VERSION 5.8 ;
BUSBITCHARS "[]" ;
DIVIDERCHAR "/" ;
UNITS
    DATABASE MICRONS 1000 ;
END UNITS

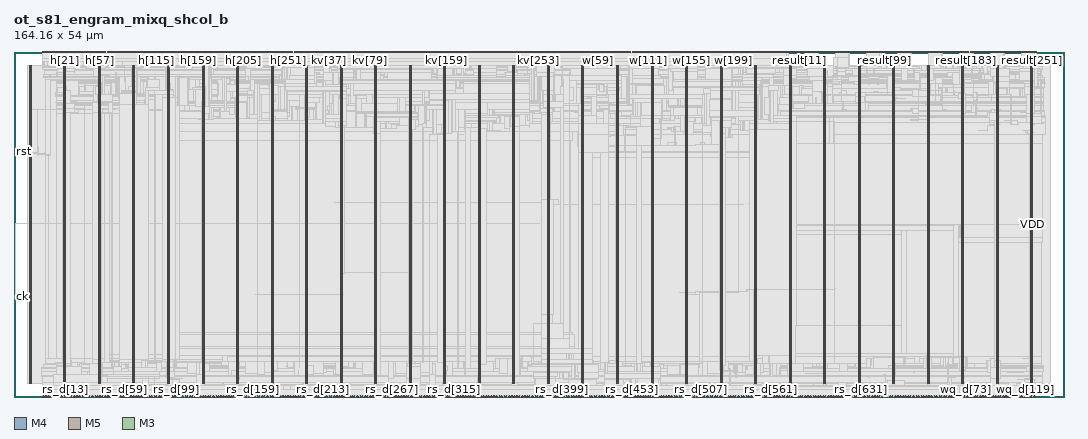
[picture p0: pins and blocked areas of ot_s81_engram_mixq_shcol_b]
MACRO ot_s81_engram_mixq_shcol_b
  FOREIGN ot_s81_engram_mixq_shcol_b 0 0 ;
  CLASS BLOCK ;
  SIZE 164.16 BY 54 ;
  PIN ck
    DIRECTION INPUT ;
    USE SIGNAL ;
    PORT
      LAYER M4 ;
        RECT  0 15.696 0.192 15.72 ;
    END
  END ck
  PIN h[0]
    DIRECTION OUTPUT ;
    USE SIGNAL ;
    PORT
      LAYER M5 ;
        RECT  4.848 53.808 4.872 54 ;
    END
  END h[0]
  PIN h[100]
    DIRECTION OUTPUT ;
    USE SIGNAL ;
    PORT
      LAYER M5 ;
        RECT  19.968 53.808 19.992 54 ;
    END
  END h[100]
  PIN h[101]
    DIRECTION OUTPUT ;
    USE SIGNAL ;
    PORT
      LAYER M3 ;
        RECT  20.124 53.856 20.142 54 ;
    END
  END h[101]
  PIN h[102]
    DIRECTION OUTPUT ;
    USE SIGNAL ;
    PORT
      LAYER M5 ;
        RECT  20.304 53.808 20.328 54 ;
    END
  END h[102]
  PIN h[103]
    DIRECTION OUTPUT ;
    USE SIGNAL ;
    PORT
      LAYER M3 ;
        RECT  20.448 53.856 20.466 54 ;
    END
  END h[103]
  PIN h[104]
    DIRECTION OUTPUT ;
    USE SIGNAL ;
    PORT
      LAYER M5 ;
        RECT  20.592 53.808 20.616 54 ;
    END
  END h[104]
  PIN h[105]
    DIRECTION OUTPUT ;
    USE SIGNAL ;
    PORT
      LAYER M3 ;
        RECT  20.736 53.856 20.754 54 ;
    END
  END h[105]
  PIN h[106]
    DIRECTION OUTPUT ;
    USE SIGNAL ;
    PORT
      LAYER M5 ;
        RECT  20.88 53.808 20.904 54 ;
    END
  END h[106]
  PIN h[107]
    DIRECTION OUTPUT ;
    USE SIGNAL ;
    PORT
      LAYER M3 ;
        RECT  21.06 53.856 21.078 54 ;
    END
  END h[107]
  PIN h[108]
    DIRECTION OUTPUT ;
    USE SIGNAL ;
    PORT
      LAYER M5 ;
        RECT  21.216 53.808 21.24 54 ;
    END
  END h[108]
  PIN h[109]
    DIRECTION OUTPUT ;
    USE SIGNAL ;
    PORT
      LAYER M3 ;
        RECT  21.348 53.856 21.366 54 ;
    END
  END h[109]
  PIN h[10]
    DIRECTION OUTPUT ;
    USE SIGNAL ;
    PORT
      LAYER M5 ;
        RECT  6.336 53.808 6.36 54 ;
    END
  END h[10]
  PIN h[110]
    DIRECTION OUTPUT ;
    USE SIGNAL ;
    PORT
      LAYER M5 ;
        RECT  21.504 53.808 21.528 54 ;
    END
  END h[110]
  PIN h[111]
    DIRECTION OUTPUT ;
    USE SIGNAL ;
    PORT
      LAYER M3 ;
        RECT  21.636 53.856 21.654 54 ;
    END
  END h[111]
  PIN h[112]
    DIRECTION OUTPUT ;
    USE SIGNAL ;
    PORT
      LAYER M5 ;
        RECT  21.792 53.808 21.816 54 ;
    END
  END h[112]
  PIN h[113]
    DIRECTION OUTPUT ;
    USE SIGNAL ;
    PORT
      LAYER M3 ;
        RECT  21.96 53.856 21.978 54 ;
    END
  END h[113]
  PIN h[114]
    DIRECTION OUTPUT ;
    USE SIGNAL ;
    PORT
      LAYER M5 ;
        RECT  22.08 53.808 22.104 54 ;
    END
  END h[114]
  PIN h[115]
    DIRECTION OUTPUT ;
    USE SIGNAL ;
    PORT
      LAYER M3 ;
        RECT  22.248 53.856 22.266 54 ;
    END
  END h[115]
  PIN h[116]
    DIRECTION OUTPUT ;
    USE SIGNAL ;
    PORT
      LAYER M5 ;
        RECT  22.416 53.808 22.44 54 ;
    END
  END h[116]
  PIN h[117]
    DIRECTION OUTPUT ;
    USE SIGNAL ;
    PORT
      LAYER M3 ;
        RECT  22.572 53.856 22.59 54 ;
    END
  END h[117]
  PIN h[118]
    DIRECTION OUTPUT ;
    USE SIGNAL ;
    PORT
      LAYER M5 ;
        RECT  22.704 53.808 22.728 54 ;
    END
  END h[118]
  PIN h[119]
    DIRECTION OUTPUT ;
    USE SIGNAL ;
    PORT
      LAYER M3 ;
        RECT  22.86 53.856 22.878 54 ;
    END
  END h[119]
  PIN h[11]
    DIRECTION OUTPUT ;
    USE SIGNAL ;
    PORT
      LAYER M3 ;
        RECT  6.516 53.856 6.534 54 ;
    END
  END h[11]
  PIN h[120]
    DIRECTION OUTPUT ;
    USE SIGNAL ;
    PORT
      LAYER M5 ;
        RECT  22.992 53.808 23.016 54 ;
    END
  END h[120]
  PIN h[121]
    DIRECTION OUTPUT ;
    USE SIGNAL ;
    PORT
      LAYER M3 ;
        RECT  23.148 53.856 23.166 54 ;
    END
  END h[121]
  PIN h[122]
    DIRECTION OUTPUT ;
    USE SIGNAL ;
    PORT
      LAYER M5 ;
        RECT  23.328 53.808 23.352 54 ;
    END
  END h[122]
  PIN h[123]
    DIRECTION OUTPUT ;
    USE SIGNAL ;
    PORT
      LAYER M3 ;
        RECT  23.472 53.856 23.49 54 ;
    END
  END h[123]
  PIN h[124]
    DIRECTION OUTPUT ;
    USE SIGNAL ;
    PORT
      LAYER M5 ;
        RECT  23.616 53.808 23.64 54 ;
    END
  END h[124]
  PIN h[125]
    DIRECTION OUTPUT ;
    USE SIGNAL ;
    PORT
      LAYER M3 ;
        RECT  23.76 53.856 23.778 54 ;
    END
  END h[125]
  PIN h[126]
    DIRECTION OUTPUT ;
    USE SIGNAL ;
    PORT
      LAYER M5 ;
        RECT  23.904 53.808 23.928 54 ;
    END
  END h[126]
  PIN h[127]
    DIRECTION OUTPUT ;
    USE SIGNAL ;
    PORT
      LAYER M3 ;
        RECT  24.084 53.856 24.102 54 ;
    END
  END h[127]
  PIN h[128]
    DIRECTION OUTPUT ;
    USE SIGNAL ;
    PORT
      LAYER M5 ;
        RECT  24.24 53.808 24.264 54 ;
    END
  END h[128]
  PIN h[129]
    DIRECTION OUTPUT ;
    USE SIGNAL ;
    PORT
      LAYER M3 ;
        RECT  24.372 53.856 24.39 54 ;
    END
  END h[129]
  PIN h[12]
    DIRECTION OUTPUT ;
    USE SIGNAL ;
    PORT
      LAYER M5 ;
        RECT  6.672 53.808 6.696 54 ;
    END
  END h[12]
  PIN h[130]
    DIRECTION OUTPUT ;
    USE SIGNAL ;
    PORT
      LAYER M5 ;
        RECT  24.528 53.808 24.552 54 ;
    END
  END h[130]
  PIN h[131]
    DIRECTION OUTPUT ;
    USE SIGNAL ;
    PORT
      LAYER M3 ;
        RECT  24.696 53.856 24.714 54 ;
    END
  END h[131]
  PIN h[132]
    DIRECTION OUTPUT ;
    USE SIGNAL ;
    PORT
      LAYER M5 ;
        RECT  24.816 53.808 24.84 54 ;
    END
  END h[132]
  PIN h[133]
    DIRECTION OUTPUT ;
    USE SIGNAL ;
    PORT
      LAYER M3 ;
        RECT  24.984 53.856 25.002 54 ;
    END
  END h[133]
  PIN h[134]
    DIRECTION OUTPUT ;
    USE SIGNAL ;
    PORT
      LAYER M5 ;
        RECT  25.152 53.808 25.176 54 ;
    END
  END h[134]
  PIN h[135]
    DIRECTION OUTPUT ;
    USE SIGNAL ;
    PORT
      LAYER M3 ;
        RECT  25.272 53.856 25.29 54 ;
    END
  END h[135]
  PIN h[136]
    DIRECTION OUTPUT ;
    USE SIGNAL ;
    PORT
      LAYER M5 ;
        RECT  25.44 53.808 25.464 54 ;
    END
  END h[136]
  PIN h[137]
    DIRECTION OUTPUT ;
    USE SIGNAL ;
    PORT
      LAYER M3 ;
        RECT  25.596 53.856 25.614 54 ;
    END
  END h[137]
  PIN h[138]
    DIRECTION OUTPUT ;
    USE SIGNAL ;
    PORT
      LAYER M5 ;
        RECT  25.728 53.808 25.752 54 ;
    END
  END h[138]
  PIN h[139]
    DIRECTION OUTPUT ;
    USE SIGNAL ;
    PORT
      LAYER M3 ;
        RECT  25.884 53.856 25.902 54 ;
    END
  END h[139]
  PIN h[13]
    DIRECTION OUTPUT ;
    USE SIGNAL ;
    PORT
      LAYER M3 ;
        RECT  6.804 53.856 6.822 54 ;
    END
  END h[13]
  PIN h[140]
    DIRECTION OUTPUT ;
    USE SIGNAL ;
    PORT
      LAYER M5 ;
        RECT  26.016 53.808 26.04 54 ;
    END
  END h[140]
  PIN h[141]
    DIRECTION OUTPUT ;
    USE SIGNAL ;
    PORT
      LAYER M3 ;
        RECT  26.208 53.856 26.226 54 ;
    END
  END h[141]
  PIN h[142]
    DIRECTION OUTPUT ;
    USE SIGNAL ;
    PORT
      LAYER M5 ;
        RECT  26.352 53.808 26.376 54 ;
    END
  END h[142]
  PIN h[143]
    DIRECTION OUTPUT ;
    USE SIGNAL ;
    PORT
      LAYER M3 ;
        RECT  26.496 53.856 26.514 54 ;
    END
  END h[143]
  PIN h[144]
    DIRECTION OUTPUT ;
    USE SIGNAL ;
    PORT
      LAYER M5 ;
        RECT  26.64 53.808 26.664 54 ;
    END
  END h[144]
  PIN h[145]
    DIRECTION OUTPUT ;
    USE SIGNAL ;
    PORT
      LAYER M3 ;
        RECT  26.784 53.856 26.802 54 ;
    END
  END h[145]
  PIN h[146]
    DIRECTION OUTPUT ;
    USE SIGNAL ;
    PORT
      LAYER M5 ;
        RECT  26.928 53.808 26.952 54 ;
    END
  END h[146]
  PIN h[147]
    DIRECTION OUTPUT ;
    USE SIGNAL ;
    PORT
      LAYER M3 ;
        RECT  27.108 53.856 27.126 54 ;
    END
  END h[147]
  PIN h[148]
    DIRECTION OUTPUT ;
    USE SIGNAL ;
    PORT
      LAYER M5 ;
        RECT  27.264 53.808 27.288 54 ;
    END
  END h[148]
  PIN h[149]
    DIRECTION OUTPUT ;
    USE SIGNAL ;
    PORT
      LAYER M3 ;
        RECT  27.396 53.856 27.414 54 ;
    END
  END h[149]
  PIN h[14]
    DIRECTION OUTPUT ;
    USE SIGNAL ;
    PORT
      LAYER M5 ;
        RECT  6.96 53.808 6.984 54 ;
    END
  END h[14]
  PIN h[150]
    DIRECTION OUTPUT ;
    USE SIGNAL ;
    PORT
      LAYER M5 ;
        RECT  27.552 53.808 27.576 54 ;
    END
  END h[150]
  PIN h[151]
    DIRECTION OUTPUT ;
    USE SIGNAL ;
    PORT
      LAYER M3 ;
        RECT  27.72 53.856 27.738 54 ;
    END
  END h[151]
  PIN h[152]
    DIRECTION OUTPUT ;
    USE SIGNAL ;
    PORT
      LAYER M5 ;
        RECT  27.84 53.808 27.864 54 ;
    END
  END h[152]
  PIN h[153]
    DIRECTION OUTPUT ;
    USE SIGNAL ;
    PORT
      LAYER M3 ;
        RECT  28.008 53.856 28.026 54 ;
    END
  END h[153]
  PIN h[154]
    DIRECTION OUTPUT ;
    USE SIGNAL ;
    PORT
      LAYER M5 ;
        RECT  28.176 53.808 28.2 54 ;
    END
  END h[154]
  PIN h[155]
    DIRECTION OUTPUT ;
    USE SIGNAL ;
    PORT
      LAYER M3 ;
        RECT  28.296 53.856 28.314 54 ;
    END
  END h[155]
  PIN h[156]
    DIRECTION OUTPUT ;
    USE SIGNAL ;
    PORT
      LAYER M5 ;
        RECT  28.464 53.808 28.488 54 ;
    END
  END h[156]
  PIN h[157]
    DIRECTION OUTPUT ;
    USE SIGNAL ;
    PORT
      LAYER M3 ;
        RECT  28.62 53.856 28.638 54 ;
    END
  END h[157]
  PIN h[158]
    DIRECTION OUTPUT ;
    USE SIGNAL ;
    PORT
      LAYER M5 ;
        RECT  28.752 53.808 28.776 54 ;
    END
  END h[158]
  PIN h[159]
    DIRECTION OUTPUT ;
    USE SIGNAL ;
    PORT
      LAYER M3 ;
        RECT  28.908 53.856 28.926 54 ;
    END
  END h[159]
  PIN h[15]
    DIRECTION OUTPUT ;
    USE SIGNAL ;
    PORT
      LAYER M3 ;
        RECT  7.128 53.856 7.146 54 ;
    END
  END h[15]
  PIN h[160]
    DIRECTION OUTPUT ;
    USE SIGNAL ;
    PORT
      LAYER M5 ;
        RECT  29.088 53.808 29.112 54 ;
    END
  END h[160]
  PIN h[161]
    DIRECTION OUTPUT ;
    USE SIGNAL ;
    PORT
      LAYER M3 ;
        RECT  29.232 53.856 29.25 54 ;
    END
  END h[161]
  PIN h[162]
    DIRECTION OUTPUT ;
    USE SIGNAL ;
    PORT
      LAYER M5 ;
        RECT  29.376 53.808 29.4 54 ;
    END
  END h[162]
  PIN h[163]
    DIRECTION OUTPUT ;
    USE SIGNAL ;
    PORT
      LAYER M3 ;
        RECT  29.52 53.856 29.538 54 ;
    END
  END h[163]
  PIN h[164]
    DIRECTION OUTPUT ;
    USE SIGNAL ;
    PORT
      LAYER M5 ;
        RECT  29.664 53.808 29.688 54 ;
    END
  END h[164]
  PIN h[165]
    DIRECTION OUTPUT ;
    USE SIGNAL ;
    PORT
      LAYER M3 ;
        RECT  29.844 53.856 29.862 54 ;
    END
  END h[165]
  PIN h[166]
    DIRECTION OUTPUT ;
    USE SIGNAL ;
    PORT
      LAYER M5 ;
        RECT  29.952 53.808 29.976 54 ;
    END
  END h[166]
  PIN h[167]
    DIRECTION OUTPUT ;
    USE SIGNAL ;
    PORT
      LAYER M3 ;
        RECT  30.132 53.856 30.15 54 ;
    END
  END h[167]
  PIN h[168]
    DIRECTION OUTPUT ;
    USE SIGNAL ;
    PORT
      LAYER M5 ;
        RECT  30.288 53.808 30.312 54 ;
    END
  END h[168]
  PIN h[169]
    DIRECTION OUTPUT ;
    USE SIGNAL ;
    PORT
      LAYER M3 ;
        RECT  30.42 53.856 30.438 54 ;
    END
  END h[169]
  PIN h[16]
    DIRECTION OUTPUT ;
    USE SIGNAL ;
    PORT
      LAYER M5 ;
        RECT  7.248 53.808 7.272 54 ;
    END
  END h[16]
  PIN h[170]
    DIRECTION OUTPUT ;
    USE SIGNAL ;
    PORT
      LAYER M5 ;
        RECT  30.576 53.808 30.6 54 ;
    END
  END h[170]
  PIN h[171]
    DIRECTION OUTPUT ;
    USE SIGNAL ;
    PORT
      LAYER M3 ;
        RECT  30.744 53.856 30.762 54 ;
    END
  END h[171]
  PIN h[172]
    DIRECTION OUTPUT ;
    USE SIGNAL ;
    PORT
      LAYER M5 ;
        RECT  30.864 53.808 30.888 54 ;
    END
  END h[172]
  PIN h[173]
    DIRECTION OUTPUT ;
    USE SIGNAL ;
    PORT
      LAYER M3 ;
        RECT  31.032 53.856 31.05 54 ;
    END
  END h[173]
  PIN h[174]
    DIRECTION OUTPUT ;
    USE SIGNAL ;
    PORT
      LAYER M5 ;
        RECT  31.2 53.808 31.224 54 ;
    END
  END h[174]
  PIN h[175]
    DIRECTION OUTPUT ;
    USE SIGNAL ;
    PORT
      LAYER M3 ;
        RECT  31.356 53.856 31.374 54 ;
    END
  END h[175]
  PIN h[176]
    DIRECTION OUTPUT ;
    USE SIGNAL ;
    PORT
      LAYER M5 ;
        RECT  31.488 53.808 31.512 54 ;
    END
  END h[176]
  PIN h[177]
    DIRECTION OUTPUT ;
    USE SIGNAL ;
    PORT
      LAYER M3 ;
        RECT  31.644 53.856 31.662 54 ;
    END
  END h[177]
  PIN h[178]
    DIRECTION OUTPUT ;
    USE SIGNAL ;
    PORT
      LAYER M5 ;
        RECT  31.776 53.808 31.8 54 ;
    END
  END h[178]
  PIN h[179]
    DIRECTION OUTPUT ;
    USE SIGNAL ;
    PORT
      LAYER M3 ;
        RECT  31.932 53.856 31.95 54 ;
    END
  END h[179]
  PIN h[17]
    DIRECTION OUTPUT ;
    USE SIGNAL ;
    PORT
      LAYER M3 ;
        RECT  7.416 53.856 7.434 54 ;
    END
  END h[17]
  PIN h[180]
    DIRECTION OUTPUT ;
    USE SIGNAL ;
    PORT
      LAYER M5 ;
        RECT  32.112 53.808 32.136 54 ;
    END
  END h[180]
  PIN h[181]
    DIRECTION OUTPUT ;
    USE SIGNAL ;
    PORT
      LAYER M3 ;
        RECT  32.256 53.856 32.274 54 ;
    END
  END h[181]
  PIN h[182]
    DIRECTION OUTPUT ;
    USE SIGNAL ;
    PORT
      LAYER M5 ;
        RECT  32.4 53.808 32.424 54 ;
    END
  END h[182]
  PIN h[183]
    DIRECTION OUTPUT ;
    USE SIGNAL ;
    PORT
      LAYER M3 ;
        RECT  32.544 53.856 32.562 54 ;
    END
  END h[183]
  PIN h[184]
    DIRECTION OUTPUT ;
    USE SIGNAL ;
    PORT
      LAYER M5 ;
        RECT  32.688 53.808 32.712 54 ;
    END
  END h[184]
  PIN h[185]
    DIRECTION OUTPUT ;
    USE SIGNAL ;
    PORT
      LAYER M3 ;
        RECT  32.868 53.856 32.886 54 ;
    END
  END h[185]
  PIN h[186]
    DIRECTION OUTPUT ;
    USE SIGNAL ;
    PORT
      LAYER M5 ;
        RECT  33.024 53.808 33.048 54 ;
    END
  END h[186]
  PIN h[187]
    DIRECTION OUTPUT ;
    USE SIGNAL ;
    PORT
      LAYER M3 ;
        RECT  33.156 53.856 33.174 54 ;
    END
  END h[187]
  PIN h[188]
    DIRECTION OUTPUT ;
    USE SIGNAL ;
    PORT
      LAYER M5 ;
        RECT  33.312 53.808 33.336 54 ;
    END
  END h[188]
  PIN h[189]
    DIRECTION OUTPUT ;
    USE SIGNAL ;
    PORT
      LAYER M3 ;
        RECT  33.444 53.856 33.462 54 ;
    END
  END h[189]
  PIN h[18]
    DIRECTION OUTPUT ;
    USE SIGNAL ;
    PORT
      LAYER M5 ;
        RECT  7.584 53.808 7.608 54 ;
    END
  END h[18]
  PIN h[190]
    DIRECTION OUTPUT ;
    USE SIGNAL ;
    PORT
      LAYER M5 ;
        RECT  33.6 53.808 33.624 54 ;
    END
  END h[190]
  PIN h[191]
    DIRECTION OUTPUT ;
    USE SIGNAL ;
    PORT
      LAYER M3 ;
        RECT  33.768 53.856 33.786 54 ;
    END
  END h[191]
  PIN h[192]
    DIRECTION OUTPUT ;
    USE SIGNAL ;
    PORT
      LAYER M5 ;
        RECT  33.936 53.808 33.96 54 ;
    END
  END h[192]
  PIN h[193]
    DIRECTION OUTPUT ;
    USE SIGNAL ;
    PORT
      LAYER M3 ;
        RECT  34.056 53.856 34.074 54 ;
    END
  END h[193]
  PIN h[194]
    DIRECTION OUTPUT ;
    USE SIGNAL ;
    PORT
      LAYER M5 ;
        RECT  34.224 53.808 34.248 54 ;
    END
  END h[194]
  PIN h[195]
    DIRECTION OUTPUT ;
    USE SIGNAL ;
    PORT
      LAYER M3 ;
        RECT  34.38 53.856 34.398 54 ;
    END
  END h[195]
  PIN h[196]
    DIRECTION OUTPUT ;
    USE SIGNAL ;
    PORT
      LAYER M5 ;
        RECT  34.512 53.808 34.536 54 ;
    END
  END h[196]
  PIN h[197]
    DIRECTION OUTPUT ;
    USE SIGNAL ;
    PORT
      LAYER M3 ;
        RECT  34.668 53.856 34.686 54 ;
    END
  END h[197]
  PIN h[198]
    DIRECTION OUTPUT ;
    USE SIGNAL ;
    PORT
      LAYER M5 ;
        RECT  34.8 53.808 34.824 54 ;
    END
  END h[198]
  PIN h[199]
    DIRECTION OUTPUT ;
    USE SIGNAL ;
    PORT
      LAYER M3 ;
        RECT  34.992 53.856 35.01 54 ;
    END
  END h[199]
  PIN h[19]
    DIRECTION OUTPUT ;
    USE SIGNAL ;
    PORT
      LAYER M3 ;
        RECT  7.704 53.856 7.722 54 ;
    END
  END h[19]
  PIN h[1]
    DIRECTION OUTPUT ;
    USE SIGNAL ;
    PORT
      LAYER M3 ;
        RECT  5.004 53.856 5.022 54 ;
    END
  END h[1]
  PIN h[200]
    DIRECTION OUTPUT ;
    USE SIGNAL ;
    PORT
      LAYER M5 ;
        RECT  35.136 53.808 35.16 54 ;
    END
  END h[200]
  PIN h[201]
    DIRECTION OUTPUT ;
    USE SIGNAL ;
    PORT
      LAYER M3 ;
        RECT  35.28 53.856 35.298 54 ;
    END
  END h[201]
  PIN h[202]
    DIRECTION OUTPUT ;
    USE SIGNAL ;
    PORT
      LAYER M5 ;
        RECT  35.424 53.808 35.448 54 ;
    END
  END h[202]
  PIN h[203]
    DIRECTION OUTPUT ;
    USE SIGNAL ;
    PORT
      LAYER M3 ;
        RECT  35.568 53.856 35.586 54 ;
    END
  END h[203]
  PIN h[204]
    DIRECTION OUTPUT ;
    USE SIGNAL ;
    PORT
      LAYER M5 ;
        RECT  35.712 53.808 35.736 54 ;
    END
  END h[204]
  PIN h[205]
    DIRECTION OUTPUT ;
    USE SIGNAL ;
    PORT
      LAYER M3 ;
        RECT  35.892 53.856 35.91 54 ;
    END
  END h[205]
  PIN h[206]
    DIRECTION OUTPUT ;
    USE SIGNAL ;
    PORT
      LAYER M5 ;
        RECT  36.048 53.808 36.072 54 ;
    END
  END h[206]
  PIN h[207]
    DIRECTION OUTPUT ;
    USE SIGNAL ;
    PORT
      LAYER M3 ;
        RECT  36.18 53.856 36.198 54 ;
    END
  END h[207]
  PIN h[208]
    DIRECTION OUTPUT ;
    USE SIGNAL ;
    PORT
      LAYER M5 ;
        RECT  36.336 53.808 36.36 54 ;
    END
  END h[208]
  PIN h[209]
    DIRECTION OUTPUT ;
    USE SIGNAL ;
    PORT
      LAYER M3 ;
        RECT  36.504 53.856 36.522 54 ;
    END
  END h[209]
  PIN h[20]
    DIRECTION OUTPUT ;
    USE SIGNAL ;
    PORT
      LAYER M5 ;
        RECT  7.872 53.808 7.896 54 ;
    END
  END h[20]
  PIN h[210]
    DIRECTION OUTPUT ;
    USE SIGNAL ;
    PORT
      LAYER M5 ;
        RECT  36.624 53.808 36.648 54 ;
    END
  END h[210]
  PIN h[211]
    DIRECTION OUTPUT ;
    USE SIGNAL ;
    PORT
      LAYER M3 ;
        RECT  36.792 53.856 36.81 54 ;
    END
  END h[211]
  PIN h[212]
    DIRECTION OUTPUT ;
    USE SIGNAL ;
    PORT
      LAYER M5 ;
        RECT  36.96 53.808 36.984 54 ;
    END
  END h[212]
  PIN h[213]
    DIRECTION OUTPUT ;
    USE SIGNAL ;
    PORT
      LAYER M3 ;
        RECT  37.08 53.856 37.098 54 ;
    END
  END h[213]
  PIN h[214]
    DIRECTION OUTPUT ;
    USE SIGNAL ;
    PORT
      LAYER M5 ;
        RECT  37.248 53.808 37.272 54 ;
    END
  END h[214]
  PIN h[215]
    DIRECTION OUTPUT ;
    USE SIGNAL ;
    PORT
      LAYER M3 ;
        RECT  37.404 53.856 37.422 54 ;
    END
  END h[215]
  PIN h[216]
    DIRECTION OUTPUT ;
    USE SIGNAL ;
    PORT
      LAYER M5 ;
        RECT  37.536 53.808 37.56 54 ;
    END
  END h[216]
  PIN h[217]
    DIRECTION OUTPUT ;
    USE SIGNAL ;
    PORT
      LAYER M3 ;
        RECT  37.692 53.856 37.71 54 ;
    END
  END h[217]
  PIN h[218]
    DIRECTION OUTPUT ;
    USE SIGNAL ;
    PORT
      LAYER M5 ;
        RECT  37.872 53.808 37.896 54 ;
    END
  END h[218]
  PIN h[219]
    DIRECTION OUTPUT ;
    USE SIGNAL ;
    PORT
      LAYER M3 ;
        RECT  38.016 53.856 38.034 54 ;
    END
  END h[219]
  PIN h[21]
    DIRECTION OUTPUT ;
    USE SIGNAL ;
    PORT
      LAYER M3 ;
        RECT  8.028 53.856 8.046 54 ;
    END
  END h[21]
  PIN h[220]
    DIRECTION OUTPUT ;
    USE SIGNAL ;
    PORT
      LAYER M5 ;
        RECT  38.16 53.808 38.184 54 ;
    END
  END h[220]
  PIN h[221]
    DIRECTION OUTPUT ;
    USE SIGNAL ;
    PORT
      LAYER M3 ;
        RECT  38.304 53.856 38.322 54 ;
    END
  END h[221]
  PIN h[222]
    DIRECTION OUTPUT ;
    USE SIGNAL ;
    PORT
      LAYER M5 ;
        RECT  38.448 53.808 38.472 54 ;
    END
  END h[222]
  PIN h[223]
    DIRECTION OUTPUT ;
    USE SIGNAL ;
    PORT
      LAYER M3 ;
        RECT  38.628 53.856 38.646 54 ;
    END
  END h[223]
  PIN h[224]
    DIRECTION OUTPUT ;
    USE SIGNAL ;
    PORT
      LAYER M5 ;
        RECT  38.736 53.808 38.76 54 ;
    END
  END h[224]
  PIN h[225]
    DIRECTION OUTPUT ;
    USE SIGNAL ;
    PORT
      LAYER M3 ;
        RECT  38.916 53.856 38.934 54 ;
    END
  END h[225]
  PIN h[226]
    DIRECTION OUTPUT ;
    USE SIGNAL ;
    PORT
      LAYER M5 ;
        RECT  39.072 53.808 39.096 54 ;
    END
  END h[226]
  PIN h[227]
    DIRECTION OUTPUT ;
    USE SIGNAL ;
    PORT
      LAYER M3 ;
        RECT  39.204 53.856 39.222 54 ;
    END
  END h[227]
  PIN h[228]
    DIRECTION OUTPUT ;
    USE SIGNAL ;
    PORT
      LAYER M5 ;
        RECT  39.36 53.808 39.384 54 ;
    END
  END h[228]
  PIN h[229]
    DIRECTION OUTPUT ;
    USE SIGNAL ;
    PORT
      LAYER M3 ;
        RECT  39.528 53.856 39.546 54 ;
    END
  END h[229]
  PIN h[22]
    DIRECTION OUTPUT ;
    USE SIGNAL ;
    PORT
      LAYER M5 ;
        RECT  8.16 53.808 8.184 54 ;
    END
  END h[22]
  PIN h[230]
    DIRECTION OUTPUT ;
    USE SIGNAL ;
    PORT
      LAYER M5 ;
        RECT  39.648 53.808 39.672 54 ;
    END
  END h[230]
  PIN h[231]
    DIRECTION OUTPUT ;
    USE SIGNAL ;
    PORT
      LAYER M3 ;
        RECT  39.816 53.856 39.834 54 ;
    END
  END h[231]
  PIN h[232]
    DIRECTION OUTPUT ;
    USE SIGNAL ;
    PORT
      LAYER M5 ;
        RECT  39.984 53.808 40.008 54 ;
    END
  END h[232]
  PIN h[233]
    DIRECTION OUTPUT ;
    USE SIGNAL ;
    PORT
      LAYER M3 ;
        RECT  40.14 53.856 40.158 54 ;
    END
  END h[233]
  PIN h[234]
    DIRECTION OUTPUT ;
    USE SIGNAL ;
    PORT
      LAYER M5 ;
        RECT  40.272 53.808 40.296 54 ;
    END
  END h[234]
  PIN h[235]
    DIRECTION OUTPUT ;
    USE SIGNAL ;
    PORT
      LAYER M3 ;
        RECT  40.428 53.856 40.446 54 ;
    END
  END h[235]
  PIN h[236]
    DIRECTION OUTPUT ;
    USE SIGNAL ;
    PORT
      LAYER M5 ;
        RECT  40.56 53.808 40.584 54 ;
    END
  END h[236]
  PIN h[237]
    DIRECTION OUTPUT ;
    USE SIGNAL ;
    PORT
      LAYER M3 ;
        RECT  40.716 53.856 40.734 54 ;
    END
  END h[237]
  PIN h[238]
    DIRECTION OUTPUT ;
    USE SIGNAL ;
    PORT
      LAYER M5 ;
        RECT  40.896 53.808 40.92 54 ;
    END
  END h[238]
  PIN h[239]
    DIRECTION OUTPUT ;
    USE SIGNAL ;
    PORT
      LAYER M3 ;
        RECT  41.04 53.856 41.058 54 ;
    END
  END h[239]
  PIN h[23]
    DIRECTION OUTPUT ;
    USE SIGNAL ;
    PORT
      LAYER M3 ;
        RECT  8.316 53.856 8.334 54 ;
    END
  END h[23]
  PIN h[240]
    DIRECTION OUTPUT ;
    USE SIGNAL ;
    PORT
      LAYER M5 ;
        RECT  41.184 53.808 41.208 54 ;
    END
  END h[240]
  PIN h[241]
    DIRECTION OUTPUT ;
    USE SIGNAL ;
    PORT
      LAYER M3 ;
        RECT  41.328 53.856 41.346 54 ;
    END
  END h[241]
  PIN h[242]
    DIRECTION OUTPUT ;
    USE SIGNAL ;
    PORT
      LAYER M5 ;
        RECT  41.472 53.808 41.496 54 ;
    END
  END h[242]
  PIN h[243]
    DIRECTION OUTPUT ;
    USE SIGNAL ;
    PORT
      LAYER M3 ;
        RECT  41.652 53.856 41.67 54 ;
    END
  END h[243]
  PIN h[244]
    DIRECTION OUTPUT ;
    USE SIGNAL ;
    PORT
      LAYER M5 ;
        RECT  41.808 53.808 41.832 54 ;
    END
  END h[244]
  PIN h[245]
    DIRECTION OUTPUT ;
    USE SIGNAL ;
    PORT
      LAYER M3 ;
        RECT  41.94 53.856 41.958 54 ;
    END
  END h[245]
  PIN h[246]
    DIRECTION OUTPUT ;
    USE SIGNAL ;
    PORT
      LAYER M5 ;
        RECT  42.096 53.808 42.12 54 ;
    END
  END h[246]
  PIN h[247]
    DIRECTION OUTPUT ;
    USE SIGNAL ;
    PORT
      LAYER M3 ;
        RECT  42.228 53.856 42.246 54 ;
    END
  END h[247]
  PIN h[248]
    DIRECTION OUTPUT ;
    USE SIGNAL ;
    PORT
      LAYER M5 ;
        RECT  42.384 53.808 42.408 54 ;
    END
  END h[248]
  PIN h[249]
    DIRECTION OUTPUT ;
    USE SIGNAL ;
    PORT
      LAYER M3 ;
        RECT  42.552 53.856 42.57 54 ;
    END
  END h[249]
  PIN h[24]
    DIRECTION OUTPUT ;
    USE SIGNAL ;
    PORT
      LAYER M5 ;
        RECT  8.496 53.808 8.52 54 ;
    END
  END h[24]
  PIN h[250]
    DIRECTION OUTPUT ;
    USE SIGNAL ;
    PORT
      LAYER M5 ;
        RECT  42.672 53.808 42.696 54 ;
    END
  END h[250]
  PIN h[251]
    DIRECTION OUTPUT ;
    USE SIGNAL ;
    PORT
      LAYER M3 ;
        RECT  42.84 53.856 42.858 54 ;
    END
  END h[251]
  PIN h[252]
    DIRECTION OUTPUT ;
    USE SIGNAL ;
    PORT
      LAYER M5 ;
        RECT  43.008 53.808 43.032 54 ;
    END
  END h[252]
  PIN h[253]
    DIRECTION OUTPUT ;
    USE SIGNAL ;
    PORT
      LAYER M3 ;
        RECT  43.164 53.856 43.182 54 ;
    END
  END h[253]
  PIN h[254]
    DIRECTION OUTPUT ;
    USE SIGNAL ;
    PORT
      LAYER M5 ;
        RECT  43.296 53.808 43.32 54 ;
    END
  END h[254]
  PIN h[255]
    DIRECTION OUTPUT ;
    USE SIGNAL ;
    PORT
      LAYER M3 ;
        RECT  43.452 53.856 43.47 54 ;
    END
  END h[255]
  PIN h[25]
    DIRECTION OUTPUT ;
    USE SIGNAL ;
    PORT
      LAYER M3 ;
        RECT  8.64 53.856 8.658 54 ;
    END
  END h[25]
  PIN h[26]
    DIRECTION OUTPUT ;
    USE SIGNAL ;
    PORT
      LAYER M5 ;
        RECT  8.784 53.808 8.808 54 ;
    END
  END h[26]
  PIN h[27]
    DIRECTION OUTPUT ;
    USE SIGNAL ;
    PORT
      LAYER M3 ;
        RECT  8.928 53.856 8.946 54 ;
    END
  END h[27]
  PIN h[28]
    DIRECTION OUTPUT ;
    USE SIGNAL ;
    PORT
      LAYER M5 ;
        RECT  9.072 53.808 9.096 54 ;
    END
  END h[28]
  PIN h[29]
    DIRECTION OUTPUT ;
    USE SIGNAL ;
    PORT
      LAYER M3 ;
        RECT  9.216 53.856 9.234 54 ;
    END
  END h[29]
  PIN h[2]
    DIRECTION OUTPUT ;
    USE SIGNAL ;
    PORT
      LAYER M5 ;
        RECT  5.136 53.808 5.16 54 ;
    END
  END h[2]
  PIN h[30]
    DIRECTION OUTPUT ;
    USE SIGNAL ;
    PORT
      LAYER M5 ;
        RECT  9.36 53.808 9.384 54 ;
    END
  END h[30]
  PIN h[31]
    DIRECTION OUTPUT ;
    USE SIGNAL ;
    PORT
      LAYER M3 ;
        RECT  9.54 53.856 9.558 54 ;
    END
  END h[31]
  PIN h[32]
    DIRECTION OUTPUT ;
    USE SIGNAL ;
    PORT
      LAYER M5 ;
        RECT  9.696 53.808 9.72 54 ;
    END
  END h[32]
  PIN h[33]
    DIRECTION OUTPUT ;
    USE SIGNAL ;
    PORT
      LAYER M3 ;
        RECT  9.828 53.856 9.846 54 ;
    END
  END h[33]
  PIN h[34]
    DIRECTION OUTPUT ;
    USE SIGNAL ;
    PORT
      LAYER M5 ;
        RECT  9.984 53.808 10.008 54 ;
    END
  END h[34]
  PIN h[35]
    DIRECTION OUTPUT ;
    USE SIGNAL ;
    PORT
      LAYER M3 ;
        RECT  10.152 53.856 10.17 54 ;
    END
  END h[35]
  PIN h[36]
    DIRECTION OUTPUT ;
    USE SIGNAL ;
    PORT
      LAYER M5 ;
        RECT  10.272 53.808 10.296 54 ;
    END
  END h[36]
  PIN h[37]
    DIRECTION OUTPUT ;
    USE SIGNAL ;
    PORT
      LAYER M3 ;
        RECT  10.44 53.856 10.458 54 ;
    END
  END h[37]
  PIN h[38]
    DIRECTION OUTPUT ;
    USE SIGNAL ;
    PORT
      LAYER M5 ;
        RECT  10.608 53.808 10.632 54 ;
    END
  END h[38]
  PIN h[39]
    DIRECTION OUTPUT ;
    USE SIGNAL ;
    PORT
      LAYER M3 ;
        RECT  10.764 53.856 10.782 54 ;
    END
  END h[39]
  PIN h[3]
    DIRECTION OUTPUT ;
    USE SIGNAL ;
    PORT
      LAYER M3 ;
        RECT  5.292 53.856 5.31 54 ;
    END
  END h[3]
  PIN h[40]
    DIRECTION OUTPUT ;
    USE SIGNAL ;
    PORT
      LAYER M5 ;
        RECT  10.896 53.808 10.92 54 ;
    END
  END h[40]
  PIN h[41]
    DIRECTION OUTPUT ;
    USE SIGNAL ;
    PORT
      LAYER M3 ;
        RECT  11.052 53.856 11.07 54 ;
    END
  END h[41]
  PIN h[42]
    DIRECTION OUTPUT ;
    USE SIGNAL ;
    PORT
      LAYER M5 ;
        RECT  11.184 53.808 11.208 54 ;
    END
  END h[42]
  PIN h[43]
    DIRECTION OUTPUT ;
    USE SIGNAL ;
    PORT
      LAYER M3 ;
        RECT  11.34 53.856 11.358 54 ;
    END
  END h[43]
  PIN h[44]
    DIRECTION OUTPUT ;
    USE SIGNAL ;
    PORT
      LAYER M5 ;
        RECT  11.52 53.808 11.544 54 ;
    END
  END h[44]
  PIN h[45]
    DIRECTION OUTPUT ;
    USE SIGNAL ;
    PORT
      LAYER M3 ;
        RECT  11.664 53.856 11.682 54 ;
    END
  END h[45]
  PIN h[46]
    DIRECTION OUTPUT ;
    USE SIGNAL ;
    PORT
      LAYER M5 ;
        RECT  11.808 53.808 11.832 54 ;
    END
  END h[46]
  PIN h[47]
    DIRECTION OUTPUT ;
    USE SIGNAL ;
    PORT
      LAYER M3 ;
        RECT  11.952 53.856 11.97 54 ;
    END
  END h[47]
  PIN h[48]
    DIRECTION OUTPUT ;
    USE SIGNAL ;
    PORT
      LAYER M5 ;
        RECT  12.096 53.808 12.12 54 ;
    END
  END h[48]
  PIN h[49]
    DIRECTION OUTPUT ;
    USE SIGNAL ;
    PORT
      LAYER M3 ;
        RECT  12.276 53.856 12.294 54 ;
    END
  END h[49]
  PIN h[4]
    DIRECTION OUTPUT ;
    USE SIGNAL ;
    PORT
      LAYER M5 ;
        RECT  5.424 53.808 5.448 54 ;
    END
  END h[4]
  PIN h[50]
    DIRECTION OUTPUT ;
    USE SIGNAL ;
    PORT
      LAYER M5 ;
        RECT  12.432 53.808 12.456 54 ;
    END
  END h[50]
  PIN h[51]
    DIRECTION OUTPUT ;
    USE SIGNAL ;
    PORT
      LAYER M3 ;
        RECT  12.564 53.856 12.582 54 ;
    END
  END h[51]
  PIN h[52]
    DIRECTION OUTPUT ;
    USE SIGNAL ;
    PORT
      LAYER M5 ;
        RECT  12.72 53.808 12.744 54 ;
    END
  END h[52]
  PIN h[53]
    DIRECTION OUTPUT ;
    USE SIGNAL ;
    PORT
      LAYER M3 ;
        RECT  12.852 53.856 12.87 54 ;
    END
  END h[53]
  PIN h[54]
    DIRECTION OUTPUT ;
    USE SIGNAL ;
    PORT
      LAYER M5 ;
        RECT  13.008 53.808 13.032 54 ;
    END
  END h[54]
  PIN h[55]
    DIRECTION OUTPUT ;
    USE SIGNAL ;
    PORT
      LAYER M3 ;
        RECT  13.176 53.856 13.194 54 ;
    END
  END h[55]
  PIN h[56]
    DIRECTION OUTPUT ;
    USE SIGNAL ;
    PORT
      LAYER M5 ;
        RECT  13.296 53.808 13.32 54 ;
    END
  END h[56]
  PIN h[57]
    DIRECTION OUTPUT ;
    USE SIGNAL ;
    PORT
      LAYER M3 ;
        RECT  13.464 53.856 13.482 54 ;
    END
  END h[57]
  PIN h[58]
    DIRECTION OUTPUT ;
    USE SIGNAL ;
    PORT
      LAYER M5 ;
        RECT  13.632 53.808 13.656 54 ;
    END
  END h[58]
  PIN h[59]
    DIRECTION OUTPUT ;
    USE SIGNAL ;
    PORT
      LAYER M3 ;
        RECT  13.788 53.856 13.806 54 ;
    END
  END h[59]
  PIN h[5]
    DIRECTION OUTPUT ;
    USE SIGNAL ;
    PORT
      LAYER M3 ;
        RECT  5.616 53.856 5.634 54 ;
    END
  END h[5]
  PIN h[60]
    DIRECTION OUTPUT ;
    USE SIGNAL ;
    PORT
      LAYER M5 ;
        RECT  13.92 53.808 13.944 54 ;
    END
  END h[60]
  PIN h[61]
    DIRECTION OUTPUT ;
    USE SIGNAL ;
    PORT
      LAYER M3 ;
        RECT  14.076 53.856 14.094 54 ;
    END
  END h[61]
  PIN h[62]
    DIRECTION OUTPUT ;
    USE SIGNAL ;
    PORT
      LAYER M5 ;
        RECT  14.208 53.808 14.232 54 ;
    END
  END h[62]
  PIN h[63]
    DIRECTION OUTPUT ;
    USE SIGNAL ;
    PORT
      LAYER M3 ;
        RECT  14.364 53.856 14.382 54 ;
    END
  END h[63]
  PIN h[64]
    DIRECTION OUTPUT ;
    USE SIGNAL ;
    PORT
      LAYER M5 ;
        RECT  14.544 53.808 14.568 54 ;
    END
  END h[64]
  PIN h[65]
    DIRECTION OUTPUT ;
    USE SIGNAL ;
    PORT
      LAYER M3 ;
        RECT  14.688 53.856 14.706 54 ;
    END
  END h[65]
  PIN h[66]
    DIRECTION OUTPUT ;
    USE SIGNAL ;
    PORT
      LAYER M5 ;
        RECT  14.832 53.808 14.856 54 ;
    END
  END h[66]
  PIN h[67]
    DIRECTION OUTPUT ;
    USE SIGNAL ;
    PORT
      LAYER M3 ;
        RECT  14.976 53.856 14.994 54 ;
    END
  END h[67]
  PIN h[68]
    DIRECTION OUTPUT ;
    USE SIGNAL ;
    PORT
      LAYER M5 ;
        RECT  15.12 53.808 15.144 54 ;
    END
  END h[68]
  PIN h[69]
    DIRECTION OUTPUT ;
    USE SIGNAL ;
    PORT
      LAYER M3 ;
        RECT  15.3 53.856 15.318 54 ;
    END
  END h[69]
  PIN h[6]
    DIRECTION OUTPUT ;
    USE SIGNAL ;
    PORT
      LAYER M5 ;
        RECT  5.76 53.808 5.784 54 ;
    END
  END h[6]
  PIN h[70]
    DIRECTION OUTPUT ;
    USE SIGNAL ;
    PORT
      LAYER M5 ;
        RECT  15.456 53.808 15.48 54 ;
    END
  END h[70]
  PIN h[71]
    DIRECTION OUTPUT ;
    USE SIGNAL ;
    PORT
      LAYER M3 ;
        RECT  15.588 53.856 15.606 54 ;
    END
  END h[71]
  PIN h[72]
    DIRECTION OUTPUT ;
    USE SIGNAL ;
    PORT
      LAYER M5 ;
        RECT  15.744 53.808 15.768 54 ;
    END
  END h[72]
  PIN h[73]
    DIRECTION OUTPUT ;
    USE SIGNAL ;
    PORT
      LAYER M3 ;
        RECT  15.912 53.856 15.93 54 ;
    END
  END h[73]
  PIN h[74]
    DIRECTION OUTPUT ;
    USE SIGNAL ;
    PORT
      LAYER M5 ;
        RECT  16.032 53.808 16.056 54 ;
    END
  END h[74]
  PIN h[75]
    DIRECTION OUTPUT ;
    USE SIGNAL ;
    PORT
      LAYER M3 ;
        RECT  16.2 53.856 16.218 54 ;
    END
  END h[75]
  PIN h[76]
    DIRECTION OUTPUT ;
    USE SIGNAL ;
    PORT
      LAYER M5 ;
        RECT  16.368 53.808 16.392 54 ;
    END
  END h[76]
  PIN h[77]
    DIRECTION OUTPUT ;
    USE SIGNAL ;
    PORT
      LAYER M3 ;
        RECT  16.488 53.856 16.506 54 ;
    END
  END h[77]
  PIN h[78]
    DIRECTION OUTPUT ;
    USE SIGNAL ;
    PORT
      LAYER M5 ;
        RECT  16.656 53.808 16.68 54 ;
    END
  END h[78]
  PIN h[79]
    DIRECTION OUTPUT ;
    USE SIGNAL ;
    PORT
      LAYER M3 ;
        RECT  16.812 53.856 16.83 54 ;
    END
  END h[79]
  PIN h[7]
    DIRECTION OUTPUT ;
    USE SIGNAL ;
    PORT
      LAYER M3 ;
        RECT  5.904 53.856 5.922 54 ;
    END
  END h[7]
  PIN h[80]
    DIRECTION OUTPUT ;
    USE SIGNAL ;
    PORT
      LAYER M5 ;
        RECT  16.944 53.808 16.968 54 ;
    END
  END h[80]
  PIN h[81]
    DIRECTION OUTPUT ;
    USE SIGNAL ;
    PORT
      LAYER M3 ;
        RECT  17.1 53.856 17.118 54 ;
    END
  END h[81]
  PIN h[82]
    DIRECTION OUTPUT ;
    USE SIGNAL ;
    PORT
      LAYER M5 ;
        RECT  17.232 53.808 17.256 54 ;
    END
  END h[82]
  PIN h[83]
    DIRECTION OUTPUT ;
    USE SIGNAL ;
    PORT
      LAYER M3 ;
        RECT  17.424 53.856 17.442 54 ;
    END
  END h[83]
  PIN h[84]
    DIRECTION OUTPUT ;
    USE SIGNAL ;
    PORT
      LAYER M5 ;
        RECT  17.568 53.808 17.592 54 ;
    END
  END h[84]
  PIN h[85]
    DIRECTION OUTPUT ;
    USE SIGNAL ;
    PORT
      LAYER M3 ;
        RECT  17.712 53.856 17.73 54 ;
    END
  END h[85]
  PIN h[86]
    DIRECTION OUTPUT ;
    USE SIGNAL ;
    PORT
      LAYER M5 ;
        RECT  17.856 53.808 17.88 54 ;
    END
  END h[86]
  PIN h[87]
    DIRECTION OUTPUT ;
    USE SIGNAL ;
    PORT
      LAYER M3 ;
        RECT  18 53.856 18.018 54 ;
    END
  END h[87]
  PIN h[88]
    DIRECTION OUTPUT ;
    USE SIGNAL ;
    PORT
      LAYER M5 ;
        RECT  18.144 53.808 18.168 54 ;
    END
  END h[88]
  PIN h[89]
    DIRECTION OUTPUT ;
    USE SIGNAL ;
    PORT
      LAYER M3 ;
        RECT  18.324 53.856 18.342 54 ;
    END
  END h[89]
  PIN h[8]
    DIRECTION OUTPUT ;
    USE SIGNAL ;
    PORT
      LAYER M5 ;
        RECT  6.048 53.808 6.072 54 ;
    END
  END h[8]
  PIN h[90]
    DIRECTION OUTPUT ;
    USE SIGNAL ;
    PORT
      LAYER M5 ;
        RECT  18.48 53.808 18.504 54 ;
    END
  END h[90]
  PIN h[91]
    DIRECTION OUTPUT ;
    USE SIGNAL ;
    PORT
      LAYER M3 ;
        RECT  18.612 53.856 18.63 54 ;
    END
  END h[91]
  PIN h[92]
    DIRECTION OUTPUT ;
    USE SIGNAL ;
    PORT
      LAYER M5 ;
        RECT  18.768 53.808 18.792 54 ;
    END
  END h[92]
  PIN h[93]
    DIRECTION OUTPUT ;
    USE SIGNAL ;
    PORT
      LAYER M3 ;
        RECT  18.936 53.856 18.954 54 ;
    END
  END h[93]
  PIN h[94]
    DIRECTION OUTPUT ;
    USE SIGNAL ;
    PORT
      LAYER M5 ;
        RECT  19.056 53.808 19.08 54 ;
    END
  END h[94]
  PIN h[95]
    DIRECTION OUTPUT ;
    USE SIGNAL ;
    PORT
      LAYER M3 ;
        RECT  19.224 53.856 19.242 54 ;
    END
  END h[95]
  PIN h[96]
    DIRECTION OUTPUT ;
    USE SIGNAL ;
    PORT
      LAYER M5 ;
        RECT  19.392 53.808 19.416 54 ;
    END
  END h[96]
  PIN h[97]
    DIRECTION OUTPUT ;
    USE SIGNAL ;
    PORT
      LAYER M3 ;
        RECT  19.512 53.856 19.53 54 ;
    END
  END h[97]
  PIN h[98]
    DIRECTION OUTPUT ;
    USE SIGNAL ;
    PORT
      LAYER M5 ;
        RECT  19.68 53.808 19.704 54 ;
    END
  END h[98]
  PIN h[99]
    DIRECTION OUTPUT ;
    USE SIGNAL ;
    PORT
      LAYER M3 ;
        RECT  19.836 53.856 19.854 54 ;
    END
  END h[99]
  PIN h[9]
    DIRECTION OUTPUT ;
    USE SIGNAL ;
    PORT
      LAYER M3 ;
        RECT  6.192 53.856 6.21 54 ;
    END
  END h[9]
  PIN iv
    DIRECTION OUTPUT ;
    USE SIGNAL ;
    PORT
      LAYER M5 ;
        RECT  4.512 53.808 4.536 54 ;
    END
  END iv
  PIN kv[0]
    DIRECTION OUTPUT ;
    USE SIGNAL ;
    PORT
      LAYER M5 ;
        RECT  43.584 53.808 43.608 54 ;
    END
  END kv[0]
  PIN kv[100]
    DIRECTION OUTPUT ;
    USE SIGNAL ;
    PORT
      LAYER M5 ;
        RECT  58.752 53.808 58.776 54 ;
    END
  END kv[100]
  PIN kv[101]
    DIRECTION OUTPUT ;
    USE SIGNAL ;
    PORT
      LAYER M3 ;
        RECT  58.896 53.856 58.914 54 ;
    END
  END kv[101]
  PIN kv[102]
    DIRECTION OUTPUT ;
    USE SIGNAL ;
    PORT
      LAYER M5 ;
        RECT  59.04 53.808 59.064 54 ;
    END
  END kv[102]
  PIN kv[103]
    DIRECTION OUTPUT ;
    USE SIGNAL ;
    PORT
      LAYER M3 ;
        RECT  59.22 53.856 59.238 54 ;
    END
  END kv[103]
  PIN kv[104]
    DIRECTION OUTPUT ;
    USE SIGNAL ;
    PORT
      LAYER M5 ;
        RECT  59.376 53.808 59.4 54 ;
    END
  END kv[104]
  PIN kv[105]
    DIRECTION OUTPUT ;
    USE SIGNAL ;
    PORT
      LAYER M3 ;
        RECT  59.508 53.856 59.526 54 ;
    END
  END kv[105]
  PIN kv[106]
    DIRECTION OUTPUT ;
    USE SIGNAL ;
    PORT
      LAYER M5 ;
        RECT  59.664 53.808 59.688 54 ;
    END
  END kv[106]
  PIN kv[107]
    DIRECTION OUTPUT ;
    USE SIGNAL ;
    PORT
      LAYER M3 ;
        RECT  59.796 53.856 59.814 54 ;
    END
  END kv[107]
  PIN kv[108]
    DIRECTION OUTPUT ;
    USE SIGNAL ;
    PORT
      LAYER M5 ;
        RECT  59.952 53.808 59.976 54 ;
    END
  END kv[108]
  PIN kv[109]
    DIRECTION OUTPUT ;
    USE SIGNAL ;
    PORT
      LAYER M3 ;
        RECT  60.12 53.856 60.138 54 ;
    END
  END kv[109]
  PIN kv[10]
    DIRECTION OUTPUT ;
    USE SIGNAL ;
    PORT
      LAYER M5 ;
        RECT  45.12 53.808 45.144 54 ;
    END
  END kv[10]
  PIN kv[110]
    DIRECTION OUTPUT ;
    USE SIGNAL ;
    PORT
      LAYER M5 ;
        RECT  60.24 53.808 60.264 54 ;
    END
  END kv[110]
  PIN kv[111]
    DIRECTION OUTPUT ;
    USE SIGNAL ;
    PORT
      LAYER M3 ;
        RECT  60.408 53.856 60.426 54 ;
    END
  END kv[111]
  PIN kv[112]
    DIRECTION OUTPUT ;
    USE SIGNAL ;
    PORT
      LAYER M5 ;
        RECT  60.576 53.808 60.6 54 ;
    END
  END kv[112]
  PIN kv[113]
    DIRECTION OUTPUT ;
    USE SIGNAL ;
    PORT
      LAYER M3 ;
        RECT  60.732 53.856 60.75 54 ;
    END
  END kv[113]
  PIN kv[114]
    DIRECTION OUTPUT ;
    USE SIGNAL ;
    PORT
      LAYER M5 ;
        RECT  60.864 53.808 60.888 54 ;
    END
  END kv[114]
  PIN kv[115]
    DIRECTION OUTPUT ;
    USE SIGNAL ;
    PORT
      LAYER M3 ;
        RECT  61.02 53.856 61.038 54 ;
    END
  END kv[115]
  PIN kv[116]
    DIRECTION OUTPUT ;
    USE SIGNAL ;
    PORT
      LAYER M5 ;
        RECT  61.152 53.808 61.176 54 ;
    END
  END kv[116]
  PIN kv[117]
    DIRECTION OUTPUT ;
    USE SIGNAL ;
    PORT
      LAYER M3 ;
        RECT  61.308 53.856 61.326 54 ;
    END
  END kv[117]
  PIN kv[118]
    DIRECTION OUTPUT ;
    USE SIGNAL ;
    PORT
      LAYER M5 ;
        RECT  61.488 53.808 61.512 54 ;
    END
  END kv[118]
  PIN kv[119]
    DIRECTION OUTPUT ;
    USE SIGNAL ;
    PORT
      LAYER M3 ;
        RECT  61.632 53.856 61.65 54 ;
    END
  END kv[119]
  PIN kv[11]
    DIRECTION OUTPUT ;
    USE SIGNAL ;
    PORT
      LAYER M3 ;
        RECT  45.288 53.856 45.306 54 ;
    END
  END kv[11]
  PIN kv[120]
    DIRECTION OUTPUT ;
    USE SIGNAL ;
    PORT
      LAYER M5 ;
        RECT  61.776 53.808 61.8 54 ;
    END
  END kv[120]
  PIN kv[121]
    DIRECTION OUTPUT ;
    USE SIGNAL ;
    PORT
      LAYER M3 ;
        RECT  61.92 53.856 61.938 54 ;
    END
  END kv[121]
  PIN kv[122]
    DIRECTION OUTPUT ;
    USE SIGNAL ;
    PORT
      LAYER M5 ;
        RECT  62.064 53.808 62.088 54 ;
    END
  END kv[122]
  PIN kv[123]
    DIRECTION OUTPUT ;
    USE SIGNAL ;
    PORT
      LAYER M3 ;
        RECT  62.244 53.856 62.262 54 ;
    END
  END kv[123]
  PIN kv[124]
    DIRECTION OUTPUT ;
    USE SIGNAL ;
    PORT
      LAYER M5 ;
        RECT  62.4 53.808 62.424 54 ;
    END
  END kv[124]
  PIN kv[125]
    DIRECTION OUTPUT ;
    USE SIGNAL ;
    PORT
      LAYER M3 ;
        RECT  62.532 53.856 62.55 54 ;
    END
  END kv[125]
  PIN kv[126]
    DIRECTION OUTPUT ;
    USE SIGNAL ;
    PORT
      LAYER M5 ;
        RECT  62.688 53.808 62.712 54 ;
    END
  END kv[126]
  PIN kv[127]
    DIRECTION OUTPUT ;
    USE SIGNAL ;
    PORT
      LAYER M3 ;
        RECT  62.856 53.856 62.874 54 ;
    END
  END kv[127]
  PIN kv[128]
    DIRECTION OUTPUT ;
    USE SIGNAL ;
    PORT
      LAYER M5 ;
        RECT  62.976 53.808 63 54 ;
    END
  END kv[128]
  PIN kv[129]
    DIRECTION OUTPUT ;
    USE SIGNAL ;
    PORT
      LAYER M3 ;
        RECT  63.144 53.856 63.162 54 ;
    END
  END kv[129]
  PIN kv[12]
    DIRECTION OUTPUT ;
    USE SIGNAL ;
    PORT
      LAYER M5 ;
        RECT  45.408 53.808 45.432 54 ;
    END
  END kv[12]
  PIN kv[130]
    DIRECTION OUTPUT ;
    USE SIGNAL ;
    PORT
      LAYER M5 ;
        RECT  63.312 53.808 63.336 54 ;
    END
  END kv[130]
  PIN kv[131]
    DIRECTION OUTPUT ;
    USE SIGNAL ;
    PORT
      LAYER M3 ;
        RECT  63.432 53.856 63.45 54 ;
    END
  END kv[131]
  PIN kv[132]
    DIRECTION OUTPUT ;
    USE SIGNAL ;
    PORT
      LAYER M5 ;
        RECT  63.6 53.808 63.624 54 ;
    END
  END kv[132]
  PIN kv[133]
    DIRECTION OUTPUT ;
    USE SIGNAL ;
    PORT
      LAYER M3 ;
        RECT  63.756 53.856 63.774 54 ;
    END
  END kv[133]
  PIN kv[134]
    DIRECTION OUTPUT ;
    USE SIGNAL ;
    PORT
      LAYER M5 ;
        RECT  63.888 53.808 63.912 54 ;
    END
  END kv[134]
  PIN kv[135]
    DIRECTION OUTPUT ;
    USE SIGNAL ;
    PORT
      LAYER M3 ;
        RECT  64.044 53.856 64.062 54 ;
    END
  END kv[135]
  PIN kv[136]
    DIRECTION OUTPUT ;
    USE SIGNAL ;
    PORT
      LAYER M5 ;
        RECT  64.176 53.808 64.2 54 ;
    END
  END kv[136]
  PIN kv[137]
    DIRECTION OUTPUT ;
    USE SIGNAL ;
    PORT
      LAYER M3 ;
        RECT  64.368 53.856 64.386 54 ;
    END
  END kv[137]
  PIN kv[138]
    DIRECTION OUTPUT ;
    USE SIGNAL ;
    PORT
      LAYER M5 ;
        RECT  64.512 53.808 64.536 54 ;
    END
  END kv[138]
  PIN kv[139]
    DIRECTION OUTPUT ;
    USE SIGNAL ;
    PORT
      LAYER M3 ;
        RECT  64.656 53.856 64.674 54 ;
    END
  END kv[139]
  PIN kv[13]
    DIRECTION OUTPUT ;
    USE SIGNAL ;
    PORT
      LAYER M3 ;
        RECT  45.576 53.856 45.594 54 ;
    END
  END kv[13]
  PIN kv[140]
    DIRECTION OUTPUT ;
    USE SIGNAL ;
    PORT
      LAYER M5 ;
        RECT  64.8 53.808 64.824 54 ;
    END
  END kv[140]
  PIN kv[141]
    DIRECTION OUTPUT ;
    USE SIGNAL ;
    PORT
      LAYER M3 ;
        RECT  64.944 53.856 64.962 54 ;
    END
  END kv[141]
  PIN kv[142]
    DIRECTION OUTPUT ;
    USE SIGNAL ;
    PORT
      LAYER M5 ;
        RECT  65.088 53.808 65.112 54 ;
    END
  END kv[142]
  PIN kv[143]
    DIRECTION OUTPUT ;
    USE SIGNAL ;
    PORT
      LAYER M3 ;
        RECT  65.268 53.856 65.286 54 ;
    END
  END kv[143]
  PIN kv[144]
    DIRECTION OUTPUT ;
    USE SIGNAL ;
    PORT
      LAYER M5 ;
        RECT  65.424 53.808 65.448 54 ;
    END
  END kv[144]
  PIN kv[145]
    DIRECTION OUTPUT ;
    USE SIGNAL ;
    PORT
      LAYER M3 ;
        RECT  65.556 53.856 65.574 54 ;
    END
  END kv[145]
  PIN kv[146]
    DIRECTION OUTPUT ;
    USE SIGNAL ;
    PORT
      LAYER M5 ;
        RECT  65.712 53.808 65.736 54 ;
    END
  END kv[146]
  PIN kv[147]
    DIRECTION OUTPUT ;
    USE SIGNAL ;
    PORT
      LAYER M3 ;
        RECT  65.88 53.856 65.898 54 ;
    END
  END kv[147]
  PIN kv[148]
    DIRECTION OUTPUT ;
    USE SIGNAL ;
    PORT
      LAYER M5 ;
        RECT  66 53.808 66.024 54 ;
    END
  END kv[148]
  PIN kv[149]
    DIRECTION OUTPUT ;
    USE SIGNAL ;
    PORT
      LAYER M3 ;
        RECT  66.168 53.856 66.186 54 ;
    END
  END kv[149]
  PIN kv[14]
    DIRECTION OUTPUT ;
    USE SIGNAL ;
    PORT
      LAYER M5 ;
        RECT  45.744 53.808 45.768 54 ;
    END
  END kv[14]
  PIN kv[150]
    DIRECTION OUTPUT ;
    USE SIGNAL ;
    PORT
      LAYER M5 ;
        RECT  66.336 53.808 66.36 54 ;
    END
  END kv[150]
  PIN kv[151]
    DIRECTION OUTPUT ;
    USE SIGNAL ;
    PORT
      LAYER M3 ;
        RECT  66.456 53.856 66.474 54 ;
    END
  END kv[151]
  PIN kv[152]
    DIRECTION OUTPUT ;
    USE SIGNAL ;
    PORT
      LAYER M5 ;
        RECT  66.624 53.808 66.648 54 ;
    END
  END kv[152]
  PIN kv[153]
    DIRECTION OUTPUT ;
    USE SIGNAL ;
    PORT
      LAYER M3 ;
        RECT  66.78 53.856 66.798 54 ;
    END
  END kv[153]
  PIN kv[154]
    DIRECTION OUTPUT ;
    USE SIGNAL ;
    PORT
      LAYER M5 ;
        RECT  66.912 53.808 66.936 54 ;
    END
  END kv[154]
  PIN kv[155]
    DIRECTION OUTPUT ;
    USE SIGNAL ;
    PORT
      LAYER M3 ;
        RECT  67.068 53.856 67.086 54 ;
    END
  END kv[155]
  PIN kv[156]
    DIRECTION OUTPUT ;
    USE SIGNAL ;
    PORT
      LAYER M5 ;
        RECT  67.248 53.808 67.272 54 ;
    END
  END kv[156]
  PIN kv[157]
    DIRECTION OUTPUT ;
    USE SIGNAL ;
    PORT
      LAYER M3 ;
        RECT  67.392 53.856 67.41 54 ;
    END
  END kv[157]
  PIN kv[158]
    DIRECTION OUTPUT ;
    USE SIGNAL ;
    PORT
      LAYER M5 ;
        RECT  67.536 53.808 67.56 54 ;
    END
  END kv[158]
  PIN kv[159]
    DIRECTION OUTPUT ;
    USE SIGNAL ;
    PORT
      LAYER M3 ;
        RECT  67.68 53.856 67.698 54 ;
    END
  END kv[159]
  PIN kv[15]
    DIRECTION OUTPUT ;
    USE SIGNAL ;
    PORT
      LAYER M3 ;
        RECT  45.864 53.856 45.882 54 ;
    END
  END kv[15]
  PIN kv[160]
    DIRECTION OUTPUT ;
    USE SIGNAL ;
    PORT
      LAYER M5 ;
        RECT  67.824 53.808 67.848 54 ;
    END
  END kv[160]
  PIN kv[161]
    DIRECTION OUTPUT ;
    USE SIGNAL ;
    PORT
      LAYER M3 ;
        RECT  68.004 53.856 68.022 54 ;
    END
  END kv[161]
  PIN kv[162]
    DIRECTION OUTPUT ;
    USE SIGNAL ;
    PORT
      LAYER M5 ;
        RECT  68.16 53.808 68.184 54 ;
    END
  END kv[162]
  PIN kv[163]
    DIRECTION OUTPUT ;
    USE SIGNAL ;
    PORT
      LAYER M3 ;
        RECT  68.292 53.856 68.31 54 ;
    END
  END kv[163]
  PIN kv[164]
    DIRECTION OUTPUT ;
    USE SIGNAL ;
    PORT
      LAYER M5 ;
        RECT  68.448 53.808 68.472 54 ;
    END
  END kv[164]
  PIN kv[165]
    DIRECTION OUTPUT ;
    USE SIGNAL ;
    PORT
      LAYER M3 ;
        RECT  68.58 53.856 68.598 54 ;
    END
  END kv[165]
  PIN kv[166]
    DIRECTION OUTPUT ;
    USE SIGNAL ;
    PORT
      LAYER M5 ;
        RECT  68.736 53.808 68.76 54 ;
    END
  END kv[166]
  PIN kv[167]
    DIRECTION OUTPUT ;
    USE SIGNAL ;
    PORT
      LAYER M3 ;
        RECT  68.904 53.856 68.922 54 ;
    END
  END kv[167]
  PIN kv[168]
    DIRECTION OUTPUT ;
    USE SIGNAL ;
    PORT
      LAYER M5 ;
        RECT  69.024 53.808 69.048 54 ;
    END
  END kv[168]
  PIN kv[169]
    DIRECTION OUTPUT ;
    USE SIGNAL ;
    PORT
      LAYER M3 ;
        RECT  69.192 53.856 69.21 54 ;
    END
  END kv[169]
  PIN kv[16]
    DIRECTION OUTPUT ;
    USE SIGNAL ;
    PORT
      LAYER M5 ;
        RECT  46.032 53.808 46.056 54 ;
    END
  END kv[16]
  PIN kv[170]
    DIRECTION OUTPUT ;
    USE SIGNAL ;
    PORT
      LAYER M5 ;
        RECT  69.36 53.808 69.384 54 ;
    END
  END kv[170]
  PIN kv[171]
    DIRECTION OUTPUT ;
    USE SIGNAL ;
    PORT
      LAYER M3 ;
        RECT  69.516 53.856 69.534 54 ;
    END
  END kv[171]
  PIN kv[172]
    DIRECTION OUTPUT ;
    USE SIGNAL ;
    PORT
      LAYER M5 ;
        RECT  69.648 53.808 69.672 54 ;
    END
  END kv[172]
  PIN kv[173]
    DIRECTION OUTPUT ;
    USE SIGNAL ;
    PORT
      LAYER M3 ;
        RECT  69.804 53.856 69.822 54 ;
    END
  END kv[173]
  PIN kv[174]
    DIRECTION OUTPUT ;
    USE SIGNAL ;
    PORT
      LAYER M5 ;
        RECT  69.936 53.808 69.96 54 ;
    END
  END kv[174]
  PIN kv[175]
    DIRECTION OUTPUT ;
    USE SIGNAL ;
    PORT
      LAYER M3 ;
        RECT  70.092 53.856 70.11 54 ;
    END
  END kv[175]
  PIN kv[176]
    DIRECTION OUTPUT ;
    USE SIGNAL ;
    PORT
      LAYER M5 ;
        RECT  70.272 53.808 70.296 54 ;
    END
  END kv[176]
  PIN kv[177]
    DIRECTION OUTPUT ;
    USE SIGNAL ;
    PORT
      LAYER M3 ;
        RECT  70.416 53.856 70.434 54 ;
    END
  END kv[177]
  PIN kv[178]
    DIRECTION OUTPUT ;
    USE SIGNAL ;
    PORT
      LAYER M5 ;
        RECT  70.56 53.808 70.584 54 ;
    END
  END kv[178]
  PIN kv[179]
    DIRECTION OUTPUT ;
    USE SIGNAL ;
    PORT
      LAYER M3 ;
        RECT  70.704 53.856 70.722 54 ;
    END
  END kv[179]
  PIN kv[17]
    DIRECTION OUTPUT ;
    USE SIGNAL ;
    PORT
      LAYER M3 ;
        RECT  46.188 53.856 46.206 54 ;
    END
  END kv[17]
  PIN kv[180]
    DIRECTION OUTPUT ;
    USE SIGNAL ;
    PORT
      LAYER M5 ;
        RECT  70.848 53.808 70.872 54 ;
    END
  END kv[180]
  PIN kv[181]
    DIRECTION OUTPUT ;
    USE SIGNAL ;
    PORT
      LAYER M3 ;
        RECT  71.028 53.856 71.046 54 ;
    END
  END kv[181]
  PIN kv[182]
    DIRECTION OUTPUT ;
    USE SIGNAL ;
    PORT
      LAYER M5 ;
        RECT  71.184 53.808 71.208 54 ;
    END
  END kv[182]
  PIN kv[183]
    DIRECTION OUTPUT ;
    USE SIGNAL ;
    PORT
      LAYER M3 ;
        RECT  71.316 53.856 71.334 54 ;
    END
  END kv[183]
  PIN kv[184]
    DIRECTION OUTPUT ;
    USE SIGNAL ;
    PORT
      LAYER M5 ;
        RECT  71.472 53.808 71.496 54 ;
    END
  END kv[184]
  PIN kv[185]
    DIRECTION OUTPUT ;
    USE SIGNAL ;
    PORT
      LAYER M3 ;
        RECT  71.64 53.856 71.658 54 ;
    END
  END kv[185]
  PIN kv[186]
    DIRECTION OUTPUT ;
    USE SIGNAL ;
    PORT
      LAYER M5 ;
        RECT  71.76 53.808 71.784 54 ;
    END
  END kv[186]
  PIN kv[187]
    DIRECTION OUTPUT ;
    USE SIGNAL ;
    PORT
      LAYER M3 ;
        RECT  71.928 53.856 71.946 54 ;
    END
  END kv[187]
  PIN kv[188]
    DIRECTION OUTPUT ;
    USE SIGNAL ;
    PORT
      LAYER M5 ;
        RECT  72.096 53.808 72.12 54 ;
    END
  END kv[188]
  PIN kv[189]
    DIRECTION OUTPUT ;
    USE SIGNAL ;
    PORT
      LAYER M3 ;
        RECT  72.216 53.856 72.234 54 ;
    END
  END kv[189]
  PIN kv[18]
    DIRECTION OUTPUT ;
    USE SIGNAL ;
    PORT
      LAYER M5 ;
        RECT  46.32 53.808 46.344 54 ;
    END
  END kv[18]
  PIN kv[190]
    DIRECTION OUTPUT ;
    USE SIGNAL ;
    PORT
      LAYER M5 ;
        RECT  72.384 53.808 72.408 54 ;
    END
  END kv[190]
  PIN kv[191]
    DIRECTION OUTPUT ;
    USE SIGNAL ;
    PORT
      LAYER M3 ;
        RECT  72.54 53.856 72.558 54 ;
    END
  END kv[191]
  PIN kv[192]
    DIRECTION OUTPUT ;
    USE SIGNAL ;
    PORT
      LAYER M5 ;
        RECT  72.672 53.808 72.696 54 ;
    END
  END kv[192]
  PIN kv[193]
    DIRECTION OUTPUT ;
    USE SIGNAL ;
    PORT
      LAYER M3 ;
        RECT  72.828 53.856 72.846 54 ;
    END
  END kv[193]
  PIN kv[194]
    DIRECTION OUTPUT ;
    USE SIGNAL ;
    PORT
      LAYER M5 ;
        RECT  72.96 53.808 72.984 54 ;
    END
  END kv[194]
  PIN kv[195]
    DIRECTION OUTPUT ;
    USE SIGNAL ;
    PORT
      LAYER M3 ;
        RECT  73.152 53.856 73.17 54 ;
    END
  END kv[195]
  PIN kv[196]
    DIRECTION OUTPUT ;
    USE SIGNAL ;
    PORT
      LAYER M5 ;
        RECT  73.296 53.808 73.32 54 ;
    END
  END kv[196]
  PIN kv[197]
    DIRECTION OUTPUT ;
    USE SIGNAL ;
    PORT
      LAYER M3 ;
        RECT  73.44 53.856 73.458 54 ;
    END
  END kv[197]
  PIN kv[198]
    DIRECTION OUTPUT ;
    USE SIGNAL ;
    PORT
      LAYER M5 ;
        RECT  73.584 53.808 73.608 54 ;
    END
  END kv[198]
  PIN kv[199]
    DIRECTION OUTPUT ;
    USE SIGNAL ;
    PORT
      LAYER M3 ;
        RECT  73.728 53.856 73.746 54 ;
    END
  END kv[199]
  PIN kv[19]
    DIRECTION OUTPUT ;
    USE SIGNAL ;
    PORT
      LAYER M3 ;
        RECT  46.476 53.856 46.494 54 ;
    END
  END kv[19]
  PIN kv[1]
    DIRECTION OUTPUT ;
    USE SIGNAL ;
    PORT
      LAYER M3 ;
        RECT  43.776 53.856 43.794 54 ;
    END
  END kv[1]
  PIN kv[200]
    DIRECTION OUTPUT ;
    USE SIGNAL ;
    PORT
      LAYER M5 ;
        RECT  73.872 53.808 73.896 54 ;
    END
  END kv[200]
  PIN kv[201]
    DIRECTION OUTPUT ;
    USE SIGNAL ;
    PORT
      LAYER M3 ;
        RECT  74.052 53.856 74.07 54 ;
    END
  END kv[201]
  PIN kv[202]
    DIRECTION OUTPUT ;
    USE SIGNAL ;
    PORT
      LAYER M5 ;
        RECT  74.208 53.808 74.232 54 ;
    END
  END kv[202]
  PIN kv[203]
    DIRECTION OUTPUT ;
    USE SIGNAL ;
    PORT
      LAYER M3 ;
        RECT  74.34 53.856 74.358 54 ;
    END
  END kv[203]
  PIN kv[204]
    DIRECTION OUTPUT ;
    USE SIGNAL ;
    PORT
      LAYER M5 ;
        RECT  74.496 53.808 74.52 54 ;
    END
  END kv[204]
  PIN kv[205]
    DIRECTION OUTPUT ;
    USE SIGNAL ;
    PORT
      LAYER M3 ;
        RECT  74.664 53.856 74.682 54 ;
    END
  END kv[205]
  PIN kv[206]
    DIRECTION OUTPUT ;
    USE SIGNAL ;
    PORT
      LAYER M5 ;
        RECT  74.784 53.808 74.808 54 ;
    END
  END kv[206]
  PIN kv[207]
    DIRECTION OUTPUT ;
    USE SIGNAL ;
    PORT
      LAYER M3 ;
        RECT  74.952 53.856 74.97 54 ;
    END
  END kv[207]
  PIN kv[208]
    DIRECTION OUTPUT ;
    USE SIGNAL ;
    PORT
      LAYER M5 ;
        RECT  75.12 53.808 75.144 54 ;
    END
  END kv[208]
  PIN kv[209]
    DIRECTION OUTPUT ;
    USE SIGNAL ;
    PORT
      LAYER M3 ;
        RECT  75.24 53.856 75.258 54 ;
    END
  END kv[209]
  PIN kv[20]
    DIRECTION OUTPUT ;
    USE SIGNAL ;
    PORT
      LAYER M5 ;
        RECT  46.656 53.808 46.68 54 ;
    END
  END kv[20]
  PIN kv[210]
    DIRECTION OUTPUT ;
    USE SIGNAL ;
    PORT
      LAYER M5 ;
        RECT  75.408 53.808 75.432 54 ;
    END
  END kv[210]
  PIN kv[211]
    DIRECTION OUTPUT ;
    USE SIGNAL ;
    PORT
      LAYER M3 ;
        RECT  75.564 53.856 75.582 54 ;
    END
  END kv[211]
  PIN kv[212]
    DIRECTION OUTPUT ;
    USE SIGNAL ;
    PORT
      LAYER M5 ;
        RECT  75.696 53.808 75.72 54 ;
    END
  END kv[212]
  PIN kv[213]
    DIRECTION OUTPUT ;
    USE SIGNAL ;
    PORT
      LAYER M3 ;
        RECT  75.852 53.856 75.87 54 ;
    END
  END kv[213]
  PIN kv[214]
    DIRECTION OUTPUT ;
    USE SIGNAL ;
    PORT
      LAYER M5 ;
        RECT  76.032 53.808 76.056 54 ;
    END
  END kv[214]
  PIN kv[215]
    DIRECTION OUTPUT ;
    USE SIGNAL ;
    PORT
      LAYER M3 ;
        RECT  76.176 53.856 76.194 54 ;
    END
  END kv[215]
  PIN kv[216]
    DIRECTION OUTPUT ;
    USE SIGNAL ;
    PORT
      LAYER M5 ;
        RECT  76.32 53.808 76.344 54 ;
    END
  END kv[216]
  PIN kv[217]
    DIRECTION OUTPUT ;
    USE SIGNAL ;
    PORT
      LAYER M3 ;
        RECT  76.464 53.856 76.482 54 ;
    END
  END kv[217]
  PIN kv[218]
    DIRECTION OUTPUT ;
    USE SIGNAL ;
    PORT
      LAYER M5 ;
        RECT  76.608 53.808 76.632 54 ;
    END
  END kv[218]
  PIN kv[219]
    DIRECTION OUTPUT ;
    USE SIGNAL ;
    PORT
      LAYER M3 ;
        RECT  76.788 53.856 76.806 54 ;
    END
  END kv[219]
  PIN kv[21]
    DIRECTION OUTPUT ;
    USE SIGNAL ;
    PORT
      LAYER M3 ;
        RECT  46.8 53.856 46.818 54 ;
    END
  END kv[21]
  PIN kv[220]
    DIRECTION OUTPUT ;
    USE SIGNAL ;
    PORT
      LAYER M5 ;
        RECT  76.896 53.808 76.92 54 ;
    END
  END kv[220]
  PIN kv[221]
    DIRECTION OUTPUT ;
    USE SIGNAL ;
    PORT
      LAYER M3 ;
        RECT  77.076 53.856 77.094 54 ;
    END
  END kv[221]
  PIN kv[222]
    DIRECTION OUTPUT ;
    USE SIGNAL ;
    PORT
      LAYER M5 ;
        RECT  77.232 53.808 77.256 54 ;
    END
  END kv[222]
  PIN kv[223]
    DIRECTION OUTPUT ;
    USE SIGNAL ;
    PORT
      LAYER M3 ;
        RECT  77.364 53.856 77.382 54 ;
    END
  END kv[223]
  PIN kv[224]
    DIRECTION OUTPUT ;
    USE SIGNAL ;
    PORT
      LAYER M5 ;
        RECT  77.52 53.808 77.544 54 ;
    END
  END kv[224]
  PIN kv[225]
    DIRECTION OUTPUT ;
    USE SIGNAL ;
    PORT
      LAYER M3 ;
        RECT  77.688 53.856 77.706 54 ;
    END
  END kv[225]
  PIN kv[226]
    DIRECTION OUTPUT ;
    USE SIGNAL ;
    PORT
      LAYER M5 ;
        RECT  77.808 53.808 77.832 54 ;
    END
  END kv[226]
  PIN kv[227]
    DIRECTION OUTPUT ;
    USE SIGNAL ;
    PORT
      LAYER M3 ;
        RECT  77.976 53.856 77.994 54 ;
    END
  END kv[227]
  PIN kv[228]
    DIRECTION OUTPUT ;
    USE SIGNAL ;
    PORT
      LAYER M5 ;
        RECT  78.144 53.808 78.168 54 ;
    END
  END kv[228]
  PIN kv[229]
    DIRECTION OUTPUT ;
    USE SIGNAL ;
    PORT
      LAYER M3 ;
        RECT  78.3 53.856 78.318 54 ;
    END
  END kv[229]
  PIN kv[22]
    DIRECTION OUTPUT ;
    USE SIGNAL ;
    PORT
      LAYER M5 ;
        RECT  46.944 53.808 46.968 54 ;
    END
  END kv[22]
  PIN kv[230]
    DIRECTION OUTPUT ;
    USE SIGNAL ;
    PORT
      LAYER M5 ;
        RECT  78.432 53.808 78.456 54 ;
    END
  END kv[230]
  PIN kv[231]
    DIRECTION OUTPUT ;
    USE SIGNAL ;
    PORT
      LAYER M3 ;
        RECT  78.588 53.856 78.606 54 ;
    END
  END kv[231]
  PIN kv[232]
    DIRECTION OUTPUT ;
    USE SIGNAL ;
    PORT
      LAYER M5 ;
        RECT  78.72 53.808 78.744 54 ;
    END
  END kv[232]
  PIN kv[233]
    DIRECTION OUTPUT ;
    USE SIGNAL ;
    PORT
      LAYER M3 ;
        RECT  78.876 53.856 78.894 54 ;
    END
  END kv[233]
  PIN kv[234]
    DIRECTION OUTPUT ;
    USE SIGNAL ;
    PORT
      LAYER M5 ;
        RECT  79.056 53.808 79.08 54 ;
    END
  END kv[234]
  PIN kv[235]
    DIRECTION OUTPUT ;
    USE SIGNAL ;
    PORT
      LAYER M3 ;
        RECT  79.2 53.856 79.218 54 ;
    END
  END kv[235]
  PIN kv[236]
    DIRECTION OUTPUT ;
    USE SIGNAL ;
    PORT
      LAYER M5 ;
        RECT  79.344 53.808 79.368 54 ;
    END
  END kv[236]
  PIN kv[237]
    DIRECTION OUTPUT ;
    USE SIGNAL ;
    PORT
      LAYER M3 ;
        RECT  79.488 53.856 79.506 54 ;
    END
  END kv[237]
  PIN kv[238]
    DIRECTION OUTPUT ;
    USE SIGNAL ;
    PORT
      LAYER M5 ;
        RECT  79.632 53.808 79.656 54 ;
    END
  END kv[238]
  PIN kv[239]
    DIRECTION OUTPUT ;
    USE SIGNAL ;
    PORT
      LAYER M3 ;
        RECT  79.812 53.856 79.83 54 ;
    END
  END kv[239]
  PIN kv[23]
    DIRECTION OUTPUT ;
    USE SIGNAL ;
    PORT
      LAYER M3 ;
        RECT  47.088 53.856 47.106 54 ;
    END
  END kv[23]
  PIN kv[240]
    DIRECTION OUTPUT ;
    USE SIGNAL ;
    PORT
      LAYER M5 ;
        RECT  79.968 53.808 79.992 54 ;
    END
  END kv[240]
  PIN kv[241]
    DIRECTION OUTPUT ;
    USE SIGNAL ;
    PORT
      LAYER M3 ;
        RECT  80.1 53.856 80.118 54 ;
    END
  END kv[241]
  PIN kv[242]
    DIRECTION OUTPUT ;
    USE SIGNAL ;
    PORT
      LAYER M5 ;
        RECT  80.256 53.808 80.28 54 ;
    END
  END kv[242]
  PIN kv[243]
    DIRECTION OUTPUT ;
    USE SIGNAL ;
    PORT
      LAYER M3 ;
        RECT  80.388 53.856 80.406 54 ;
    END
  END kv[243]
  PIN kv[244]
    DIRECTION OUTPUT ;
    USE SIGNAL ;
    PORT
      LAYER M5 ;
        RECT  80.544 53.808 80.568 54 ;
    END
  END kv[244]
  PIN kv[245]
    DIRECTION OUTPUT ;
    USE SIGNAL ;
    PORT
      LAYER M3 ;
        RECT  80.712 53.856 80.73 54 ;
    END
  END kv[245]
  PIN kv[246]
    DIRECTION OUTPUT ;
    USE SIGNAL ;
    PORT
      LAYER M5 ;
        RECT  80.88 53.808 80.904 54 ;
    END
  END kv[246]
  PIN kv[247]
    DIRECTION OUTPUT ;
    USE SIGNAL ;
    PORT
      LAYER M3 ;
        RECT  81 53.856 81.018 54 ;
    END
  END kv[247]
  PIN kv[248]
    DIRECTION OUTPUT ;
    USE SIGNAL ;
    PORT
      LAYER M5 ;
        RECT  81.168 53.808 81.192 54 ;
    END
  END kv[248]
  PIN kv[249]
    DIRECTION OUTPUT ;
    USE SIGNAL ;
    PORT
      LAYER M3 ;
        RECT  81.324 53.856 81.342 54 ;
    END
  END kv[249]
  PIN kv[24]
    DIRECTION OUTPUT ;
    USE SIGNAL ;
    PORT
      LAYER M5 ;
        RECT  47.232 53.808 47.256 54 ;
    END
  END kv[24]
  PIN kv[250]
    DIRECTION OUTPUT ;
    USE SIGNAL ;
    PORT
      LAYER M5 ;
        RECT  81.456 53.808 81.48 54 ;
    END
  END kv[250]
  PIN kv[251]
    DIRECTION OUTPUT ;
    USE SIGNAL ;
    PORT
      LAYER M3 ;
        RECT  81.612 53.856 81.63 54 ;
    END
  END kv[251]
  PIN kv[252]
    DIRECTION OUTPUT ;
    USE SIGNAL ;
    PORT
      LAYER M5 ;
        RECT  81.744 53.808 81.768 54 ;
    END
  END kv[252]
  PIN kv[253]
    DIRECTION OUTPUT ;
    USE SIGNAL ;
    PORT
      LAYER M3 ;
        RECT  81.936 53.856 81.954 54 ;
    END
  END kv[253]
  PIN kv[254]
    DIRECTION OUTPUT ;
    USE SIGNAL ;
    PORT
      LAYER M5 ;
        RECT  82.08 53.808 82.104 54 ;
    END
  END kv[254]
  PIN kv[255]
    DIRECTION OUTPUT ;
    USE SIGNAL ;
    PORT
      LAYER M3 ;
        RECT  82.224 53.856 82.242 54 ;
    END
  END kv[255]
  PIN kv[25]
    DIRECTION OUTPUT ;
    USE SIGNAL ;
    PORT
      LAYER M3 ;
        RECT  47.376 53.856 47.394 54 ;
    END
  END kv[25]
  PIN kv[26]
    DIRECTION OUTPUT ;
    USE SIGNAL ;
    PORT
      LAYER M5 ;
        RECT  47.52 53.808 47.544 54 ;
    END
  END kv[26]
  PIN kv[27]
    DIRECTION OUTPUT ;
    USE SIGNAL ;
    PORT
      LAYER M3 ;
        RECT  47.7 53.856 47.718 54 ;
    END
  END kv[27]
  PIN kv[28]
    DIRECTION OUTPUT ;
    USE SIGNAL ;
    PORT
      LAYER M5 ;
        RECT  47.856 53.808 47.88 54 ;
    END
  END kv[28]
  PIN kv[29]
    DIRECTION OUTPUT ;
    USE SIGNAL ;
    PORT
      LAYER M3 ;
        RECT  47.988 53.856 48.006 54 ;
    END
  END kv[29]
  PIN kv[2]
    DIRECTION OUTPUT ;
    USE SIGNAL ;
    PORT
      LAYER M5 ;
        RECT  43.92 53.808 43.944 54 ;
    END
  END kv[2]
  PIN kv[30]
    DIRECTION OUTPUT ;
    USE SIGNAL ;
    PORT
      LAYER M5 ;
        RECT  48.144 53.808 48.168 54 ;
    END
  END kv[30]
  PIN kv[31]
    DIRECTION OUTPUT ;
    USE SIGNAL ;
    PORT
      LAYER M3 ;
        RECT  48.312 53.856 48.33 54 ;
    END
  END kv[31]
  PIN kv[32]
    DIRECTION OUTPUT ;
    USE SIGNAL ;
    PORT
      LAYER M5 ;
        RECT  48.432 53.808 48.456 54 ;
    END
  END kv[32]
  PIN kv[33]
    DIRECTION OUTPUT ;
    USE SIGNAL ;
    PORT
      LAYER M3 ;
        RECT  48.6 53.856 48.618 54 ;
    END
  END kv[33]
  PIN kv[34]
    DIRECTION OUTPUT ;
    USE SIGNAL ;
    PORT
      LAYER M5 ;
        RECT  48.768 53.808 48.792 54 ;
    END
  END kv[34]
  PIN kv[35]
    DIRECTION OUTPUT ;
    USE SIGNAL ;
    PORT
      LAYER M3 ;
        RECT  48.924 53.856 48.942 54 ;
    END
  END kv[35]
  PIN kv[36]
    DIRECTION OUTPUT ;
    USE SIGNAL ;
    PORT
      LAYER M5 ;
        RECT  49.056 53.808 49.08 54 ;
    END
  END kv[36]
  PIN kv[37]
    DIRECTION OUTPUT ;
    USE SIGNAL ;
    PORT
      LAYER M3 ;
        RECT  49.212 53.856 49.23 54 ;
    END
  END kv[37]
  PIN kv[38]
    DIRECTION OUTPUT ;
    USE SIGNAL ;
    PORT
      LAYER M5 ;
        RECT  49.344 53.808 49.368 54 ;
    END
  END kv[38]
  PIN kv[39]
    DIRECTION OUTPUT ;
    USE SIGNAL ;
    PORT
      LAYER M3 ;
        RECT  49.5 53.856 49.518 54 ;
    END
  END kv[39]
  PIN kv[3]
    DIRECTION OUTPUT ;
    USE SIGNAL ;
    PORT
      LAYER M3 ;
        RECT  44.064 53.856 44.082 54 ;
    END
  END kv[3]
  PIN kv[40]
    DIRECTION OUTPUT ;
    USE SIGNAL ;
    PORT
      LAYER M5 ;
        RECT  49.68 53.808 49.704 54 ;
    END
  END kv[40]
  PIN kv[41]
    DIRECTION OUTPUT ;
    USE SIGNAL ;
    PORT
      LAYER M3 ;
        RECT  49.824 53.856 49.842 54 ;
    END
  END kv[41]
  PIN kv[42]
    DIRECTION OUTPUT ;
    USE SIGNAL ;
    PORT
      LAYER M5 ;
        RECT  49.968 53.808 49.992 54 ;
    END
  END kv[42]
  PIN kv[43]
    DIRECTION OUTPUT ;
    USE SIGNAL ;
    PORT
      LAYER M3 ;
        RECT  50.112 53.856 50.13 54 ;
    END
  END kv[43]
  PIN kv[44]
    DIRECTION OUTPUT ;
    USE SIGNAL ;
    PORT
      LAYER M5 ;
        RECT  50.256 53.808 50.28 54 ;
    END
  END kv[44]
  PIN kv[45]
    DIRECTION OUTPUT ;
    USE SIGNAL ;
    PORT
      LAYER M3 ;
        RECT  50.436 53.856 50.454 54 ;
    END
  END kv[45]
  PIN kv[46]
    DIRECTION OUTPUT ;
    USE SIGNAL ;
    PORT
      LAYER M5 ;
        RECT  50.592 53.808 50.616 54 ;
    END
  END kv[46]
  PIN kv[47]
    DIRECTION OUTPUT ;
    USE SIGNAL ;
    PORT
      LAYER M3 ;
        RECT  50.724 53.856 50.742 54 ;
    END
  END kv[47]
  PIN kv[48]
    DIRECTION OUTPUT ;
    USE SIGNAL ;
    PORT
      LAYER M5 ;
        RECT  50.88 53.808 50.904 54 ;
    END
  END kv[48]
  PIN kv[49]
    DIRECTION OUTPUT ;
    USE SIGNAL ;
    PORT
      LAYER M3 ;
        RECT  51.012 53.856 51.03 54 ;
    END
  END kv[49]
  PIN kv[4]
    DIRECTION OUTPUT ;
    USE SIGNAL ;
    PORT
      LAYER M5 ;
        RECT  44.208 53.808 44.232 54 ;
    END
  END kv[4]
  PIN kv[50]
    DIRECTION OUTPUT ;
    USE SIGNAL ;
    PORT
      LAYER M5 ;
        RECT  51.168 53.808 51.192 54 ;
    END
  END kv[50]
  PIN kv[51]
    DIRECTION OUTPUT ;
    USE SIGNAL ;
    PORT
      LAYER M3 ;
        RECT  51.336 53.856 51.354 54 ;
    END
  END kv[51]
  PIN kv[52]
    DIRECTION OUTPUT ;
    USE SIGNAL ;
    PORT
      LAYER M5 ;
        RECT  51.456 53.808 51.48 54 ;
    END
  END kv[52]
  PIN kv[53]
    DIRECTION OUTPUT ;
    USE SIGNAL ;
    PORT
      LAYER M3 ;
        RECT  51.624 53.856 51.642 54 ;
    END
  END kv[53]
  PIN kv[54]
    DIRECTION OUTPUT ;
    USE SIGNAL ;
    PORT
      LAYER M5 ;
        RECT  51.792 53.808 51.816 54 ;
    END
  END kv[54]
  PIN kv[55]
    DIRECTION OUTPUT ;
    USE SIGNAL ;
    PORT
      LAYER M3 ;
        RECT  51.948 53.856 51.966 54 ;
    END
  END kv[55]
  PIN kv[56]
    DIRECTION OUTPUT ;
    USE SIGNAL ;
    PORT
      LAYER M5 ;
        RECT  52.08 53.808 52.104 54 ;
    END
  END kv[56]
  PIN kv[57]
    DIRECTION OUTPUT ;
    USE SIGNAL ;
    PORT
      LAYER M3 ;
        RECT  52.236 53.856 52.254 54 ;
    END
  END kv[57]
  PIN kv[58]
    DIRECTION OUTPUT ;
    USE SIGNAL ;
    PORT
      LAYER M5 ;
        RECT  52.368 53.808 52.392 54 ;
    END
  END kv[58]
  PIN kv[59]
    DIRECTION OUTPUT ;
    USE SIGNAL ;
    PORT
      LAYER M3 ;
        RECT  52.524 53.856 52.542 54 ;
    END
  END kv[59]
  PIN kv[5]
    DIRECTION OUTPUT ;
    USE SIGNAL ;
    PORT
      LAYER M3 ;
        RECT  44.352 53.856 44.37 54 ;
    END
  END kv[5]
  PIN kv[60]
    DIRECTION OUTPUT ;
    USE SIGNAL ;
    PORT
      LAYER M5 ;
        RECT  52.704 53.808 52.728 54 ;
    END
  END kv[60]
  PIN kv[61]
    DIRECTION OUTPUT ;
    USE SIGNAL ;
    PORT
      LAYER M3 ;
        RECT  52.848 53.856 52.866 54 ;
    END
  END kv[61]
  PIN kv[62]
    DIRECTION OUTPUT ;
    USE SIGNAL ;
    PORT
      LAYER M5 ;
        RECT  52.992 53.808 53.016 54 ;
    END
  END kv[62]
  PIN kv[63]
    DIRECTION OUTPUT ;
    USE SIGNAL ;
    PORT
      LAYER M3 ;
        RECT  53.136 53.856 53.154 54 ;
    END
  END kv[63]
  PIN kv[64]
    DIRECTION OUTPUT ;
    USE SIGNAL ;
    PORT
      LAYER M5 ;
        RECT  53.28 53.808 53.304 54 ;
    END
  END kv[64]
  PIN kv[65]
    DIRECTION OUTPUT ;
    USE SIGNAL ;
    PORT
      LAYER M3 ;
        RECT  53.46 53.856 53.478 54 ;
    END
  END kv[65]
  PIN kv[66]
    DIRECTION OUTPUT ;
    USE SIGNAL ;
    PORT
      LAYER M5 ;
        RECT  53.616 53.808 53.64 54 ;
    END
  END kv[66]
  PIN kv[67]
    DIRECTION OUTPUT ;
    USE SIGNAL ;
    PORT
      LAYER M3 ;
        RECT  53.748 53.856 53.766 54 ;
    END
  END kv[67]
  PIN kv[68]
    DIRECTION OUTPUT ;
    USE SIGNAL ;
    PORT
      LAYER M5 ;
        RECT  53.904 53.808 53.928 54 ;
    END
  END kv[68]
  PIN kv[69]
    DIRECTION OUTPUT ;
    USE SIGNAL ;
    PORT
      LAYER M3 ;
        RECT  54.072 53.856 54.09 54 ;
    END
  END kv[69]
  PIN kv[6]
    DIRECTION OUTPUT ;
    USE SIGNAL ;
    PORT
      LAYER M5 ;
        RECT  44.496 53.808 44.52 54 ;
    END
  END kv[6]
  PIN kv[70]
    DIRECTION OUTPUT ;
    USE SIGNAL ;
    PORT
      LAYER M5 ;
        RECT  54.192 53.808 54.216 54 ;
    END
  END kv[70]
  PIN kv[71]
    DIRECTION OUTPUT ;
    USE SIGNAL ;
    PORT
      LAYER M3 ;
        RECT  54.36 53.856 54.378 54 ;
    END
  END kv[71]
  PIN kv[72]
    DIRECTION OUTPUT ;
    USE SIGNAL ;
    PORT
      LAYER M5 ;
        RECT  54.528 53.808 54.552 54 ;
    END
  END kv[72]
  PIN kv[73]
    DIRECTION OUTPUT ;
    USE SIGNAL ;
    PORT
      LAYER M3 ;
        RECT  54.648 53.856 54.666 54 ;
    END
  END kv[73]
  PIN kv[74]
    DIRECTION OUTPUT ;
    USE SIGNAL ;
    PORT
      LAYER M5 ;
        RECT  54.816 53.808 54.84 54 ;
    END
  END kv[74]
  PIN kv[75]
    DIRECTION OUTPUT ;
    USE SIGNAL ;
    PORT
      LAYER M3 ;
        RECT  54.972 53.856 54.99 54 ;
    END
  END kv[75]
  PIN kv[76]
    DIRECTION OUTPUT ;
    USE SIGNAL ;
    PORT
      LAYER M5 ;
        RECT  55.104 53.808 55.128 54 ;
    END
  END kv[76]
  PIN kv[77]
    DIRECTION OUTPUT ;
    USE SIGNAL ;
    PORT
      LAYER M3 ;
        RECT  55.26 53.856 55.278 54 ;
    END
  END kv[77]
  PIN kv[78]
    DIRECTION OUTPUT ;
    USE SIGNAL ;
    PORT
      LAYER M5 ;
        RECT  55.44 53.808 55.464 54 ;
    END
  END kv[78]
  PIN kv[79]
    DIRECTION OUTPUT ;
    USE SIGNAL ;
    PORT
      LAYER M3 ;
        RECT  55.584 53.856 55.602 54 ;
    END
  END kv[79]
  PIN kv[7]
    DIRECTION OUTPUT ;
    USE SIGNAL ;
    PORT
      LAYER M3 ;
        RECT  44.676 53.856 44.694 54 ;
    END
  END kv[7]
  PIN kv[80]
    DIRECTION OUTPUT ;
    USE SIGNAL ;
    PORT
      LAYER M5 ;
        RECT  55.728 53.808 55.752 54 ;
    END
  END kv[80]
  PIN kv[81]
    DIRECTION OUTPUT ;
    USE SIGNAL ;
    PORT
      LAYER M3 ;
        RECT  55.872 53.856 55.89 54 ;
    END
  END kv[81]
  PIN kv[82]
    DIRECTION OUTPUT ;
    USE SIGNAL ;
    PORT
      LAYER M5 ;
        RECT  56.016 53.808 56.04 54 ;
    END
  END kv[82]
  PIN kv[83]
    DIRECTION OUTPUT ;
    USE SIGNAL ;
    PORT
      LAYER M3 ;
        RECT  56.16 53.856 56.178 54 ;
    END
  END kv[83]
  PIN kv[84]
    DIRECTION OUTPUT ;
    USE SIGNAL ;
    PORT
      LAYER M5 ;
        RECT  56.304 53.808 56.328 54 ;
    END
  END kv[84]
  PIN kv[85]
    DIRECTION OUTPUT ;
    USE SIGNAL ;
    PORT
      LAYER M3 ;
        RECT  56.484 53.856 56.502 54 ;
    END
  END kv[85]
  PIN kv[86]
    DIRECTION OUTPUT ;
    USE SIGNAL ;
    PORT
      LAYER M5 ;
        RECT  56.64 53.808 56.664 54 ;
    END
  END kv[86]
  PIN kv[87]
    DIRECTION OUTPUT ;
    USE SIGNAL ;
    PORT
      LAYER M3 ;
        RECT  56.772 53.856 56.79 54 ;
    END
  END kv[87]
  PIN kv[88]
    DIRECTION OUTPUT ;
    USE SIGNAL ;
    PORT
      LAYER M5 ;
        RECT  56.928 53.808 56.952 54 ;
    END
  END kv[88]
  PIN kv[89]
    DIRECTION OUTPUT ;
    USE SIGNAL ;
    PORT
      LAYER M3 ;
        RECT  57.096 53.856 57.114 54 ;
    END
  END kv[89]
  PIN kv[8]
    DIRECTION OUTPUT ;
    USE SIGNAL ;
    PORT
      LAYER M5 ;
        RECT  44.832 53.808 44.856 54 ;
    END
  END kv[8]
  PIN kv[90]
    DIRECTION OUTPUT ;
    USE SIGNAL ;
    PORT
      LAYER M5 ;
        RECT  57.216 53.808 57.24 54 ;
    END
  END kv[90]
  PIN kv[91]
    DIRECTION OUTPUT ;
    USE SIGNAL ;
    PORT
      LAYER M3 ;
        RECT  57.384 53.856 57.402 54 ;
    END
  END kv[91]
  PIN kv[92]
    DIRECTION OUTPUT ;
    USE SIGNAL ;
    PORT
      LAYER M5 ;
        RECT  57.552 53.808 57.576 54 ;
    END
  END kv[92]
  PIN kv[93]
    DIRECTION OUTPUT ;
    USE SIGNAL ;
    PORT
      LAYER M3 ;
        RECT  57.708 53.856 57.726 54 ;
    END
  END kv[93]
  PIN kv[94]
    DIRECTION OUTPUT ;
    USE SIGNAL ;
    PORT
      LAYER M5 ;
        RECT  57.84 53.808 57.864 54 ;
    END
  END kv[94]
  PIN kv[95]
    DIRECTION OUTPUT ;
    USE SIGNAL ;
    PORT
      LAYER M3 ;
        RECT  57.996 53.856 58.014 54 ;
    END
  END kv[95]
  PIN kv[96]
    DIRECTION OUTPUT ;
    USE SIGNAL ;
    PORT
      LAYER M5 ;
        RECT  58.128 53.808 58.152 54 ;
    END
  END kv[96]
  PIN kv[97]
    DIRECTION OUTPUT ;
    USE SIGNAL ;
    PORT
      LAYER M3 ;
        RECT  58.284 53.856 58.302 54 ;
    END
  END kv[97]
  PIN kv[98]
    DIRECTION OUTPUT ;
    USE SIGNAL ;
    PORT
      LAYER M5 ;
        RECT  58.464 53.808 58.488 54 ;
    END
  END kv[98]
  PIN kv[99]
    DIRECTION OUTPUT ;
    USE SIGNAL ;
    PORT
      LAYER M3 ;
        RECT  58.608 53.856 58.626 54 ;
    END
  END kv[99]
  PIN kv[9]
    DIRECTION OUTPUT ;
    USE SIGNAL ;
    PORT
      LAYER M3 ;
        RECT  44.964 53.856 44.982 54 ;
    END
  END kv[9]
  PIN ov
    DIRECTION INPUT ;
    USE SIGNAL ;
    PORT
      LAYER M3 ;
        RECT  4.392 53.856 4.41 54 ;
    END
  END ov
  PIN ph
    DIRECTION OUTPUT ;
    USE SIGNAL ;
    PORT
      LAYER M3 ;
        RECT  4.68 53.856 4.698 54 ;
    END
  END ph
  PIN result[0]
    DIRECTION INPUT ;
    USE SIGNAL ;
    PORT
      LAYER M5 ;
        RECT  121.152 53.808 121.176 54 ;
    END
  END result[0]
  PIN result[100]
    DIRECTION INPUT ;
    USE SIGNAL ;
    PORT
      LAYER M5 ;
        RECT  136.272 53.808 136.296 54 ;
    END
  END result[100]
  PIN result[101]
    DIRECTION INPUT ;
    USE SIGNAL ;
    PORT
      LAYER M3 ;
        RECT  136.44 53.856 136.458 54 ;
    END
  END result[101]
  PIN result[102]
    DIRECTION INPUT ;
    USE SIGNAL ;
    PORT
      LAYER M5 ;
        RECT  136.56 53.808 136.584 54 ;
    END
  END result[102]
  PIN result[103]
    DIRECTION INPUT ;
    USE SIGNAL ;
    PORT
      LAYER M3 ;
        RECT  136.728 53.856 136.746 54 ;
    END
  END result[103]
  PIN result[104]
    DIRECTION INPUT ;
    USE SIGNAL ;
    PORT
      LAYER M5 ;
        RECT  136.896 53.808 136.92 54 ;
    END
  END result[104]
  PIN result[105]
    DIRECTION INPUT ;
    USE SIGNAL ;
    PORT
      LAYER M3 ;
        RECT  137.052 53.856 137.07 54 ;
    END
  END result[105]
  PIN result[106]
    DIRECTION INPUT ;
    USE SIGNAL ;
    PORT
      LAYER M5 ;
        RECT  137.184 53.808 137.208 54 ;
    END
  END result[106]
  PIN result[107]
    DIRECTION INPUT ;
    USE SIGNAL ;
    PORT
      LAYER M3 ;
        RECT  137.34 53.856 137.358 54 ;
    END
  END result[107]
  PIN result[108]
    DIRECTION INPUT ;
    USE SIGNAL ;
    PORT
      LAYER M5 ;
        RECT  137.472 53.808 137.496 54 ;
    END
  END result[108]
  PIN result[109]
    DIRECTION INPUT ;
    USE SIGNAL ;
    PORT
      LAYER M3 ;
        RECT  137.664 53.856 137.682 54 ;
    END
  END result[109]
  PIN result[10]
    DIRECTION INPUT ;
    USE SIGNAL ;
    PORT
      LAYER M5 ;
        RECT  122.64 53.808 122.664 54 ;
    END
  END result[10]
  PIN result[110]
    DIRECTION INPUT ;
    USE SIGNAL ;
    PORT
      LAYER M5 ;
        RECT  137.808 53.808 137.832 54 ;
    END
  END result[110]
  PIN result[111]
    DIRECTION INPUT ;
    USE SIGNAL ;
    PORT
      LAYER M3 ;
        RECT  137.952 53.856 137.97 54 ;
    END
  END result[111]
  PIN result[112]
    DIRECTION INPUT ;
    USE SIGNAL ;
    PORT
      LAYER M5 ;
        RECT  138.096 53.808 138.12 54 ;
    END
  END result[112]
  PIN result[113]
    DIRECTION INPUT ;
    USE SIGNAL ;
    PORT
      LAYER M3 ;
        RECT  138.24 53.856 138.258 54 ;
    END
  END result[113]
  PIN result[114]
    DIRECTION INPUT ;
    USE SIGNAL ;
    PORT
      LAYER M5 ;
        RECT  138.384 53.808 138.408 54 ;
    END
  END result[114]
  PIN result[115]
    DIRECTION INPUT ;
    USE SIGNAL ;
    PORT
      LAYER M3 ;
        RECT  138.564 53.856 138.582 54 ;
    END
  END result[115]
  PIN result[116]
    DIRECTION INPUT ;
    USE SIGNAL ;
    PORT
      LAYER M5 ;
        RECT  138.72 53.808 138.744 54 ;
    END
  END result[116]
  PIN result[117]
    DIRECTION INPUT ;
    USE SIGNAL ;
    PORT
      LAYER M3 ;
        RECT  138.852 53.856 138.87 54 ;
    END
  END result[117]
  PIN result[118]
    DIRECTION INPUT ;
    USE SIGNAL ;
    PORT
      LAYER M5 ;
        RECT  139.008 53.808 139.032 54 ;
    END
  END result[118]
  PIN result[119]
    DIRECTION INPUT ;
    USE SIGNAL ;
    PORT
      LAYER M3 ;
        RECT  139.176 53.856 139.194 54 ;
    END
  END result[119]
  PIN result[11]
    DIRECTION INPUT ;
    USE SIGNAL ;
    PORT
      LAYER M3 ;
        RECT  122.796 53.856 122.814 54 ;
    END
  END result[11]
  PIN result[120]
    DIRECTION INPUT ;
    USE SIGNAL ;
    PORT
      LAYER M5 ;
        RECT  139.296 53.808 139.32 54 ;
    END
  END result[120]
  PIN result[121]
    DIRECTION INPUT ;
    USE SIGNAL ;
    PORT
      LAYER M3 ;
        RECT  139.464 53.856 139.482 54 ;
    END
  END result[121]
  PIN result[122]
    DIRECTION INPUT ;
    USE SIGNAL ;
    PORT
      LAYER M5 ;
        RECT  139.632 53.808 139.656 54 ;
    END
  END result[122]
  PIN result[123]
    DIRECTION INPUT ;
    USE SIGNAL ;
    PORT
      LAYER M3 ;
        RECT  139.752 53.856 139.77 54 ;
    END
  END result[123]
  PIN result[124]
    DIRECTION INPUT ;
    USE SIGNAL ;
    PORT
      LAYER M5 ;
        RECT  139.92 53.808 139.944 54 ;
    END
  END result[124]
  PIN result[125]
    DIRECTION INPUT ;
    USE SIGNAL ;
    PORT
      LAYER M3 ;
        RECT  140.076 53.856 140.094 54 ;
    END
  END result[125]
  PIN result[126]
    DIRECTION INPUT ;
    USE SIGNAL ;
    PORT
      LAYER M5 ;
        RECT  140.208 53.808 140.232 54 ;
    END
  END result[126]
  PIN result[127]
    DIRECTION INPUT ;
    USE SIGNAL ;
    PORT
      LAYER M3 ;
        RECT  140.364 53.856 140.382 54 ;
    END
  END result[127]
  PIN result[128]
    DIRECTION INPUT ;
    USE SIGNAL ;
    PORT
      LAYER M5 ;
        RECT  140.544 53.808 140.568 54 ;
    END
  END result[128]
  PIN result[129]
    DIRECTION INPUT ;
    USE SIGNAL ;
    PORT
      LAYER M3 ;
        RECT  140.688 53.856 140.706 54 ;
    END
  END result[129]
  PIN result[12]
    DIRECTION INPUT ;
    USE SIGNAL ;
    PORT
      LAYER M5 ;
        RECT  122.976 53.808 123 54 ;
    END
  END result[12]
  PIN result[130]
    DIRECTION INPUT ;
    USE SIGNAL ;
    PORT
      LAYER M5 ;
        RECT  140.832 53.808 140.856 54 ;
    END
  END result[130]
  PIN result[131]
    DIRECTION INPUT ;
    USE SIGNAL ;
    PORT
      LAYER M3 ;
        RECT  140.976 53.856 140.994 54 ;
    END
  END result[131]
  PIN result[132]
    DIRECTION INPUT ;
    USE SIGNAL ;
    PORT
      LAYER M5 ;
        RECT  141.12 53.808 141.144 54 ;
    END
  END result[132]
  PIN result[133]
    DIRECTION INPUT ;
    USE SIGNAL ;
    PORT
      LAYER M3 ;
        RECT  141.264 53.856 141.282 54 ;
    END
  END result[133]
  PIN result[134]
    DIRECTION INPUT ;
    USE SIGNAL ;
    PORT
      LAYER M5 ;
        RECT  141.408 53.808 141.432 54 ;
    END
  END result[134]
  PIN result[135]
    DIRECTION INPUT ;
    USE SIGNAL ;
    PORT
      LAYER M3 ;
        RECT  141.588 53.856 141.606 54 ;
    END
  END result[135]
  PIN result[136]
    DIRECTION INPUT ;
    USE SIGNAL ;
    PORT
      LAYER M5 ;
        RECT  141.744 53.808 141.768 54 ;
    END
  END result[136]
  PIN result[137]
    DIRECTION INPUT ;
    USE SIGNAL ;
    PORT
      LAYER M3 ;
        RECT  141.876 53.856 141.894 54 ;
    END
  END result[137]
  PIN result[138]
    DIRECTION INPUT ;
    USE SIGNAL ;
    PORT
      LAYER M5 ;
        RECT  142.032 53.808 142.056 54 ;
    END
  END result[138]
  PIN result[139]
    DIRECTION INPUT ;
    USE SIGNAL ;
    PORT
      LAYER M3 ;
        RECT  142.2 53.856 142.218 54 ;
    END
  END result[139]
  PIN result[13]
    DIRECTION INPUT ;
    USE SIGNAL ;
    PORT
      LAYER M3 ;
        RECT  123.12 53.856 123.138 54 ;
    END
  END result[13]
  PIN result[140]
    DIRECTION INPUT ;
    USE SIGNAL ;
    PORT
      LAYER M5 ;
        RECT  142.32 53.808 142.344 54 ;
    END
  END result[140]
  PIN result[141]
    DIRECTION INPUT ;
    USE SIGNAL ;
    PORT
      LAYER M3 ;
        RECT  142.488 53.856 142.506 54 ;
    END
  END result[141]
  PIN result[142]
    DIRECTION INPUT ;
    USE SIGNAL ;
    PORT
      LAYER M5 ;
        RECT  142.656 53.808 142.68 54 ;
    END
  END result[142]
  PIN result[143]
    DIRECTION INPUT ;
    USE SIGNAL ;
    PORT
      LAYER M3 ;
        RECT  142.812 53.856 142.83 54 ;
    END
  END result[143]
  PIN result[144]
    DIRECTION INPUT ;
    USE SIGNAL ;
    PORT
      LAYER M5 ;
        RECT  142.944 53.808 142.968 54 ;
    END
  END result[144]
  PIN result[145]
    DIRECTION INPUT ;
    USE SIGNAL ;
    PORT
      LAYER M3 ;
        RECT  143.1 53.856 143.118 54 ;
    END
  END result[145]
  PIN result[146]
    DIRECTION INPUT ;
    USE SIGNAL ;
    PORT
      LAYER M5 ;
        RECT  143.232 53.808 143.256 54 ;
    END
  END result[146]
  PIN result[147]
    DIRECTION INPUT ;
    USE SIGNAL ;
    PORT
      LAYER M3 ;
        RECT  143.388 53.856 143.406 54 ;
    END
  END result[147]
  PIN result[148]
    DIRECTION INPUT ;
    USE SIGNAL ;
    PORT
      LAYER M5 ;
        RECT  143.568 53.808 143.592 54 ;
    END
  END result[148]
  PIN result[149]
    DIRECTION INPUT ;
    USE SIGNAL ;
    PORT
      LAYER M3 ;
        RECT  143.712 53.856 143.73 54 ;
    END
  END result[149]
  PIN result[14]
    DIRECTION INPUT ;
    USE SIGNAL ;
    PORT
      LAYER M5 ;
        RECT  123.264 53.808 123.288 54 ;
    END
  END result[14]
  PIN result[150]
    DIRECTION INPUT ;
    USE SIGNAL ;
    PORT
      LAYER M5 ;
        RECT  143.856 53.808 143.88 54 ;
    END
  END result[150]
  PIN result[151]
    DIRECTION INPUT ;
    USE SIGNAL ;
    PORT
      LAYER M3 ;
        RECT  144 53.856 144.018 54 ;
    END
  END result[151]
  PIN result[152]
    DIRECTION INPUT ;
    USE SIGNAL ;
    PORT
      LAYER M5 ;
        RECT  144.144 53.808 144.168 54 ;
    END
  END result[152]
  PIN result[153]
    DIRECTION INPUT ;
    USE SIGNAL ;
    PORT
      LAYER M3 ;
        RECT  144.324 53.856 144.342 54 ;
    END
  END result[153]
  PIN result[154]
    DIRECTION INPUT ;
    USE SIGNAL ;
    PORT
      LAYER M5 ;
        RECT  144.48 53.808 144.504 54 ;
    END
  END result[154]
  PIN result[155]
    DIRECTION INPUT ;
    USE SIGNAL ;
    PORT
      LAYER M3 ;
        RECT  144.612 53.856 144.63 54 ;
    END
  END result[155]
  PIN result[156]
    DIRECTION INPUT ;
    USE SIGNAL ;
    PORT
      LAYER M5 ;
        RECT  144.768 53.808 144.792 54 ;
    END
  END result[156]
  PIN result[157]
    DIRECTION INPUT ;
    USE SIGNAL ;
    PORT
      LAYER M3 ;
        RECT  144.9 53.856 144.918 54 ;
    END
  END result[157]
  PIN result[158]
    DIRECTION INPUT ;
    USE SIGNAL ;
    PORT
      LAYER M5 ;
        RECT  145.056 53.808 145.08 54 ;
    END
  END result[158]
  PIN result[159]
    DIRECTION INPUT ;
    USE SIGNAL ;
    PORT
      LAYER M3 ;
        RECT  145.224 53.856 145.242 54 ;
    END
  END result[159]
  PIN result[15]
    DIRECTION INPUT ;
    USE SIGNAL ;
    PORT
      LAYER M3 ;
        RECT  123.408 53.856 123.426 54 ;
    END
  END result[15]
  PIN result[160]
    DIRECTION INPUT ;
    USE SIGNAL ;
    PORT
      LAYER M5 ;
        RECT  145.344 53.808 145.368 54 ;
    END
  END result[160]
  PIN result[161]
    DIRECTION INPUT ;
    USE SIGNAL ;
    PORT
      LAYER M3 ;
        RECT  145.512 53.856 145.53 54 ;
    END
  END result[161]
  PIN result[162]
    DIRECTION INPUT ;
    USE SIGNAL ;
    PORT
      LAYER M5 ;
        RECT  145.68 53.808 145.704 54 ;
    END
  END result[162]
  PIN result[163]
    DIRECTION INPUT ;
    USE SIGNAL ;
    PORT
      LAYER M3 ;
        RECT  145.836 53.856 145.854 54 ;
    END
  END result[163]
  PIN result[164]
    DIRECTION INPUT ;
    USE SIGNAL ;
    PORT
      LAYER M5 ;
        RECT  145.968 53.808 145.992 54 ;
    END
  END result[164]
  PIN result[165]
    DIRECTION INPUT ;
    USE SIGNAL ;
    PORT
      LAYER M3 ;
        RECT  146.124 53.856 146.142 54 ;
    END
  END result[165]
  PIN result[166]
    DIRECTION INPUT ;
    USE SIGNAL ;
    PORT
      LAYER M5 ;
        RECT  146.256 53.808 146.28 54 ;
    END
  END result[166]
  PIN result[167]
    DIRECTION INPUT ;
    USE SIGNAL ;
    PORT
      LAYER M3 ;
        RECT  146.412 53.856 146.43 54 ;
    END
  END result[167]
  PIN result[168]
    DIRECTION INPUT ;
    USE SIGNAL ;
    PORT
      LAYER M5 ;
        RECT  146.592 53.808 146.616 54 ;
    END
  END result[168]
  PIN result[169]
    DIRECTION INPUT ;
    USE SIGNAL ;
    PORT
      LAYER M3 ;
        RECT  146.736 53.856 146.754 54 ;
    END
  END result[169]
  PIN result[16]
    DIRECTION INPUT ;
    USE SIGNAL ;
    PORT
      LAYER M5 ;
        RECT  123.552 53.808 123.576 54 ;
    END
  END result[16]
  PIN result[170]
    DIRECTION INPUT ;
    USE SIGNAL ;
    PORT
      LAYER M5 ;
        RECT  146.88 53.808 146.904 54 ;
    END
  END result[170]
  PIN result[171]
    DIRECTION INPUT ;
    USE SIGNAL ;
    PORT
      LAYER M3 ;
        RECT  147.024 53.856 147.042 54 ;
    END
  END result[171]
  PIN result[172]
    DIRECTION INPUT ;
    USE SIGNAL ;
    PORT
      LAYER M5 ;
        RECT  147.168 53.808 147.192 54 ;
    END
  END result[172]
  PIN result[173]
    DIRECTION INPUT ;
    USE SIGNAL ;
    PORT
      LAYER M3 ;
        RECT  147.348 53.856 147.366 54 ;
    END
  END result[173]
  PIN result[174]
    DIRECTION INPUT ;
    USE SIGNAL ;
    PORT
      LAYER M5 ;
        RECT  147.504 53.808 147.528 54 ;
    END
  END result[174]
  PIN result[175]
    DIRECTION INPUT ;
    USE SIGNAL ;
    PORT
      LAYER M3 ;
        RECT  147.636 53.856 147.654 54 ;
    END
  END result[175]
  PIN result[176]
    DIRECTION INPUT ;
    USE SIGNAL ;
    PORT
      LAYER M5 ;
        RECT  147.792 53.808 147.816 54 ;
    END
  END result[176]
  PIN result[177]
    DIRECTION INPUT ;
    USE SIGNAL ;
    PORT
      LAYER M3 ;
        RECT  147.96 53.856 147.978 54 ;
    END
  END result[177]
  PIN result[178]
    DIRECTION INPUT ;
    USE SIGNAL ;
    PORT
      LAYER M5 ;
        RECT  148.08 53.808 148.104 54 ;
    END
  END result[178]
  PIN result[179]
    DIRECTION INPUT ;
    USE SIGNAL ;
    PORT
      LAYER M3 ;
        RECT  148.248 53.856 148.266 54 ;
    END
  END result[179]
  PIN result[17]
    DIRECTION INPUT ;
    USE SIGNAL ;
    PORT
      LAYER M3 ;
        RECT  123.732 53.856 123.75 54 ;
    END
  END result[17]
  PIN result[180]
    DIRECTION INPUT ;
    USE SIGNAL ;
    PORT
      LAYER M5 ;
        RECT  148.416 53.808 148.44 54 ;
    END
  END result[180]
  PIN result[181]
    DIRECTION INPUT ;
    USE SIGNAL ;
    PORT
      LAYER M3 ;
        RECT  148.536 53.856 148.554 54 ;
    END
  END result[181]
  PIN result[182]
    DIRECTION INPUT ;
    USE SIGNAL ;
    PORT
      LAYER M5 ;
        RECT  148.704 53.808 148.728 54 ;
    END
  END result[182]
  PIN result[183]
    DIRECTION INPUT ;
    USE SIGNAL ;
    PORT
      LAYER M3 ;
        RECT  148.86 53.856 148.878 54 ;
    END
  END result[183]
  PIN result[184]
    DIRECTION INPUT ;
    USE SIGNAL ;
    PORT
      LAYER M5 ;
        RECT  148.992 53.808 149.016 54 ;
    END
  END result[184]
  PIN result[185]
    DIRECTION INPUT ;
    USE SIGNAL ;
    PORT
      LAYER M3 ;
        RECT  149.148 53.856 149.166 54 ;
    END
  END result[185]
  PIN result[186]
    DIRECTION INPUT ;
    USE SIGNAL ;
    PORT
      LAYER M5 ;
        RECT  149.28 53.808 149.304 54 ;
    END
  END result[186]
  PIN result[187]
    DIRECTION INPUT ;
    USE SIGNAL ;
    PORT
      LAYER M3 ;
        RECT  149.472 53.856 149.49 54 ;
    END
  END result[187]
  PIN result[188]
    DIRECTION INPUT ;
    USE SIGNAL ;
    PORT
      LAYER M5 ;
        RECT  149.616 53.808 149.64 54 ;
    END
  END result[188]
  PIN result[189]
    DIRECTION INPUT ;
    USE SIGNAL ;
    PORT
      LAYER M3 ;
        RECT  149.76 53.856 149.778 54 ;
    END
  END result[189]
  PIN result[18]
    DIRECTION INPUT ;
    USE SIGNAL ;
    PORT
      LAYER M5 ;
        RECT  123.84 53.808 123.864 54 ;
    END
  END result[18]
  PIN result[190]
    DIRECTION INPUT ;
    USE SIGNAL ;
    PORT
      LAYER M5 ;
        RECT  149.904 53.808 149.928 54 ;
    END
  END result[190]
  PIN result[191]
    DIRECTION INPUT ;
    USE SIGNAL ;
    PORT
      LAYER M3 ;
        RECT  150.048 53.856 150.066 54 ;
    END
  END result[191]
  PIN result[192]
    DIRECTION INPUT ;
    USE SIGNAL ;
    PORT
      LAYER M5 ;
        RECT  150.192 53.808 150.216 54 ;
    END
  END result[192]
  PIN result[193]
    DIRECTION INPUT ;
    USE SIGNAL ;
    PORT
      LAYER M3 ;
        RECT  150.372 53.856 150.39 54 ;
    END
  END result[193]
  PIN result[194]
    DIRECTION INPUT ;
    USE SIGNAL ;
    PORT
      LAYER M5 ;
        RECT  150.528 53.808 150.552 54 ;
    END
  END result[194]
  PIN result[195]
    DIRECTION INPUT ;
    USE SIGNAL ;
    PORT
      LAYER M3 ;
        RECT  150.66 53.856 150.678 54 ;
    END
  END result[195]
  PIN result[196]
    DIRECTION INPUT ;
    USE SIGNAL ;
    PORT
      LAYER M5 ;
        RECT  150.816 53.808 150.84 54 ;
    END
  END result[196]
  PIN result[197]
    DIRECTION INPUT ;
    USE SIGNAL ;
    PORT
      LAYER M3 ;
        RECT  150.984 53.856 151.002 54 ;
    END
  END result[197]
  PIN result[198]
    DIRECTION INPUT ;
    USE SIGNAL ;
    PORT
      LAYER M5 ;
        RECT  151.104 53.808 151.128 54 ;
    END
  END result[198]
  PIN result[199]
    DIRECTION INPUT ;
    USE SIGNAL ;
    PORT
      LAYER M3 ;
        RECT  151.272 53.856 151.29 54 ;
    END
  END result[199]
  PIN result[19]
    DIRECTION INPUT ;
    USE SIGNAL ;
    PORT
      LAYER M3 ;
        RECT  124.02 53.856 124.038 54 ;
    END
  END result[19]
  PIN result[1]
    DIRECTION INPUT ;
    USE SIGNAL ;
    PORT
      LAYER M3 ;
        RECT  121.284 53.856 121.302 54 ;
    END
  END result[1]
  PIN result[200]
    DIRECTION INPUT ;
    USE SIGNAL ;
    PORT
      LAYER M5 ;
        RECT  151.44 53.808 151.464 54 ;
    END
  END result[200]
  PIN result[201]
    DIRECTION INPUT ;
    USE SIGNAL ;
    PORT
      LAYER M3 ;
        RECT  151.56 53.856 151.578 54 ;
    END
  END result[201]
  PIN result[202]
    DIRECTION INPUT ;
    USE SIGNAL ;
    PORT
      LAYER M5 ;
        RECT  151.728 53.808 151.752 54 ;
    END
  END result[202]
  PIN result[203]
    DIRECTION INPUT ;
    USE SIGNAL ;
    PORT
      LAYER M3 ;
        RECT  151.884 53.856 151.902 54 ;
    END
  END result[203]
  PIN result[204]
    DIRECTION INPUT ;
    USE SIGNAL ;
    PORT
      LAYER M5 ;
        RECT  152.016 53.808 152.04 54 ;
    END
  END result[204]
  PIN result[205]
    DIRECTION INPUT ;
    USE SIGNAL ;
    PORT
      LAYER M3 ;
        RECT  152.172 53.856 152.19 54 ;
    END
  END result[205]
  PIN result[206]
    DIRECTION INPUT ;
    USE SIGNAL ;
    PORT
      LAYER M5 ;
        RECT  152.352 53.808 152.376 54 ;
    END
  END result[206]
  PIN result[207]
    DIRECTION INPUT ;
    USE SIGNAL ;
    PORT
      LAYER M3 ;
        RECT  152.496 53.856 152.514 54 ;
    END
  END result[207]
  PIN result[208]
    DIRECTION INPUT ;
    USE SIGNAL ;
    PORT
      LAYER M5 ;
        RECT  152.64 53.808 152.664 54 ;
    END
  END result[208]
  PIN result[209]
    DIRECTION INPUT ;
    USE SIGNAL ;
    PORT
      LAYER M3 ;
        RECT  152.784 53.856 152.802 54 ;
    END
  END result[209]
  PIN result[20]
    DIRECTION INPUT ;
    USE SIGNAL ;
    PORT
      LAYER M5 ;
        RECT  124.176 53.808 124.2 54 ;
    END
  END result[20]
  PIN result[210]
    DIRECTION INPUT ;
    USE SIGNAL ;
    PORT
      LAYER M5 ;
        RECT  152.928 53.808 152.952 54 ;
    END
  END result[210]
  PIN result[211]
    DIRECTION INPUT ;
    USE SIGNAL ;
    PORT
      LAYER M3 ;
        RECT  153.108 53.856 153.126 54 ;
    END
  END result[211]
  PIN result[212]
    DIRECTION INPUT ;
    USE SIGNAL ;
    PORT
      LAYER M5 ;
        RECT  153.264 53.808 153.288 54 ;
    END
  END result[212]
  PIN result[213]
    DIRECTION INPUT ;
    USE SIGNAL ;
    PORT
      LAYER M3 ;
        RECT  153.396 53.856 153.414 54 ;
    END
  END result[213]
  PIN result[214]
    DIRECTION INPUT ;
    USE SIGNAL ;
    PORT
      LAYER M5 ;
        RECT  153.552 53.808 153.576 54 ;
    END
  END result[214]
  PIN result[215]
    DIRECTION INPUT ;
    USE SIGNAL ;
    PORT
      LAYER M3 ;
        RECT  153.684 53.856 153.702 54 ;
    END
  END result[215]
  PIN result[216]
    DIRECTION INPUT ;
    USE SIGNAL ;
    PORT
      LAYER M5 ;
        RECT  153.84 53.808 153.864 54 ;
    END
  END result[216]
  PIN result[217]
    DIRECTION INPUT ;
    USE SIGNAL ;
    PORT
      LAYER M3 ;
        RECT  154.008 53.856 154.026 54 ;
    END
  END result[217]
  PIN result[218]
    DIRECTION INPUT ;
    USE SIGNAL ;
    PORT
      LAYER M5 ;
        RECT  154.128 53.808 154.152 54 ;
    END
  END result[218]
  PIN result[219]
    DIRECTION INPUT ;
    USE SIGNAL ;
    PORT
      LAYER M3 ;
        RECT  154.296 53.856 154.314 54 ;
    END
  END result[219]
  PIN result[21]
    DIRECTION INPUT ;
    USE SIGNAL ;
    PORT
      LAYER M3 ;
        RECT  124.308 53.856 124.326 54 ;
    END
  END result[21]
  PIN result[220]
    DIRECTION INPUT ;
    USE SIGNAL ;
    PORT
      LAYER M5 ;
        RECT  154.464 53.808 154.488 54 ;
    END
  END result[220]
  PIN result[221]
    DIRECTION INPUT ;
    USE SIGNAL ;
    PORT
      LAYER M3 ;
        RECT  154.62 53.856 154.638 54 ;
    END
  END result[221]
  PIN result[222]
    DIRECTION INPUT ;
    USE SIGNAL ;
    PORT
      LAYER M5 ;
        RECT  154.752 53.808 154.776 54 ;
    END
  END result[222]
  PIN result[223]
    DIRECTION INPUT ;
    USE SIGNAL ;
    PORT
      LAYER M3 ;
        RECT  154.908 53.856 154.926 54 ;
    END
  END result[223]
  PIN result[224]
    DIRECTION INPUT ;
    USE SIGNAL ;
    PORT
      LAYER M5 ;
        RECT  155.04 53.808 155.064 54 ;
    END
  END result[224]
  PIN result[225]
    DIRECTION INPUT ;
    USE SIGNAL ;
    PORT
      LAYER M3 ;
        RECT  155.196 53.856 155.214 54 ;
    END
  END result[225]
  PIN result[226]
    DIRECTION INPUT ;
    USE SIGNAL ;
    PORT
      LAYER M5 ;
        RECT  155.376 53.808 155.4 54 ;
    END
  END result[226]
  PIN result[227]
    DIRECTION INPUT ;
    USE SIGNAL ;
    PORT
      LAYER M3 ;
        RECT  155.52 53.856 155.538 54 ;
    END
  END result[227]
  PIN result[228]
    DIRECTION INPUT ;
    USE SIGNAL ;
    PORT
      LAYER M5 ;
        RECT  155.664 53.808 155.688 54 ;
    END
  END result[228]
  PIN result[229]
    DIRECTION INPUT ;
    USE SIGNAL ;
    PORT
      LAYER M3 ;
        RECT  155.808 53.856 155.826 54 ;
    END
  END result[229]
  PIN result[22]
    DIRECTION INPUT ;
    USE SIGNAL ;
    PORT
      LAYER M5 ;
        RECT  124.464 53.808 124.488 54 ;
    END
  END result[22]
  PIN result[230]
    DIRECTION INPUT ;
    USE SIGNAL ;
    PORT
      LAYER M5 ;
        RECT  155.952 53.808 155.976 54 ;
    END
  END result[230]
  PIN result[231]
    DIRECTION INPUT ;
    USE SIGNAL ;
    PORT
      LAYER M3 ;
        RECT  156.132 53.856 156.15 54 ;
    END
  END result[231]
  PIN result[232]
    DIRECTION INPUT ;
    USE SIGNAL ;
    PORT
      LAYER M5 ;
        RECT  156.288 53.808 156.312 54 ;
    END
  END result[232]
  PIN result[233]
    DIRECTION INPUT ;
    USE SIGNAL ;
    PORT
      LAYER M3 ;
        RECT  156.42 53.856 156.438 54 ;
    END
  END result[233]
  PIN result[234]
    DIRECTION INPUT ;
    USE SIGNAL ;
    PORT
      LAYER M5 ;
        RECT  156.576 53.808 156.6 54 ;
    END
  END result[234]
  PIN result[235]
    DIRECTION INPUT ;
    USE SIGNAL ;
    PORT
      LAYER M3 ;
        RECT  156.744 53.856 156.762 54 ;
    END
  END result[235]
  PIN result[236]
    DIRECTION INPUT ;
    USE SIGNAL ;
    PORT
      LAYER M5 ;
        RECT  156.864 53.808 156.888 54 ;
    END
  END result[236]
  PIN result[237]
    DIRECTION INPUT ;
    USE SIGNAL ;
    PORT
      LAYER M3 ;
        RECT  157.032 53.856 157.05 54 ;
    END
  END result[237]
  PIN result[238]
    DIRECTION INPUT ;
    USE SIGNAL ;
    PORT
      LAYER M5 ;
        RECT  157.2 53.808 157.224 54 ;
    END
  END result[238]
  PIN result[239]
    DIRECTION INPUT ;
    USE SIGNAL ;
    PORT
      LAYER M3 ;
        RECT  157.32 53.856 157.338 54 ;
    END
  END result[239]
  PIN result[23]
    DIRECTION INPUT ;
    USE SIGNAL ;
    PORT
      LAYER M3 ;
        RECT  124.632 53.856 124.65 54 ;
    END
  END result[23]
  PIN result[240]
    DIRECTION INPUT ;
    USE SIGNAL ;
    PORT
      LAYER M5 ;
        RECT  157.488 53.808 157.512 54 ;
    END
  END result[240]
  PIN result[241]
    DIRECTION INPUT ;
    USE SIGNAL ;
    PORT
      LAYER M3 ;
        RECT  157.644 53.856 157.662 54 ;
    END
  END result[241]
  PIN result[242]
    DIRECTION INPUT ;
    USE SIGNAL ;
    PORT
      LAYER M5 ;
        RECT  157.776 53.808 157.8 54 ;
    END
  END result[242]
  PIN result[243]
    DIRECTION INPUT ;
    USE SIGNAL ;
    PORT
      LAYER M3 ;
        RECT  157.932 53.856 157.95 54 ;
    END
  END result[243]
  PIN result[244]
    DIRECTION INPUT ;
    USE SIGNAL ;
    PORT
      LAYER M5 ;
        RECT  158.064 53.808 158.088 54 ;
    END
  END result[244]
  PIN result[245]
    DIRECTION INPUT ;
    USE SIGNAL ;
    PORT
      LAYER M3 ;
        RECT  158.256 53.856 158.274 54 ;
    END
  END result[245]
  PIN result[246]
    DIRECTION INPUT ;
    USE SIGNAL ;
    PORT
      LAYER M5 ;
        RECT  158.4 53.808 158.424 54 ;
    END
  END result[246]
  PIN result[247]
    DIRECTION INPUT ;
    USE SIGNAL ;
    PORT
      LAYER M3 ;
        RECT  158.544 53.856 158.562 54 ;
    END
  END result[247]
  PIN result[248]
    DIRECTION INPUT ;
    USE SIGNAL ;
    PORT
      LAYER M5 ;
        RECT  158.688 53.808 158.712 54 ;
    END
  END result[248]
  PIN result[249]
    DIRECTION INPUT ;
    USE SIGNAL ;
    PORT
      LAYER M3 ;
        RECT  158.832 53.856 158.85 54 ;
    END
  END result[249]
  PIN result[24]
    DIRECTION INPUT ;
    USE SIGNAL ;
    PORT
      LAYER M5 ;
        RECT  124.752 53.808 124.776 54 ;
    END
  END result[24]
  PIN result[250]
    DIRECTION INPUT ;
    USE SIGNAL ;
    PORT
      LAYER M5 ;
        RECT  158.976 53.808 159 54 ;
    END
  END result[250]
  PIN result[251]
    DIRECTION INPUT ;
    USE SIGNAL ;
    PORT
      LAYER M3 ;
        RECT  159.156 53.856 159.174 54 ;
    END
  END result[251]
  PIN result[252]
    DIRECTION INPUT ;
    USE SIGNAL ;
    PORT
      LAYER M5 ;
        RECT  159.312 53.808 159.336 54 ;
    END
  END result[252]
  PIN result[253]
    DIRECTION INPUT ;
    USE SIGNAL ;
    PORT
      LAYER M3 ;
        RECT  159.444 53.856 159.462 54 ;
    END
  END result[253]
  PIN result[254]
    DIRECTION INPUT ;
    USE SIGNAL ;
    PORT
      LAYER M5 ;
        RECT  159.6 53.808 159.624 54 ;
    END
  END result[254]
  PIN result[255]
    DIRECTION INPUT ;
    USE SIGNAL ;
    PORT
      LAYER M3 ;
        RECT  159.768 53.856 159.786 54 ;
    END
  END result[255]
  PIN result[25]
    DIRECTION INPUT ;
    USE SIGNAL ;
    PORT
      LAYER M3 ;
        RECT  124.92 53.856 124.938 54 ;
    END
  END result[25]
  PIN result[26]
    DIRECTION INPUT ;
    USE SIGNAL ;
    PORT
      LAYER M5 ;
        RECT  125.088 53.808 125.112 54 ;
    END
  END result[26]
  PIN result[27]
    DIRECTION INPUT ;
    USE SIGNAL ;
    PORT
      LAYER M3 ;
        RECT  125.244 53.856 125.262 54 ;
    END
  END result[27]
  PIN result[28]
    DIRECTION INPUT ;
    USE SIGNAL ;
    PORT
      LAYER M5 ;
        RECT  125.376 53.808 125.4 54 ;
    END
  END result[28]
  PIN result[29]
    DIRECTION INPUT ;
    USE SIGNAL ;
    PORT
      LAYER M3 ;
        RECT  125.532 53.856 125.55 54 ;
    END
  END result[29]
  PIN result[2]
    DIRECTION INPUT ;
    USE SIGNAL ;
    PORT
      LAYER M5 ;
        RECT  121.44 53.808 121.464 54 ;
    END
  END result[2]
  PIN result[30]
    DIRECTION INPUT ;
    USE SIGNAL ;
    PORT
      LAYER M5 ;
        RECT  125.664 53.808 125.688 54 ;
    END
  END result[30]
  PIN result[31]
    DIRECTION INPUT ;
    USE SIGNAL ;
    PORT
      LAYER M3 ;
        RECT  125.82 53.856 125.838 54 ;
    END
  END result[31]
  PIN result[32]
    DIRECTION INPUT ;
    USE SIGNAL ;
    PORT
      LAYER M5 ;
        RECT  126 53.808 126.024 54 ;
    END
  END result[32]
  PIN result[33]
    DIRECTION INPUT ;
    USE SIGNAL ;
    PORT
      LAYER M3 ;
        RECT  126.144 53.856 126.162 54 ;
    END
  END result[33]
  PIN result[34]
    DIRECTION INPUT ;
    USE SIGNAL ;
    PORT
      LAYER M5 ;
        RECT  126.288 53.808 126.312 54 ;
    END
  END result[34]
  PIN result[35]
    DIRECTION INPUT ;
    USE SIGNAL ;
    PORT
      LAYER M3 ;
        RECT  126.432 53.856 126.45 54 ;
    END
  END result[35]
  PIN result[36]
    DIRECTION INPUT ;
    USE SIGNAL ;
    PORT
      LAYER M5 ;
        RECT  126.576 53.808 126.6 54 ;
    END
  END result[36]
  PIN result[37]
    DIRECTION INPUT ;
    USE SIGNAL ;
    PORT
      LAYER M3 ;
        RECT  126.756 53.856 126.774 54 ;
    END
  END result[37]
  PIN result[38]
    DIRECTION INPUT ;
    USE SIGNAL ;
    PORT
      LAYER M5 ;
        RECT  126.912 53.808 126.936 54 ;
    END
  END result[38]
  PIN result[39]
    DIRECTION INPUT ;
    USE SIGNAL ;
    PORT
      LAYER M3 ;
        RECT  127.044 53.856 127.062 54 ;
    END
  END result[39]
  PIN result[3]
    DIRECTION INPUT ;
    USE SIGNAL ;
    PORT
      LAYER M3 ;
        RECT  121.608 53.856 121.626 54 ;
    END
  END result[3]
  PIN result[40]
    DIRECTION INPUT ;
    USE SIGNAL ;
    PORT
      LAYER M5 ;
        RECT  127.2 53.808 127.224 54 ;
    END
  END result[40]
  PIN result[41]
    DIRECTION INPUT ;
    USE SIGNAL ;
    PORT
      LAYER M3 ;
        RECT  127.332 53.856 127.35 54 ;
    END
  END result[41]
  PIN result[42]
    DIRECTION INPUT ;
    USE SIGNAL ;
    PORT
      LAYER M5 ;
        RECT  127.488 53.808 127.512 54 ;
    END
  END result[42]
  PIN result[43]
    DIRECTION INPUT ;
    USE SIGNAL ;
    PORT
      LAYER M3 ;
        RECT  127.656 53.856 127.674 54 ;
    END
  END result[43]
  PIN result[44]
    DIRECTION INPUT ;
    USE SIGNAL ;
    PORT
      LAYER M5 ;
        RECT  127.824 53.808 127.848 54 ;
    END
  END result[44]
  PIN result[45]
    DIRECTION INPUT ;
    USE SIGNAL ;
    PORT
      LAYER M3 ;
        RECT  127.944 53.856 127.962 54 ;
    END
  END result[45]
  PIN result[46]
    DIRECTION INPUT ;
    USE SIGNAL ;
    PORT
      LAYER M5 ;
        RECT  128.112 53.808 128.136 54 ;
    END
  END result[46]
  PIN result[47]
    DIRECTION INPUT ;
    USE SIGNAL ;
    PORT
      LAYER M3 ;
        RECT  128.268 53.856 128.286 54 ;
    END
  END result[47]
  PIN result[48]
    DIRECTION INPUT ;
    USE SIGNAL ;
    PORT
      LAYER M5 ;
        RECT  128.4 53.808 128.424 54 ;
    END
  END result[48]
  PIN result[49]
    DIRECTION INPUT ;
    USE SIGNAL ;
    PORT
      LAYER M3 ;
        RECT  128.556 53.856 128.574 54 ;
    END
  END result[49]
  PIN result[4]
    DIRECTION INPUT ;
    USE SIGNAL ;
    PORT
      LAYER M5 ;
        RECT  121.728 53.808 121.752 54 ;
    END
  END result[4]
  PIN result[50]
    DIRECTION INPUT ;
    USE SIGNAL ;
    PORT
      LAYER M5 ;
        RECT  128.688 53.808 128.712 54 ;
    END
  END result[50]
  PIN result[51]
    DIRECTION INPUT ;
    USE SIGNAL ;
    PORT
      LAYER M3 ;
        RECT  128.88 53.856 128.898 54 ;
    END
  END result[51]
  PIN result[52]
    DIRECTION INPUT ;
    USE SIGNAL ;
    PORT
      LAYER M5 ;
        RECT  129.024 53.808 129.048 54 ;
    END
  END result[52]
  PIN result[53]
    DIRECTION INPUT ;
    USE SIGNAL ;
    PORT
      LAYER M3 ;
        RECT  129.168 53.856 129.186 54 ;
    END
  END result[53]
  PIN result[54]
    DIRECTION INPUT ;
    USE SIGNAL ;
    PORT
      LAYER M5 ;
        RECT  129.312 53.808 129.336 54 ;
    END
  END result[54]
  PIN result[55]
    DIRECTION INPUT ;
    USE SIGNAL ;
    PORT
      LAYER M3 ;
        RECT  129.456 53.856 129.474 54 ;
    END
  END result[55]
  PIN result[56]
    DIRECTION INPUT ;
    USE SIGNAL ;
    PORT
      LAYER M5 ;
        RECT  129.6 53.808 129.624 54 ;
    END
  END result[56]
  PIN result[57]
    DIRECTION INPUT ;
    USE SIGNAL ;
    PORT
      LAYER M3 ;
        RECT  129.78 53.856 129.798 54 ;
    END
  END result[57]
  PIN result[58]
    DIRECTION INPUT ;
    USE SIGNAL ;
    PORT
      LAYER M5 ;
        RECT  129.936 53.808 129.96 54 ;
    END
  END result[58]
  PIN result[59]
    DIRECTION INPUT ;
    USE SIGNAL ;
    PORT
      LAYER M3 ;
        RECT  130.068 53.856 130.086 54 ;
    END
  END result[59]
  PIN result[5]
    DIRECTION INPUT ;
    USE SIGNAL ;
    PORT
      LAYER M3 ;
        RECT  121.896 53.856 121.914 54 ;
    END
  END result[5]
  PIN result[60]
    DIRECTION INPUT ;
    USE SIGNAL ;
    PORT
      LAYER M5 ;
        RECT  130.224 53.808 130.248 54 ;
    END
  END result[60]
  PIN result[61]
    DIRECTION INPUT ;
    USE SIGNAL ;
    PORT
      LAYER M3 ;
        RECT  130.392 53.856 130.41 54 ;
    END
  END result[61]
  PIN result[62]
    DIRECTION INPUT ;
    USE SIGNAL ;
    PORT
      LAYER M5 ;
        RECT  130.512 53.808 130.536 54 ;
    END
  END result[62]
  PIN result[63]
    DIRECTION INPUT ;
    USE SIGNAL ;
    PORT
      LAYER M3 ;
        RECT  130.68 53.856 130.698 54 ;
    END
  END result[63]
  PIN result[64]
    DIRECTION INPUT ;
    USE SIGNAL ;
    PORT
      LAYER M5 ;
        RECT  130.848 53.808 130.872 54 ;
    END
  END result[64]
  PIN result[65]
    DIRECTION INPUT ;
    USE SIGNAL ;
    PORT
      LAYER M3 ;
        RECT  130.968 53.856 130.986 54 ;
    END
  END result[65]
  PIN result[66]
    DIRECTION INPUT ;
    USE SIGNAL ;
    PORT
      LAYER M5 ;
        RECT  131.136 53.808 131.16 54 ;
    END
  END result[66]
  PIN result[67]
    DIRECTION INPUT ;
    USE SIGNAL ;
    PORT
      LAYER M3 ;
        RECT  131.292 53.856 131.31 54 ;
    END
  END result[67]
  PIN result[68]
    DIRECTION INPUT ;
    USE SIGNAL ;
    PORT
      LAYER M5 ;
        RECT  131.424 53.808 131.448 54 ;
    END
  END result[68]
  PIN result[69]
    DIRECTION INPUT ;
    USE SIGNAL ;
    PORT
      LAYER M3 ;
        RECT  131.58 53.856 131.598 54 ;
    END
  END result[69]
  PIN result[6]
    DIRECTION INPUT ;
    USE SIGNAL ;
    PORT
      LAYER M5 ;
        RECT  122.064 53.808 122.088 54 ;
    END
  END result[6]
  PIN result[70]
    DIRECTION INPUT ;
    USE SIGNAL ;
    PORT
      LAYER M5 ;
        RECT  131.76 53.808 131.784 54 ;
    END
  END result[70]
  PIN result[71]
    DIRECTION INPUT ;
    USE SIGNAL ;
    PORT
      LAYER M3 ;
        RECT  131.904 53.856 131.922 54 ;
    END
  END result[71]
  PIN result[72]
    DIRECTION INPUT ;
    USE SIGNAL ;
    PORT
      LAYER M5 ;
        RECT  132.048 53.808 132.072 54 ;
    END
  END result[72]
  PIN result[73]
    DIRECTION INPUT ;
    USE SIGNAL ;
    PORT
      LAYER M3 ;
        RECT  132.192 53.856 132.21 54 ;
    END
  END result[73]
  PIN result[74]
    DIRECTION INPUT ;
    USE SIGNAL ;
    PORT
      LAYER M5 ;
        RECT  132.336 53.808 132.36 54 ;
    END
  END result[74]
  PIN result[75]
    DIRECTION INPUT ;
    USE SIGNAL ;
    PORT
      LAYER M3 ;
        RECT  132.48 53.856 132.498 54 ;
    END
  END result[75]
  PIN result[76]
    DIRECTION INPUT ;
    USE SIGNAL ;
    PORT
      LAYER M5 ;
        RECT  132.624 53.808 132.648 54 ;
    END
  END result[76]
  PIN result[77]
    DIRECTION INPUT ;
    USE SIGNAL ;
    PORT
      LAYER M3 ;
        RECT  132.804 53.856 132.822 54 ;
    END
  END result[77]
  PIN result[78]
    DIRECTION INPUT ;
    USE SIGNAL ;
    PORT
      LAYER M5 ;
        RECT  132.96 53.808 132.984 54 ;
    END
  END result[78]
  PIN result[79]
    DIRECTION INPUT ;
    USE SIGNAL ;
    PORT
      LAYER M3 ;
        RECT  133.092 53.856 133.11 54 ;
    END
  END result[79]
  PIN result[7]
    DIRECTION INPUT ;
    USE SIGNAL ;
    PORT
      LAYER M3 ;
        RECT  122.184 53.856 122.202 54 ;
    END
  END result[7]
  PIN result[80]
    DIRECTION INPUT ;
    USE SIGNAL ;
    PORT
      LAYER M5 ;
        RECT  133.248 53.808 133.272 54 ;
    END
  END result[80]
  PIN result[81]
    DIRECTION INPUT ;
    USE SIGNAL ;
    PORT
      LAYER M3 ;
        RECT  133.416 53.856 133.434 54 ;
    END
  END result[81]
  PIN result[82]
    DIRECTION INPUT ;
    USE SIGNAL ;
    PORT
      LAYER M5 ;
        RECT  133.536 53.808 133.56 54 ;
    END
  END result[82]
  PIN result[83]
    DIRECTION INPUT ;
    USE SIGNAL ;
    PORT
      LAYER M3 ;
        RECT  133.704 53.856 133.722 54 ;
    END
  END result[83]
  PIN result[84]
    DIRECTION INPUT ;
    USE SIGNAL ;
    PORT
      LAYER M5 ;
        RECT  133.872 53.808 133.896 54 ;
    END
  END result[84]
  PIN result[85]
    DIRECTION INPUT ;
    USE SIGNAL ;
    PORT
      LAYER M3 ;
        RECT  134.028 53.856 134.046 54 ;
    END
  END result[85]
  PIN result[86]
    DIRECTION INPUT ;
    USE SIGNAL ;
    PORT
      LAYER M5 ;
        RECT  134.16 53.808 134.184 54 ;
    END
  END result[86]
  PIN result[87]
    DIRECTION INPUT ;
    USE SIGNAL ;
    PORT
      LAYER M3 ;
        RECT  134.316 53.856 134.334 54 ;
    END
  END result[87]
  PIN result[88]
    DIRECTION INPUT ;
    USE SIGNAL ;
    PORT
      LAYER M5 ;
        RECT  134.448 53.808 134.472 54 ;
    END
  END result[88]
  PIN result[89]
    DIRECTION INPUT ;
    USE SIGNAL ;
    PORT
      LAYER M3 ;
        RECT  134.604 53.856 134.622 54 ;
    END
  END result[89]
  PIN result[8]
    DIRECTION INPUT ;
    USE SIGNAL ;
    PORT
      LAYER M5 ;
        RECT  122.352 53.808 122.376 54 ;
    END
  END result[8]
  PIN result[90]
    DIRECTION INPUT ;
    USE SIGNAL ;
    PORT
      LAYER M5 ;
        RECT  134.784 53.808 134.808 54 ;
    END
  END result[90]
  PIN result[91]
    DIRECTION INPUT ;
    USE SIGNAL ;
    PORT
      LAYER M3 ;
        RECT  134.928 53.856 134.946 54 ;
    END
  END result[91]
  PIN result[92]
    DIRECTION INPUT ;
    USE SIGNAL ;
    PORT
      LAYER M5 ;
        RECT  135.072 53.808 135.096 54 ;
    END
  END result[92]
  PIN result[93]
    DIRECTION INPUT ;
    USE SIGNAL ;
    PORT
      LAYER M3 ;
        RECT  135.216 53.856 135.234 54 ;
    END
  END result[93]
  PIN result[94]
    DIRECTION INPUT ;
    USE SIGNAL ;
    PORT
      LAYER M5 ;
        RECT  135.36 53.808 135.384 54 ;
    END
  END result[94]
  PIN result[95]
    DIRECTION INPUT ;
    USE SIGNAL ;
    PORT
      LAYER M3 ;
        RECT  135.54 53.856 135.558 54 ;
    END
  END result[95]
  PIN result[96]
    DIRECTION INPUT ;
    USE SIGNAL ;
    PORT
      LAYER M5 ;
        RECT  135.696 53.808 135.72 54 ;
    END
  END result[96]
  PIN result[97]
    DIRECTION INPUT ;
    USE SIGNAL ;
    PORT
      LAYER M3 ;
        RECT  135.828 53.856 135.846 54 ;
    END
  END result[97]
  PIN result[98]
    DIRECTION INPUT ;
    USE SIGNAL ;
    PORT
      LAYER M5 ;
        RECT  135.984 53.808 136.008 54 ;
    END
  END result[98]
  PIN result[99]
    DIRECTION INPUT ;
    USE SIGNAL ;
    PORT
      LAYER M3 ;
        RECT  136.116 53.856 136.134 54 ;
    END
  END result[99]
  PIN result[9]
    DIRECTION INPUT ;
    USE SIGNAL ;
    PORT
      LAYER M3 ;
        RECT  122.508 53.856 122.526 54 ;
    END
  END result[9]
  PIN rs_d[0]
    DIRECTION INPUT ;
    USE SIGNAL ;
    PORT
      LAYER M5 ;
        RECT  5.424 0 5.448 0.192 ;
    END
  END rs_d[0]
  PIN rs_d[100]
    DIRECTION INPUT ;
    USE SIGNAL ;
    PORT
      LAYER M5 ;
        RECT  25.536 0 25.56 0.192 ;
    END
  END rs_d[100]
  PIN rs_d[101]
    DIRECTION INPUT ;
    USE SIGNAL ;
    PORT
      LAYER M3 ;
        RECT  25.74 0 25.758 0.144 ;
    END
  END rs_d[101]
  PIN rs_d[102]
    DIRECTION INPUT ;
    USE SIGNAL ;
    PORT
      LAYER M5 ;
        RECT  25.92 0 25.944 0.192 ;
    END
  END rs_d[102]
  PIN rs_d[103]
    DIRECTION INPUT ;
    USE SIGNAL ;
    PORT
      LAYER M3 ;
        RECT  26.136 0 26.154 0.144 ;
    END
  END rs_d[103]
  PIN rs_d[104]
    DIRECTION INPUT ;
    USE SIGNAL ;
    PORT
      LAYER M5 ;
        RECT  26.352 0 26.376 0.192 ;
    END
  END rs_d[104]
  PIN rs_d[105]
    DIRECTION INPUT ;
    USE SIGNAL ;
    PORT
      LAYER M3 ;
        RECT  26.532 0 26.55 0.144 ;
    END
  END rs_d[105]
  PIN rs_d[106]
    DIRECTION INPUT ;
    USE SIGNAL ;
    PORT
      LAYER M5 ;
        RECT  26.736 0 26.76 0.192 ;
    END
  END rs_d[106]
  PIN rs_d[107]
    DIRECTION INPUT ;
    USE SIGNAL ;
    PORT
      LAYER M3 ;
        RECT  26.928 0 26.946 0.144 ;
    END
  END rs_d[107]
  PIN rs_d[108]
    DIRECTION INPUT ;
    USE SIGNAL ;
    PORT
      LAYER M5 ;
        RECT  27.12 0 27.144 0.192 ;
    END
  END rs_d[108]
  PIN rs_d[109]
    DIRECTION INPUT ;
    USE SIGNAL ;
    PORT
      LAYER M3 ;
        RECT  27.36 0 27.378 0.144 ;
    END
  END rs_d[109]
  PIN rs_d[10]
    DIRECTION INPUT ;
    USE SIGNAL ;
    PORT
      LAYER M5 ;
        RECT  7.44 0 7.464 0.192 ;
    END
  END rs_d[10]
  PIN rs_d[110]
    DIRECTION INPUT ;
    USE SIGNAL ;
    PORT
      LAYER M5 ;
        RECT  27.552 0 27.576 0.192 ;
    END
  END rs_d[110]
  PIN rs_d[111]
    DIRECTION INPUT ;
    USE SIGNAL ;
    PORT
      LAYER M3 ;
        RECT  27.756 0 27.774 0.144 ;
    END
  END rs_d[111]
  PIN rs_d[112]
    DIRECTION INPUT ;
    USE SIGNAL ;
    PORT
      LAYER M5 ;
        RECT  27.936 0 27.96 0.192 ;
    END
  END rs_d[112]
  PIN rs_d[113]
    DIRECTION INPUT ;
    USE SIGNAL ;
    PORT
      LAYER M3 ;
        RECT  28.152 0 28.17 0.144 ;
    END
  END rs_d[113]
  PIN rs_d[114]
    DIRECTION INPUT ;
    USE SIGNAL ;
    PORT
      LAYER M5 ;
        RECT  28.368 0 28.392 0.192 ;
    END
  END rs_d[114]
  PIN rs_d[115]
    DIRECTION INPUT ;
    USE SIGNAL ;
    PORT
      LAYER M3 ;
        RECT  28.548 0 28.566 0.144 ;
    END
  END rs_d[115]
  PIN rs_d[116]
    DIRECTION INPUT ;
    USE SIGNAL ;
    PORT
      LAYER M5 ;
        RECT  28.752 0 28.776 0.192 ;
    END
  END rs_d[116]
  PIN rs_d[117]
    DIRECTION INPUT ;
    USE SIGNAL ;
    PORT
      LAYER M3 ;
        RECT  28.944 0 28.962 0.144 ;
    END
  END rs_d[117]
  PIN rs_d[118]
    DIRECTION INPUT ;
    USE SIGNAL ;
    PORT
      LAYER M5 ;
        RECT  29.136 0 29.16 0.192 ;
    END
  END rs_d[118]
  PIN rs_d[119]
    DIRECTION INPUT ;
    USE SIGNAL ;
    PORT
      LAYER M3 ;
        RECT  29.376 0 29.394 0.144 ;
    END
  END rs_d[119]
  PIN rs_d[11]
    DIRECTION INPUT ;
    USE SIGNAL ;
    PORT
      LAYER M3 ;
        RECT  7.632 0 7.65 0.144 ;
    END
  END rs_d[11]
  PIN rs_d[120]
    DIRECTION INPUT ;
    USE SIGNAL ;
    PORT
      LAYER M5 ;
        RECT  29.568 0 29.592 0.192 ;
    END
  END rs_d[120]
  PIN rs_d[121]
    DIRECTION INPUT ;
    USE SIGNAL ;
    PORT
      LAYER M3 ;
        RECT  29.772 0 29.79 0.144 ;
    END
  END rs_d[121]
  PIN rs_d[122]
    DIRECTION INPUT ;
    USE SIGNAL ;
    PORT
      LAYER M5 ;
        RECT  29.952 0 29.976 0.192 ;
    END
  END rs_d[122]
  PIN rs_d[123]
    DIRECTION INPUT ;
    USE SIGNAL ;
    PORT
      LAYER M3 ;
        RECT  30.168 0 30.186 0.144 ;
    END
  END rs_d[123]
  PIN rs_d[124]
    DIRECTION INPUT ;
    USE SIGNAL ;
    PORT
      LAYER M5 ;
        RECT  30.384 0 30.408 0.192 ;
    END
  END rs_d[124]
  PIN rs_d[125]
    DIRECTION INPUT ;
    USE SIGNAL ;
    PORT
      LAYER M3 ;
        RECT  30.564 0 30.582 0.144 ;
    END
  END rs_d[125]
  PIN rs_d[126]
    DIRECTION INPUT ;
    USE SIGNAL ;
    PORT
      LAYER M5 ;
        RECT  30.768 0 30.792 0.192 ;
    END
  END rs_d[126]
  PIN rs_d[127]
    DIRECTION INPUT ;
    USE SIGNAL ;
    PORT
      LAYER M3 ;
        RECT  30.96 0 30.978 0.144 ;
    END
  END rs_d[127]
  PIN rs_d[128]
    DIRECTION INPUT ;
    USE SIGNAL ;
    PORT
      LAYER M5 ;
        RECT  31.152 0 31.176 0.192 ;
    END
  END rs_d[128]
  PIN rs_d[129]
    DIRECTION INPUT ;
    USE SIGNAL ;
    PORT
      LAYER M3 ;
        RECT  31.356 0 31.374 0.144 ;
    END
  END rs_d[129]
  PIN rs_d[12]
    DIRECTION INPUT ;
    USE SIGNAL ;
    PORT
      LAYER M5 ;
        RECT  7.824 0 7.848 0.192 ;
    END
  END rs_d[12]
  PIN rs_d[130]
    DIRECTION INPUT ;
    USE SIGNAL ;
    PORT
      LAYER M5 ;
        RECT  31.584 0 31.608 0.192 ;
    END
  END rs_d[130]
  PIN rs_d[131]
    DIRECTION INPUT ;
    USE SIGNAL ;
    PORT
      LAYER M3 ;
        RECT  31.788 0 31.806 0.144 ;
    END
  END rs_d[131]
  PIN rs_d[132]
    DIRECTION INPUT ;
    USE SIGNAL ;
    PORT
      LAYER M5 ;
        RECT  31.968 0 31.992 0.192 ;
    END
  END rs_d[132]
  PIN rs_d[133]
    DIRECTION INPUT ;
    USE SIGNAL ;
    PORT
      LAYER M3 ;
        RECT  32.184 0 32.202 0.144 ;
    END
  END rs_d[133]
  PIN rs_d[134]
    DIRECTION INPUT ;
    USE SIGNAL ;
    PORT
      LAYER M5 ;
        RECT  32.352 0 32.376 0.192 ;
    END
  END rs_d[134]
  PIN rs_d[135]
    DIRECTION INPUT ;
    USE SIGNAL ;
    PORT
      LAYER M3 ;
        RECT  32.58 0 32.598 0.144 ;
    END
  END rs_d[135]
  PIN rs_d[136]
    DIRECTION INPUT ;
    USE SIGNAL ;
    PORT
      LAYER M5 ;
        RECT  32.784 0 32.808 0.192 ;
    END
  END rs_d[136]
  PIN rs_d[137]
    DIRECTION INPUT ;
    USE SIGNAL ;
    PORT
      LAYER M3 ;
        RECT  32.976 0 32.994 0.144 ;
    END
  END rs_d[137]
  PIN rs_d[138]
    DIRECTION INPUT ;
    USE SIGNAL ;
    PORT
      LAYER M5 ;
        RECT  33.168 0 33.192 0.192 ;
    END
  END rs_d[138]
  PIN rs_d[139]
    DIRECTION INPUT ;
    USE SIGNAL ;
    PORT
      LAYER M3 ;
        RECT  33.372 0 33.39 0.144 ;
    END
  END rs_d[139]
  PIN rs_d[13]
    DIRECTION INPUT ;
    USE SIGNAL ;
    PORT
      LAYER M3 ;
        RECT  8.028 0 8.046 0.144 ;
    END
  END rs_d[13]
  PIN rs_d[140]
    DIRECTION INPUT ;
    USE SIGNAL ;
    PORT
      LAYER M5 ;
        RECT  33.6 0 33.624 0.192 ;
    END
  END rs_d[140]
  PIN rs_d[141]
    DIRECTION INPUT ;
    USE SIGNAL ;
    PORT
      LAYER M3 ;
        RECT  33.768 0 33.786 0.144 ;
    END
  END rs_d[141]
  PIN rs_d[142]
    DIRECTION INPUT ;
    USE SIGNAL ;
    PORT
      LAYER M5 ;
        RECT  33.984 0 34.008 0.192 ;
    END
  END rs_d[142]
  PIN rs_d[143]
    DIRECTION INPUT ;
    USE SIGNAL ;
    PORT
      LAYER M3 ;
        RECT  34.2 0 34.218 0.144 ;
    END
  END rs_d[143]
  PIN rs_d[144]
    DIRECTION INPUT ;
    USE SIGNAL ;
    PORT
      LAYER M5 ;
        RECT  34.368 0 34.392 0.192 ;
    END
  END rs_d[144]
  PIN rs_d[145]
    DIRECTION INPUT ;
    USE SIGNAL ;
    PORT
      LAYER M3 ;
        RECT  34.596 0 34.614 0.144 ;
    END
  END rs_d[145]
  PIN rs_d[146]
    DIRECTION INPUT ;
    USE SIGNAL ;
    PORT
      LAYER M5 ;
        RECT  34.8 0 34.824 0.192 ;
    END
  END rs_d[146]
  PIN rs_d[147]
    DIRECTION INPUT ;
    USE SIGNAL ;
    PORT
      LAYER M3 ;
        RECT  34.992 0 35.01 0.144 ;
    END
  END rs_d[147]
  PIN rs_d[148]
    DIRECTION INPUT ;
    USE SIGNAL ;
    PORT
      LAYER M5 ;
        RECT  35.184 0 35.208 0.192 ;
    END
  END rs_d[148]
  PIN rs_d[149]
    DIRECTION INPUT ;
    USE SIGNAL ;
    PORT
      LAYER M3 ;
        RECT  35.388 0 35.406 0.144 ;
    END
  END rs_d[149]
  PIN rs_d[14]
    DIRECTION INPUT ;
    USE SIGNAL ;
    PORT
      LAYER M5 ;
        RECT  8.208 0 8.232 0.192 ;
    END
  END rs_d[14]
  PIN rs_d[150]
    DIRECTION INPUT ;
    USE SIGNAL ;
    PORT
      LAYER M5 ;
        RECT  35.616 0 35.64 0.192 ;
    END
  END rs_d[150]
  PIN rs_d[151]
    DIRECTION INPUT ;
    USE SIGNAL ;
    PORT
      LAYER M3 ;
        RECT  35.784 0 35.802 0.144 ;
    END
  END rs_d[151]
  PIN rs_d[152]
    DIRECTION INPUT ;
    USE SIGNAL ;
    PORT
      LAYER M5 ;
        RECT  36 0 36.024 0.192 ;
    END
  END rs_d[152]
  PIN rs_d[153]
    DIRECTION INPUT ;
    USE SIGNAL ;
    PORT
      LAYER M3 ;
        RECT  36.216 0 36.234 0.144 ;
    END
  END rs_d[153]
  PIN rs_d[154]
    DIRECTION INPUT ;
    USE SIGNAL ;
    PORT
      LAYER M5 ;
        RECT  36.384 0 36.408 0.192 ;
    END
  END rs_d[154]
  PIN rs_d[155]
    DIRECTION INPUT ;
    USE SIGNAL ;
    PORT
      LAYER M3 ;
        RECT  36.612 0 36.63 0.144 ;
    END
  END rs_d[155]
  PIN rs_d[156]
    DIRECTION INPUT ;
    USE SIGNAL ;
    PORT
      LAYER M5 ;
        RECT  36.816 0 36.84 0.192 ;
    END
  END rs_d[156]
  PIN rs_d[157]
    DIRECTION INPUT ;
    USE SIGNAL ;
    PORT
      LAYER M3 ;
        RECT  37.008 0 37.026 0.144 ;
    END
  END rs_d[157]
  PIN rs_d[158]
    DIRECTION INPUT ;
    USE SIGNAL ;
    PORT
      LAYER M5 ;
        RECT  37.2 0 37.224 0.192 ;
    END
  END rs_d[158]
  PIN rs_d[159]
    DIRECTION INPUT ;
    USE SIGNAL ;
    PORT
      LAYER M3 ;
        RECT  37.404 0 37.422 0.144 ;
    END
  END rs_d[159]
  PIN rs_d[15]
    DIRECTION INPUT ;
    USE SIGNAL ;
    PORT
      LAYER M3 ;
        RECT  8.424 0 8.442 0.144 ;
    END
  END rs_d[15]
  PIN rs_d[160]
    DIRECTION INPUT ;
    USE SIGNAL ;
    PORT
      LAYER M5 ;
        RECT  37.584 0 37.608 0.192 ;
    END
  END rs_d[160]
  PIN rs_d[161]
    DIRECTION INPUT ;
    USE SIGNAL ;
    PORT
      LAYER M3 ;
        RECT  37.8 0 37.818 0.144 ;
    END
  END rs_d[161]
  PIN rs_d[162]
    DIRECTION INPUT ;
    USE SIGNAL ;
    PORT
      LAYER M5 ;
        RECT  38.016 0 38.04 0.192 ;
    END
  END rs_d[162]
  PIN rs_d[163]
    DIRECTION INPUT ;
    USE SIGNAL ;
    PORT
      LAYER M3 ;
        RECT  38.196 0 38.214 0.144 ;
    END
  END rs_d[163]
  PIN rs_d[164]
    DIRECTION INPUT ;
    USE SIGNAL ;
    PORT
      LAYER M5 ;
        RECT  38.4 0 38.424 0.192 ;
    END
  END rs_d[164]
  PIN rs_d[165]
    DIRECTION INPUT ;
    USE SIGNAL ;
    PORT
      LAYER M3 ;
        RECT  38.628 0 38.646 0.144 ;
    END
  END rs_d[165]
  PIN rs_d[166]
    DIRECTION INPUT ;
    USE SIGNAL ;
    PORT
      LAYER M5 ;
        RECT  38.832 0 38.856 0.192 ;
    END
  END rs_d[166]
  PIN rs_d[167]
    DIRECTION INPUT ;
    USE SIGNAL ;
    PORT
      LAYER M3 ;
        RECT  39.024 0 39.042 0.144 ;
    END
  END rs_d[167]
  PIN rs_d[168]
    DIRECTION INPUT ;
    USE SIGNAL ;
    PORT
      LAYER M5 ;
        RECT  39.216 0 39.24 0.192 ;
    END
  END rs_d[168]
  PIN rs_d[169]
    DIRECTION INPUT ;
    USE SIGNAL ;
    PORT
      LAYER M3 ;
        RECT  39.42 0 39.438 0.144 ;
    END
  END rs_d[169]
  PIN rs_d[16]
    DIRECTION INPUT ;
    USE SIGNAL ;
    PORT
      LAYER M5 ;
        RECT  8.64 0 8.664 0.192 ;
    END
  END rs_d[16]
  PIN rs_d[170]
    DIRECTION INPUT ;
    USE SIGNAL ;
    PORT
      LAYER M5 ;
        RECT  39.6 0 39.624 0.192 ;
    END
  END rs_d[170]
  PIN rs_d[171]
    DIRECTION INPUT ;
    USE SIGNAL ;
    PORT
      LAYER M3 ;
        RECT  39.816 0 39.834 0.144 ;
    END
  END rs_d[171]
  PIN rs_d[172]
    DIRECTION INPUT ;
    USE SIGNAL ;
    PORT
      LAYER M5 ;
        RECT  40.032 0 40.056 0.192 ;
    END
  END rs_d[172]
  PIN rs_d[173]
    DIRECTION INPUT ;
    USE SIGNAL ;
    PORT
      LAYER M3 ;
        RECT  40.212 0 40.23 0.144 ;
    END
  END rs_d[173]
  PIN rs_d[174]
    DIRECTION INPUT ;
    USE SIGNAL ;
    PORT
      LAYER M5 ;
        RECT  40.416 0 40.44 0.192 ;
    END
  END rs_d[174]
  PIN rs_d[175]
    DIRECTION INPUT ;
    USE SIGNAL ;
    PORT
      LAYER M3 ;
        RECT  40.608 0 40.626 0.144 ;
    END
  END rs_d[175]
  PIN rs_d[176]
    DIRECTION INPUT ;
    USE SIGNAL ;
    PORT
      LAYER M5 ;
        RECT  40.848 0 40.872 0.192 ;
    END
  END rs_d[176]
  PIN rs_d[177]
    DIRECTION INPUT ;
    USE SIGNAL ;
    PORT
      LAYER M3 ;
        RECT  41.04 0 41.058 0.144 ;
    END
  END rs_d[177]
  PIN rs_d[178]
    DIRECTION INPUT ;
    USE SIGNAL ;
    PORT
      LAYER M5 ;
        RECT  41.232 0 41.256 0.192 ;
    END
  END rs_d[178]
  PIN rs_d[179]
    DIRECTION INPUT ;
    USE SIGNAL ;
    PORT
      LAYER M3 ;
        RECT  41.436 0 41.454 0.144 ;
    END
  END rs_d[179]
  PIN rs_d[17]
    DIRECTION INPUT ;
    USE SIGNAL ;
    PORT
      LAYER M3 ;
        RECT  8.82 0 8.838 0.144 ;
    END
  END rs_d[17]
  PIN rs_d[180]
    DIRECTION INPUT ;
    USE SIGNAL ;
    PORT
      LAYER M5 ;
        RECT  41.616 0 41.64 0.192 ;
    END
  END rs_d[180]
  PIN rs_d[181]
    DIRECTION INPUT ;
    USE SIGNAL ;
    PORT
      LAYER M3 ;
        RECT  41.832 0 41.85 0.144 ;
    END
  END rs_d[181]
  PIN rs_d[182]
    DIRECTION INPUT ;
    USE SIGNAL ;
    PORT
      LAYER M5 ;
        RECT  42.048 0 42.072 0.192 ;
    END
  END rs_d[182]
  PIN rs_d[183]
    DIRECTION INPUT ;
    USE SIGNAL ;
    PORT
      LAYER M3 ;
        RECT  42.228 0 42.246 0.144 ;
    END
  END rs_d[183]
  PIN rs_d[184]
    DIRECTION INPUT ;
    USE SIGNAL ;
    PORT
      LAYER M5 ;
        RECT  42.432 0 42.456 0.192 ;
    END
  END rs_d[184]
  PIN rs_d[185]
    DIRECTION INPUT ;
    USE SIGNAL ;
    PORT
      LAYER M3 ;
        RECT  42.624 0 42.642 0.144 ;
    END
  END rs_d[185]
  PIN rs_d[186]
    DIRECTION INPUT ;
    USE SIGNAL ;
    PORT
      LAYER M5 ;
        RECT  42.816 0 42.84 0.192 ;
    END
  END rs_d[186]
  PIN rs_d[187]
    DIRECTION INPUT ;
    USE SIGNAL ;
    PORT
      LAYER M3 ;
        RECT  43.056 0 43.074 0.144 ;
    END
  END rs_d[187]
  PIN rs_d[188]
    DIRECTION INPUT ;
    USE SIGNAL ;
    PORT
      LAYER M5 ;
        RECT  43.248 0 43.272 0.192 ;
    END
  END rs_d[188]
  PIN rs_d[189]
    DIRECTION INPUT ;
    USE SIGNAL ;
    PORT
      LAYER M3 ;
        RECT  43.452 0 43.47 0.144 ;
    END
  END rs_d[189]
  PIN rs_d[18]
    DIRECTION INPUT ;
    USE SIGNAL ;
    PORT
      LAYER M5 ;
        RECT  9.024 0 9.048 0.192 ;
    END
  END rs_d[18]
  PIN rs_d[190]
    DIRECTION INPUT ;
    USE SIGNAL ;
    PORT
      LAYER M5 ;
        RECT  43.632 0 43.656 0.192 ;
    END
  END rs_d[190]
  PIN rs_d[191]
    DIRECTION INPUT ;
    USE SIGNAL ;
    PORT
      LAYER M3 ;
        RECT  43.848 0 43.866 0.144 ;
    END
  END rs_d[191]
  PIN rs_d[192]
    DIRECTION INPUT ;
    USE SIGNAL ;
    PORT
      LAYER M5 ;
        RECT  44.064 0 44.088 0.192 ;
    END
  END rs_d[192]
  PIN rs_d[193]
    DIRECTION INPUT ;
    USE SIGNAL ;
    PORT
      LAYER M3 ;
        RECT  44.244 0 44.262 0.144 ;
    END
  END rs_d[193]
  PIN rs_d[194]
    DIRECTION INPUT ;
    USE SIGNAL ;
    PORT
      LAYER M5 ;
        RECT  44.448 0 44.472 0.192 ;
    END
  END rs_d[194]
  PIN rs_d[195]
    DIRECTION INPUT ;
    USE SIGNAL ;
    PORT
      LAYER M3 ;
        RECT  44.64 0 44.658 0.144 ;
    END
  END rs_d[195]
  PIN rs_d[196]
    DIRECTION INPUT ;
    USE SIGNAL ;
    PORT
      LAYER M5 ;
        RECT  44.832 0 44.856 0.192 ;
    END
  END rs_d[196]
  PIN rs_d[197]
    DIRECTION INPUT ;
    USE SIGNAL ;
    PORT
      LAYER M3 ;
        RECT  45.036 0 45.054 0.144 ;
    END
  END rs_d[197]
  PIN rs_d[198]
    DIRECTION INPUT ;
    USE SIGNAL ;
    PORT
      LAYER M5 ;
        RECT  45.264 0 45.288 0.192 ;
    END
  END rs_d[198]
  PIN rs_d[199]
    DIRECTION INPUT ;
    USE SIGNAL ;
    PORT
      LAYER M3 ;
        RECT  45.468 0 45.486 0.144 ;
    END
  END rs_d[199]
  PIN rs_d[19]
    DIRECTION INPUT ;
    USE SIGNAL ;
    PORT
      LAYER M3 ;
        RECT  9.252 0 9.27 0.144 ;
    END
  END rs_d[19]
  PIN rs_d[1]
    DIRECTION INPUT ;
    USE SIGNAL ;
    PORT
      LAYER M3 ;
        RECT  5.616 0 5.634 0.144 ;
    END
  END rs_d[1]
  PIN rs_d[200]
    DIRECTION INPUT ;
    USE SIGNAL ;
    PORT
      LAYER M5 ;
        RECT  45.648 0 45.672 0.192 ;
    END
  END rs_d[200]
  PIN rs_d[201]
    DIRECTION INPUT ;
    USE SIGNAL ;
    PORT
      LAYER M3 ;
        RECT  45.864 0 45.882 0.144 ;
    END
  END rs_d[201]
  PIN rs_d[202]
    DIRECTION INPUT ;
    USE SIGNAL ;
    PORT
      LAYER M5 ;
        RECT  46.032 0 46.056 0.192 ;
    END
  END rs_d[202]
  PIN rs_d[203]
    DIRECTION INPUT ;
    USE SIGNAL ;
    PORT
      LAYER M3 ;
        RECT  46.26 0 46.278 0.144 ;
    END
  END rs_d[203]
  PIN rs_d[204]
    DIRECTION INPUT ;
    USE SIGNAL ;
    PORT
      LAYER M5 ;
        RECT  46.464 0 46.488 0.192 ;
    END
  END rs_d[204]
  PIN rs_d[205]
    DIRECTION INPUT ;
    USE SIGNAL ;
    PORT
      LAYER M3 ;
        RECT  46.656 0 46.674 0.144 ;
    END
  END rs_d[205]
  PIN rs_d[206]
    DIRECTION INPUT ;
    USE SIGNAL ;
    PORT
      LAYER M5 ;
        RECT  46.848 0 46.872 0.192 ;
    END
  END rs_d[206]
  PIN rs_d[207]
    DIRECTION INPUT ;
    USE SIGNAL ;
    PORT
      LAYER M3 ;
        RECT  47.052 0 47.07 0.144 ;
    END
  END rs_d[207]
  PIN rs_d[208]
    DIRECTION INPUT ;
    USE SIGNAL ;
    PORT
      LAYER M5 ;
        RECT  47.28 0 47.304 0.192 ;
    END
  END rs_d[208]
  PIN rs_d[209]
    DIRECTION INPUT ;
    USE SIGNAL ;
    PORT
      LAYER M3 ;
        RECT  47.484 0 47.502 0.144 ;
    END
  END rs_d[209]
  PIN rs_d[20]
    DIRECTION INPUT ;
    USE SIGNAL ;
    PORT
      LAYER M5 ;
        RECT  9.456 0 9.48 0.192 ;
    END
  END rs_d[20]
  PIN rs_d[210]
    DIRECTION INPUT ;
    USE SIGNAL ;
    PORT
      LAYER M5 ;
        RECT  47.664 0 47.688 0.192 ;
    END
  END rs_d[210]
  PIN rs_d[211]
    DIRECTION INPUT ;
    USE SIGNAL ;
    PORT
      LAYER M3 ;
        RECT  47.88 0 47.898 0.144 ;
    END
  END rs_d[211]
  PIN rs_d[212]
    DIRECTION INPUT ;
    USE SIGNAL ;
    PORT
      LAYER M5 ;
        RECT  48.048 0 48.072 0.192 ;
    END
  END rs_d[212]
  PIN rs_d[213]
    DIRECTION INPUT ;
    USE SIGNAL ;
    PORT
      LAYER M3 ;
        RECT  48.276 0 48.294 0.144 ;
    END
  END rs_d[213]
  PIN rs_d[214]
    DIRECTION INPUT ;
    USE SIGNAL ;
    PORT
      LAYER M5 ;
        RECT  48.48 0 48.504 0.192 ;
    END
  END rs_d[214]
  PIN rs_d[215]
    DIRECTION INPUT ;
    USE SIGNAL ;
    PORT
      LAYER M3 ;
        RECT  48.672 0 48.69 0.144 ;
    END
  END rs_d[215]
  PIN rs_d[216]
    DIRECTION INPUT ;
    USE SIGNAL ;
    PORT
      LAYER M5 ;
        RECT  48.864 0 48.888 0.192 ;
    END
  END rs_d[216]
  PIN rs_d[217]
    DIRECTION INPUT ;
    USE SIGNAL ;
    PORT
      LAYER M3 ;
        RECT  49.068 0 49.086 0.144 ;
    END
  END rs_d[217]
  PIN rs_d[218]
    DIRECTION INPUT ;
    USE SIGNAL ;
    PORT
      LAYER M5 ;
        RECT  49.296 0 49.32 0.192 ;
    END
  END rs_d[218]
  PIN rs_d[219]
    DIRECTION INPUT ;
    USE SIGNAL ;
    PORT
      LAYER M3 ;
        RECT  49.464 0 49.482 0.144 ;
    END
  END rs_d[219]
  PIN rs_d[21]
    DIRECTION INPUT ;
    USE SIGNAL ;
    PORT
      LAYER M3 ;
        RECT  9.648 0 9.666 0.144 ;
    END
  END rs_d[21]
  PIN rs_d[220]
    DIRECTION INPUT ;
    USE SIGNAL ;
    PORT
      LAYER M5 ;
        RECT  49.68 0 49.704 0.192 ;
    END
  END rs_d[220]
  PIN rs_d[221]
    DIRECTION INPUT ;
    USE SIGNAL ;
    PORT
      LAYER M3 ;
        RECT  49.896 0 49.914 0.144 ;
    END
  END rs_d[221]
  PIN rs_d[222]
    DIRECTION INPUT ;
    USE SIGNAL ;
    PORT
      LAYER M5 ;
        RECT  50.064 0 50.088 0.192 ;
    END
  END rs_d[222]
  PIN rs_d[223]
    DIRECTION INPUT ;
    USE SIGNAL ;
    PORT
      LAYER M3 ;
        RECT  50.292 0 50.31 0.144 ;
    END
  END rs_d[223]
  PIN rs_d[224]
    DIRECTION INPUT ;
    USE SIGNAL ;
    PORT
      LAYER M5 ;
        RECT  50.496 0 50.52 0.192 ;
    END
  END rs_d[224]
  PIN rs_d[225]
    DIRECTION INPUT ;
    USE SIGNAL ;
    PORT
      LAYER M3 ;
        RECT  50.688 0 50.706 0.144 ;
    END
  END rs_d[225]
  PIN rs_d[226]
    DIRECTION INPUT ;
    USE SIGNAL ;
    PORT
      LAYER M5 ;
        RECT  50.88 0 50.904 0.192 ;
    END
  END rs_d[226]
  PIN rs_d[227]
    DIRECTION INPUT ;
    USE SIGNAL ;
    PORT
      LAYER M3 ;
        RECT  51.084 0 51.102 0.144 ;
    END
  END rs_d[227]
  PIN rs_d[228]
    DIRECTION INPUT ;
    USE SIGNAL ;
    PORT
      LAYER M5 ;
        RECT  51.264 0 51.288 0.192 ;
    END
  END rs_d[228]
  PIN rs_d[229]
    DIRECTION INPUT ;
    USE SIGNAL ;
    PORT
      LAYER M3 ;
        RECT  51.48 0 51.498 0.144 ;
    END
  END rs_d[229]
  PIN rs_d[22]
    DIRECTION INPUT ;
    USE SIGNAL ;
    PORT
      LAYER M5 ;
        RECT  9.84 0 9.864 0.192 ;
    END
  END rs_d[22]
  PIN rs_d[230]
    DIRECTION INPUT ;
    USE SIGNAL ;
    PORT
      LAYER M5 ;
        RECT  51.696 0 51.72 0.192 ;
    END
  END rs_d[230]
  PIN rs_d[231]
    DIRECTION INPUT ;
    USE SIGNAL ;
    PORT
      LAYER M3 ;
        RECT  51.876 0 51.894 0.144 ;
    END
  END rs_d[231]
  PIN rs_d[232]
    DIRECTION INPUT ;
    USE SIGNAL ;
    PORT
      LAYER M5 ;
        RECT  52.08 0 52.104 0.192 ;
    END
  END rs_d[232]
  PIN rs_d[233]
    DIRECTION INPUT ;
    USE SIGNAL ;
    PORT
      LAYER M3 ;
        RECT  52.308 0 52.326 0.144 ;
    END
  END rs_d[233]
  PIN rs_d[234]
    DIRECTION INPUT ;
    USE SIGNAL ;
    PORT
      LAYER M5 ;
        RECT  52.512 0 52.536 0.192 ;
    END
  END rs_d[234]
  PIN rs_d[235]
    DIRECTION INPUT ;
    USE SIGNAL ;
    PORT
      LAYER M3 ;
        RECT  52.704 0 52.722 0.144 ;
    END
  END rs_d[235]
  PIN rs_d[236]
    DIRECTION INPUT ;
    USE SIGNAL ;
    PORT
      LAYER M5 ;
        RECT  52.896 0 52.92 0.192 ;
    END
  END rs_d[236]
  PIN rs_d[237]
    DIRECTION INPUT ;
    USE SIGNAL ;
    PORT
      LAYER M3 ;
        RECT  53.1 0 53.118 0.144 ;
    END
  END rs_d[237]
  PIN rs_d[238]
    DIRECTION INPUT ;
    USE SIGNAL ;
    PORT
      LAYER M5 ;
        RECT  53.28 0 53.304 0.192 ;
    END
  END rs_d[238]
  PIN rs_d[239]
    DIRECTION INPUT ;
    USE SIGNAL ;
    PORT
      LAYER M3 ;
        RECT  53.496 0 53.514 0.144 ;
    END
  END rs_d[239]
  PIN rs_d[23]
    DIRECTION INPUT ;
    USE SIGNAL ;
    PORT
      LAYER M3 ;
        RECT  10.044 0 10.062 0.144 ;
    END
  END rs_d[23]
  PIN rs_d[240]
    DIRECTION INPUT ;
    USE SIGNAL ;
    PORT
      LAYER M5 ;
        RECT  53.712 0 53.736 0.192 ;
    END
  END rs_d[240]
  PIN rs_d[241]
    DIRECTION INPUT ;
    USE SIGNAL ;
    PORT
      LAYER M3 ;
        RECT  53.892 0 53.91 0.144 ;
    END
  END rs_d[241]
  PIN rs_d[242]
    DIRECTION INPUT ;
    USE SIGNAL ;
    PORT
      LAYER M5 ;
        RECT  54.096 0 54.12 0.192 ;
    END
  END rs_d[242]
  PIN rs_d[243]
    DIRECTION INPUT ;
    USE SIGNAL ;
    PORT
      LAYER M3 ;
        RECT  54.324 0 54.342 0.144 ;
    END
  END rs_d[243]
  PIN rs_d[244]
    DIRECTION INPUT ;
    USE SIGNAL ;
    PORT
      LAYER M5 ;
        RECT  54.528 0 54.552 0.192 ;
    END
  END rs_d[244]
  PIN rs_d[245]
    DIRECTION INPUT ;
    USE SIGNAL ;
    PORT
      LAYER M3 ;
        RECT  54.72 0 54.738 0.144 ;
    END
  END rs_d[245]
  PIN rs_d[246]
    DIRECTION INPUT ;
    USE SIGNAL ;
    PORT
      LAYER M5 ;
        RECT  54.912 0 54.936 0.192 ;
    END
  END rs_d[246]
  PIN rs_d[247]
    DIRECTION INPUT ;
    USE SIGNAL ;
    PORT
      LAYER M3 ;
        RECT  55.116 0 55.134 0.144 ;
    END
  END rs_d[247]
  PIN rs_d[248]
    DIRECTION INPUT ;
    USE SIGNAL ;
    PORT
      LAYER M5 ;
        RECT  55.296 0 55.32 0.192 ;
    END
  END rs_d[248]
  PIN rs_d[249]
    DIRECTION INPUT ;
    USE SIGNAL ;
    PORT
      LAYER M3 ;
        RECT  55.512 0 55.53 0.144 ;
    END
  END rs_d[249]
  PIN rs_d[24]
    DIRECTION INPUT ;
    USE SIGNAL ;
    PORT
      LAYER M5 ;
        RECT  10.224 0 10.248 0.192 ;
    END
  END rs_d[24]
  PIN rs_d[250]
    DIRECTION INPUT ;
    USE SIGNAL ;
    PORT
      LAYER M5 ;
        RECT  55.728 0 55.752 0.192 ;
    END
  END rs_d[250]
  PIN rs_d[251]
    DIRECTION INPUT ;
    USE SIGNAL ;
    PORT
      LAYER M3 ;
        RECT  55.908 0 55.926 0.144 ;
    END
  END rs_d[251]
  PIN rs_d[252]
    DIRECTION INPUT ;
    USE SIGNAL ;
    PORT
      LAYER M5 ;
        RECT  56.112 0 56.136 0.192 ;
    END
  END rs_d[252]
  PIN rs_d[253]
    DIRECTION INPUT ;
    USE SIGNAL ;
    PORT
      LAYER M3 ;
        RECT  56.304 0 56.322 0.144 ;
    END
  END rs_d[253]
  PIN rs_d[254]
    DIRECTION INPUT ;
    USE SIGNAL ;
    PORT
      LAYER M5 ;
        RECT  56.496 0 56.52 0.192 ;
    END
  END rs_d[254]
  PIN rs_d[255]
    DIRECTION INPUT ;
    USE SIGNAL ;
    PORT
      LAYER M3 ;
        RECT  56.736 0 56.754 0.144 ;
    END
  END rs_d[255]
  PIN rs_d[256]
    DIRECTION INPUT ;
    USE SIGNAL ;
    PORT
      LAYER M5 ;
        RECT  56.928 0 56.952 0.192 ;
    END
  END rs_d[256]
  PIN rs_d[257]
    DIRECTION INPUT ;
    USE SIGNAL ;
    PORT
      LAYER M3 ;
        RECT  57.132 0 57.15 0.144 ;
    END
  END rs_d[257]
  PIN rs_d[258]
    DIRECTION INPUT ;
    USE SIGNAL ;
    PORT
      LAYER M5 ;
        RECT  57.312 0 57.336 0.192 ;
    END
  END rs_d[258]
  PIN rs_d[259]
    DIRECTION INPUT ;
    USE SIGNAL ;
    PORT
      LAYER M3 ;
        RECT  57.528 0 57.546 0.144 ;
    END
  END rs_d[259]
  PIN rs_d[25]
    DIRECTION INPUT ;
    USE SIGNAL ;
    PORT
      LAYER M3 ;
        RECT  10.44 0 10.458 0.144 ;
    END
  END rs_d[25]
  PIN rs_d[260]
    DIRECTION INPUT ;
    USE SIGNAL ;
    PORT
      LAYER M5 ;
        RECT  57.744 0 57.768 0.192 ;
    END
  END rs_d[260]
  PIN rs_d[261]
    DIRECTION INPUT ;
    USE SIGNAL ;
    PORT
      LAYER M3 ;
        RECT  57.924 0 57.942 0.144 ;
    END
  END rs_d[261]
  PIN rs_d[262]
    DIRECTION INPUT ;
    USE SIGNAL ;
    PORT
      LAYER M5 ;
        RECT  58.128 0 58.152 0.192 ;
    END
  END rs_d[262]
  PIN rs_d[263]
    DIRECTION INPUT ;
    USE SIGNAL ;
    PORT
      LAYER M3 ;
        RECT  58.32 0 58.338 0.144 ;
    END
  END rs_d[263]
  PIN rs_d[264]
    DIRECTION INPUT ;
    USE SIGNAL ;
    PORT
      LAYER M5 ;
        RECT  58.512 0 58.536 0.192 ;
    END
  END rs_d[264]
  PIN rs_d[265]
    DIRECTION INPUT ;
    USE SIGNAL ;
    PORT
      LAYER M3 ;
        RECT  58.716 0 58.734 0.144 ;
    END
  END rs_d[265]
  PIN rs_d[266]
    DIRECTION INPUT ;
    USE SIGNAL ;
    PORT
      LAYER M5 ;
        RECT  58.944 0 58.968 0.192 ;
    END
  END rs_d[266]
  PIN rs_d[267]
    DIRECTION INPUT ;
    USE SIGNAL ;
    PORT
      LAYER M3 ;
        RECT  59.148 0 59.166 0.144 ;
    END
  END rs_d[267]
  PIN rs_d[268]
    DIRECTION INPUT ;
    USE SIGNAL ;
    PORT
      LAYER M5 ;
        RECT  59.328 0 59.352 0.192 ;
    END
  END rs_d[268]
  PIN rs_d[269]
    DIRECTION INPUT ;
    USE SIGNAL ;
    PORT
      LAYER M3 ;
        RECT  59.544 0 59.562 0.144 ;
    END
  END rs_d[269]
  PIN rs_d[26]
    DIRECTION INPUT ;
    USE SIGNAL ;
    PORT
      LAYER M5 ;
        RECT  10.656 0 10.68 0.192 ;
    END
  END rs_d[26]
  PIN rs_d[270]
    DIRECTION INPUT ;
    USE SIGNAL ;
    PORT
      LAYER M5 ;
        RECT  59.712 0 59.736 0.192 ;
    END
  END rs_d[270]
  PIN rs_d[271]
    DIRECTION INPUT ;
    USE SIGNAL ;
    PORT
      LAYER M3 ;
        RECT  59.94 0 59.958 0.144 ;
    END
  END rs_d[271]
  PIN rs_d[272]
    DIRECTION INPUT ;
    USE SIGNAL ;
    PORT
      LAYER M5 ;
        RECT  60.144 0 60.168 0.192 ;
    END
  END rs_d[272]
  PIN rs_d[273]
    DIRECTION INPUT ;
    USE SIGNAL ;
    PORT
      LAYER M3 ;
        RECT  60.336 0 60.354 0.144 ;
    END
  END rs_d[273]
  PIN rs_d[274]
    DIRECTION INPUT ;
    USE SIGNAL ;
    PORT
      LAYER M5 ;
        RECT  60.528 0 60.552 0.192 ;
    END
  END rs_d[274]
  PIN rs_d[275]
    DIRECTION INPUT ;
    USE SIGNAL ;
    PORT
      LAYER M3 ;
        RECT  60.732 0 60.75 0.144 ;
    END
  END rs_d[275]
  PIN rs_d[276]
    DIRECTION INPUT ;
    USE SIGNAL ;
    PORT
      LAYER M5 ;
        RECT  60.96 0 60.984 0.192 ;
    END
  END rs_d[276]
  PIN rs_d[277]
    DIRECTION INPUT ;
    USE SIGNAL ;
    PORT
      LAYER M3 ;
        RECT  61.164 0 61.182 0.144 ;
    END
  END rs_d[277]
  PIN rs_d[278]
    DIRECTION INPUT ;
    USE SIGNAL ;
    PORT
      LAYER M5 ;
        RECT  61.344 0 61.368 0.192 ;
    END
  END rs_d[278]
  PIN rs_d[279]
    DIRECTION INPUT ;
    USE SIGNAL ;
    PORT
      LAYER M3 ;
        RECT  61.56 0 61.578 0.144 ;
    END
  END rs_d[279]
  PIN rs_d[27]
    DIRECTION INPUT ;
    USE SIGNAL ;
    PORT
      LAYER M3 ;
        RECT  10.836 0 10.854 0.144 ;
    END
  END rs_d[27]
  PIN rs_d[280]
    DIRECTION INPUT ;
    USE SIGNAL ;
    PORT
      LAYER M5 ;
        RECT  61.728 0 61.752 0.192 ;
    END
  END rs_d[280]
  PIN rs_d[281]
    DIRECTION INPUT ;
    USE SIGNAL ;
    PORT
      LAYER M3 ;
        RECT  61.956 0 61.974 0.144 ;
    END
  END rs_d[281]
  PIN rs_d[282]
    DIRECTION INPUT ;
    USE SIGNAL ;
    PORT
      LAYER M5 ;
        RECT  62.16 0 62.184 0.192 ;
    END
  END rs_d[282]
  PIN rs_d[283]
    DIRECTION INPUT ;
    USE SIGNAL ;
    PORT
      LAYER M3 ;
        RECT  62.352 0 62.37 0.144 ;
    END
  END rs_d[283]
  PIN rs_d[284]
    DIRECTION INPUT ;
    USE SIGNAL ;
    PORT
      LAYER M5 ;
        RECT  62.544 0 62.568 0.192 ;
    END
  END rs_d[284]
  PIN rs_d[285]
    DIRECTION INPUT ;
    USE SIGNAL ;
    PORT
      LAYER M3 ;
        RECT  62.748 0 62.766 0.144 ;
    END
  END rs_d[285]
  PIN rs_d[286]
    DIRECTION INPUT ;
    USE SIGNAL ;
    PORT
      LAYER M5 ;
        RECT  62.976 0 63 0.192 ;
    END
  END rs_d[286]
  PIN rs_d[287]
    DIRECTION INPUT ;
    USE SIGNAL ;
    PORT
      LAYER M3 ;
        RECT  63.144 0 63.162 0.144 ;
    END
  END rs_d[287]
  PIN rs_d[288]
    DIRECTION INPUT ;
    USE SIGNAL ;
    PORT
      LAYER M5 ;
        RECT  63.36 0 63.384 0.192 ;
    END
  END rs_d[288]
  PIN rs_d[289]
    DIRECTION INPUT ;
    USE SIGNAL ;
    PORT
      LAYER M3 ;
        RECT  63.576 0 63.594 0.144 ;
    END
  END rs_d[289]
  PIN rs_d[28]
    DIRECTION INPUT ;
    USE SIGNAL ;
    PORT
      LAYER M5 ;
        RECT  11.04 0 11.064 0.192 ;
    END
  END rs_d[28]
  PIN rs_d[290]
    DIRECTION INPUT ;
    USE SIGNAL ;
    PORT
      LAYER M5 ;
        RECT  63.744 0 63.768 0.192 ;
    END
  END rs_d[290]
  PIN rs_d[291]
    DIRECTION INPUT ;
    USE SIGNAL ;
    PORT
      LAYER M3 ;
        RECT  63.972 0 63.99 0.144 ;
    END
  END rs_d[291]
  PIN rs_d[292]
    DIRECTION INPUT ;
    USE SIGNAL ;
    PORT
      LAYER M5 ;
        RECT  64.176 0 64.2 0.192 ;
    END
  END rs_d[292]
  PIN rs_d[293]
    DIRECTION INPUT ;
    USE SIGNAL ;
    PORT
      LAYER M3 ;
        RECT  64.368 0 64.386 0.144 ;
    END
  END rs_d[293]
  PIN rs_d[294]
    DIRECTION INPUT ;
    USE SIGNAL ;
    PORT
      LAYER M5 ;
        RECT  64.56 0 64.584 0.192 ;
    END
  END rs_d[294]
  PIN rs_d[295]
    DIRECTION INPUT ;
    USE SIGNAL ;
    PORT
      LAYER M3 ;
        RECT  64.764 0 64.782 0.144 ;
    END
  END rs_d[295]
  PIN rs_d[296]
    DIRECTION INPUT ;
    USE SIGNAL ;
    PORT
      LAYER M5 ;
        RECT  64.944 0 64.968 0.192 ;
    END
  END rs_d[296]
  PIN rs_d[297]
    DIRECTION INPUT ;
    USE SIGNAL ;
    PORT
      LAYER M3 ;
        RECT  65.16 0 65.178 0.144 ;
    END
  END rs_d[297]
  PIN rs_d[298]
    DIRECTION INPUT ;
    USE SIGNAL ;
    PORT
      LAYER M5 ;
        RECT  65.376 0 65.4 0.192 ;
    END
  END rs_d[298]
  PIN rs_d[299]
    DIRECTION INPUT ;
    USE SIGNAL ;
    PORT
      LAYER M3 ;
        RECT  65.556 0 65.574 0.144 ;
    END
  END rs_d[299]
  PIN rs_d[29]
    DIRECTION INPUT ;
    USE SIGNAL ;
    PORT
      LAYER M3 ;
        RECT  11.268 0 11.286 0.144 ;
    END
  END rs_d[29]
  PIN rs_d[2]
    DIRECTION INPUT ;
    USE SIGNAL ;
    PORT
      LAYER M5 ;
        RECT  5.808 0 5.832 0.192 ;
    END
  END rs_d[2]
  PIN rs_d[300]
    DIRECTION INPUT ;
    USE SIGNAL ;
    PORT
      LAYER M5 ;
        RECT  65.76 0 65.784 0.192 ;
    END
  END rs_d[300]
  PIN rs_d[301]
    DIRECTION INPUT ;
    USE SIGNAL ;
    PORT
      LAYER M3 ;
        RECT  65.988 0 66.006 0.144 ;
    END
  END rs_d[301]
  PIN rs_d[302]
    DIRECTION INPUT ;
    USE SIGNAL ;
    PORT
      LAYER M5 ;
        RECT  66.192 0 66.216 0.192 ;
    END
  END rs_d[302]
  PIN rs_d[303]
    DIRECTION INPUT ;
    USE SIGNAL ;
    PORT
      LAYER M3 ;
        RECT  66.384 0 66.402 0.144 ;
    END
  END rs_d[303]
  PIN rs_d[304]
    DIRECTION INPUT ;
    USE SIGNAL ;
    PORT
      LAYER M5 ;
        RECT  66.576 0 66.6 0.192 ;
    END
  END rs_d[304]
  PIN rs_d[305]
    DIRECTION INPUT ;
    USE SIGNAL ;
    PORT
      LAYER M3 ;
        RECT  66.78 0 66.798 0.144 ;
    END
  END rs_d[305]
  PIN rs_d[306]
    DIRECTION INPUT ;
    USE SIGNAL ;
    PORT
      LAYER M5 ;
        RECT  66.96 0 66.984 0.192 ;
    END
  END rs_d[306]
  PIN rs_d[307]
    DIRECTION INPUT ;
    USE SIGNAL ;
    PORT
      LAYER M3 ;
        RECT  67.176 0 67.194 0.144 ;
    END
  END rs_d[307]
  PIN rs_d[308]
    DIRECTION INPUT ;
    USE SIGNAL ;
    PORT
      LAYER M5 ;
        RECT  67.392 0 67.416 0.192 ;
    END
  END rs_d[308]
  PIN rs_d[309]
    DIRECTION INPUT ;
    USE SIGNAL ;
    PORT
      LAYER M3 ;
        RECT  67.572 0 67.59 0.144 ;
    END
  END rs_d[309]
  PIN rs_d[30]
    DIRECTION INPUT ;
    USE SIGNAL ;
    PORT
      LAYER M5 ;
        RECT  11.472 0 11.496 0.192 ;
    END
  END rs_d[30]
  PIN rs_d[310]
    DIRECTION INPUT ;
    USE SIGNAL ;
    PORT
      LAYER M5 ;
        RECT  67.776 0 67.8 0.192 ;
    END
  END rs_d[310]
  PIN rs_d[311]
    DIRECTION INPUT ;
    USE SIGNAL ;
    PORT
      LAYER M3 ;
        RECT  68.004 0 68.022 0.144 ;
    END
  END rs_d[311]
  PIN rs_d[312]
    DIRECTION INPUT ;
    USE SIGNAL ;
    PORT
      LAYER M5 ;
        RECT  68.208 0 68.232 0.192 ;
    END
  END rs_d[312]
  PIN rs_d[313]
    DIRECTION INPUT ;
    USE SIGNAL ;
    PORT
      LAYER M3 ;
        RECT  68.4 0 68.418 0.144 ;
    END
  END rs_d[313]
  PIN rs_d[314]
    DIRECTION INPUT ;
    USE SIGNAL ;
    PORT
      LAYER M5 ;
        RECT  68.592 0 68.616 0.192 ;
    END
  END rs_d[314]
  PIN rs_d[315]
    DIRECTION INPUT ;
    USE SIGNAL ;
    PORT
      LAYER M3 ;
        RECT  68.796 0 68.814 0.144 ;
    END
  END rs_d[315]
  PIN rs_d[316]
    DIRECTION INPUT ;
    USE SIGNAL ;
    PORT
      LAYER M5 ;
        RECT  68.976 0 69 0.192 ;
    END
  END rs_d[316]
  PIN rs_d[317]
    DIRECTION INPUT ;
    USE SIGNAL ;
    PORT
      LAYER M3 ;
        RECT  69.192 0 69.21 0.144 ;
    END
  END rs_d[317]
  PIN rs_d[318]
    DIRECTION INPUT ;
    USE SIGNAL ;
    PORT
      LAYER M5 ;
        RECT  69.408 0 69.432 0.192 ;
    END
  END rs_d[318]
  PIN rs_d[319]
    DIRECTION INPUT ;
    USE SIGNAL ;
    PORT
      LAYER M3 ;
        RECT  69.588 0 69.606 0.144 ;
    END
  END rs_d[319]
  PIN rs_d[31]
    DIRECTION INPUT ;
    USE SIGNAL ;
    PORT
      LAYER M3 ;
        RECT  11.664 0 11.682 0.144 ;
    END
  END rs_d[31]
  PIN rs_d[320]
    DIRECTION INPUT ;
    USE SIGNAL ;
    PORT
      LAYER M5 ;
        RECT  69.792 0 69.816 0.192 ;
    END
  END rs_d[320]
  PIN rs_d[321]
    DIRECTION INPUT ;
    USE SIGNAL ;
    PORT
      LAYER M3 ;
        RECT  69.984 0 70.002 0.144 ;
    END
  END rs_d[321]
  PIN rs_d[322]
    DIRECTION INPUT ;
    USE SIGNAL ;
    PORT
      LAYER M5 ;
        RECT  70.176 0 70.2 0.192 ;
    END
  END rs_d[322]
  PIN rs_d[323]
    DIRECTION INPUT ;
    USE SIGNAL ;
    PORT
      LAYER M3 ;
        RECT  70.416 0 70.434 0.144 ;
    END
  END rs_d[323]
  PIN rs_d[324]
    DIRECTION INPUT ;
    USE SIGNAL ;
    PORT
      LAYER M5 ;
        RECT  70.608 0 70.632 0.192 ;
    END
  END rs_d[324]
  PIN rs_d[325]
    DIRECTION INPUT ;
    USE SIGNAL ;
    PORT
      LAYER M3 ;
        RECT  70.812 0 70.83 0.144 ;
    END
  END rs_d[325]
  PIN rs_d[326]
    DIRECTION INPUT ;
    USE SIGNAL ;
    PORT
      LAYER M5 ;
        RECT  70.992 0 71.016 0.192 ;
    END
  END rs_d[326]
  PIN rs_d[327]
    DIRECTION INPUT ;
    USE SIGNAL ;
    PORT
      LAYER M3 ;
        RECT  71.208 0 71.226 0.144 ;
    END
  END rs_d[327]
  PIN rs_d[328]
    DIRECTION INPUT ;
    USE SIGNAL ;
    PORT
      LAYER M5 ;
        RECT  71.424 0 71.448 0.192 ;
    END
  END rs_d[328]
  PIN rs_d[329]
    DIRECTION INPUT ;
    USE SIGNAL ;
    PORT
      LAYER M3 ;
        RECT  71.604 0 71.622 0.144 ;
    END
  END rs_d[329]
  PIN rs_d[32]
    DIRECTION INPUT ;
    USE SIGNAL ;
    PORT
      LAYER M5 ;
        RECT  11.856 0 11.88 0.192 ;
    END
  END rs_d[32]
  PIN rs_d[330]
    DIRECTION INPUT ;
    USE SIGNAL ;
    PORT
      LAYER M5 ;
        RECT  71.808 0 71.832 0.192 ;
    END
  END rs_d[330]
  PIN rs_d[331]
    DIRECTION INPUT ;
    USE SIGNAL ;
    PORT
      LAYER M3 ;
        RECT  72 0 72.018 0.144 ;
    END
  END rs_d[331]
  PIN rs_d[332]
    DIRECTION INPUT ;
    USE SIGNAL ;
    PORT
      LAYER M5 ;
        RECT  72.192 0 72.216 0.192 ;
    END
  END rs_d[332]
  PIN rs_d[333]
    DIRECTION INPUT ;
    USE SIGNAL ;
    PORT
      LAYER M3 ;
        RECT  72.396 0 72.414 0.144 ;
    END
  END rs_d[333]
  PIN rs_d[334]
    DIRECTION INPUT ;
    USE SIGNAL ;
    PORT
      LAYER M5 ;
        RECT  72.624 0 72.648 0.192 ;
    END
  END rs_d[334]
  PIN rs_d[335]
    DIRECTION INPUT ;
    USE SIGNAL ;
    PORT
      LAYER M3 ;
        RECT  72.828 0 72.846 0.144 ;
    END
  END rs_d[335]
  PIN rs_d[336]
    DIRECTION INPUT ;
    USE SIGNAL ;
    PORT
      LAYER M5 ;
        RECT  73.008 0 73.032 0.192 ;
    END
  END rs_d[336]
  PIN rs_d[337]
    DIRECTION INPUT ;
    USE SIGNAL ;
    PORT
      LAYER M3 ;
        RECT  73.224 0 73.242 0.144 ;
    END
  END rs_d[337]
  PIN rs_d[338]
    DIRECTION INPUT ;
    USE SIGNAL ;
    PORT
      LAYER M5 ;
        RECT  73.44 0 73.464 0.192 ;
    END
  END rs_d[338]
  PIN rs_d[339]
    DIRECTION INPUT ;
    USE SIGNAL ;
    PORT
      LAYER M3 ;
        RECT  73.62 0 73.638 0.144 ;
    END
  END rs_d[339]
  PIN rs_d[33]
    DIRECTION INPUT ;
    USE SIGNAL ;
    PORT
      LAYER M3 ;
        RECT  12.06 0 12.078 0.144 ;
    END
  END rs_d[33]
  PIN rs_d[340]
    DIRECTION INPUT ;
    USE SIGNAL ;
    PORT
      LAYER M5 ;
        RECT  73.824 0 73.848 0.192 ;
    END
  END rs_d[340]
  PIN rs_d[341]
    DIRECTION INPUT ;
    USE SIGNAL ;
    PORT
      LAYER M3 ;
        RECT  74.016 0 74.034 0.144 ;
    END
  END rs_d[341]
  PIN rs_d[342]
    DIRECTION INPUT ;
    USE SIGNAL ;
    PORT
      LAYER M5 ;
        RECT  74.208 0 74.232 0.192 ;
    END
  END rs_d[342]
  PIN rs_d[343]
    DIRECTION INPUT ;
    USE SIGNAL ;
    PORT
      LAYER M3 ;
        RECT  74.412 0 74.43 0.144 ;
    END
  END rs_d[343]
  PIN rs_d[344]
    DIRECTION INPUT ;
    USE SIGNAL ;
    PORT
      LAYER M5 ;
        RECT  74.64 0 74.664 0.192 ;
    END
  END rs_d[344]
  PIN rs_d[345]
    DIRECTION INPUT ;
    USE SIGNAL ;
    PORT
      LAYER M3 ;
        RECT  74.844 0 74.862 0.144 ;
    END
  END rs_d[345]
  PIN rs_d[346]
    DIRECTION INPUT ;
    USE SIGNAL ;
    PORT
      LAYER M5 ;
        RECT  75.024 0 75.048 0.192 ;
    END
  END rs_d[346]
  PIN rs_d[347]
    DIRECTION INPUT ;
    USE SIGNAL ;
    PORT
      LAYER M3 ;
        RECT  75.24 0 75.258 0.144 ;
    END
  END rs_d[347]
  PIN rs_d[348]
    DIRECTION INPUT ;
    USE SIGNAL ;
    PORT
      LAYER M5 ;
        RECT  75.408 0 75.432 0.192 ;
    END
  END rs_d[348]
  PIN rs_d[349]
    DIRECTION INPUT ;
    USE SIGNAL ;
    PORT
      LAYER M3 ;
        RECT  75.636 0 75.654 0.144 ;
    END
  END rs_d[349]
  PIN rs_d[34]
    DIRECTION INPUT ;
    USE SIGNAL ;
    PORT
      LAYER M5 ;
        RECT  12.24 0 12.264 0.192 ;
    END
  END rs_d[34]
  PIN rs_d[350]
    DIRECTION INPUT ;
    USE SIGNAL ;
    PORT
      LAYER M5 ;
        RECT  75.84 0 75.864 0.192 ;
    END
  END rs_d[350]
  PIN rs_d[351]
    DIRECTION INPUT ;
    USE SIGNAL ;
    PORT
      LAYER M3 ;
        RECT  76.032 0 76.05 0.144 ;
    END
  END rs_d[351]
  PIN rs_d[352]
    DIRECTION INPUT ;
    USE SIGNAL ;
    PORT
      LAYER M5 ;
        RECT  76.224 0 76.248 0.192 ;
    END
  END rs_d[352]
  PIN rs_d[353]
    DIRECTION INPUT ;
    USE SIGNAL ;
    PORT
      LAYER M3 ;
        RECT  76.428 0 76.446 0.144 ;
    END
  END rs_d[353]
  PIN rs_d[354]
    DIRECTION INPUT ;
    USE SIGNAL ;
    PORT
      LAYER M5 ;
        RECT  76.656 0 76.68 0.192 ;
    END
  END rs_d[354]
  PIN rs_d[355]
    DIRECTION INPUT ;
    USE SIGNAL ;
    PORT
      LAYER M3 ;
        RECT  76.824 0 76.842 0.144 ;
    END
  END rs_d[355]
  PIN rs_d[356]
    DIRECTION INPUT ;
    USE SIGNAL ;
    PORT
      LAYER M5 ;
        RECT  77.04 0 77.064 0.192 ;
    END
  END rs_d[356]
  PIN rs_d[357]
    DIRECTION INPUT ;
    USE SIGNAL ;
    PORT
      LAYER M3 ;
        RECT  77.256 0 77.274 0.144 ;
    END
  END rs_d[357]
  PIN rs_d[358]
    DIRECTION INPUT ;
    USE SIGNAL ;
    PORT
      LAYER M5 ;
        RECT  77.424 0 77.448 0.192 ;
    END
  END rs_d[358]
  PIN rs_d[359]
    DIRECTION INPUT ;
    USE SIGNAL ;
    PORT
      LAYER M3 ;
        RECT  77.652 0 77.67 0.144 ;
    END
  END rs_d[359]
  PIN rs_d[35]
    DIRECTION INPUT ;
    USE SIGNAL ;
    PORT
      LAYER M3 ;
        RECT  12.456 0 12.474 0.144 ;
    END
  END rs_d[35]
  PIN rs_d[360]
    DIRECTION INPUT ;
    USE SIGNAL ;
    PORT
      LAYER M5 ;
        RECT  77.856 0 77.88 0.192 ;
    END
  END rs_d[360]
  PIN rs_d[361]
    DIRECTION INPUT ;
    USE SIGNAL ;
    PORT
      LAYER M3 ;
        RECT  78.048 0 78.066 0.144 ;
    END
  END rs_d[361]
  PIN rs_d[362]
    DIRECTION INPUT ;
    USE SIGNAL ;
    PORT
      LAYER M5 ;
        RECT  78.24 0 78.264 0.192 ;
    END
  END rs_d[362]
  PIN rs_d[363]
    DIRECTION INPUT ;
    USE SIGNAL ;
    PORT
      LAYER M3 ;
        RECT  78.444 0 78.462 0.144 ;
    END
  END rs_d[363]
  PIN rs_d[364]
    DIRECTION INPUT ;
    USE SIGNAL ;
    PORT
      LAYER M5 ;
        RECT  78.624 0 78.648 0.192 ;
    END
  END rs_d[364]
  PIN rs_d[365]
    DIRECTION INPUT ;
    USE SIGNAL ;
    PORT
      LAYER M3 ;
        RECT  78.84 0 78.858 0.144 ;
    END
  END rs_d[365]
  PIN rs_d[366]
    DIRECTION INPUT ;
    USE SIGNAL ;
    PORT
      LAYER M5 ;
        RECT  79.056 0 79.08 0.192 ;
    END
  END rs_d[366]
  PIN rs_d[367]
    DIRECTION INPUT ;
    USE SIGNAL ;
    PORT
      LAYER M3 ;
        RECT  79.272 0 79.29 0.144 ;
    END
  END rs_d[367]
  PIN rs_d[368]
    DIRECTION INPUT ;
    USE SIGNAL ;
    PORT
      LAYER M5 ;
        RECT  79.44 0 79.464 0.192 ;
    END
  END rs_d[368]
  PIN rs_d[369]
    DIRECTION INPUT ;
    USE SIGNAL ;
    PORT
      LAYER M3 ;
        RECT  79.668 0 79.686 0.144 ;
    END
  END rs_d[369]
  PIN rs_d[36]
    DIRECTION INPUT ;
    USE SIGNAL ;
    PORT
      LAYER M5 ;
        RECT  12.672 0 12.696 0.192 ;
    END
  END rs_d[36]
  PIN rs_d[370]
    DIRECTION INPUT ;
    USE SIGNAL ;
    PORT
      LAYER M5 ;
        RECT  79.872 0 79.896 0.192 ;
    END
  END rs_d[370]
  PIN rs_d[371]
    DIRECTION INPUT ;
    USE SIGNAL ;
    PORT
      LAYER M3 ;
        RECT  80.064 0 80.082 0.144 ;
    END
  END rs_d[371]
  PIN rs_d[372]
    DIRECTION INPUT ;
    USE SIGNAL ;
    PORT
      LAYER M5 ;
        RECT  80.256 0 80.28 0.192 ;
    END
  END rs_d[372]
  PIN rs_d[373]
    DIRECTION INPUT ;
    USE SIGNAL ;
    PORT
      LAYER M3 ;
        RECT  80.46 0 80.478 0.144 ;
    END
  END rs_d[373]
  PIN rs_d[374]
    DIRECTION INPUT ;
    USE SIGNAL ;
    PORT
      LAYER M5 ;
        RECT  80.64 0 80.664 0.192 ;
    END
  END rs_d[374]
  PIN rs_d[375]
    DIRECTION INPUT ;
    USE SIGNAL ;
    PORT
      LAYER M3 ;
        RECT  80.856 0 80.874 0.144 ;
    END
  END rs_d[375]
  PIN rs_d[376]
    DIRECTION INPUT ;
    USE SIGNAL ;
    PORT
      LAYER M5 ;
        RECT  81.072 0 81.096 0.192 ;
    END
  END rs_d[376]
  PIN rs_d[377]
    DIRECTION INPUT ;
    USE SIGNAL ;
    PORT
      LAYER M3 ;
        RECT  81.252 0 81.27 0.144 ;
    END
  END rs_d[377]
  PIN rs_d[378]
    DIRECTION INPUT ;
    USE SIGNAL ;
    PORT
      LAYER M5 ;
        RECT  81.456 0 81.48 0.192 ;
    END
  END rs_d[378]
  PIN rs_d[379]
    DIRECTION INPUT ;
    USE SIGNAL ;
    PORT
      LAYER M3 ;
        RECT  81.684 0 81.702 0.144 ;
    END
  END rs_d[379]
  PIN rs_d[37]
    DIRECTION INPUT ;
    USE SIGNAL ;
    PORT
      LAYER M3 ;
        RECT  12.852 0 12.87 0.144 ;
    END
  END rs_d[37]
  PIN rs_d[380]
    DIRECTION INPUT ;
    USE SIGNAL ;
    PORT
      LAYER M5 ;
        RECT  81.888 0 81.912 0.192 ;
    END
  END rs_d[380]
  PIN rs_d[381]
    DIRECTION INPUT ;
    USE SIGNAL ;
    PORT
      LAYER M3 ;
        RECT  82.08 0 82.098 0.144 ;
    END
  END rs_d[381]
  PIN rs_d[382]
    DIRECTION INPUT ;
    USE SIGNAL ;
    PORT
      LAYER M5 ;
        RECT  82.272 0 82.296 0.192 ;
    END
  END rs_d[382]
  PIN rs_d[383]
    DIRECTION INPUT ;
    USE SIGNAL ;
    PORT
      LAYER M3 ;
        RECT  82.476 0 82.494 0.144 ;
    END
  END rs_d[383]
  PIN rs_d[384]
    DIRECTION INPUT ;
    USE SIGNAL ;
    PORT
      LAYER M5 ;
        RECT  82.656 0 82.68 0.192 ;
    END
  END rs_d[384]
  PIN rs_d[385]
    DIRECTION INPUT ;
    USE SIGNAL ;
    PORT
      LAYER M3 ;
        RECT  82.872 0 82.89 0.144 ;
    END
  END rs_d[385]
  PIN rs_d[386]
    DIRECTION INPUT ;
    USE SIGNAL ;
    PORT
      LAYER M5 ;
        RECT  83.088 0 83.112 0.192 ;
    END
  END rs_d[386]
  PIN rs_d[387]
    DIRECTION INPUT ;
    USE SIGNAL ;
    PORT
      LAYER M3 ;
        RECT  83.268 0 83.286 0.144 ;
    END
  END rs_d[387]
  PIN rs_d[388]
    DIRECTION INPUT ;
    USE SIGNAL ;
    PORT
      LAYER M5 ;
        RECT  83.472 0 83.496 0.192 ;
    END
  END rs_d[388]
  PIN rs_d[389]
    DIRECTION INPUT ;
    USE SIGNAL ;
    PORT
      LAYER M3 ;
        RECT  83.664 0 83.682 0.144 ;
    END
  END rs_d[389]
  PIN rs_d[38]
    DIRECTION INPUT ;
    USE SIGNAL ;
    PORT
      LAYER M5 ;
        RECT  13.056 0 13.08 0.192 ;
    END
  END rs_d[38]
  PIN rs_d[390]
    DIRECTION INPUT ;
    USE SIGNAL ;
    PORT
      LAYER M5 ;
        RECT  83.856 0 83.88 0.192 ;
    END
  END rs_d[390]
  PIN rs_d[391]
    DIRECTION INPUT ;
    USE SIGNAL ;
    PORT
      LAYER M3 ;
        RECT  84.096 0 84.114 0.144 ;
    END
  END rs_d[391]
  PIN rs_d[392]
    DIRECTION INPUT ;
    USE SIGNAL ;
    PORT
      LAYER M5 ;
        RECT  84.288 0 84.312 0.192 ;
    END
  END rs_d[392]
  PIN rs_d[393]
    DIRECTION INPUT ;
    USE SIGNAL ;
    PORT
      LAYER M3 ;
        RECT  84.492 0 84.51 0.144 ;
    END
  END rs_d[393]
  PIN rs_d[394]
    DIRECTION INPUT ;
    USE SIGNAL ;
    PORT
      LAYER M5 ;
        RECT  84.672 0 84.696 0.192 ;
    END
  END rs_d[394]
  PIN rs_d[395]
    DIRECTION INPUT ;
    USE SIGNAL ;
    PORT
      LAYER M3 ;
        RECT  84.888 0 84.906 0.144 ;
    END
  END rs_d[395]
  PIN rs_d[396]
    DIRECTION INPUT ;
    USE SIGNAL ;
    PORT
      LAYER M5 ;
        RECT  85.104 0 85.128 0.192 ;
    END
  END rs_d[396]
  PIN rs_d[397]
    DIRECTION INPUT ;
    USE SIGNAL ;
    PORT
      LAYER M3 ;
        RECT  85.284 0 85.302 0.144 ;
    END
  END rs_d[397]
  PIN rs_d[398]
    DIRECTION INPUT ;
    USE SIGNAL ;
    PORT
      LAYER M5 ;
        RECT  85.488 0 85.512 0.192 ;
    END
  END rs_d[398]
  PIN rs_d[399]
    DIRECTION INPUT ;
    USE SIGNAL ;
    PORT
      LAYER M3 ;
        RECT  85.68 0 85.698 0.144 ;
    END
  END rs_d[399]
  PIN rs_d[39]
    DIRECTION INPUT ;
    USE SIGNAL ;
    PORT
      LAYER M3 ;
        RECT  13.248 0 13.266 0.144 ;
    END
  END rs_d[39]
  PIN rs_d[3]
    DIRECTION INPUT ;
    USE SIGNAL ;
    PORT
      LAYER M3 ;
        RECT  6.012 0 6.03 0.144 ;
    END
  END rs_d[3]
  PIN rs_d[400]
    DIRECTION INPUT ;
    USE SIGNAL ;
    PORT
      LAYER M5 ;
        RECT  85.872 0 85.896 0.192 ;
    END
  END rs_d[400]
  PIN rs_d[401]
    DIRECTION INPUT ;
    USE SIGNAL ;
    PORT
      LAYER M3 ;
        RECT  86.112 0 86.13 0.144 ;
    END
  END rs_d[401]
  PIN rs_d[402]
    DIRECTION INPUT ;
    USE SIGNAL ;
    PORT
      LAYER M5 ;
        RECT  86.304 0 86.328 0.192 ;
    END
  END rs_d[402]
  PIN rs_d[403]
    DIRECTION INPUT ;
    USE SIGNAL ;
    PORT
      LAYER M3 ;
        RECT  86.508 0 86.526 0.144 ;
    END
  END rs_d[403]
  PIN rs_d[404]
    DIRECTION INPUT ;
    USE SIGNAL ;
    PORT
      LAYER M5 ;
        RECT  86.688 0 86.712 0.192 ;
    END
  END rs_d[404]
  PIN rs_d[405]
    DIRECTION INPUT ;
    USE SIGNAL ;
    PORT
      LAYER M3 ;
        RECT  86.904 0 86.922 0.144 ;
    END
  END rs_d[405]
  PIN rs_d[406]
    DIRECTION INPUT ;
    USE SIGNAL ;
    PORT
      LAYER M5 ;
        RECT  87.12 0 87.144 0.192 ;
    END
  END rs_d[406]
  PIN rs_d[407]
    DIRECTION INPUT ;
    USE SIGNAL ;
    PORT
      LAYER M3 ;
        RECT  87.3 0 87.318 0.144 ;
    END
  END rs_d[407]
  PIN rs_d[408]
    DIRECTION INPUT ;
    USE SIGNAL ;
    PORT
      LAYER M5 ;
        RECT  87.504 0 87.528 0.192 ;
    END
  END rs_d[408]
  PIN rs_d[409]
    DIRECTION INPUT ;
    USE SIGNAL ;
    PORT
      LAYER M3 ;
        RECT  87.696 0 87.714 0.144 ;
    END
  END rs_d[409]
  PIN rs_d[40]
    DIRECTION INPUT ;
    USE SIGNAL ;
    PORT
      LAYER M5 ;
        RECT  13.44 0 13.464 0.192 ;
    END
  END rs_d[40]
  PIN rs_d[410]
    DIRECTION INPUT ;
    USE SIGNAL ;
    PORT
      LAYER M5 ;
        RECT  87.888 0 87.912 0.192 ;
    END
  END rs_d[410]
  PIN rs_d[411]
    DIRECTION INPUT ;
    USE SIGNAL ;
    PORT
      LAYER M3 ;
        RECT  88.092 0 88.11 0.144 ;
    END
  END rs_d[411]
  PIN rs_d[412]
    DIRECTION INPUT ;
    USE SIGNAL ;
    PORT
      LAYER M5 ;
        RECT  88.32 0 88.344 0.192 ;
    END
  END rs_d[412]
  PIN rs_d[413]
    DIRECTION INPUT ;
    USE SIGNAL ;
    PORT
      LAYER M3 ;
        RECT  88.524 0 88.542 0.144 ;
    END
  END rs_d[413]
  PIN rs_d[414]
    DIRECTION INPUT ;
    USE SIGNAL ;
    PORT
      LAYER M5 ;
        RECT  88.704 0 88.728 0.192 ;
    END
  END rs_d[414]
  PIN rs_d[415]
    DIRECTION INPUT ;
    USE SIGNAL ;
    PORT
      LAYER M3 ;
        RECT  88.92 0 88.938 0.144 ;
    END
  END rs_d[415]
  PIN rs_d[416]
    DIRECTION INPUT ;
    USE SIGNAL ;
    PORT
      LAYER M5 ;
        RECT  89.088 0 89.112 0.192 ;
    END
  END rs_d[416]
  PIN rs_d[417]
    DIRECTION INPUT ;
    USE SIGNAL ;
    PORT
      LAYER M3 ;
        RECT  89.316 0 89.334 0.144 ;
    END
  END rs_d[417]
  PIN rs_d[418]
    DIRECTION INPUT ;
    USE SIGNAL ;
    PORT
      LAYER M5 ;
        RECT  89.52 0 89.544 0.192 ;
    END
  END rs_d[418]
  PIN rs_d[419]
    DIRECTION INPUT ;
    USE SIGNAL ;
    PORT
      LAYER M3 ;
        RECT  89.712 0 89.73 0.144 ;
    END
  END rs_d[419]
  PIN rs_d[41]
    DIRECTION INPUT ;
    USE SIGNAL ;
    PORT
      LAYER M3 ;
        RECT  13.68 0 13.698 0.144 ;
    END
  END rs_d[41]
  PIN rs_d[420]
    DIRECTION INPUT ;
    USE SIGNAL ;
    PORT
      LAYER M5 ;
        RECT  89.904 0 89.928 0.192 ;
    END
  END rs_d[420]
  PIN rs_d[421]
    DIRECTION INPUT ;
    USE SIGNAL ;
    PORT
      LAYER M3 ;
        RECT  90.108 0 90.126 0.144 ;
    END
  END rs_d[421]
  PIN rs_d[422]
    DIRECTION INPUT ;
    USE SIGNAL ;
    PORT
      LAYER M5 ;
        RECT  90.336 0 90.36 0.192 ;
    END
  END rs_d[422]
  PIN rs_d[423]
    DIRECTION INPUT ;
    USE SIGNAL ;
    PORT
      LAYER M3 ;
        RECT  90.504 0 90.522 0.144 ;
    END
  END rs_d[423]
  PIN rs_d[424]
    DIRECTION INPUT ;
    USE SIGNAL ;
    PORT
      LAYER M5 ;
        RECT  90.72 0 90.744 0.192 ;
    END
  END rs_d[424]
  PIN rs_d[425]
    DIRECTION INPUT ;
    USE SIGNAL ;
    PORT
      LAYER M3 ;
        RECT  90.936 0 90.954 0.144 ;
    END
  END rs_d[425]
  PIN rs_d[426]
    DIRECTION INPUT ;
    USE SIGNAL ;
    PORT
      LAYER M5 ;
        RECT  91.104 0 91.128 0.192 ;
    END
  END rs_d[426]
  PIN rs_d[427]
    DIRECTION INPUT ;
    USE SIGNAL ;
    PORT
      LAYER M3 ;
        RECT  91.332 0 91.35 0.144 ;
    END
  END rs_d[427]
  PIN rs_d[428]
    DIRECTION INPUT ;
    USE SIGNAL ;
    PORT
      LAYER M5 ;
        RECT  91.536 0 91.56 0.192 ;
    END
  END rs_d[428]
  PIN rs_d[429]
    DIRECTION INPUT ;
    USE SIGNAL ;
    PORT
      LAYER M3 ;
        RECT  91.728 0 91.746 0.144 ;
    END
  END rs_d[429]
  PIN rs_d[42]
    DIRECTION INPUT ;
    USE SIGNAL ;
    PORT
      LAYER M5 ;
        RECT  13.872 0 13.896 0.192 ;
    END
  END rs_d[42]
  PIN rs_d[430]
    DIRECTION INPUT ;
    USE SIGNAL ;
    PORT
      LAYER M5 ;
        RECT  91.92 0 91.944 0.192 ;
    END
  END rs_d[430]
  PIN rs_d[431]
    DIRECTION INPUT ;
    USE SIGNAL ;
    PORT
      LAYER M3 ;
        RECT  92.124 0 92.142 0.144 ;
    END
  END rs_d[431]
  PIN rs_d[432]
    DIRECTION INPUT ;
    USE SIGNAL ;
    PORT
      LAYER M5 ;
        RECT  92.352 0 92.376 0.192 ;
    END
  END rs_d[432]
  PIN rs_d[433]
    DIRECTION INPUT ;
    USE SIGNAL ;
    PORT
      LAYER M3 ;
        RECT  92.52 0 92.538 0.144 ;
    END
  END rs_d[433]
  PIN rs_d[434]
    DIRECTION INPUT ;
    USE SIGNAL ;
    PORT
      LAYER M5 ;
        RECT  92.736 0 92.76 0.192 ;
    END
  END rs_d[434]
  PIN rs_d[435]
    DIRECTION INPUT ;
    USE SIGNAL ;
    PORT
      LAYER M3 ;
        RECT  92.952 0 92.97 0.144 ;
    END
  END rs_d[435]
  PIN rs_d[436]
    DIRECTION INPUT ;
    USE SIGNAL ;
    PORT
      LAYER M5 ;
        RECT  93.12 0 93.144 0.192 ;
    END
  END rs_d[436]
  PIN rs_d[437]
    DIRECTION INPUT ;
    USE SIGNAL ;
    PORT
      LAYER M3 ;
        RECT  93.348 0 93.366 0.144 ;
    END
  END rs_d[437]
  PIN rs_d[438]
    DIRECTION INPUT ;
    USE SIGNAL ;
    PORT
      LAYER M5 ;
        RECT  93.552 0 93.576 0.192 ;
    END
  END rs_d[438]
  PIN rs_d[439]
    DIRECTION INPUT ;
    USE SIGNAL ;
    PORT
      LAYER M3 ;
        RECT  93.744 0 93.762 0.144 ;
    END
  END rs_d[439]
  PIN rs_d[43]
    DIRECTION INPUT ;
    USE SIGNAL ;
    PORT
      LAYER M3 ;
        RECT  14.076 0 14.094 0.144 ;
    END
  END rs_d[43]
  PIN rs_d[440]
    DIRECTION INPUT ;
    USE SIGNAL ;
    PORT
      LAYER M5 ;
        RECT  93.936 0 93.96 0.192 ;
    END
  END rs_d[440]
  PIN rs_d[441]
    DIRECTION INPUT ;
    USE SIGNAL ;
    PORT
      LAYER M3 ;
        RECT  94.14 0 94.158 0.144 ;
    END
  END rs_d[441]
  PIN rs_d[442]
    DIRECTION INPUT ;
    USE SIGNAL ;
    PORT
      LAYER M5 ;
        RECT  94.32 0 94.344 0.192 ;
    END
  END rs_d[442]
  PIN rs_d[443]
    DIRECTION INPUT ;
    USE SIGNAL ;
    PORT
      LAYER M3 ;
        RECT  94.536 0 94.554 0.144 ;
    END
  END rs_d[443]
  PIN rs_d[444]
    DIRECTION INPUT ;
    USE SIGNAL ;
    PORT
      LAYER M5 ;
        RECT  94.752 0 94.776 0.192 ;
    END
  END rs_d[444]
  PIN rs_d[445]
    DIRECTION INPUT ;
    USE SIGNAL ;
    PORT
      LAYER M3 ;
        RECT  94.932 0 94.95 0.144 ;
    END
  END rs_d[445]
  PIN rs_d[446]
    DIRECTION INPUT ;
    USE SIGNAL ;
    PORT
      LAYER M5 ;
        RECT  95.136 0 95.16 0.192 ;
    END
  END rs_d[446]
  PIN rs_d[447]
    DIRECTION INPUT ;
    USE SIGNAL ;
    PORT
      LAYER M3 ;
        RECT  95.364 0 95.382 0.144 ;
    END
  END rs_d[447]
  PIN rs_d[448]
    DIRECTION INPUT ;
    USE SIGNAL ;
    PORT
      LAYER M5 ;
        RECT  95.568 0 95.592 0.192 ;
    END
  END rs_d[448]
  PIN rs_d[449]
    DIRECTION INPUT ;
    USE SIGNAL ;
    PORT
      LAYER M3 ;
        RECT  95.76 0 95.778 0.144 ;
    END
  END rs_d[449]
  PIN rs_d[44]
    DIRECTION INPUT ;
    USE SIGNAL ;
    PORT
      LAYER M5 ;
        RECT  14.256 0 14.28 0.192 ;
    END
  END rs_d[44]
  PIN rs_d[450]
    DIRECTION INPUT ;
    USE SIGNAL ;
    PORT
      LAYER M5 ;
        RECT  95.952 0 95.976 0.192 ;
    END
  END rs_d[450]
  PIN rs_d[451]
    DIRECTION INPUT ;
    USE SIGNAL ;
    PORT
      LAYER M3 ;
        RECT  96.156 0 96.174 0.144 ;
    END
  END rs_d[451]
  PIN rs_d[452]
    DIRECTION INPUT ;
    USE SIGNAL ;
    PORT
      LAYER M5 ;
        RECT  96.336 0 96.36 0.192 ;
    END
  END rs_d[452]
  PIN rs_d[453]
    DIRECTION INPUT ;
    USE SIGNAL ;
    PORT
      LAYER M3 ;
        RECT  96.552 0 96.57 0.144 ;
    END
  END rs_d[453]
  PIN rs_d[454]
    DIRECTION INPUT ;
    USE SIGNAL ;
    PORT
      LAYER M5 ;
        RECT  96.768 0 96.792 0.192 ;
    END
  END rs_d[454]
  PIN rs_d[455]
    DIRECTION INPUT ;
    USE SIGNAL ;
    PORT
      LAYER M3 ;
        RECT  96.948 0 96.966 0.144 ;
    END
  END rs_d[455]
  PIN rs_d[456]
    DIRECTION INPUT ;
    USE SIGNAL ;
    PORT
      LAYER M5 ;
        RECT  97.152 0 97.176 0.192 ;
    END
  END rs_d[456]
  PIN rs_d[457]
    DIRECTION INPUT ;
    USE SIGNAL ;
    PORT
      LAYER M3 ;
        RECT  97.344 0 97.362 0.144 ;
    END
  END rs_d[457]
  PIN rs_d[458]
    DIRECTION INPUT ;
    USE SIGNAL ;
    PORT
      LAYER M5 ;
        RECT  97.536 0 97.56 0.192 ;
    END
  END rs_d[458]
  PIN rs_d[459]
    DIRECTION INPUT ;
    USE SIGNAL ;
    PORT
      LAYER M3 ;
        RECT  97.776 0 97.794 0.144 ;
    END
  END rs_d[459]
  PIN rs_d[45]
    DIRECTION INPUT ;
    USE SIGNAL ;
    PORT
      LAYER M3 ;
        RECT  14.472 0 14.49 0.144 ;
    END
  END rs_d[45]
  PIN rs_d[460]
    DIRECTION INPUT ;
    USE SIGNAL ;
    PORT
      LAYER M5 ;
        RECT  97.968 0 97.992 0.192 ;
    END
  END rs_d[460]
  PIN rs_d[461]
    DIRECTION INPUT ;
    USE SIGNAL ;
    PORT
      LAYER M3 ;
        RECT  98.172 0 98.19 0.144 ;
    END
  END rs_d[461]
  PIN rs_d[462]
    DIRECTION INPUT ;
    USE SIGNAL ;
    PORT
      LAYER M5 ;
        RECT  98.352 0 98.376 0.192 ;
    END
  END rs_d[462]
  PIN rs_d[463]
    DIRECTION INPUT ;
    USE SIGNAL ;
    PORT
      LAYER M3 ;
        RECT  98.568 0 98.586 0.144 ;
    END
  END rs_d[463]
  PIN rs_d[464]
    DIRECTION INPUT ;
    USE SIGNAL ;
    PORT
      LAYER M5 ;
        RECT  98.784 0 98.808 0.192 ;
    END
  END rs_d[464]
  PIN rs_d[465]
    DIRECTION INPUT ;
    USE SIGNAL ;
    PORT
      LAYER M3 ;
        RECT  98.964 0 98.982 0.144 ;
    END
  END rs_d[465]
  PIN rs_d[466]
    DIRECTION INPUT ;
    USE SIGNAL ;
    PORT
      LAYER M5 ;
        RECT  99.168 0 99.192 0.192 ;
    END
  END rs_d[466]
  PIN rs_d[467]
    DIRECTION INPUT ;
    USE SIGNAL ;
    PORT
      LAYER M3 ;
        RECT  99.36 0 99.378 0.144 ;
    END
  END rs_d[467]
  PIN rs_d[468]
    DIRECTION INPUT ;
    USE SIGNAL ;
    PORT
      LAYER M5 ;
        RECT  99.552 0 99.576 0.192 ;
    END
  END rs_d[468]
  PIN rs_d[469]
    DIRECTION INPUT ;
    USE SIGNAL ;
    PORT
      LAYER M3 ;
        RECT  99.792 0 99.81 0.144 ;
    END
  END rs_d[469]
  PIN rs_d[46]
    DIRECTION INPUT ;
    USE SIGNAL ;
    PORT
      LAYER M5 ;
        RECT  14.688 0 14.712 0.192 ;
    END
  END rs_d[46]
  PIN rs_d[470]
    DIRECTION INPUT ;
    USE SIGNAL ;
    PORT
      LAYER M5 ;
        RECT  99.984 0 100.008 0.192 ;
    END
  END rs_d[470]
  PIN rs_d[471]
    DIRECTION INPUT ;
    USE SIGNAL ;
    PORT
      LAYER M3 ;
        RECT  100.188 0 100.206 0.144 ;
    END
  END rs_d[471]
  PIN rs_d[472]
    DIRECTION INPUT ;
    USE SIGNAL ;
    PORT
      LAYER M5 ;
        RECT  100.368 0 100.392 0.192 ;
    END
  END rs_d[472]
  PIN rs_d[473]
    DIRECTION INPUT ;
    USE SIGNAL ;
    PORT
      LAYER M3 ;
        RECT  100.584 0 100.602 0.144 ;
    END
  END rs_d[473]
  PIN rs_d[474]
    DIRECTION INPUT ;
    USE SIGNAL ;
    PORT
      LAYER M5 ;
        RECT  100.8 0 100.824 0.192 ;
    END
  END rs_d[474]
  PIN rs_d[475]
    DIRECTION INPUT ;
    USE SIGNAL ;
    PORT
      LAYER M3 ;
        RECT  100.98 0 100.998 0.144 ;
    END
  END rs_d[475]
  PIN rs_d[476]
    DIRECTION INPUT ;
    USE SIGNAL ;
    PORT
      LAYER M5 ;
        RECT  101.184 0 101.208 0.192 ;
    END
  END rs_d[476]
  PIN rs_d[477]
    DIRECTION INPUT ;
    USE SIGNAL ;
    PORT
      LAYER M3 ;
        RECT  101.376 0 101.394 0.144 ;
    END
  END rs_d[477]
  PIN rs_d[478]
    DIRECTION INPUT ;
    USE SIGNAL ;
    PORT
      LAYER M5 ;
        RECT  101.568 0 101.592 0.192 ;
    END
  END rs_d[478]
  PIN rs_d[479]
    DIRECTION INPUT ;
    USE SIGNAL ;
    PORT
      LAYER M3 ;
        RECT  101.772 0 101.79 0.144 ;
    END
  END rs_d[479]
  PIN rs_d[47]
    DIRECTION INPUT ;
    USE SIGNAL ;
    PORT
      LAYER M3 ;
        RECT  14.868 0 14.886 0.144 ;
    END
  END rs_d[47]
  PIN rs_d[480]
    DIRECTION INPUT ;
    USE SIGNAL ;
    PORT
      LAYER M5 ;
        RECT  102 0 102.024 0.192 ;
    END
  END rs_d[480]
  PIN rs_d[481]
    DIRECTION INPUT ;
    USE SIGNAL ;
    PORT
      LAYER M3 ;
        RECT  102.204 0 102.222 0.144 ;
    END
  END rs_d[481]
  PIN rs_d[482]
    DIRECTION INPUT ;
    USE SIGNAL ;
    PORT
      LAYER M5 ;
        RECT  102.384 0 102.408 0.192 ;
    END
  END rs_d[482]
  PIN rs_d[483]
    DIRECTION INPUT ;
    USE SIGNAL ;
    PORT
      LAYER M3 ;
        RECT  102.6 0 102.618 0.144 ;
    END
  END rs_d[483]
  PIN rs_d[484]
    DIRECTION INPUT ;
    USE SIGNAL ;
    PORT
      LAYER M5 ;
        RECT  102.768 0 102.792 0.192 ;
    END
  END rs_d[484]
  PIN rs_d[485]
    DIRECTION INPUT ;
    USE SIGNAL ;
    PORT
      LAYER M3 ;
        RECT  102.996 0 103.014 0.144 ;
    END
  END rs_d[485]
  PIN rs_d[486]
    DIRECTION INPUT ;
    USE SIGNAL ;
    PORT
      LAYER M5 ;
        RECT  103.2 0 103.224 0.192 ;
    END
  END rs_d[486]
  PIN rs_d[487]
    DIRECTION INPUT ;
    USE SIGNAL ;
    PORT
      LAYER M3 ;
        RECT  103.392 0 103.41 0.144 ;
    END
  END rs_d[487]
  PIN rs_d[488]
    DIRECTION INPUT ;
    USE SIGNAL ;
    PORT
      LAYER M5 ;
        RECT  103.584 0 103.608 0.192 ;
    END
  END rs_d[488]
  PIN rs_d[489]
    DIRECTION INPUT ;
    USE SIGNAL ;
    PORT
      LAYER M3 ;
        RECT  103.788 0 103.806 0.144 ;
    END
  END rs_d[489]
  PIN rs_d[48]
    DIRECTION INPUT ;
    USE SIGNAL ;
    PORT
      LAYER M5 ;
        RECT  15.072 0 15.096 0.192 ;
    END
  END rs_d[48]
  PIN rs_d[490]
    DIRECTION INPUT ;
    USE SIGNAL ;
    PORT
      LAYER M5 ;
        RECT  104.016 0 104.04 0.192 ;
    END
  END rs_d[490]
  PIN rs_d[491]
    DIRECTION INPUT ;
    USE SIGNAL ;
    PORT
      LAYER M3 ;
        RECT  104.184 0 104.202 0.144 ;
    END
  END rs_d[491]
  PIN rs_d[492]
    DIRECTION INPUT ;
    USE SIGNAL ;
    PORT
      LAYER M5 ;
        RECT  104.4 0 104.424 0.192 ;
    END
  END rs_d[492]
  PIN rs_d[493]
    DIRECTION INPUT ;
    USE SIGNAL ;
    PORT
      LAYER M3 ;
        RECT  104.616 0 104.634 0.144 ;
    END
  END rs_d[493]
  PIN rs_d[494]
    DIRECTION INPUT ;
    USE SIGNAL ;
    PORT
      LAYER M5 ;
        RECT  104.784 0 104.808 0.192 ;
    END
  END rs_d[494]
  PIN rs_d[495]
    DIRECTION INPUT ;
    USE SIGNAL ;
    PORT
      LAYER M3 ;
        RECT  105.012 0 105.03 0.144 ;
    END
  END rs_d[495]
  PIN rs_d[496]
    DIRECTION INPUT ;
    USE SIGNAL ;
    PORT
      LAYER M5 ;
        RECT  105.216 0 105.24 0.192 ;
    END
  END rs_d[496]
  PIN rs_d[497]
    DIRECTION INPUT ;
    USE SIGNAL ;
    PORT
      LAYER M3 ;
        RECT  105.408 0 105.426 0.144 ;
    END
  END rs_d[497]
  PIN rs_d[498]
    DIRECTION INPUT ;
    USE SIGNAL ;
    PORT
      LAYER M5 ;
        RECT  105.6 0 105.624 0.192 ;
    END
  END rs_d[498]
  PIN rs_d[499]
    DIRECTION INPUT ;
    USE SIGNAL ;
    PORT
      LAYER M3 ;
        RECT  105.804 0 105.822 0.144 ;
    END
  END rs_d[499]
  PIN rs_d[49]
    DIRECTION INPUT ;
    USE SIGNAL ;
    PORT
      LAYER M3 ;
        RECT  15.264 0 15.282 0.144 ;
    END
  END rs_d[49]
  PIN rs_d[4]
    DIRECTION INPUT ;
    USE SIGNAL ;
    PORT
      LAYER M5 ;
        RECT  6.24 0 6.264 0.192 ;
    END
  END rs_d[4]
  PIN rs_d[500]
    DIRECTION INPUT ;
    USE SIGNAL ;
    PORT
      LAYER M5 ;
        RECT  106.032 0 106.056 0.192 ;
    END
  END rs_d[500]
  PIN rs_d[501]
    DIRECTION INPUT ;
    USE SIGNAL ;
    PORT
      LAYER M3 ;
        RECT  106.2 0 106.218 0.144 ;
    END
  END rs_d[501]
  PIN rs_d[502]
    DIRECTION INPUT ;
    USE SIGNAL ;
    PORT
      LAYER M5 ;
        RECT  106.416 0 106.44 0.192 ;
    END
  END rs_d[502]
  PIN rs_d[503]
    DIRECTION INPUT ;
    USE SIGNAL ;
    PORT
      LAYER M3 ;
        RECT  106.632 0 106.65 0.144 ;
    END
  END rs_d[503]
  PIN rs_d[504]
    DIRECTION INPUT ;
    USE SIGNAL ;
    PORT
      LAYER M5 ;
        RECT  106.8 0 106.824 0.192 ;
    END
  END rs_d[504]
  PIN rs_d[505]
    DIRECTION INPUT ;
    USE SIGNAL ;
    PORT
      LAYER M3 ;
        RECT  107.028 0 107.046 0.144 ;
    END
  END rs_d[505]
  PIN rs_d[506]
    DIRECTION INPUT ;
    USE SIGNAL ;
    PORT
      LAYER M5 ;
        RECT  107.232 0 107.256 0.192 ;
    END
  END rs_d[506]
  PIN rs_d[507]
    DIRECTION INPUT ;
    USE SIGNAL ;
    PORT
      LAYER M3 ;
        RECT  107.424 0 107.442 0.144 ;
    END
  END rs_d[507]
  PIN rs_d[508]
    DIRECTION INPUT ;
    USE SIGNAL ;
    PORT
      LAYER M5 ;
        RECT  107.616 0 107.64 0.192 ;
    END
  END rs_d[508]
  PIN rs_d[509]
    DIRECTION INPUT ;
    USE SIGNAL ;
    PORT
      LAYER M3 ;
        RECT  107.82 0 107.838 0.144 ;
    END
  END rs_d[509]
  PIN rs_d[50]
    DIRECTION INPUT ;
    USE SIGNAL ;
    PORT
      LAYER M5 ;
        RECT  15.456 0 15.48 0.192 ;
    END
  END rs_d[50]
  PIN rs_d[510]
    DIRECTION INPUT ;
    USE SIGNAL ;
    PORT
      LAYER M5 ;
        RECT  108 0 108.024 0.192 ;
    END
  END rs_d[510]
  PIN rs_d[511]
    DIRECTION INPUT ;
    USE SIGNAL ;
    PORT
      LAYER M3 ;
        RECT  108.216 0 108.234 0.144 ;
    END
  END rs_d[511]
  PIN rs_d[512]
    DIRECTION INPUT ;
    USE SIGNAL ;
    PORT
      LAYER M5 ;
        RECT  108.432 0 108.456 0.192 ;
    END
  END rs_d[512]
  PIN rs_d[513]
    DIRECTION INPUT ;
    USE SIGNAL ;
    PORT
      LAYER M3 ;
        RECT  108.612 0 108.63 0.144 ;
    END
  END rs_d[513]
  PIN rs_d[514]
    DIRECTION INPUT ;
    USE SIGNAL ;
    PORT
      LAYER M5 ;
        RECT  108.816 0 108.84 0.192 ;
    END
  END rs_d[514]
  PIN rs_d[515]
    DIRECTION INPUT ;
    USE SIGNAL ;
    PORT
      LAYER M3 ;
        RECT  109.044 0 109.062 0.144 ;
    END
  END rs_d[515]
  PIN rs_d[516]
    DIRECTION INPUT ;
    USE SIGNAL ;
    PORT
      LAYER M5 ;
        RECT  109.248 0 109.272 0.192 ;
    END
  END rs_d[516]
  PIN rs_d[517]
    DIRECTION INPUT ;
    USE SIGNAL ;
    PORT
      LAYER M3 ;
        RECT  109.44 0 109.458 0.144 ;
    END
  END rs_d[517]
  PIN rs_d[518]
    DIRECTION INPUT ;
    USE SIGNAL ;
    PORT
      LAYER M5 ;
        RECT  109.632 0 109.656 0.192 ;
    END
  END rs_d[518]
  PIN rs_d[519]
    DIRECTION INPUT ;
    USE SIGNAL ;
    PORT
      LAYER M3 ;
        RECT  109.836 0 109.854 0.144 ;
    END
  END rs_d[519]
  PIN rs_d[51]
    DIRECTION INPUT ;
    USE SIGNAL ;
    PORT
      LAYER M3 ;
        RECT  15.696 0 15.714 0.144 ;
    END
  END rs_d[51]
  PIN rs_d[520]
    DIRECTION INPUT ;
    USE SIGNAL ;
    PORT
      LAYER M5 ;
        RECT  110.016 0 110.04 0.192 ;
    END
  END rs_d[520]
  PIN rs_d[521]
    DIRECTION INPUT ;
    USE SIGNAL ;
    PORT
      LAYER M3 ;
        RECT  110.232 0 110.25 0.144 ;
    END
  END rs_d[521]
  PIN rs_d[522]
    DIRECTION INPUT ;
    USE SIGNAL ;
    PORT
      LAYER M5 ;
        RECT  110.448 0 110.472 0.192 ;
    END
  END rs_d[522]
  PIN rs_d[523]
    DIRECTION INPUT ;
    USE SIGNAL ;
    PORT
      LAYER M3 ;
        RECT  110.628 0 110.646 0.144 ;
    END
  END rs_d[523]
  PIN rs_d[524]
    DIRECTION INPUT ;
    USE SIGNAL ;
    PORT
      LAYER M5 ;
        RECT  110.832 0 110.856 0.192 ;
    END
  END rs_d[524]
  PIN rs_d[525]
    DIRECTION INPUT ;
    USE SIGNAL ;
    PORT
      LAYER M3 ;
        RECT  111.06 0 111.078 0.144 ;
    END
  END rs_d[525]
  PIN rs_d[526]
    DIRECTION INPUT ;
    USE SIGNAL ;
    PORT
      LAYER M5 ;
        RECT  111.264 0 111.288 0.192 ;
    END
  END rs_d[526]
  PIN rs_d[527]
    DIRECTION INPUT ;
    USE SIGNAL ;
    PORT
      LAYER M3 ;
        RECT  111.456 0 111.474 0.144 ;
    END
  END rs_d[527]
  PIN rs_d[528]
    DIRECTION INPUT ;
    USE SIGNAL ;
    PORT
      LAYER M5 ;
        RECT  111.648 0 111.672 0.192 ;
    END
  END rs_d[528]
  PIN rs_d[529]
    DIRECTION INPUT ;
    USE SIGNAL ;
    PORT
      LAYER M3 ;
        RECT  111.852 0 111.87 0.144 ;
    END
  END rs_d[529]
  PIN rs_d[52]
    DIRECTION INPUT ;
    USE SIGNAL ;
    PORT
      LAYER M5 ;
        RECT  15.888 0 15.912 0.192 ;
    END
  END rs_d[52]
  PIN rs_d[530]
    DIRECTION INPUT ;
    USE SIGNAL ;
    PORT
      LAYER M5 ;
        RECT  112.032 0 112.056 0.192 ;
    END
  END rs_d[530]
  PIN rs_d[531]
    DIRECTION INPUT ;
    USE SIGNAL ;
    PORT
      LAYER M3 ;
        RECT  112.248 0 112.266 0.144 ;
    END
  END rs_d[531]
  PIN rs_d[532]
    DIRECTION INPUT ;
    USE SIGNAL ;
    PORT
      LAYER M5 ;
        RECT  112.464 0 112.488 0.192 ;
    END
  END rs_d[532]
  PIN rs_d[533]
    DIRECTION INPUT ;
    USE SIGNAL ;
    PORT
      LAYER M3 ;
        RECT  112.644 0 112.662 0.144 ;
    END
  END rs_d[533]
  PIN rs_d[534]
    DIRECTION INPUT ;
    USE SIGNAL ;
    PORT
      LAYER M5 ;
        RECT  112.848 0 112.872 0.192 ;
    END
  END rs_d[534]
  PIN rs_d[535]
    DIRECTION INPUT ;
    USE SIGNAL ;
    PORT
      LAYER M3 ;
        RECT  113.04 0 113.058 0.144 ;
    END
  END rs_d[535]
  PIN rs_d[536]
    DIRECTION INPUT ;
    USE SIGNAL ;
    PORT
      LAYER M5 ;
        RECT  113.232 0 113.256 0.192 ;
    END
  END rs_d[536]
  PIN rs_d[537]
    DIRECTION INPUT ;
    USE SIGNAL ;
    PORT
      LAYER M3 ;
        RECT  113.472 0 113.49 0.144 ;
    END
  END rs_d[537]
  PIN rs_d[538]
    DIRECTION INPUT ;
    USE SIGNAL ;
    PORT
      LAYER M5 ;
        RECT  113.664 0 113.688 0.192 ;
    END
  END rs_d[538]
  PIN rs_d[539]
    DIRECTION INPUT ;
    USE SIGNAL ;
    PORT
      LAYER M3 ;
        RECT  113.868 0 113.886 0.144 ;
    END
  END rs_d[539]
  PIN rs_d[53]
    DIRECTION INPUT ;
    USE SIGNAL ;
    PORT
      LAYER M3 ;
        RECT  16.092 0 16.11 0.144 ;
    END
  END rs_d[53]
  PIN rs_d[540]
    DIRECTION INPUT ;
    USE SIGNAL ;
    PORT
      LAYER M5 ;
        RECT  114.048 0 114.072 0.192 ;
    END
  END rs_d[540]
  PIN rs_d[541]
    DIRECTION INPUT ;
    USE SIGNAL ;
    PORT
      LAYER M3 ;
        RECT  114.264 0 114.282 0.144 ;
    END
  END rs_d[541]
  PIN rs_d[542]
    DIRECTION INPUT ;
    USE SIGNAL ;
    PORT
      LAYER M5 ;
        RECT  114.48 0 114.504 0.192 ;
    END
  END rs_d[542]
  PIN rs_d[543]
    DIRECTION INPUT ;
    USE SIGNAL ;
    PORT
      LAYER M3 ;
        RECT  114.66 0 114.678 0.144 ;
    END
  END rs_d[543]
  PIN rs_d[544]
    DIRECTION INPUT ;
    USE SIGNAL ;
    PORT
      LAYER M5 ;
        RECT  114.864 0 114.888 0.192 ;
    END
  END rs_d[544]
  PIN rs_d[545]
    DIRECTION INPUT ;
    USE SIGNAL ;
    PORT
      LAYER M3 ;
        RECT  115.056 0 115.074 0.144 ;
    END
  END rs_d[545]
  PIN rs_d[546]
    DIRECTION INPUT ;
    USE SIGNAL ;
    PORT
      LAYER M5 ;
        RECT  115.248 0 115.272 0.192 ;
    END
  END rs_d[546]
  PIN rs_d[547]
    DIRECTION INPUT ;
    USE SIGNAL ;
    PORT
      LAYER M3 ;
        RECT  115.452 0 115.47 0.144 ;
    END
  END rs_d[547]
  PIN rs_d[548]
    DIRECTION INPUT ;
    USE SIGNAL ;
    PORT
      LAYER M5 ;
        RECT  115.68 0 115.704 0.192 ;
    END
  END rs_d[548]
  PIN rs_d[549]
    DIRECTION INPUT ;
    USE SIGNAL ;
    PORT
      LAYER M3 ;
        RECT  115.884 0 115.902 0.144 ;
    END
  END rs_d[549]
  PIN rs_d[54]
    DIRECTION INPUT ;
    USE SIGNAL ;
    PORT
      LAYER M5 ;
        RECT  16.272 0 16.296 0.192 ;
    END
  END rs_d[54]
  PIN rs_d[550]
    DIRECTION INPUT ;
    USE SIGNAL ;
    PORT
      LAYER M5 ;
        RECT  116.064 0 116.088 0.192 ;
    END
  END rs_d[550]
  PIN rs_d[551]
    DIRECTION INPUT ;
    USE SIGNAL ;
    PORT
      LAYER M3 ;
        RECT  116.28 0 116.298 0.144 ;
    END
  END rs_d[551]
  PIN rs_d[552]
    DIRECTION INPUT ;
    USE SIGNAL ;
    PORT
      LAYER M5 ;
        RECT  116.448 0 116.472 0.192 ;
    END
  END rs_d[552]
  PIN rs_d[553]
    DIRECTION INPUT ;
    USE SIGNAL ;
    PORT
      LAYER M3 ;
        RECT  116.676 0 116.694 0.144 ;
    END
  END rs_d[553]
  PIN rs_d[554]
    DIRECTION INPUT ;
    USE SIGNAL ;
    PORT
      LAYER M5 ;
        RECT  116.88 0 116.904 0.192 ;
    END
  END rs_d[554]
  PIN rs_d[555]
    DIRECTION INPUT ;
    USE SIGNAL ;
    PORT
      LAYER M3 ;
        RECT  117.072 0 117.09 0.144 ;
    END
  END rs_d[555]
  PIN rs_d[556]
    DIRECTION INPUT ;
    USE SIGNAL ;
    PORT
      LAYER M5 ;
        RECT  117.264 0 117.288 0.192 ;
    END
  END rs_d[556]
  PIN rs_d[557]
    DIRECTION INPUT ;
    USE SIGNAL ;
    PORT
      LAYER M3 ;
        RECT  117.468 0 117.486 0.144 ;
    END
  END rs_d[557]
  PIN rs_d[558]
    DIRECTION INPUT ;
    USE SIGNAL ;
    PORT
      LAYER M5 ;
        RECT  117.696 0 117.72 0.192 ;
    END
  END rs_d[558]
  PIN rs_d[559]
    DIRECTION INPUT ;
    USE SIGNAL ;
    PORT
      LAYER M3 ;
        RECT  117.9 0 117.918 0.144 ;
    END
  END rs_d[559]
  PIN rs_d[55]
    DIRECTION INPUT ;
    USE SIGNAL ;
    PORT
      LAYER M3 ;
        RECT  16.488 0 16.506 0.144 ;
    END
  END rs_d[55]
  PIN rs_d[560]
    DIRECTION INPUT ;
    USE SIGNAL ;
    PORT
      LAYER M5 ;
        RECT  118.08 0 118.104 0.192 ;
    END
  END rs_d[560]
  PIN rs_d[561]
    DIRECTION INPUT ;
    USE SIGNAL ;
    PORT
      LAYER M3 ;
        RECT  118.296 0 118.314 0.144 ;
    END
  END rs_d[561]
  PIN rs_d[562]
    DIRECTION INPUT ;
    USE SIGNAL ;
    PORT
      LAYER M5 ;
        RECT  118.464 0 118.488 0.192 ;
    END
  END rs_d[562]
  PIN rs_d[563]
    DIRECTION INPUT ;
    USE SIGNAL ;
    PORT
      LAYER M3 ;
        RECT  118.692 0 118.71 0.144 ;
    END
  END rs_d[563]
  PIN rs_d[564]
    DIRECTION INPUT ;
    USE SIGNAL ;
    PORT
      LAYER M5 ;
        RECT  118.896 0 118.92 0.192 ;
    END
  END rs_d[564]
  PIN rs_d[565]
    DIRECTION INPUT ;
    USE SIGNAL ;
    PORT
      LAYER M3 ;
        RECT  119.088 0 119.106 0.144 ;
    END
  END rs_d[565]
  PIN rs_d[566]
    DIRECTION INPUT ;
    USE SIGNAL ;
    PORT
      LAYER M5 ;
        RECT  119.28 0 119.304 0.192 ;
    END
  END rs_d[566]
  PIN rs_d[567]
    DIRECTION INPUT ;
    USE SIGNAL ;
    PORT
      LAYER M3 ;
        RECT  119.484 0 119.502 0.144 ;
    END
  END rs_d[567]
  PIN rs_d[568]
    DIRECTION INPUT ;
    USE SIGNAL ;
    PORT
      LAYER M5 ;
        RECT  119.712 0 119.736 0.192 ;
    END
  END rs_d[568]
  PIN rs_d[569]
    DIRECTION INPUT ;
    USE SIGNAL ;
    PORT
      LAYER M3 ;
        RECT  119.88 0 119.898 0.144 ;
    END
  END rs_d[569]
  PIN rs_d[56]
    DIRECTION INPUT ;
    USE SIGNAL ;
    PORT
      LAYER M5 ;
        RECT  16.704 0 16.728 0.192 ;
    END
  END rs_d[56]
  PIN rs_d[570]
    DIRECTION INPUT ;
    USE SIGNAL ;
    PORT
      LAYER M5 ;
        RECT  120.096 0 120.12 0.192 ;
    END
  END rs_d[570]
  PIN rs_d[571]
    DIRECTION INPUT ;
    USE SIGNAL ;
    PORT
      LAYER M3 ;
        RECT  120.312 0 120.33 0.144 ;
    END
  END rs_d[571]
  PIN rs_d[572]
    DIRECTION INPUT ;
    USE SIGNAL ;
    PORT
      LAYER M5 ;
        RECT  120.48 0 120.504 0.192 ;
    END
  END rs_d[572]
  PIN rs_d[573]
    DIRECTION INPUT ;
    USE SIGNAL ;
    PORT
      LAYER M3 ;
        RECT  120.708 0 120.726 0.144 ;
    END
  END rs_d[573]
  PIN rs_d[574]
    DIRECTION INPUT ;
    USE SIGNAL ;
    PORT
      LAYER M5 ;
        RECT  120.912 0 120.936 0.192 ;
    END
  END rs_d[574]
  PIN rs_d[575]
    DIRECTION INPUT ;
    USE SIGNAL ;
    PORT
      LAYER M3 ;
        RECT  121.104 0 121.122 0.144 ;
    END
  END rs_d[575]
  PIN rs_d[576]
    DIRECTION INPUT ;
    USE SIGNAL ;
    PORT
      LAYER M5 ;
        RECT  121.296 0 121.32 0.192 ;
    END
  END rs_d[576]
  PIN rs_d[577]
    DIRECTION INPUT ;
    USE SIGNAL ;
    PORT
      LAYER M3 ;
        RECT  121.5 0 121.518 0.144 ;
    END
  END rs_d[577]
  PIN rs_d[578]
    DIRECTION INPUT ;
    USE SIGNAL ;
    PORT
      LAYER M5 ;
        RECT  121.68 0 121.704 0.192 ;
    END
  END rs_d[578]
  PIN rs_d[579]
    DIRECTION INPUT ;
    USE SIGNAL ;
    PORT
      LAYER M3 ;
        RECT  121.896 0 121.914 0.144 ;
    END
  END rs_d[579]
  PIN rs_d[57]
    DIRECTION INPUT ;
    USE SIGNAL ;
    PORT
      LAYER M3 ;
        RECT  16.884 0 16.902 0.144 ;
    END
  END rs_d[57]
  PIN rs_d[580]
    DIRECTION INPUT ;
    USE SIGNAL ;
    PORT
      LAYER M5 ;
        RECT  122.112 0 122.136 0.192 ;
    END
  END rs_d[580]
  PIN rs_d[581]
    DIRECTION INPUT ;
    USE SIGNAL ;
    PORT
      LAYER M3 ;
        RECT  122.292 0 122.31 0.144 ;
    END
  END rs_d[581]
  PIN rs_d[582]
    DIRECTION INPUT ;
    USE SIGNAL ;
    PORT
      LAYER M5 ;
        RECT  122.496 0 122.52 0.192 ;
    END
  END rs_d[582]
  PIN rs_d[583]
    DIRECTION INPUT ;
    USE SIGNAL ;
    PORT
      LAYER M3 ;
        RECT  122.724 0 122.742 0.144 ;
    END
  END rs_d[583]
  PIN rs_d[584]
    DIRECTION INPUT ;
    USE SIGNAL ;
    PORT
      LAYER M5 ;
        RECT  122.928 0 122.952 0.192 ;
    END
  END rs_d[584]
  PIN rs_d[585]
    DIRECTION INPUT ;
    USE SIGNAL ;
    PORT
      LAYER M3 ;
        RECT  123.12 0 123.138 0.144 ;
    END
  END rs_d[585]
  PIN rs_d[586]
    DIRECTION INPUT ;
    USE SIGNAL ;
    PORT
      LAYER M5 ;
        RECT  123.312 0 123.336 0.192 ;
    END
  END rs_d[586]
  PIN rs_d[587]
    DIRECTION INPUT ;
    USE SIGNAL ;
    PORT
      LAYER M3 ;
        RECT  123.516 0 123.534 0.144 ;
    END
  END rs_d[587]
  PIN rs_d[588]
    DIRECTION INPUT ;
    USE SIGNAL ;
    PORT
      LAYER M5 ;
        RECT  123.696 0 123.72 0.192 ;
    END
  END rs_d[588]
  PIN rs_d[589]
    DIRECTION INPUT ;
    USE SIGNAL ;
    PORT
      LAYER M3 ;
        RECT  123.912 0 123.93 0.144 ;
    END
  END rs_d[589]
  PIN rs_d[58]
    DIRECTION INPUT ;
    USE SIGNAL ;
    PORT
      LAYER M5 ;
        RECT  17.088 0 17.112 0.192 ;
    END
  END rs_d[58]
  PIN rs_d[590]
    DIRECTION INPUT ;
    USE SIGNAL ;
    PORT
      LAYER M5 ;
        RECT  124.128 0 124.152 0.192 ;
    END
  END rs_d[590]
  PIN rs_d[591]
    DIRECTION INPUT ;
    USE SIGNAL ;
    PORT
      LAYER M3 ;
        RECT  124.308 0 124.326 0.144 ;
    END
  END rs_d[591]
  PIN rs_d[592]
    DIRECTION INPUT ;
    USE SIGNAL ;
    PORT
      LAYER M5 ;
        RECT  124.512 0 124.536 0.192 ;
    END
  END rs_d[592]
  PIN rs_d[593]
    DIRECTION INPUT ;
    USE SIGNAL ;
    PORT
      LAYER M3 ;
        RECT  124.74 0 124.758 0.144 ;
    END
  END rs_d[593]
  PIN rs_d[594]
    DIRECTION INPUT ;
    USE SIGNAL ;
    PORT
      LAYER M5 ;
        RECT  124.944 0 124.968 0.192 ;
    END
  END rs_d[594]
  PIN rs_d[595]
    DIRECTION INPUT ;
    USE SIGNAL ;
    PORT
      LAYER M3 ;
        RECT  125.136 0 125.154 0.144 ;
    END
  END rs_d[595]
  PIN rs_d[596]
    DIRECTION INPUT ;
    USE SIGNAL ;
    PORT
      LAYER M5 ;
        RECT  125.328 0 125.352 0.192 ;
    END
  END rs_d[596]
  PIN rs_d[597]
    DIRECTION INPUT ;
    USE SIGNAL ;
    PORT
      LAYER M3 ;
        RECT  125.532 0 125.55 0.144 ;
    END
  END rs_d[597]
  PIN rs_d[598]
    DIRECTION INPUT ;
    USE SIGNAL ;
    PORT
      LAYER M5 ;
        RECT  125.712 0 125.736 0.192 ;
    END
  END rs_d[598]
  PIN rs_d[599]
    DIRECTION INPUT ;
    USE SIGNAL ;
    PORT
      LAYER M3 ;
        RECT  125.928 0 125.946 0.144 ;
    END
  END rs_d[599]
  PIN rs_d[59]
    DIRECTION INPUT ;
    USE SIGNAL ;
    PORT
      LAYER M3 ;
        RECT  17.28 0 17.298 0.144 ;
    END
  END rs_d[59]
  PIN rs_d[5]
    DIRECTION INPUT ;
    USE SIGNAL ;
    PORT
      LAYER M3 ;
        RECT  6.408 0 6.426 0.144 ;
    END
  END rs_d[5]
  PIN rs_d[600]
    DIRECTION INPUT ;
    USE SIGNAL ;
    PORT
      LAYER M5 ;
        RECT  126.144 0 126.168 0.192 ;
    END
  END rs_d[600]
  PIN rs_d[601]
    DIRECTION INPUT ;
    USE SIGNAL ;
    PORT
      LAYER M3 ;
        RECT  126.324 0 126.342 0.144 ;
    END
  END rs_d[601]
  PIN rs_d[602]
    DIRECTION INPUT ;
    USE SIGNAL ;
    PORT
      LAYER M5 ;
        RECT  126.528 0 126.552 0.192 ;
    END
  END rs_d[602]
  PIN rs_d[603]
    DIRECTION INPUT ;
    USE SIGNAL ;
    PORT
      LAYER M3 ;
        RECT  126.72 0 126.738 0.144 ;
    END
  END rs_d[603]
  PIN rs_d[604]
    DIRECTION INPUT ;
    USE SIGNAL ;
    PORT
      LAYER M5 ;
        RECT  126.912 0 126.936 0.192 ;
    END
  END rs_d[604]
  PIN rs_d[605]
    DIRECTION INPUT ;
    USE SIGNAL ;
    PORT
      LAYER M3 ;
        RECT  127.152 0 127.17 0.144 ;
    END
  END rs_d[605]
  PIN rs_d[606]
    DIRECTION INPUT ;
    USE SIGNAL ;
    PORT
      LAYER M5 ;
        RECT  127.344 0 127.368 0.192 ;
    END
  END rs_d[606]
  PIN rs_d[607]
    DIRECTION INPUT ;
    USE SIGNAL ;
    PORT
      LAYER M3 ;
        RECT  127.548 0 127.566 0.144 ;
    END
  END rs_d[607]
  PIN rs_d[608]
    DIRECTION INPUT ;
    USE SIGNAL ;
    PORT
      LAYER M5 ;
        RECT  127.728 0 127.752 0.192 ;
    END
  END rs_d[608]
  PIN rs_d[609]
    DIRECTION INPUT ;
    USE SIGNAL ;
    PORT
      LAYER M3 ;
        RECT  127.944 0 127.962 0.144 ;
    END
  END rs_d[609]
  PIN rs_d[60]
    DIRECTION INPUT ;
    USE SIGNAL ;
    PORT
      LAYER M5 ;
        RECT  17.472 0 17.496 0.192 ;
    END
  END rs_d[60]
  PIN rs_d[610]
    DIRECTION INPUT ;
    USE SIGNAL ;
    PORT
      LAYER M5 ;
        RECT  128.16 0 128.184 0.192 ;
    END
  END rs_d[610]
  PIN rs_d[611]
    DIRECTION INPUT ;
    USE SIGNAL ;
    PORT
      LAYER M3 ;
        RECT  128.34 0 128.358 0.144 ;
    END
  END rs_d[611]
  PIN rs_d[612]
    DIRECTION INPUT ;
    USE SIGNAL ;
    PORT
      LAYER M5 ;
        RECT  128.544 0 128.568 0.192 ;
    END
  END rs_d[612]
  PIN rs_d[613]
    DIRECTION INPUT ;
    USE SIGNAL ;
    PORT
      LAYER M3 ;
        RECT  128.736 0 128.754 0.144 ;
    END
  END rs_d[613]
  PIN rs_d[614]
    DIRECTION INPUT ;
    USE SIGNAL ;
    PORT
      LAYER M5 ;
        RECT  128.928 0 128.952 0.192 ;
    END
  END rs_d[614]
  PIN rs_d[615]
    DIRECTION INPUT ;
    USE SIGNAL ;
    PORT
      LAYER M3 ;
        RECT  129.132 0 129.15 0.144 ;
    END
  END rs_d[615]
  PIN rs_d[616]
    DIRECTION INPUT ;
    USE SIGNAL ;
    PORT
      LAYER M5 ;
        RECT  129.36 0 129.384 0.192 ;
    END
  END rs_d[616]
  PIN rs_d[617]
    DIRECTION INPUT ;
    USE SIGNAL ;
    PORT
      LAYER M3 ;
        RECT  129.564 0 129.582 0.144 ;
    END
  END rs_d[617]
  PIN rs_d[618]
    DIRECTION INPUT ;
    USE SIGNAL ;
    PORT
      LAYER M5 ;
        RECT  129.744 0 129.768 0.192 ;
    END
  END rs_d[618]
  PIN rs_d[619]
    DIRECTION INPUT ;
    USE SIGNAL ;
    PORT
      LAYER M3 ;
        RECT  129.96 0 129.978 0.144 ;
    END
  END rs_d[619]
  PIN rs_d[61]
    DIRECTION INPUT ;
    USE SIGNAL ;
    PORT
      LAYER M3 ;
        RECT  17.676 0 17.694 0.144 ;
    END
  END rs_d[61]
  PIN rs_d[620]
    DIRECTION INPUT ;
    USE SIGNAL ;
    PORT
      LAYER M5 ;
        RECT  130.176 0 130.2 0.192 ;
    END
  END rs_d[620]
  PIN rs_d[621]
    DIRECTION INPUT ;
    USE SIGNAL ;
    PORT
      LAYER M3 ;
        RECT  130.356 0 130.374 0.144 ;
    END
  END rs_d[621]
  PIN rs_d[622]
    DIRECTION INPUT ;
    USE SIGNAL ;
    PORT
      LAYER M5 ;
        RECT  130.56 0 130.584 0.192 ;
    END
  END rs_d[622]
  PIN rs_d[623]
    DIRECTION INPUT ;
    USE SIGNAL ;
    PORT
      LAYER M3 ;
        RECT  130.752 0 130.77 0.144 ;
    END
  END rs_d[623]
  PIN rs_d[624]
    DIRECTION INPUT ;
    USE SIGNAL ;
    PORT
      LAYER M5 ;
        RECT  130.944 0 130.968 0.192 ;
    END
  END rs_d[624]
  PIN rs_d[625]
    DIRECTION INPUT ;
    USE SIGNAL ;
    PORT
      LAYER M3 ;
        RECT  131.148 0 131.166 0.144 ;
    END
  END rs_d[625]
  PIN rs_d[626]
    DIRECTION INPUT ;
    USE SIGNAL ;
    PORT
      LAYER M5 ;
        RECT  131.376 0 131.4 0.192 ;
    END
  END rs_d[626]
  PIN rs_d[627]
    DIRECTION INPUT ;
    USE SIGNAL ;
    PORT
      LAYER M3 ;
        RECT  131.58 0 131.598 0.144 ;
    END
  END rs_d[627]
  PIN rs_d[628]
    DIRECTION INPUT ;
    USE SIGNAL ;
    PORT
      LAYER M5 ;
        RECT  131.76 0 131.784 0.192 ;
    END
  END rs_d[628]
  PIN rs_d[629]
    DIRECTION INPUT ;
    USE SIGNAL ;
    PORT
      LAYER M3 ;
        RECT  131.976 0 131.994 0.144 ;
    END
  END rs_d[629]
  PIN rs_d[62]
    DIRECTION INPUT ;
    USE SIGNAL ;
    PORT
      LAYER M5 ;
        RECT  17.904 0 17.928 0.192 ;
    END
  END rs_d[62]
  PIN rs_d[630]
    DIRECTION INPUT ;
    USE SIGNAL ;
    PORT
      LAYER M5 ;
        RECT  132.144 0 132.168 0.192 ;
    END
  END rs_d[630]
  PIN rs_d[631]
    DIRECTION INPUT ;
    USE SIGNAL ;
    PORT
      LAYER M3 ;
        RECT  132.372 0 132.39 0.144 ;
    END
  END rs_d[631]
  PIN rs_d[632]
    DIRECTION INPUT ;
    USE SIGNAL ;
    PORT
      LAYER M5 ;
        RECT  132.576 0 132.6 0.192 ;
    END
  END rs_d[632]
  PIN rs_d[633]
    DIRECTION INPUT ;
    USE SIGNAL ;
    PORT
      LAYER M3 ;
        RECT  132.768 0 132.786 0.144 ;
    END
  END rs_d[633]
  PIN rs_d[634]
    DIRECTION INPUT ;
    USE SIGNAL ;
    PORT
      LAYER M5 ;
        RECT  132.96 0 132.984 0.192 ;
    END
  END rs_d[634]
  PIN rs_d[635]
    DIRECTION INPUT ;
    USE SIGNAL ;
    PORT
      LAYER M3 ;
        RECT  133.164 0 133.182 0.144 ;
    END
  END rs_d[635]
  PIN rs_d[636]
    DIRECTION INPUT ;
    USE SIGNAL ;
    PORT
      LAYER M5 ;
        RECT  133.392 0 133.416 0.192 ;
    END
  END rs_d[636]
  PIN rs_d[637]
    DIRECTION INPUT ;
    USE SIGNAL ;
    PORT
      LAYER M3 ;
        RECT  133.56 0 133.578 0.144 ;
    END
  END rs_d[637]
  PIN rs_d[638]
    DIRECTION INPUT ;
    USE SIGNAL ;
    PORT
      LAYER M5 ;
        RECT  133.776 0 133.8 0.192 ;
    END
  END rs_d[638]
  PIN rs_d[639]
    DIRECTION INPUT ;
    USE SIGNAL ;
    PORT
      LAYER M3 ;
        RECT  133.992 0 134.01 0.144 ;
    END
  END rs_d[639]
  PIN rs_d[63]
    DIRECTION INPUT ;
    USE SIGNAL ;
    PORT
      LAYER M3 ;
        RECT  18.108 0 18.126 0.144 ;
    END
  END rs_d[63]
  PIN rs_d[64]
    DIRECTION INPUT ;
    USE SIGNAL ;
    PORT
      LAYER M5 ;
        RECT  18.288 0 18.312 0.192 ;
    END
  END rs_d[64]
  PIN rs_d[65]
    DIRECTION INPUT ;
    USE SIGNAL ;
    PORT
      LAYER M3 ;
        RECT  18.504 0 18.522 0.144 ;
    END
  END rs_d[65]
  PIN rs_d[66]
    DIRECTION INPUT ;
    USE SIGNAL ;
    PORT
      LAYER M5 ;
        RECT  18.672 0 18.696 0.192 ;
    END
  END rs_d[66]
  PIN rs_d[67]
    DIRECTION INPUT ;
    USE SIGNAL ;
    PORT
      LAYER M3 ;
        RECT  18.9 0 18.918 0.144 ;
    END
  END rs_d[67]
  PIN rs_d[68]
    DIRECTION INPUT ;
    USE SIGNAL ;
    PORT
      LAYER M5 ;
        RECT  19.104 0 19.128 0.192 ;
    END
  END rs_d[68]
  PIN rs_d[69]
    DIRECTION INPUT ;
    USE SIGNAL ;
    PORT
      LAYER M3 ;
        RECT  19.296 0 19.314 0.144 ;
    END
  END rs_d[69]
  PIN rs_d[6]
    DIRECTION INPUT ;
    USE SIGNAL ;
    PORT
      LAYER M5 ;
        RECT  6.624 0 6.648 0.192 ;
    END
  END rs_d[6]
  PIN rs_d[70]
    DIRECTION INPUT ;
    USE SIGNAL ;
    PORT
      LAYER M5 ;
        RECT  19.488 0 19.512 0.192 ;
    END
  END rs_d[70]
  PIN rs_d[71]
    DIRECTION INPUT ;
    USE SIGNAL ;
    PORT
      LAYER M3 ;
        RECT  19.692 0 19.71 0.144 ;
    END
  END rs_d[71]
  PIN rs_d[72]
    DIRECTION INPUT ;
    USE SIGNAL ;
    PORT
      LAYER M5 ;
        RECT  19.92 0 19.944 0.192 ;
    END
  END rs_d[72]
  PIN rs_d[73]
    DIRECTION INPUT ;
    USE SIGNAL ;
    PORT
      LAYER M3 ;
        RECT  20.088 0 20.106 0.144 ;
    END
  END rs_d[73]
  PIN rs_d[74]
    DIRECTION INPUT ;
    USE SIGNAL ;
    PORT
      LAYER M5 ;
        RECT  20.304 0 20.328 0.192 ;
    END
  END rs_d[74]
  PIN rs_d[75]
    DIRECTION INPUT ;
    USE SIGNAL ;
    PORT
      LAYER M3 ;
        RECT  20.52 0 20.538 0.144 ;
    END
  END rs_d[75]
  PIN rs_d[76]
    DIRECTION INPUT ;
    USE SIGNAL ;
    PORT
      LAYER M5 ;
        RECT  20.688 0 20.712 0.192 ;
    END
  END rs_d[76]
  PIN rs_d[77]
    DIRECTION INPUT ;
    USE SIGNAL ;
    PORT
      LAYER M3 ;
        RECT  20.916 0 20.934 0.144 ;
    END
  END rs_d[77]
  PIN rs_d[78]
    DIRECTION INPUT ;
    USE SIGNAL ;
    PORT
      LAYER M5 ;
        RECT  21.12 0 21.144 0.192 ;
    END
  END rs_d[78]
  PIN rs_d[79]
    DIRECTION INPUT ;
    USE SIGNAL ;
    PORT
      LAYER M3 ;
        RECT  21.312 0 21.33 0.144 ;
    END
  END rs_d[79]
  PIN rs_d[7]
    DIRECTION INPUT ;
    USE SIGNAL ;
    PORT
      LAYER M3 ;
        RECT  6.84 0 6.858 0.144 ;
    END
  END rs_d[7]
  PIN rs_d[80]
    DIRECTION INPUT ;
    USE SIGNAL ;
    PORT
      LAYER M5 ;
        RECT  21.504 0 21.528 0.192 ;
    END
  END rs_d[80]
  PIN rs_d[81]
    DIRECTION INPUT ;
    USE SIGNAL ;
    PORT
      LAYER M3 ;
        RECT  21.708 0 21.726 0.144 ;
    END
  END rs_d[81]
  PIN rs_d[82]
    DIRECTION INPUT ;
    USE SIGNAL ;
    PORT
      LAYER M5 ;
        RECT  21.936 0 21.96 0.192 ;
    END
  END rs_d[82]
  PIN rs_d[83]
    DIRECTION INPUT ;
    USE SIGNAL ;
    PORT
      LAYER M3 ;
        RECT  22.104 0 22.122 0.144 ;
    END
  END rs_d[83]
  PIN rs_d[84]
    DIRECTION INPUT ;
    USE SIGNAL ;
    PORT
      LAYER M5 ;
        RECT  22.32 0 22.344 0.192 ;
    END
  END rs_d[84]
  PIN rs_d[85]
    DIRECTION INPUT ;
    USE SIGNAL ;
    PORT
      LAYER M3 ;
        RECT  22.536 0 22.554 0.144 ;
    END
  END rs_d[85]
  PIN rs_d[86]
    DIRECTION INPUT ;
    USE SIGNAL ;
    PORT
      LAYER M5 ;
        RECT  22.704 0 22.728 0.192 ;
    END
  END rs_d[86]
  PIN rs_d[87]
    DIRECTION INPUT ;
    USE SIGNAL ;
    PORT
      LAYER M3 ;
        RECT  22.932 0 22.95 0.144 ;
    END
  END rs_d[87]
  PIN rs_d[88]
    DIRECTION INPUT ;
    USE SIGNAL ;
    PORT
      LAYER M5 ;
        RECT  23.136 0 23.16 0.192 ;
    END
  END rs_d[88]
  PIN rs_d[89]
    DIRECTION INPUT ;
    USE SIGNAL ;
    PORT
      LAYER M3 ;
        RECT  23.328 0 23.346 0.144 ;
    END
  END rs_d[89]
  PIN rs_d[8]
    DIRECTION INPUT ;
    USE SIGNAL ;
    PORT
      LAYER M5 ;
        RECT  7.008 0 7.032 0.192 ;
    END
  END rs_d[8]
  PIN rs_d[90]
    DIRECTION INPUT ;
    USE SIGNAL ;
    PORT
      LAYER M5 ;
        RECT  23.52 0 23.544 0.192 ;
    END
  END rs_d[90]
  PIN rs_d[91]
    DIRECTION INPUT ;
    USE SIGNAL ;
    PORT
      LAYER M3 ;
        RECT  23.724 0 23.742 0.144 ;
    END
  END rs_d[91]
  PIN rs_d[92]
    DIRECTION INPUT ;
    USE SIGNAL ;
    PORT
      LAYER M5 ;
        RECT  23.904 0 23.928 0.192 ;
    END
  END rs_d[92]
  PIN rs_d[93]
    DIRECTION INPUT ;
    USE SIGNAL ;
    PORT
      LAYER M3 ;
        RECT  24.12 0 24.138 0.144 ;
    END
  END rs_d[93]
  PIN rs_d[94]
    DIRECTION INPUT ;
    USE SIGNAL ;
    PORT
      LAYER M5 ;
        RECT  24.336 0 24.36 0.192 ;
    END
  END rs_d[94]
  PIN rs_d[95]
    DIRECTION INPUT ;
    USE SIGNAL ;
    PORT
      LAYER M3 ;
        RECT  24.516 0 24.534 0.144 ;
    END
  END rs_d[95]
  PIN rs_d[96]
    DIRECTION INPUT ;
    USE SIGNAL ;
    PORT
      LAYER M5 ;
        RECT  24.72 0 24.744 0.192 ;
    END
  END rs_d[96]
  PIN rs_d[97]
    DIRECTION INPUT ;
    USE SIGNAL ;
    PORT
      LAYER M3 ;
        RECT  24.948 0 24.966 0.144 ;
    END
  END rs_d[97]
  PIN rs_d[98]
    DIRECTION INPUT ;
    USE SIGNAL ;
    PORT
      LAYER M5 ;
        RECT  25.152 0 25.176 0.192 ;
    END
  END rs_d[98]
  PIN rs_d[99]
    DIRECTION INPUT ;
    USE SIGNAL ;
    PORT
      LAYER M3 ;
        RECT  25.344 0 25.362 0.144 ;
    END
  END rs_d[99]
  PIN rs_d[9]
    DIRECTION INPUT ;
    USE SIGNAL ;
    PORT
      LAYER M3 ;
        RECT  7.236 0 7.254 0.144 ;
    END
  END rs_d[9]
  PIN rs_v[0]
    DIRECTION INPUT ;
    USE SIGNAL ;
    PORT
      LAYER M3 ;
        RECT  4.428 0 4.446 0.144 ;
    END
  END rs_v[0]
  PIN rs_v[1]
    DIRECTION INPUT ;
    USE SIGNAL ;
    PORT
      LAYER M5 ;
        RECT  4.608 0 4.632 0.192 ;
    END
  END rs_v[1]
  PIN rs_v[2]
    DIRECTION INPUT ;
    USE SIGNAL ;
    PORT
      LAYER M3 ;
        RECT  4.824 0 4.842 0.144 ;
    END
  END rs_v[2]
  PIN rs_v[3]
    DIRECTION INPUT ;
    USE SIGNAL ;
    PORT
      LAYER M5 ;
        RECT  4.992 0 5.016 0.192 ;
    END
  END rs_v[3]
  PIN rs_v[4]
    DIRECTION INPUT ;
    USE SIGNAL ;
    PORT
      LAYER M3 ;
        RECT  5.22 0 5.238 0.144 ;
    END
  END rs_v[4]
  PIN rst
    DIRECTION INPUT ;
    USE SIGNAL ;
    PORT
      LAYER M4 ;
        RECT  0 38.352 0.192 38.376 ;
    END
  END rst
  PIN w[0]
    DIRECTION OUTPUT ;
    USE SIGNAL ;
    PORT
      LAYER M5 ;
        RECT  82.368 53.808 82.392 54 ;
    END
  END w[0]
  PIN w[100]
    DIRECTION OUTPUT ;
    USE SIGNAL ;
    PORT
      LAYER M5 ;
        RECT  97.536 53.808 97.56 54 ;
    END
  END w[100]
  PIN w[101]
    DIRECTION OUTPUT ;
    USE SIGNAL ;
    PORT
      LAYER M3 ;
        RECT  97.668 53.856 97.686 54 ;
    END
  END w[101]
  PIN w[102]
    DIRECTION OUTPUT ;
    USE SIGNAL ;
    PORT
      LAYER M5 ;
        RECT  97.824 53.808 97.848 54 ;
    END
  END w[102]
  PIN w[103]
    DIRECTION OUTPUT ;
    USE SIGNAL ;
    PORT
      LAYER M3 ;
        RECT  97.956 53.856 97.974 54 ;
    END
  END w[103]
  PIN w[104]
    DIRECTION OUTPUT ;
    USE SIGNAL ;
    PORT
      LAYER M5 ;
        RECT  98.112 53.808 98.136 54 ;
    END
  END w[104]
  PIN w[105]
    DIRECTION OUTPUT ;
    USE SIGNAL ;
    PORT
      LAYER M3 ;
        RECT  98.28 53.856 98.298 54 ;
    END
  END w[105]
  PIN w[106]
    DIRECTION OUTPUT ;
    USE SIGNAL ;
    PORT
      LAYER M5 ;
        RECT  98.4 53.808 98.424 54 ;
    END
  END w[106]
  PIN w[107]
    DIRECTION OUTPUT ;
    USE SIGNAL ;
    PORT
      LAYER M3 ;
        RECT  98.568 53.856 98.586 54 ;
    END
  END w[107]
  PIN w[108]
    DIRECTION OUTPUT ;
    USE SIGNAL ;
    PORT
      LAYER M5 ;
        RECT  98.736 53.808 98.76 54 ;
    END
  END w[108]
  PIN w[109]
    DIRECTION OUTPUT ;
    USE SIGNAL ;
    PORT
      LAYER M3 ;
        RECT  98.892 53.856 98.91 54 ;
    END
  END w[109]
  PIN w[10]
    DIRECTION OUTPUT ;
    USE SIGNAL ;
    PORT
      LAYER M5 ;
        RECT  83.904 53.808 83.928 54 ;
    END
  END w[10]
  PIN w[110]
    DIRECTION OUTPUT ;
    USE SIGNAL ;
    PORT
      LAYER M5 ;
        RECT  99.024 53.808 99.048 54 ;
    END
  END w[110]
  PIN w[111]
    DIRECTION OUTPUT ;
    USE SIGNAL ;
    PORT
      LAYER M3 ;
        RECT  99.18 53.856 99.198 54 ;
    END
  END w[111]
  PIN w[112]
    DIRECTION OUTPUT ;
    USE SIGNAL ;
    PORT
      LAYER M5 ;
        RECT  99.312 53.808 99.336 54 ;
    END
  END w[112]
  PIN w[113]
    DIRECTION OUTPUT ;
    USE SIGNAL ;
    PORT
      LAYER M3 ;
        RECT  99.468 53.856 99.486 54 ;
    END
  END w[113]
  PIN w[114]
    DIRECTION OUTPUT ;
    USE SIGNAL ;
    PORT
      LAYER M5 ;
        RECT  99.648 53.808 99.672 54 ;
    END
  END w[114]
  PIN w[115]
    DIRECTION OUTPUT ;
    USE SIGNAL ;
    PORT
      LAYER M3 ;
        RECT  99.792 53.856 99.81 54 ;
    END
  END w[115]
  PIN w[116]
    DIRECTION OUTPUT ;
    USE SIGNAL ;
    PORT
      LAYER M5 ;
        RECT  99.936 53.808 99.96 54 ;
    END
  END w[116]
  PIN w[117]
    DIRECTION OUTPUT ;
    USE SIGNAL ;
    PORT
      LAYER M3 ;
        RECT  100.08 53.856 100.098 54 ;
    END
  END w[117]
  PIN w[118]
    DIRECTION OUTPUT ;
    USE SIGNAL ;
    PORT
      LAYER M5 ;
        RECT  100.224 53.808 100.248 54 ;
    END
  END w[118]
  PIN w[119]
    DIRECTION OUTPUT ;
    USE SIGNAL ;
    PORT
      LAYER M3 ;
        RECT  100.404 53.856 100.422 54 ;
    END
  END w[119]
  PIN w[11]
    DIRECTION OUTPUT ;
    USE SIGNAL ;
    PORT
      LAYER M3 ;
        RECT  84.024 53.856 84.042 54 ;
    END
  END w[11]
  PIN w[120]
    DIRECTION OUTPUT ;
    USE SIGNAL ;
    PORT
      LAYER M5 ;
        RECT  100.56 53.808 100.584 54 ;
    END
  END w[120]
  PIN w[121]
    DIRECTION OUTPUT ;
    USE SIGNAL ;
    PORT
      LAYER M3 ;
        RECT  100.692 53.856 100.71 54 ;
    END
  END w[121]
  PIN w[122]
    DIRECTION OUTPUT ;
    USE SIGNAL ;
    PORT
      LAYER M5 ;
        RECT  100.848 53.808 100.872 54 ;
    END
  END w[122]
  PIN w[123]
    DIRECTION OUTPUT ;
    USE SIGNAL ;
    PORT
      LAYER M3 ;
        RECT  101.016 53.856 101.034 54 ;
    END
  END w[123]
  PIN w[124]
    DIRECTION OUTPUT ;
    USE SIGNAL ;
    PORT
      LAYER M5 ;
        RECT  101.136 53.808 101.16 54 ;
    END
  END w[124]
  PIN w[125]
    DIRECTION OUTPUT ;
    USE SIGNAL ;
    PORT
      LAYER M3 ;
        RECT  101.304 53.856 101.322 54 ;
    END
  END w[125]
  PIN w[126]
    DIRECTION OUTPUT ;
    USE SIGNAL ;
    PORT
      LAYER M5 ;
        RECT  101.472 53.808 101.496 54 ;
    END
  END w[126]
  PIN w[127]
    DIRECTION OUTPUT ;
    USE SIGNAL ;
    PORT
      LAYER M3 ;
        RECT  101.592 53.856 101.61 54 ;
    END
  END w[127]
  PIN w[128]
    DIRECTION OUTPUT ;
    USE SIGNAL ;
    PORT
      LAYER M5 ;
        RECT  101.76 53.808 101.784 54 ;
    END
  END w[128]
  PIN w[129]
    DIRECTION OUTPUT ;
    USE SIGNAL ;
    PORT
      LAYER M3 ;
        RECT  101.916 53.856 101.934 54 ;
    END
  END w[129]
  PIN w[12]
    DIRECTION OUTPUT ;
    USE SIGNAL ;
    PORT
      LAYER M5 ;
        RECT  84.192 53.808 84.216 54 ;
    END
  END w[12]
  PIN w[130]
    DIRECTION OUTPUT ;
    USE SIGNAL ;
    PORT
      LAYER M5 ;
        RECT  102.048 53.808 102.072 54 ;
    END
  END w[130]
  PIN w[131]
    DIRECTION OUTPUT ;
    USE SIGNAL ;
    PORT
      LAYER M3 ;
        RECT  102.204 53.856 102.222 54 ;
    END
  END w[131]
  PIN w[132]
    DIRECTION OUTPUT ;
    USE SIGNAL ;
    PORT
      LAYER M5 ;
        RECT  102.336 53.808 102.36 54 ;
    END
  END w[132]
  PIN w[133]
    DIRECTION OUTPUT ;
    USE SIGNAL ;
    PORT
      LAYER M3 ;
        RECT  102.528 53.856 102.546 54 ;
    END
  END w[133]
  PIN w[134]
    DIRECTION OUTPUT ;
    USE SIGNAL ;
    PORT
      LAYER M5 ;
        RECT  102.672 53.808 102.696 54 ;
    END
  END w[134]
  PIN w[135]
    DIRECTION OUTPUT ;
    USE SIGNAL ;
    PORT
      LAYER M3 ;
        RECT  102.816 53.856 102.834 54 ;
    END
  END w[135]
  PIN w[136]
    DIRECTION OUTPUT ;
    USE SIGNAL ;
    PORT
      LAYER M5 ;
        RECT  102.96 53.808 102.984 54 ;
    END
  END w[136]
  PIN w[137]
    DIRECTION OUTPUT ;
    USE SIGNAL ;
    PORT
      LAYER M3 ;
        RECT  103.104 53.856 103.122 54 ;
    END
  END w[137]
  PIN w[138]
    DIRECTION OUTPUT ;
    USE SIGNAL ;
    PORT
      LAYER M5 ;
        RECT  103.248 53.808 103.272 54 ;
    END
  END w[138]
  PIN w[139]
    DIRECTION OUTPUT ;
    USE SIGNAL ;
    PORT
      LAYER M3 ;
        RECT  103.428 53.856 103.446 54 ;
    END
  END w[139]
  PIN w[13]
    DIRECTION OUTPUT ;
    USE SIGNAL ;
    PORT
      LAYER M3 ;
        RECT  84.348 53.856 84.366 54 ;
    END
  END w[13]
  PIN w[140]
    DIRECTION OUTPUT ;
    USE SIGNAL ;
    PORT
      LAYER M5 ;
        RECT  103.584 53.808 103.608 54 ;
    END
  END w[140]
  PIN w[141]
    DIRECTION OUTPUT ;
    USE SIGNAL ;
    PORT
      LAYER M3 ;
        RECT  103.716 53.856 103.734 54 ;
    END
  END w[141]
  PIN w[142]
    DIRECTION OUTPUT ;
    USE SIGNAL ;
    PORT
      LAYER M5 ;
        RECT  103.872 53.808 103.896 54 ;
    END
  END w[142]
  PIN w[143]
    DIRECTION OUTPUT ;
    USE SIGNAL ;
    PORT
      LAYER M3 ;
        RECT  104.04 53.856 104.058 54 ;
    END
  END w[143]
  PIN w[144]
    DIRECTION OUTPUT ;
    USE SIGNAL ;
    PORT
      LAYER M5 ;
        RECT  104.16 53.808 104.184 54 ;
    END
  END w[144]
  PIN w[145]
    DIRECTION OUTPUT ;
    USE SIGNAL ;
    PORT
      LAYER M3 ;
        RECT  104.328 53.856 104.346 54 ;
    END
  END w[145]
  PIN w[146]
    DIRECTION OUTPUT ;
    USE SIGNAL ;
    PORT
      LAYER M5 ;
        RECT  104.496 53.808 104.52 54 ;
    END
  END w[146]
  PIN w[147]
    DIRECTION OUTPUT ;
    USE SIGNAL ;
    PORT
      LAYER M3 ;
        RECT  104.652 53.856 104.67 54 ;
    END
  END w[147]
  PIN w[148]
    DIRECTION OUTPUT ;
    USE SIGNAL ;
    PORT
      LAYER M5 ;
        RECT  104.784 53.808 104.808 54 ;
    END
  END w[148]
  PIN w[149]
    DIRECTION OUTPUT ;
    USE SIGNAL ;
    PORT
      LAYER M3 ;
        RECT  104.94 53.856 104.958 54 ;
    END
  END w[149]
  PIN w[14]
    DIRECTION OUTPUT ;
    USE SIGNAL ;
    PORT
      LAYER M5 ;
        RECT  84.48 53.808 84.504 54 ;
    END
  END w[14]
  PIN w[150]
    DIRECTION OUTPUT ;
    USE SIGNAL ;
    PORT
      LAYER M5 ;
        RECT  105.072 53.808 105.096 54 ;
    END
  END w[150]
  PIN w[151]
    DIRECTION OUTPUT ;
    USE SIGNAL ;
    PORT
      LAYER M3 ;
        RECT  105.228 53.856 105.246 54 ;
    END
  END w[151]
  PIN w[152]
    DIRECTION OUTPUT ;
    USE SIGNAL ;
    PORT
      LAYER M5 ;
        RECT  105.408 53.808 105.432 54 ;
    END
  END w[152]
  PIN w[153]
    DIRECTION OUTPUT ;
    USE SIGNAL ;
    PORT
      LAYER M3 ;
        RECT  105.552 53.856 105.57 54 ;
    END
  END w[153]
  PIN w[154]
    DIRECTION OUTPUT ;
    USE SIGNAL ;
    PORT
      LAYER M5 ;
        RECT  105.696 53.808 105.72 54 ;
    END
  END w[154]
  PIN w[155]
    DIRECTION OUTPUT ;
    USE SIGNAL ;
    PORT
      LAYER M3 ;
        RECT  105.84 53.856 105.858 54 ;
    END
  END w[155]
  PIN w[156]
    DIRECTION OUTPUT ;
    USE SIGNAL ;
    PORT
      LAYER M5 ;
        RECT  105.984 53.808 106.008 54 ;
    END
  END w[156]
  PIN w[157]
    DIRECTION OUTPUT ;
    USE SIGNAL ;
    PORT
      LAYER M3 ;
        RECT  106.164 53.856 106.182 54 ;
    END
  END w[157]
  PIN w[158]
    DIRECTION OUTPUT ;
    USE SIGNAL ;
    PORT
      LAYER M5 ;
        RECT  106.32 53.808 106.344 54 ;
    END
  END w[158]
  PIN w[159]
    DIRECTION OUTPUT ;
    USE SIGNAL ;
    PORT
      LAYER M3 ;
        RECT  106.452 53.856 106.47 54 ;
    END
  END w[159]
  PIN w[15]
    DIRECTION OUTPUT ;
    USE SIGNAL ;
    PORT
      LAYER M3 ;
        RECT  84.636 53.856 84.654 54 ;
    END
  END w[15]
  PIN w[160]
    DIRECTION OUTPUT ;
    USE SIGNAL ;
    PORT
      LAYER M5 ;
        RECT  106.608 53.808 106.632 54 ;
    END
  END w[160]
  PIN w[161]
    DIRECTION OUTPUT ;
    USE SIGNAL ;
    PORT
      LAYER M3 ;
        RECT  106.74 53.856 106.758 54 ;
    END
  END w[161]
  PIN w[162]
    DIRECTION OUTPUT ;
    USE SIGNAL ;
    PORT
      LAYER M5 ;
        RECT  106.896 53.808 106.92 54 ;
    END
  END w[162]
  PIN w[163]
    DIRECTION OUTPUT ;
    USE SIGNAL ;
    PORT
      LAYER M3 ;
        RECT  107.064 53.856 107.082 54 ;
    END
  END w[163]
  PIN w[164]
    DIRECTION OUTPUT ;
    USE SIGNAL ;
    PORT
      LAYER M5 ;
        RECT  107.184 53.808 107.208 54 ;
    END
  END w[164]
  PIN w[165]
    DIRECTION OUTPUT ;
    USE SIGNAL ;
    PORT
      LAYER M3 ;
        RECT  107.352 53.856 107.37 54 ;
    END
  END w[165]
  PIN w[166]
    DIRECTION OUTPUT ;
    USE SIGNAL ;
    PORT
      LAYER M5 ;
        RECT  107.52 53.808 107.544 54 ;
    END
  END w[166]
  PIN w[167]
    DIRECTION OUTPUT ;
    USE SIGNAL ;
    PORT
      LAYER M3 ;
        RECT  107.676 53.856 107.694 54 ;
    END
  END w[167]
  PIN w[168]
    DIRECTION OUTPUT ;
    USE SIGNAL ;
    PORT
      LAYER M5 ;
        RECT  107.808 53.808 107.832 54 ;
    END
  END w[168]
  PIN w[169]
    DIRECTION OUTPUT ;
    USE SIGNAL ;
    PORT
      LAYER M3 ;
        RECT  107.964 53.856 107.982 54 ;
    END
  END w[169]
  PIN w[16]
    DIRECTION OUTPUT ;
    USE SIGNAL ;
    PORT
      LAYER M5 ;
        RECT  84.816 53.808 84.84 54 ;
    END
  END w[16]
  PIN w[170]
    DIRECTION OUTPUT ;
    USE SIGNAL ;
    PORT
      LAYER M5 ;
        RECT  108.096 53.808 108.12 54 ;
    END
  END w[170]
  PIN w[171]
    DIRECTION OUTPUT ;
    USE SIGNAL ;
    PORT
      LAYER M3 ;
        RECT  108.252 53.856 108.27 54 ;
    END
  END w[171]
  PIN w[172]
    DIRECTION OUTPUT ;
    USE SIGNAL ;
    PORT
      LAYER M5 ;
        RECT  108.432 53.808 108.456 54 ;
    END
  END w[172]
  PIN w[173]
    DIRECTION OUTPUT ;
    USE SIGNAL ;
    PORT
      LAYER M3 ;
        RECT  108.576 53.856 108.594 54 ;
    END
  END w[173]
  PIN w[174]
    DIRECTION OUTPUT ;
    USE SIGNAL ;
    PORT
      LAYER M5 ;
        RECT  108.72 53.808 108.744 54 ;
    END
  END w[174]
  PIN w[175]
    DIRECTION OUTPUT ;
    USE SIGNAL ;
    PORT
      LAYER M3 ;
        RECT  108.864 53.856 108.882 54 ;
    END
  END w[175]
  PIN w[176]
    DIRECTION OUTPUT ;
    USE SIGNAL ;
    PORT
      LAYER M5 ;
        RECT  109.008 53.808 109.032 54 ;
    END
  END w[176]
  PIN w[177]
    DIRECTION OUTPUT ;
    USE SIGNAL ;
    PORT
      LAYER M3 ;
        RECT  109.188 53.856 109.206 54 ;
    END
  END w[177]
  PIN w[178]
    DIRECTION OUTPUT ;
    USE SIGNAL ;
    PORT
      LAYER M5 ;
        RECT  109.344 53.808 109.368 54 ;
    END
  END w[178]
  PIN w[179]
    DIRECTION OUTPUT ;
    USE SIGNAL ;
    PORT
      LAYER M3 ;
        RECT  109.476 53.856 109.494 54 ;
    END
  END w[179]
  PIN w[17]
    DIRECTION OUTPUT ;
    USE SIGNAL ;
    PORT
      LAYER M3 ;
        RECT  84.96 53.856 84.978 54 ;
    END
  END w[17]
  PIN w[180]
    DIRECTION OUTPUT ;
    USE SIGNAL ;
    PORT
      LAYER M5 ;
        RECT  109.632 53.808 109.656 54 ;
    END
  END w[180]
  PIN w[181]
    DIRECTION OUTPUT ;
    USE SIGNAL ;
    PORT
      LAYER M3 ;
        RECT  109.8 53.856 109.818 54 ;
    END
  END w[181]
  PIN w[182]
    DIRECTION OUTPUT ;
    USE SIGNAL ;
    PORT
      LAYER M5 ;
        RECT  109.92 53.808 109.944 54 ;
    END
  END w[182]
  PIN w[183]
    DIRECTION OUTPUT ;
    USE SIGNAL ;
    PORT
      LAYER M3 ;
        RECT  110.088 53.856 110.106 54 ;
    END
  END w[183]
  PIN w[184]
    DIRECTION OUTPUT ;
    USE SIGNAL ;
    PORT
      LAYER M5 ;
        RECT  110.256 53.808 110.28 54 ;
    END
  END w[184]
  PIN w[185]
    DIRECTION OUTPUT ;
    USE SIGNAL ;
    PORT
      LAYER M3 ;
        RECT  110.376 53.856 110.394 54 ;
    END
  END w[185]
  PIN w[186]
    DIRECTION OUTPUT ;
    USE SIGNAL ;
    PORT
      LAYER M5 ;
        RECT  110.544 53.808 110.568 54 ;
    END
  END w[186]
  PIN w[187]
    DIRECTION OUTPUT ;
    USE SIGNAL ;
    PORT
      LAYER M3 ;
        RECT  110.7 53.856 110.718 54 ;
    END
  END w[187]
  PIN w[188]
    DIRECTION OUTPUT ;
    USE SIGNAL ;
    PORT
      LAYER M5 ;
        RECT  110.832 53.808 110.856 54 ;
    END
  END w[188]
  PIN w[189]
    DIRECTION OUTPUT ;
    USE SIGNAL ;
    PORT
      LAYER M3 ;
        RECT  110.988 53.856 111.006 54 ;
    END
  END w[189]
  PIN w[18]
    DIRECTION OUTPUT ;
    USE SIGNAL ;
    PORT
      LAYER M5 ;
        RECT  85.104 53.808 85.128 54 ;
    END
  END w[18]
  PIN w[190]
    DIRECTION OUTPUT ;
    USE SIGNAL ;
    PORT
      LAYER M5 ;
        RECT  111.12 53.808 111.144 54 ;
    END
  END w[190]
  PIN w[191]
    DIRECTION OUTPUT ;
    USE SIGNAL ;
    PORT
      LAYER M3 ;
        RECT  111.312 53.856 111.33 54 ;
    END
  END w[191]
  PIN w[192]
    DIRECTION OUTPUT ;
    USE SIGNAL ;
    PORT
      LAYER M5 ;
        RECT  111.456 53.808 111.48 54 ;
    END
  END w[192]
  PIN w[193]
    DIRECTION OUTPUT ;
    USE SIGNAL ;
    PORT
      LAYER M3 ;
        RECT  111.6 53.856 111.618 54 ;
    END
  END w[193]
  PIN w[194]
    DIRECTION OUTPUT ;
    USE SIGNAL ;
    PORT
      LAYER M5 ;
        RECT  111.744 53.808 111.768 54 ;
    END
  END w[194]
  PIN w[195]
    DIRECTION OUTPUT ;
    USE SIGNAL ;
    PORT
      LAYER M3 ;
        RECT  111.888 53.856 111.906 54 ;
    END
  END w[195]
  PIN w[196]
    DIRECTION OUTPUT ;
    USE SIGNAL ;
    PORT
      LAYER M5 ;
        RECT  112.032 53.808 112.056 54 ;
    END
  END w[196]
  PIN w[197]
    DIRECTION OUTPUT ;
    USE SIGNAL ;
    PORT
      LAYER M3 ;
        RECT  112.212 53.856 112.23 54 ;
    END
  END w[197]
  PIN w[198]
    DIRECTION OUTPUT ;
    USE SIGNAL ;
    PORT
      LAYER M5 ;
        RECT  112.368 53.808 112.392 54 ;
    END
  END w[198]
  PIN w[199]
    DIRECTION OUTPUT ;
    USE SIGNAL ;
    PORT
      LAYER M3 ;
        RECT  112.5 53.856 112.518 54 ;
    END
  END w[199]
  PIN w[19]
    DIRECTION OUTPUT ;
    USE SIGNAL ;
    PORT
      LAYER M3 ;
        RECT  85.248 53.856 85.266 54 ;
    END
  END w[19]
  PIN w[1]
    DIRECTION OUTPUT ;
    USE SIGNAL ;
    PORT
      LAYER M3 ;
        RECT  82.512 53.856 82.53 54 ;
    END
  END w[1]
  PIN w[200]
    DIRECTION OUTPUT ;
    USE SIGNAL ;
    PORT
      LAYER M5 ;
        RECT  112.656 53.808 112.68 54 ;
    END
  END w[200]
  PIN w[201]
    DIRECTION OUTPUT ;
    USE SIGNAL ;
    PORT
      LAYER M3 ;
        RECT  112.824 53.856 112.842 54 ;
    END
  END w[201]
  PIN w[202]
    DIRECTION OUTPUT ;
    USE SIGNAL ;
    PORT
      LAYER M5 ;
        RECT  112.944 53.808 112.968 54 ;
    END
  END w[202]
  PIN w[203]
    DIRECTION OUTPUT ;
    USE SIGNAL ;
    PORT
      LAYER M3 ;
        RECT  113.112 53.856 113.13 54 ;
    END
  END w[203]
  PIN w[204]
    DIRECTION OUTPUT ;
    USE SIGNAL ;
    PORT
      LAYER M5 ;
        RECT  113.28 53.808 113.304 54 ;
    END
  END w[204]
  PIN w[205]
    DIRECTION OUTPUT ;
    USE SIGNAL ;
    PORT
      LAYER M3 ;
        RECT  113.4 53.856 113.418 54 ;
    END
  END w[205]
  PIN w[206]
    DIRECTION OUTPUT ;
    USE SIGNAL ;
    PORT
      LAYER M5 ;
        RECT  113.568 53.808 113.592 54 ;
    END
  END w[206]
  PIN w[207]
    DIRECTION OUTPUT ;
    USE SIGNAL ;
    PORT
      LAYER M3 ;
        RECT  113.724 53.856 113.742 54 ;
    END
  END w[207]
  PIN w[208]
    DIRECTION OUTPUT ;
    USE SIGNAL ;
    PORT
      LAYER M5 ;
        RECT  113.856 53.808 113.88 54 ;
    END
  END w[208]
  PIN w[209]
    DIRECTION OUTPUT ;
    USE SIGNAL ;
    PORT
      LAYER M3 ;
        RECT  114.012 53.856 114.03 54 ;
    END
  END w[209]
  PIN w[20]
    DIRECTION OUTPUT ;
    USE SIGNAL ;
    PORT
      LAYER M5 ;
        RECT  85.392 53.808 85.416 54 ;
    END
  END w[20]
  PIN w[210]
    DIRECTION OUTPUT ;
    USE SIGNAL ;
    PORT
      LAYER M5 ;
        RECT  114.192 53.808 114.216 54 ;
    END
  END w[210]
  PIN w[211]
    DIRECTION OUTPUT ;
    USE SIGNAL ;
    PORT
      LAYER M3 ;
        RECT  114.336 53.856 114.354 54 ;
    END
  END w[211]
  PIN w[212]
    DIRECTION OUTPUT ;
    USE SIGNAL ;
    PORT
      LAYER M5 ;
        RECT  114.48 53.808 114.504 54 ;
    END
  END w[212]
  PIN w[213]
    DIRECTION OUTPUT ;
    USE SIGNAL ;
    PORT
      LAYER M3 ;
        RECT  114.624 53.856 114.642 54 ;
    END
  END w[213]
  PIN w[214]
    DIRECTION OUTPUT ;
    USE SIGNAL ;
    PORT
      LAYER M5 ;
        RECT  114.768 53.808 114.792 54 ;
    END
  END w[214]
  PIN w[215]
    DIRECTION OUTPUT ;
    USE SIGNAL ;
    PORT
      LAYER M3 ;
        RECT  114.948 53.856 114.966 54 ;
    END
  END w[215]
  PIN w[216]
    DIRECTION OUTPUT ;
    USE SIGNAL ;
    PORT
      LAYER M5 ;
        RECT  115.104 53.808 115.128 54 ;
    END
  END w[216]
  PIN w[217]
    DIRECTION OUTPUT ;
    USE SIGNAL ;
    PORT
      LAYER M3 ;
        RECT  115.236 53.856 115.254 54 ;
    END
  END w[217]
  PIN w[218]
    DIRECTION OUTPUT ;
    USE SIGNAL ;
    PORT
      LAYER M5 ;
        RECT  115.392 53.808 115.416 54 ;
    END
  END w[218]
  PIN w[219]
    DIRECTION OUTPUT ;
    USE SIGNAL ;
    PORT
      LAYER M3 ;
        RECT  115.524 53.856 115.542 54 ;
    END
  END w[219]
  PIN w[21]
    DIRECTION OUTPUT ;
    USE SIGNAL ;
    PORT
      LAYER M3 ;
        RECT  85.536 53.856 85.554 54 ;
    END
  END w[21]
  PIN w[220]
    DIRECTION OUTPUT ;
    USE SIGNAL ;
    PORT
      LAYER M5 ;
        RECT  115.68 53.808 115.704 54 ;
    END
  END w[220]
  PIN w[221]
    DIRECTION OUTPUT ;
    USE SIGNAL ;
    PORT
      LAYER M3 ;
        RECT  115.848 53.856 115.866 54 ;
    END
  END w[221]
  PIN w[222]
    DIRECTION OUTPUT ;
    USE SIGNAL ;
    PORT
      LAYER M5 ;
        RECT  115.968 53.808 115.992 54 ;
    END
  END w[222]
  PIN w[223]
    DIRECTION OUTPUT ;
    USE SIGNAL ;
    PORT
      LAYER M3 ;
        RECT  116.136 53.856 116.154 54 ;
    END
  END w[223]
  PIN w[224]
    DIRECTION OUTPUT ;
    USE SIGNAL ;
    PORT
      LAYER M5 ;
        RECT  116.304 53.808 116.328 54 ;
    END
  END w[224]
  PIN w[225]
    DIRECTION OUTPUT ;
    USE SIGNAL ;
    PORT
      LAYER M3 ;
        RECT  116.46 53.856 116.478 54 ;
    END
  END w[225]
  PIN w[226]
    DIRECTION OUTPUT ;
    USE SIGNAL ;
    PORT
      LAYER M5 ;
        RECT  116.592 53.808 116.616 54 ;
    END
  END w[226]
  PIN w[227]
    DIRECTION OUTPUT ;
    USE SIGNAL ;
    PORT
      LAYER M3 ;
        RECT  116.748 53.856 116.766 54 ;
    END
  END w[227]
  PIN w[228]
    DIRECTION OUTPUT ;
    USE SIGNAL ;
    PORT
      LAYER M5 ;
        RECT  116.88 53.808 116.904 54 ;
    END
  END w[228]
  PIN w[229]
    DIRECTION OUTPUT ;
    USE SIGNAL ;
    PORT
      LAYER M3 ;
        RECT  117.036 53.856 117.054 54 ;
    END
  END w[229]
  PIN w[22]
    DIRECTION OUTPUT ;
    USE SIGNAL ;
    PORT
      LAYER M5 ;
        RECT  85.68 53.808 85.704 54 ;
    END
  END w[22]
  PIN w[230]
    DIRECTION OUTPUT ;
    USE SIGNAL ;
    PORT
      LAYER M5 ;
        RECT  117.216 53.808 117.24 54 ;
    END
  END w[230]
  PIN w[231]
    DIRECTION OUTPUT ;
    USE SIGNAL ;
    PORT
      LAYER M3 ;
        RECT  117.36 53.856 117.378 54 ;
    END
  END w[231]
  PIN w[232]
    DIRECTION OUTPUT ;
    USE SIGNAL ;
    PORT
      LAYER M5 ;
        RECT  117.504 53.808 117.528 54 ;
    END
  END w[232]
  PIN w[233]
    DIRECTION OUTPUT ;
    USE SIGNAL ;
    PORT
      LAYER M3 ;
        RECT  117.648 53.856 117.666 54 ;
    END
  END w[233]
  PIN w[234]
    DIRECTION OUTPUT ;
    USE SIGNAL ;
    PORT
      LAYER M5 ;
        RECT  117.792 53.808 117.816 54 ;
    END
  END w[234]
  PIN w[235]
    DIRECTION OUTPUT ;
    USE SIGNAL ;
    PORT
      LAYER M3 ;
        RECT  117.972 53.856 117.99 54 ;
    END
  END w[235]
  PIN w[236]
    DIRECTION OUTPUT ;
    USE SIGNAL ;
    PORT
      LAYER M5 ;
        RECT  118.128 53.808 118.152 54 ;
    END
  END w[236]
  PIN w[237]
    DIRECTION OUTPUT ;
    USE SIGNAL ;
    PORT
      LAYER M3 ;
        RECT  118.26 53.856 118.278 54 ;
    END
  END w[237]
  PIN w[238]
    DIRECTION OUTPUT ;
    USE SIGNAL ;
    PORT
      LAYER M5 ;
        RECT  118.416 53.808 118.44 54 ;
    END
  END w[238]
  PIN w[239]
    DIRECTION OUTPUT ;
    USE SIGNAL ;
    PORT
      LAYER M3 ;
        RECT  118.548 53.856 118.566 54 ;
    END
  END w[239]
  PIN w[23]
    DIRECTION OUTPUT ;
    USE SIGNAL ;
    PORT
      LAYER M3 ;
        RECT  85.86 53.856 85.878 54 ;
    END
  END w[23]
  PIN w[240]
    DIRECTION OUTPUT ;
    USE SIGNAL ;
    PORT
      LAYER M5 ;
        RECT  118.704 53.808 118.728 54 ;
    END
  END w[240]
  PIN w[241]
    DIRECTION OUTPUT ;
    USE SIGNAL ;
    PORT
      LAYER M3 ;
        RECT  118.872 53.856 118.89 54 ;
    END
  END w[241]
  PIN w[242]
    DIRECTION OUTPUT ;
    USE SIGNAL ;
    PORT
      LAYER M5 ;
        RECT  119.04 53.808 119.064 54 ;
    END
  END w[242]
  PIN w[243]
    DIRECTION OUTPUT ;
    USE SIGNAL ;
    PORT
      LAYER M3 ;
        RECT  119.16 53.856 119.178 54 ;
    END
  END w[243]
  PIN w[244]
    DIRECTION OUTPUT ;
    USE SIGNAL ;
    PORT
      LAYER M5 ;
        RECT  119.328 53.808 119.352 54 ;
    END
  END w[244]
  PIN w[245]
    DIRECTION OUTPUT ;
    USE SIGNAL ;
    PORT
      LAYER M3 ;
        RECT  119.484 53.856 119.502 54 ;
    END
  END w[245]
  PIN w[246]
    DIRECTION OUTPUT ;
    USE SIGNAL ;
    PORT
      LAYER M5 ;
        RECT  119.616 53.808 119.64 54 ;
    END
  END w[246]
  PIN w[247]
    DIRECTION OUTPUT ;
    USE SIGNAL ;
    PORT
      LAYER M3 ;
        RECT  119.772 53.856 119.79 54 ;
    END
  END w[247]
  PIN w[248]
    DIRECTION OUTPUT ;
    USE SIGNAL ;
    PORT
      LAYER M5 ;
        RECT  119.904 53.808 119.928 54 ;
    END
  END w[248]
  PIN w[249]
    DIRECTION OUTPUT ;
    USE SIGNAL ;
    PORT
      LAYER M3 ;
        RECT  120.096 53.856 120.114 54 ;
    END
  END w[249]
  PIN w[24]
    DIRECTION OUTPUT ;
    USE SIGNAL ;
    PORT
      LAYER M5 ;
        RECT  86.016 53.808 86.04 54 ;
    END
  END w[24]
  PIN w[250]
    DIRECTION OUTPUT ;
    USE SIGNAL ;
    PORT
      LAYER M5 ;
        RECT  120.24 53.808 120.264 54 ;
    END
  END w[250]
  PIN w[251]
    DIRECTION OUTPUT ;
    USE SIGNAL ;
    PORT
      LAYER M3 ;
        RECT  120.384 53.856 120.402 54 ;
    END
  END w[251]
  PIN w[252]
    DIRECTION OUTPUT ;
    USE SIGNAL ;
    PORT
      LAYER M5 ;
        RECT  120.528 53.808 120.552 54 ;
    END
  END w[252]
  PIN w[253]
    DIRECTION OUTPUT ;
    USE SIGNAL ;
    PORT
      LAYER M3 ;
        RECT  120.672 53.856 120.69 54 ;
    END
  END w[253]
  PIN w[254]
    DIRECTION OUTPUT ;
    USE SIGNAL ;
    PORT
      LAYER M5 ;
        RECT  120.816 53.808 120.84 54 ;
    END
  END w[254]
  PIN w[255]
    DIRECTION OUTPUT ;
    USE SIGNAL ;
    PORT
      LAYER M3 ;
        RECT  120.996 53.856 121.014 54 ;
    END
  END w[255]
  PIN w[25]
    DIRECTION OUTPUT ;
    USE SIGNAL ;
    PORT
      LAYER M3 ;
        RECT  86.148 53.856 86.166 54 ;
    END
  END w[25]
  PIN w[26]
    DIRECTION OUTPUT ;
    USE SIGNAL ;
    PORT
      LAYER M5 ;
        RECT  86.304 53.808 86.328 54 ;
    END
  END w[26]
  PIN w[27]
    DIRECTION OUTPUT ;
    USE SIGNAL ;
    PORT
      LAYER M3 ;
        RECT  86.472 53.856 86.49 54 ;
    END
  END w[27]
  PIN w[28]
    DIRECTION OUTPUT ;
    USE SIGNAL ;
    PORT
      LAYER M5 ;
        RECT  86.592 53.808 86.616 54 ;
    END
  END w[28]
  PIN w[29]
    DIRECTION OUTPUT ;
    USE SIGNAL ;
    PORT
      LAYER M3 ;
        RECT  86.76 53.856 86.778 54 ;
    END
  END w[29]
  PIN w[2]
    DIRECTION OUTPUT ;
    USE SIGNAL ;
    PORT
      LAYER M5 ;
        RECT  82.656 53.808 82.68 54 ;
    END
  END w[2]
  PIN w[30]
    DIRECTION OUTPUT ;
    USE SIGNAL ;
    PORT
      LAYER M5 ;
        RECT  86.928 53.808 86.952 54 ;
    END
  END w[30]
  PIN w[31]
    DIRECTION OUTPUT ;
    USE SIGNAL ;
    PORT
      LAYER M3 ;
        RECT  87.084 53.856 87.102 54 ;
    END
  END w[31]
  PIN w[32]
    DIRECTION OUTPUT ;
    USE SIGNAL ;
    PORT
      LAYER M5 ;
        RECT  87.216 53.808 87.24 54 ;
    END
  END w[32]
  PIN w[33]
    DIRECTION OUTPUT ;
    USE SIGNAL ;
    PORT
      LAYER M3 ;
        RECT  87.372 53.856 87.39 54 ;
    END
  END w[33]
  PIN w[34]
    DIRECTION OUTPUT ;
    USE SIGNAL ;
    PORT
      LAYER M5 ;
        RECT  87.504 53.808 87.528 54 ;
    END
  END w[34]
  PIN w[35]
    DIRECTION OUTPUT ;
    USE SIGNAL ;
    PORT
      LAYER M3 ;
        RECT  87.66 53.856 87.678 54 ;
    END
  END w[35]
  PIN w[36]
    DIRECTION OUTPUT ;
    USE SIGNAL ;
    PORT
      LAYER M5 ;
        RECT  87.84 53.808 87.864 54 ;
    END
  END w[36]
  PIN w[37]
    DIRECTION OUTPUT ;
    USE SIGNAL ;
    PORT
      LAYER M3 ;
        RECT  87.984 53.856 88.002 54 ;
    END
  END w[37]
  PIN w[38]
    DIRECTION OUTPUT ;
    USE SIGNAL ;
    PORT
      LAYER M5 ;
        RECT  88.128 53.808 88.152 54 ;
    END
  END w[38]
  PIN w[39]
    DIRECTION OUTPUT ;
    USE SIGNAL ;
    PORT
      LAYER M3 ;
        RECT  88.272 53.856 88.29 54 ;
    END
  END w[39]
  PIN w[3]
    DIRECTION OUTPUT ;
    USE SIGNAL ;
    PORT
      LAYER M3 ;
        RECT  82.836 53.856 82.854 54 ;
    END
  END w[3]
  PIN w[40]
    DIRECTION OUTPUT ;
    USE SIGNAL ;
    PORT
      LAYER M5 ;
        RECT  88.416 53.808 88.44 54 ;
    END
  END w[40]
  PIN w[41]
    DIRECTION OUTPUT ;
    USE SIGNAL ;
    PORT
      LAYER M3 ;
        RECT  88.596 53.856 88.614 54 ;
    END
  END w[41]
  PIN w[42]
    DIRECTION OUTPUT ;
    USE SIGNAL ;
    PORT
      LAYER M5 ;
        RECT  88.752 53.808 88.776 54 ;
    END
  END w[42]
  PIN w[43]
    DIRECTION OUTPUT ;
    USE SIGNAL ;
    PORT
      LAYER M3 ;
        RECT  88.884 53.856 88.902 54 ;
    END
  END w[43]
  PIN w[44]
    DIRECTION OUTPUT ;
    USE SIGNAL ;
    PORT
      LAYER M5 ;
        RECT  89.04 53.808 89.064 54 ;
    END
  END w[44]
  PIN w[45]
    DIRECTION OUTPUT ;
    USE SIGNAL ;
    PORT
      LAYER M3 ;
        RECT  89.172 53.856 89.19 54 ;
    END
  END w[45]
  PIN w[46]
    DIRECTION OUTPUT ;
    USE SIGNAL ;
    PORT
      LAYER M5 ;
        RECT  89.328 53.808 89.352 54 ;
    END
  END w[46]
  PIN w[47]
    DIRECTION OUTPUT ;
    USE SIGNAL ;
    PORT
      LAYER M3 ;
        RECT  89.496 53.856 89.514 54 ;
    END
  END w[47]
  PIN w[48]
    DIRECTION OUTPUT ;
    USE SIGNAL ;
    PORT
      LAYER M5 ;
        RECT  89.616 53.808 89.64 54 ;
    END
  END w[48]
  PIN w[49]
    DIRECTION OUTPUT ;
    USE SIGNAL ;
    PORT
      LAYER M3 ;
        RECT  89.784 53.856 89.802 54 ;
    END
  END w[49]
  PIN w[4]
    DIRECTION OUTPUT ;
    USE SIGNAL ;
    PORT
      LAYER M5 ;
        RECT  82.992 53.808 83.016 54 ;
    END
  END w[4]
  PIN w[50]
    DIRECTION OUTPUT ;
    USE SIGNAL ;
    PORT
      LAYER M5 ;
        RECT  89.952 53.808 89.976 54 ;
    END
  END w[50]
  PIN w[51]
    DIRECTION OUTPUT ;
    USE SIGNAL ;
    PORT
      LAYER M3 ;
        RECT  90.108 53.856 90.126 54 ;
    END
  END w[51]
  PIN w[52]
    DIRECTION OUTPUT ;
    USE SIGNAL ;
    PORT
      LAYER M5 ;
        RECT  90.24 53.808 90.264 54 ;
    END
  END w[52]
  PIN w[53]
    DIRECTION OUTPUT ;
    USE SIGNAL ;
    PORT
      LAYER M3 ;
        RECT  90.396 53.856 90.414 54 ;
    END
  END w[53]
  PIN w[54]
    DIRECTION OUTPUT ;
    USE SIGNAL ;
    PORT
      LAYER M5 ;
        RECT  90.528 53.808 90.552 54 ;
    END
  END w[54]
  PIN w[55]
    DIRECTION OUTPUT ;
    USE SIGNAL ;
    PORT
      LAYER M3 ;
        RECT  90.72 53.856 90.738 54 ;
    END
  END w[55]
  PIN w[56]
    DIRECTION OUTPUT ;
    USE SIGNAL ;
    PORT
      LAYER M5 ;
        RECT  90.864 53.808 90.888 54 ;
    END
  END w[56]
  PIN w[57]
    DIRECTION OUTPUT ;
    USE SIGNAL ;
    PORT
      LAYER M3 ;
        RECT  91.008 53.856 91.026 54 ;
    END
  END w[57]
  PIN w[58]
    DIRECTION OUTPUT ;
    USE SIGNAL ;
    PORT
      LAYER M5 ;
        RECT  91.152 53.808 91.176 54 ;
    END
  END w[58]
  PIN w[59]
    DIRECTION OUTPUT ;
    USE SIGNAL ;
    PORT
      LAYER M3 ;
        RECT  91.296 53.856 91.314 54 ;
    END
  END w[59]
  PIN w[5]
    DIRECTION OUTPUT ;
    USE SIGNAL ;
    PORT
      LAYER M3 ;
        RECT  83.124 53.856 83.142 54 ;
    END
  END w[5]
  PIN w[60]
    DIRECTION OUTPUT ;
    USE SIGNAL ;
    PORT
      LAYER M5 ;
        RECT  91.44 53.808 91.464 54 ;
    END
  END w[60]
  PIN w[61]
    DIRECTION OUTPUT ;
    USE SIGNAL ;
    PORT
      LAYER M3 ;
        RECT  91.62 53.856 91.638 54 ;
    END
  END w[61]
  PIN w[62]
    DIRECTION OUTPUT ;
    USE SIGNAL ;
    PORT
      LAYER M5 ;
        RECT  91.776 53.808 91.8 54 ;
    END
  END w[62]
  PIN w[63]
    DIRECTION OUTPUT ;
    USE SIGNAL ;
    PORT
      LAYER M3 ;
        RECT  91.908 53.856 91.926 54 ;
    END
  END w[63]
  PIN w[64]
    DIRECTION OUTPUT ;
    USE SIGNAL ;
    PORT
      LAYER M5 ;
        RECT  92.064 53.808 92.088 54 ;
    END
  END w[64]
  PIN w[65]
    DIRECTION OUTPUT ;
    USE SIGNAL ;
    PORT
      LAYER M3 ;
        RECT  92.232 53.856 92.25 54 ;
    END
  END w[65]
  PIN w[66]
    DIRECTION OUTPUT ;
    USE SIGNAL ;
    PORT
      LAYER M5 ;
        RECT  92.352 53.808 92.376 54 ;
    END
  END w[66]
  PIN w[67]
    DIRECTION OUTPUT ;
    USE SIGNAL ;
    PORT
      LAYER M3 ;
        RECT  92.52 53.856 92.538 54 ;
    END
  END w[67]
  PIN w[68]
    DIRECTION OUTPUT ;
    USE SIGNAL ;
    PORT
      LAYER M5 ;
        RECT  92.688 53.808 92.712 54 ;
    END
  END w[68]
  PIN w[69]
    DIRECTION OUTPUT ;
    USE SIGNAL ;
    PORT
      LAYER M3 ;
        RECT  92.808 53.856 92.826 54 ;
    END
  END w[69]
  PIN w[6]
    DIRECTION OUTPUT ;
    USE SIGNAL ;
    PORT
      LAYER M5 ;
        RECT  83.28 53.808 83.304 54 ;
    END
  END w[6]
  PIN w[70]
    DIRECTION OUTPUT ;
    USE SIGNAL ;
    PORT
      LAYER M5 ;
        RECT  92.976 53.808 93 54 ;
    END
  END w[70]
  PIN w[71]
    DIRECTION OUTPUT ;
    USE SIGNAL ;
    PORT
      LAYER M3 ;
        RECT  93.132 53.856 93.15 54 ;
    END
  END w[71]
  PIN w[72]
    DIRECTION OUTPUT ;
    USE SIGNAL ;
    PORT
      LAYER M5 ;
        RECT  93.264 53.808 93.288 54 ;
    END
  END w[72]
  PIN w[73]
    DIRECTION OUTPUT ;
    USE SIGNAL ;
    PORT
      LAYER M3 ;
        RECT  93.42 53.856 93.438 54 ;
    END
  END w[73]
  PIN w[74]
    DIRECTION OUTPUT ;
    USE SIGNAL ;
    PORT
      LAYER M5 ;
        RECT  93.6 53.808 93.624 54 ;
    END
  END w[74]
  PIN w[75]
    DIRECTION OUTPUT ;
    USE SIGNAL ;
    PORT
      LAYER M3 ;
        RECT  93.744 53.856 93.762 54 ;
    END
  END w[75]
  PIN w[76]
    DIRECTION OUTPUT ;
    USE SIGNAL ;
    PORT
      LAYER M5 ;
        RECT  93.888 53.808 93.912 54 ;
    END
  END w[76]
  PIN w[77]
    DIRECTION OUTPUT ;
    USE SIGNAL ;
    PORT
      LAYER M3 ;
        RECT  94.032 53.856 94.05 54 ;
    END
  END w[77]
  PIN w[78]
    DIRECTION OUTPUT ;
    USE SIGNAL ;
    PORT
      LAYER M5 ;
        RECT  94.176 53.808 94.2 54 ;
    END
  END w[78]
  PIN w[79]
    DIRECTION OUTPUT ;
    USE SIGNAL ;
    PORT
      LAYER M3 ;
        RECT  94.32 53.856 94.338 54 ;
    END
  END w[79]
  PIN w[7]
    DIRECTION OUTPUT ;
    USE SIGNAL ;
    PORT
      LAYER M3 ;
        RECT  83.448 53.856 83.466 54 ;
    END
  END w[7]
  PIN w[80]
    DIRECTION OUTPUT ;
    USE SIGNAL ;
    PORT
      LAYER M5 ;
        RECT  94.464 53.808 94.488 54 ;
    END
  END w[80]
  PIN w[81]
    DIRECTION OUTPUT ;
    USE SIGNAL ;
    PORT
      LAYER M3 ;
        RECT  94.644 53.856 94.662 54 ;
    END
  END w[81]
  PIN w[82]
    DIRECTION OUTPUT ;
    USE SIGNAL ;
    PORT
      LAYER M5 ;
        RECT  94.8 53.808 94.824 54 ;
    END
  END w[82]
  PIN w[83]
    DIRECTION OUTPUT ;
    USE SIGNAL ;
    PORT
      LAYER M3 ;
        RECT  94.932 53.856 94.95 54 ;
    END
  END w[83]
  PIN w[84]
    DIRECTION OUTPUT ;
    USE SIGNAL ;
    PORT
      LAYER M5 ;
        RECT  95.088 53.808 95.112 54 ;
    END
  END w[84]
  PIN w[85]
    DIRECTION OUTPUT ;
    USE SIGNAL ;
    PORT
      LAYER M3 ;
        RECT  95.256 53.856 95.274 54 ;
    END
  END w[85]
  PIN w[86]
    DIRECTION OUTPUT ;
    USE SIGNAL ;
    PORT
      LAYER M5 ;
        RECT  95.376 53.808 95.4 54 ;
    END
  END w[86]
  PIN w[87]
    DIRECTION OUTPUT ;
    USE SIGNAL ;
    PORT
      LAYER M3 ;
        RECT  95.544 53.856 95.562 54 ;
    END
  END w[87]
  PIN w[88]
    DIRECTION OUTPUT ;
    USE SIGNAL ;
    PORT
      LAYER M5 ;
        RECT  95.712 53.808 95.736 54 ;
    END
  END w[88]
  PIN w[89]
    DIRECTION OUTPUT ;
    USE SIGNAL ;
    PORT
      LAYER M3 ;
        RECT  95.868 53.856 95.886 54 ;
    END
  END w[89]
  PIN w[8]
    DIRECTION OUTPUT ;
    USE SIGNAL ;
    PORT
      LAYER M5 ;
        RECT  83.568 53.808 83.592 54 ;
    END
  END w[8]
  PIN w[90]
    DIRECTION OUTPUT ;
    USE SIGNAL ;
    PORT
      LAYER M5 ;
        RECT  96 53.808 96.024 54 ;
    END
  END w[90]
  PIN w[91]
    DIRECTION OUTPUT ;
    USE SIGNAL ;
    PORT
      LAYER M3 ;
        RECT  96.156 53.856 96.174 54 ;
    END
  END w[91]
  PIN w[92]
    DIRECTION OUTPUT ;
    USE SIGNAL ;
    PORT
      LAYER M5 ;
        RECT  96.288 53.808 96.312 54 ;
    END
  END w[92]
  PIN w[93]
    DIRECTION OUTPUT ;
    USE SIGNAL ;
    PORT
      LAYER M3 ;
        RECT  96.444 53.856 96.462 54 ;
    END
  END w[93]
  PIN w[94]
    DIRECTION OUTPUT ;
    USE SIGNAL ;
    PORT
      LAYER M5 ;
        RECT  96.624 53.808 96.648 54 ;
    END
  END w[94]
  PIN w[95]
    DIRECTION OUTPUT ;
    USE SIGNAL ;
    PORT
      LAYER M3 ;
        RECT  96.768 53.856 96.786 54 ;
    END
  END w[95]
  PIN w[96]
    DIRECTION OUTPUT ;
    USE SIGNAL ;
    PORT
      LAYER M5 ;
        RECT  96.912 53.808 96.936 54 ;
    END
  END w[96]
  PIN w[97]
    DIRECTION OUTPUT ;
    USE SIGNAL ;
    PORT
      LAYER M3 ;
        RECT  97.056 53.856 97.074 54 ;
    END
  END w[97]
  PIN w[98]
    DIRECTION OUTPUT ;
    USE SIGNAL ;
    PORT
      LAYER M5 ;
        RECT  97.2 53.808 97.224 54 ;
    END
  END w[98]
  PIN w[99]
    DIRECTION OUTPUT ;
    USE SIGNAL ;
    PORT
      LAYER M3 ;
        RECT  97.38 53.856 97.398 54 ;
    END
  END w[99]
  PIN w[9]
    DIRECTION OUTPUT ;
    USE SIGNAL ;
    PORT
      LAYER M3 ;
        RECT  83.736 53.856 83.754 54 ;
    END
  END w[9]
  PIN wq_d[0]
    DIRECTION OUTPUT ;
    USE SIGNAL ;
    PORT
      LAYER M5 ;
        RECT  134.16 0 134.184 0.192 ;
    END
  END wq_d[0]
  PIN wq_d[100]
    DIRECTION OUTPUT ;
    USE SIGNAL ;
    PORT
      LAYER M5 ;
        RECT  154.272 0 154.296 0.192 ;
    END
  END wq_d[100]
  PIN wq_d[101]
    DIRECTION OUTPUT ;
    USE SIGNAL ;
    PORT
      LAYER M3 ;
        RECT  154.512 0 154.53 0.144 ;
    END
  END wq_d[101]
  PIN wq_d[102]
    DIRECTION OUTPUT ;
    USE SIGNAL ;
    PORT
      LAYER M5 ;
        RECT  154.704 0 154.728 0.192 ;
    END
  END wq_d[102]
  PIN wq_d[103]
    DIRECTION OUTPUT ;
    USE SIGNAL ;
    PORT
      LAYER M3 ;
        RECT  154.908 0 154.926 0.144 ;
    END
  END wq_d[103]
  PIN wq_d[104]
    DIRECTION OUTPUT ;
    USE SIGNAL ;
    PORT
      LAYER M5 ;
        RECT  155.088 0 155.112 0.192 ;
    END
  END wq_d[104]
  PIN wq_d[105]
    DIRECTION OUTPUT ;
    USE SIGNAL ;
    PORT
      LAYER M3 ;
        RECT  155.304 0 155.322 0.144 ;
    END
  END wq_d[105]
  PIN wq_d[106]
    DIRECTION OUTPUT ;
    USE SIGNAL ;
    PORT
      LAYER M5 ;
        RECT  155.52 0 155.544 0.192 ;
    END
  END wq_d[106]
  PIN wq_d[107]
    DIRECTION OUTPUT ;
    USE SIGNAL ;
    PORT
      LAYER M3 ;
        RECT  155.7 0 155.718 0.144 ;
    END
  END wq_d[107]
  PIN wq_d[108]
    DIRECTION OUTPUT ;
    USE SIGNAL ;
    PORT
      LAYER M5 ;
        RECT  155.904 0 155.928 0.192 ;
    END
  END wq_d[108]
  PIN wq_d[109]
    DIRECTION OUTPUT ;
    USE SIGNAL ;
    PORT
      LAYER M3 ;
        RECT  156.096 0 156.114 0.144 ;
    END
  END wq_d[109]
  PIN wq_d[10]
    DIRECTION OUTPUT ;
    USE SIGNAL ;
    PORT
      LAYER M5 ;
        RECT  136.176 0 136.2 0.192 ;
    END
  END wq_d[10]
  PIN wq_d[110]
    DIRECTION OUTPUT ;
    USE SIGNAL ;
    PORT
      LAYER M5 ;
        RECT  156.288 0 156.312 0.192 ;
    END
  END wq_d[110]
  PIN wq_d[111]
    DIRECTION OUTPUT ;
    USE SIGNAL ;
    PORT
      LAYER M3 ;
        RECT  156.528 0 156.546 0.144 ;
    END
  END wq_d[111]
  PIN wq_d[112]
    DIRECTION OUTPUT ;
    USE SIGNAL ;
    PORT
      LAYER M5 ;
        RECT  156.72 0 156.744 0.192 ;
    END
  END wq_d[112]
  PIN wq_d[113]
    DIRECTION OUTPUT ;
    USE SIGNAL ;
    PORT
      LAYER M3 ;
        RECT  156.924 0 156.942 0.144 ;
    END
  END wq_d[113]
  PIN wq_d[114]
    DIRECTION OUTPUT ;
    USE SIGNAL ;
    PORT
      LAYER M5 ;
        RECT  157.104 0 157.128 0.192 ;
    END
  END wq_d[114]
  PIN wq_d[115]
    DIRECTION OUTPUT ;
    USE SIGNAL ;
    PORT
      LAYER M3 ;
        RECT  157.32 0 157.338 0.144 ;
    END
  END wq_d[115]
  PIN wq_d[116]
    DIRECTION OUTPUT ;
    USE SIGNAL ;
    PORT
      LAYER M5 ;
        RECT  157.536 0 157.56 0.192 ;
    END
  END wq_d[116]
  PIN wq_d[117]
    DIRECTION OUTPUT ;
    USE SIGNAL ;
    PORT
      LAYER M3 ;
        RECT  157.716 0 157.734 0.144 ;
    END
  END wq_d[117]
  PIN wq_d[118]
    DIRECTION OUTPUT ;
    USE SIGNAL ;
    PORT
      LAYER M5 ;
        RECT  157.92 0 157.944 0.192 ;
    END
  END wq_d[118]
  PIN wq_d[119]
    DIRECTION OUTPUT ;
    USE SIGNAL ;
    PORT
      LAYER M3 ;
        RECT  158.112 0 158.13 0.144 ;
    END
  END wq_d[119]
  PIN wq_d[11]
    DIRECTION OUTPUT ;
    USE SIGNAL ;
    PORT
      LAYER M3 ;
        RECT  136.404 0 136.422 0.144 ;
    END
  END wq_d[11]
  PIN wq_d[120]
    DIRECTION OUTPUT ;
    USE SIGNAL ;
    PORT
      LAYER M5 ;
        RECT  158.304 0 158.328 0.192 ;
    END
  END wq_d[120]
  PIN wq_d[121]
    DIRECTION OUTPUT ;
    USE SIGNAL ;
    PORT
      LAYER M3 ;
        RECT  158.508 0 158.526 0.144 ;
    END
  END wq_d[121]
  PIN wq_d[122]
    DIRECTION OUTPUT ;
    USE SIGNAL ;
    PORT
      LAYER M5 ;
        RECT  158.736 0 158.76 0.192 ;
    END
  END wq_d[122]
  PIN wq_d[123]
    DIRECTION OUTPUT ;
    USE SIGNAL ;
    PORT
      LAYER M3 ;
        RECT  158.94 0 158.958 0.144 ;
    END
  END wq_d[123]
  PIN wq_d[124]
    DIRECTION OUTPUT ;
    USE SIGNAL ;
    PORT
      LAYER M5 ;
        RECT  159.12 0 159.144 0.192 ;
    END
  END wq_d[124]
  PIN wq_d[125]
    DIRECTION OUTPUT ;
    USE SIGNAL ;
    PORT
      LAYER M3 ;
        RECT  159.336 0 159.354 0.144 ;
    END
  END wq_d[125]
  PIN wq_d[126]
    DIRECTION OUTPUT ;
    USE SIGNAL ;
    PORT
      LAYER M5 ;
        RECT  159.504 0 159.528 0.192 ;
    END
  END wq_d[126]
  PIN wq_d[127]
    DIRECTION OUTPUT ;
    USE SIGNAL ;
    PORT
      LAYER M3 ;
        RECT  159.732 0 159.75 0.144 ;
    END
  END wq_d[127]
  PIN wq_d[12]
    DIRECTION OUTPUT ;
    USE SIGNAL ;
    PORT
      LAYER M5 ;
        RECT  136.608 0 136.632 0.192 ;
    END
  END wq_d[12]
  PIN wq_d[13]
    DIRECTION OUTPUT ;
    USE SIGNAL ;
    PORT
      LAYER M3 ;
        RECT  136.8 0 136.818 0.144 ;
    END
  END wq_d[13]
  PIN wq_d[14]
    DIRECTION OUTPUT ;
    USE SIGNAL ;
    PORT
      LAYER M5 ;
        RECT  136.992 0 137.016 0.192 ;
    END
  END wq_d[14]
  PIN wq_d[15]
    DIRECTION OUTPUT ;
    USE SIGNAL ;
    PORT
      LAYER M3 ;
        RECT  137.196 0 137.214 0.144 ;
    END
  END wq_d[15]
  PIN wq_d[16]
    DIRECTION OUTPUT ;
    USE SIGNAL ;
    PORT
      LAYER M5 ;
        RECT  137.376 0 137.4 0.192 ;
    END
  END wq_d[16]
  PIN wq_d[17]
    DIRECTION OUTPUT ;
    USE SIGNAL ;
    PORT
      LAYER M3 ;
        RECT  137.592 0 137.61 0.144 ;
    END
  END wq_d[17]
  PIN wq_d[18]
    DIRECTION OUTPUT ;
    USE SIGNAL ;
    PORT
      LAYER M5 ;
        RECT  137.808 0 137.832 0.192 ;
    END
  END wq_d[18]
  PIN wq_d[19]
    DIRECTION OUTPUT ;
    USE SIGNAL ;
    PORT
      LAYER M3 ;
        RECT  137.988 0 138.006 0.144 ;
    END
  END wq_d[19]
  PIN wq_d[1]
    DIRECTION OUTPUT ;
    USE SIGNAL ;
    PORT
      LAYER M3 ;
        RECT  134.388 0 134.406 0.144 ;
    END
  END wq_d[1]
  PIN wq_d[20]
    DIRECTION OUTPUT ;
    USE SIGNAL ;
    PORT
      LAYER M5 ;
        RECT  138.192 0 138.216 0.192 ;
    END
  END wq_d[20]
  PIN wq_d[21]
    DIRECTION OUTPUT ;
    USE SIGNAL ;
    PORT
      LAYER M3 ;
        RECT  138.42 0 138.438 0.144 ;
    END
  END wq_d[21]
  PIN wq_d[22]
    DIRECTION OUTPUT ;
    USE SIGNAL ;
    PORT
      LAYER M5 ;
        RECT  138.624 0 138.648 0.192 ;
    END
  END wq_d[22]
  PIN wq_d[23]
    DIRECTION OUTPUT ;
    USE SIGNAL ;
    PORT
      LAYER M3 ;
        RECT  138.816 0 138.834 0.144 ;
    END
  END wq_d[23]
  PIN wq_d[24]
    DIRECTION OUTPUT ;
    USE SIGNAL ;
    PORT
      LAYER M5 ;
        RECT  139.008 0 139.032 0.192 ;
    END
  END wq_d[24]
  PIN wq_d[25]
    DIRECTION OUTPUT ;
    USE SIGNAL ;
    PORT
      LAYER M3 ;
        RECT  139.212 0 139.23 0.144 ;
    END
  END wq_d[25]
  PIN wq_d[26]
    DIRECTION OUTPUT ;
    USE SIGNAL ;
    PORT
      LAYER M5 ;
        RECT  139.392 0 139.416 0.192 ;
    END
  END wq_d[26]
  PIN wq_d[27]
    DIRECTION OUTPUT ;
    USE SIGNAL ;
    PORT
      LAYER M3 ;
        RECT  139.608 0 139.626 0.144 ;
    END
  END wq_d[27]
  PIN wq_d[28]
    DIRECTION OUTPUT ;
    USE SIGNAL ;
    PORT
      LAYER M5 ;
        RECT  139.824 0 139.848 0.192 ;
    END
  END wq_d[28]
  PIN wq_d[29]
    DIRECTION OUTPUT ;
    USE SIGNAL ;
    PORT
      LAYER M3 ;
        RECT  140.004 0 140.022 0.144 ;
    END
  END wq_d[29]
  PIN wq_d[2]
    DIRECTION OUTPUT ;
    USE SIGNAL ;
    PORT
      LAYER M5 ;
        RECT  134.592 0 134.616 0.192 ;
    END
  END wq_d[2]
  PIN wq_d[30]
    DIRECTION OUTPUT ;
    USE SIGNAL ;
    PORT
      LAYER M5 ;
        RECT  140.208 0 140.232 0.192 ;
    END
  END wq_d[30]
  PIN wq_d[31]
    DIRECTION OUTPUT ;
    USE SIGNAL ;
    PORT
      LAYER M3 ;
        RECT  140.4 0 140.418 0.144 ;
    END
  END wq_d[31]
  PIN wq_d[32]
    DIRECTION OUTPUT ;
    USE SIGNAL ;
    PORT
      LAYER M5 ;
        RECT  140.592 0 140.616 0.192 ;
    END
  END wq_d[32]
  PIN wq_d[33]
    DIRECTION OUTPUT ;
    USE SIGNAL ;
    PORT
      LAYER M3 ;
        RECT  140.832 0 140.85 0.144 ;
    END
  END wq_d[33]
  PIN wq_d[34]
    DIRECTION OUTPUT ;
    USE SIGNAL ;
    PORT
      LAYER M5 ;
        RECT  141.024 0 141.048 0.192 ;
    END
  END wq_d[34]
  PIN wq_d[35]
    DIRECTION OUTPUT ;
    USE SIGNAL ;
    PORT
      LAYER M3 ;
        RECT  141.228 0 141.246 0.144 ;
    END
  END wq_d[35]
  PIN wq_d[36]
    DIRECTION OUTPUT ;
    USE SIGNAL ;
    PORT
      LAYER M5 ;
        RECT  141.408 0 141.432 0.192 ;
    END
  END wq_d[36]
  PIN wq_d[37]
    DIRECTION OUTPUT ;
    USE SIGNAL ;
    PORT
      LAYER M3 ;
        RECT  141.624 0 141.642 0.144 ;
    END
  END wq_d[37]
  PIN wq_d[38]
    DIRECTION OUTPUT ;
    USE SIGNAL ;
    PORT
      LAYER M5 ;
        RECT  141.84 0 141.864 0.192 ;
    END
  END wq_d[38]
  PIN wq_d[39]
    DIRECTION OUTPUT ;
    USE SIGNAL ;
    PORT
      LAYER M3 ;
        RECT  142.02 0 142.038 0.144 ;
    END
  END wq_d[39]
  PIN wq_d[3]
    DIRECTION OUTPUT ;
    USE SIGNAL ;
    PORT
      LAYER M3 ;
        RECT  134.784 0 134.802 0.144 ;
    END
  END wq_d[3]
  PIN wq_d[40]
    DIRECTION OUTPUT ;
    USE SIGNAL ;
    PORT
      LAYER M5 ;
        RECT  142.224 0 142.248 0.192 ;
    END
  END wq_d[40]
  PIN wq_d[41]
    DIRECTION OUTPUT ;
    USE SIGNAL ;
    PORT
      LAYER M3 ;
        RECT  142.416 0 142.434 0.144 ;
    END
  END wq_d[41]
  PIN wq_d[42]
    DIRECTION OUTPUT ;
    USE SIGNAL ;
    PORT
      LAYER M5 ;
        RECT  142.608 0 142.632 0.192 ;
    END
  END wq_d[42]
  PIN wq_d[43]
    DIRECTION OUTPUT ;
    USE SIGNAL ;
    PORT
      LAYER M3 ;
        RECT  142.848 0 142.866 0.144 ;
    END
  END wq_d[43]
  PIN wq_d[44]
    DIRECTION OUTPUT ;
    USE SIGNAL ;
    PORT
      LAYER M5 ;
        RECT  143.04 0 143.064 0.192 ;
    END
  END wq_d[44]
  PIN wq_d[45]
    DIRECTION OUTPUT ;
    USE SIGNAL ;
    PORT
      LAYER M3 ;
        RECT  143.244 0 143.262 0.144 ;
    END
  END wq_d[45]
  PIN wq_d[46]
    DIRECTION OUTPUT ;
    USE SIGNAL ;
    PORT
      LAYER M5 ;
        RECT  143.424 0 143.448 0.192 ;
    END
  END wq_d[46]
  PIN wq_d[47]
    DIRECTION OUTPUT ;
    USE SIGNAL ;
    PORT
      LAYER M3 ;
        RECT  143.64 0 143.658 0.144 ;
    END
  END wq_d[47]
  PIN wq_d[48]
    DIRECTION OUTPUT ;
    USE SIGNAL ;
    PORT
      LAYER M5 ;
        RECT  143.856 0 143.88 0.192 ;
    END
  END wq_d[48]
  PIN wq_d[49]
    DIRECTION OUTPUT ;
    USE SIGNAL ;
    PORT
      LAYER M3 ;
        RECT  144.036 0 144.054 0.144 ;
    END
  END wq_d[49]
  PIN wq_d[4]
    DIRECTION OUTPUT ;
    USE SIGNAL ;
    PORT
      LAYER M5 ;
        RECT  134.976 0 135 0.192 ;
    END
  END wq_d[4]
  PIN wq_d[50]
    DIRECTION OUTPUT ;
    USE SIGNAL ;
    PORT
      LAYER M5 ;
        RECT  144.24 0 144.264 0.192 ;
    END
  END wq_d[50]
  PIN wq_d[51]
    DIRECTION OUTPUT ;
    USE SIGNAL ;
    PORT
      LAYER M3 ;
        RECT  144.432 0 144.45 0.144 ;
    END
  END wq_d[51]
  PIN wq_d[52]
    DIRECTION OUTPUT ;
    USE SIGNAL ;
    PORT
      LAYER M5 ;
        RECT  144.624 0 144.648 0.192 ;
    END
  END wq_d[52]
  PIN wq_d[53]
    DIRECTION OUTPUT ;
    USE SIGNAL ;
    PORT
      LAYER M3 ;
        RECT  144.828 0 144.846 0.144 ;
    END
  END wq_d[53]
  PIN wq_d[54]
    DIRECTION OUTPUT ;
    USE SIGNAL ;
    PORT
      LAYER M5 ;
        RECT  145.056 0 145.08 0.192 ;
    END
  END wq_d[54]
  PIN wq_d[55]
    DIRECTION OUTPUT ;
    USE SIGNAL ;
    PORT
      LAYER M3 ;
        RECT  145.26 0 145.278 0.144 ;
    END
  END wq_d[55]
  PIN wq_d[56]
    DIRECTION OUTPUT ;
    USE SIGNAL ;
    PORT
      LAYER M5 ;
        RECT  145.44 0 145.464 0.192 ;
    END
  END wq_d[56]
  PIN wq_d[57]
    DIRECTION OUTPUT ;
    USE SIGNAL ;
    PORT
      LAYER M3 ;
        RECT  145.656 0 145.674 0.144 ;
    END
  END wq_d[57]
  PIN wq_d[58]
    DIRECTION OUTPUT ;
    USE SIGNAL ;
    PORT
      LAYER M5 ;
        RECT  145.824 0 145.848 0.192 ;
    END
  END wq_d[58]
  PIN wq_d[59]
    DIRECTION OUTPUT ;
    USE SIGNAL ;
    PORT
      LAYER M3 ;
        RECT  146.052 0 146.07 0.144 ;
    END
  END wq_d[59]
  PIN wq_d[5]
    DIRECTION OUTPUT ;
    USE SIGNAL ;
    PORT
      LAYER M3 ;
        RECT  135.18 0 135.198 0.144 ;
    END
  END wq_d[5]
  PIN wq_d[60]
    DIRECTION OUTPUT ;
    USE SIGNAL ;
    PORT
      LAYER M5 ;
        RECT  146.256 0 146.28 0.192 ;
    END
  END wq_d[60]
  PIN wq_d[61]
    DIRECTION OUTPUT ;
    USE SIGNAL ;
    PORT
      LAYER M3 ;
        RECT  146.448 0 146.466 0.144 ;
    END
  END wq_d[61]
  PIN wq_d[62]
    DIRECTION OUTPUT ;
    USE SIGNAL ;
    PORT
      LAYER M5 ;
        RECT  146.64 0 146.664 0.192 ;
    END
  END wq_d[62]
  PIN wq_d[63]
    DIRECTION OUTPUT ;
    USE SIGNAL ;
    PORT
      LAYER M3 ;
        RECT  146.844 0 146.862 0.144 ;
    END
  END wq_d[63]
  PIN wq_d[64]
    DIRECTION OUTPUT ;
    USE SIGNAL ;
    PORT
      LAYER M5 ;
        RECT  147.072 0 147.096 0.192 ;
    END
  END wq_d[64]
  PIN wq_d[65]
    DIRECTION OUTPUT ;
    USE SIGNAL ;
    PORT
      LAYER M3 ;
        RECT  147.24 0 147.258 0.144 ;
    END
  END wq_d[65]
  PIN wq_d[66]
    DIRECTION OUTPUT ;
    USE SIGNAL ;
    PORT
      LAYER M5 ;
        RECT  147.456 0 147.48 0.192 ;
    END
  END wq_d[66]
  PIN wq_d[67]
    DIRECTION OUTPUT ;
    USE SIGNAL ;
    PORT
      LAYER M3 ;
        RECT  147.672 0 147.69 0.144 ;
    END
  END wq_d[67]
  PIN wq_d[68]
    DIRECTION OUTPUT ;
    USE SIGNAL ;
    PORT
      LAYER M5 ;
        RECT  147.84 0 147.864 0.192 ;
    END
  END wq_d[68]
  PIN wq_d[69]
    DIRECTION OUTPUT ;
    USE SIGNAL ;
    PORT
      LAYER M3 ;
        RECT  148.068 0 148.086 0.144 ;
    END
  END wq_d[69]
  PIN wq_d[6]
    DIRECTION OUTPUT ;
    USE SIGNAL ;
    PORT
      LAYER M5 ;
        RECT  135.36 0 135.384 0.192 ;
    END
  END wq_d[6]
  PIN wq_d[70]
    DIRECTION OUTPUT ;
    USE SIGNAL ;
    PORT
      LAYER M5 ;
        RECT  148.272 0 148.296 0.192 ;
    END
  END wq_d[70]
  PIN wq_d[71]
    DIRECTION OUTPUT ;
    USE SIGNAL ;
    PORT
      LAYER M3 ;
        RECT  148.464 0 148.482 0.144 ;
    END
  END wq_d[71]
  PIN wq_d[72]
    DIRECTION OUTPUT ;
    USE SIGNAL ;
    PORT
      LAYER M5 ;
        RECT  148.656 0 148.68 0.192 ;
    END
  END wq_d[72]
  PIN wq_d[73]
    DIRECTION OUTPUT ;
    USE SIGNAL ;
    PORT
      LAYER M3 ;
        RECT  148.86 0 148.878 0.144 ;
    END
  END wq_d[73]
  PIN wq_d[74]
    DIRECTION OUTPUT ;
    USE SIGNAL ;
    PORT
      LAYER M5 ;
        RECT  149.088 0 149.112 0.192 ;
    END
  END wq_d[74]
  PIN wq_d[75]
    DIRECTION OUTPUT ;
    USE SIGNAL ;
    PORT
      LAYER M3 ;
        RECT  149.256 0 149.274 0.144 ;
    END
  END wq_d[75]
  PIN wq_d[76]
    DIRECTION OUTPUT ;
    USE SIGNAL ;
    PORT
      LAYER M5 ;
        RECT  149.472 0 149.496 0.192 ;
    END
  END wq_d[76]
  PIN wq_d[77]
    DIRECTION OUTPUT ;
    USE SIGNAL ;
    PORT
      LAYER M3 ;
        RECT  149.688 0 149.706 0.144 ;
    END
  END wq_d[77]
  PIN wq_d[78]
    DIRECTION OUTPUT ;
    USE SIGNAL ;
    PORT
      LAYER M5 ;
        RECT  149.856 0 149.88 0.192 ;
    END
  END wq_d[78]
  PIN wq_d[79]
    DIRECTION OUTPUT ;
    USE SIGNAL ;
    PORT
      LAYER M3 ;
        RECT  150.084 0 150.102 0.144 ;
    END
  END wq_d[79]
  PIN wq_d[7]
    DIRECTION OUTPUT ;
    USE SIGNAL ;
    PORT
      LAYER M3 ;
        RECT  135.576 0 135.594 0.144 ;
    END
  END wq_d[7]
  PIN wq_d[80]
    DIRECTION OUTPUT ;
    USE SIGNAL ;
    PORT
      LAYER M5 ;
        RECT  150.288 0 150.312 0.192 ;
    END
  END wq_d[80]
  PIN wq_d[81]
    DIRECTION OUTPUT ;
    USE SIGNAL ;
    PORT
      LAYER M3 ;
        RECT  150.48 0 150.498 0.144 ;
    END
  END wq_d[81]
  PIN wq_d[82]
    DIRECTION OUTPUT ;
    USE SIGNAL ;
    PORT
      LAYER M5 ;
        RECT  150.672 0 150.696 0.192 ;
    END
  END wq_d[82]
  PIN wq_d[83]
    DIRECTION OUTPUT ;
    USE SIGNAL ;
    PORT
      LAYER M3 ;
        RECT  150.876 0 150.894 0.144 ;
    END
  END wq_d[83]
  PIN wq_d[84]
    DIRECTION OUTPUT ;
    USE SIGNAL ;
    PORT
      LAYER M5 ;
        RECT  151.056 0 151.08 0.192 ;
    END
  END wq_d[84]
  PIN wq_d[85]
    DIRECTION OUTPUT ;
    USE SIGNAL ;
    PORT
      LAYER M3 ;
        RECT  151.272 0 151.29 0.144 ;
    END
  END wq_d[85]
  PIN wq_d[86]
    DIRECTION OUTPUT ;
    USE SIGNAL ;
    PORT
      LAYER M5 ;
        RECT  151.488 0 151.512 0.192 ;
    END
  END wq_d[86]
  PIN wq_d[87]
    DIRECTION OUTPUT ;
    USE SIGNAL ;
    PORT
      LAYER M3 ;
        RECT  151.668 0 151.686 0.144 ;
    END
  END wq_d[87]
  PIN wq_d[88]
    DIRECTION OUTPUT ;
    USE SIGNAL ;
    PORT
      LAYER M5 ;
        RECT  151.872 0 151.896 0.192 ;
    END
  END wq_d[88]
  PIN wq_d[89]
    DIRECTION OUTPUT ;
    USE SIGNAL ;
    PORT
      LAYER M3 ;
        RECT  152.1 0 152.118 0.144 ;
    END
  END wq_d[89]
  PIN wq_d[8]
    DIRECTION OUTPUT ;
    USE SIGNAL ;
    PORT
      LAYER M5 ;
        RECT  135.792 0 135.816 0.192 ;
    END
  END wq_d[8]
  PIN wq_d[90]
    DIRECTION OUTPUT ;
    USE SIGNAL ;
    PORT
      LAYER M5 ;
        RECT  152.304 0 152.328 0.192 ;
    END
  END wq_d[90]
  PIN wq_d[91]
    DIRECTION OUTPUT ;
    USE SIGNAL ;
    PORT
      LAYER M3 ;
        RECT  152.496 0 152.514 0.144 ;
    END
  END wq_d[91]
  PIN wq_d[92]
    DIRECTION OUTPUT ;
    USE SIGNAL ;
    PORT
      LAYER M5 ;
        RECT  152.688 0 152.712 0.192 ;
    END
  END wq_d[92]
  PIN wq_d[93]
    DIRECTION OUTPUT ;
    USE SIGNAL ;
    PORT
      LAYER M3 ;
        RECT  152.892 0 152.91 0.144 ;
    END
  END wq_d[93]
  PIN wq_d[94]
    DIRECTION OUTPUT ;
    USE SIGNAL ;
    PORT
      LAYER M5 ;
        RECT  153.072 0 153.096 0.192 ;
    END
  END wq_d[94]
  PIN wq_d[95]
    DIRECTION OUTPUT ;
    USE SIGNAL ;
    PORT
      LAYER M3 ;
        RECT  153.288 0 153.306 0.144 ;
    END
  END wq_d[95]
  PIN wq_d[96]
    DIRECTION OUTPUT ;
    USE SIGNAL ;
    PORT
      LAYER M5 ;
        RECT  153.504 0 153.528 0.192 ;
    END
  END wq_d[96]
  PIN wq_d[97]
    DIRECTION OUTPUT ;
    USE SIGNAL ;
    PORT
      LAYER M3 ;
        RECT  153.684 0 153.702 0.144 ;
    END
  END wq_d[97]
  PIN wq_d[98]
    DIRECTION OUTPUT ;
    USE SIGNAL ;
    PORT
      LAYER M5 ;
        RECT  153.888 0 153.912 0.192 ;
    END
  END wq_d[98]
  PIN wq_d[99]
    DIRECTION OUTPUT ;
    USE SIGNAL ;
    PORT
      LAYER M3 ;
        RECT  154.08 0 154.098 0.144 ;
    END
  END wq_d[99]
  PIN wq_d[9]
    DIRECTION OUTPUT ;
    USE SIGNAL ;
    PORT
      LAYER M3 ;
        RECT  135.972 0 135.99 0.144 ;
    END
  END wq_d[9]
  PIN VDD
    DIRECTION INOUT ;
    USE POWER ;
    PORT
      LAYER M5 ;
        RECT  159.192 2.151 159.312 51.849 ;
        RECT  153.792 2.151 153.912 51.849 ;
        RECT  148.392 2.151 148.512 51.849 ;
        RECT  142.992 2.151 143.112 51.849 ;
        RECT  137.592 2.151 137.712 51.849 ;
        RECT  132.192 2.151 132.312 51.849 ;
        RECT  126.792 2.151 126.912 51.849 ;
        RECT  121.392 2.151 121.512 51.849 ;
        RECT  115.992 2.151 116.112 51.849 ;
        RECT  110.592 2.151 110.712 51.849 ;
        RECT  105.192 2.151 105.312 51.849 ;
        RECT  99.792 2.151 99.912 51.849 ;
        RECT  94.392 2.151 94.512 51.849 ;
        RECT  88.992 2.151 89.112 51.849 ;
        RECT  83.592 2.151 83.712 51.849 ;
        RECT  78.192 2.151 78.312 51.849 ;
        RECT  72.792 2.151 72.912 51.849 ;
        RECT  67.392 2.151 67.512 51.849 ;
        RECT  61.992 2.151 62.112 51.849 ;
        RECT  56.592 2.151 56.712 51.849 ;
        RECT  51.192 2.151 51.312 51.849 ;
        RECT  45.792 2.151 45.912 51.849 ;
        RECT  40.392 2.151 40.512 51.849 ;
        RECT  34.992 2.151 35.112 51.849 ;
        RECT  29.592 2.151 29.712 51.849 ;
        RECT  24.192 2.151 24.312 51.849 ;
        RECT  18.792 2.151 18.912 51.849 ;
        RECT  13.392 2.151 13.512 51.849 ;
        RECT  7.992 2.151 8.112 51.849 ;
        RECT  2.592 2.151 2.712 51.849 ;
    END
  END VDD
  PIN VSS
    DIRECTION INOUT ;
    USE GROUND ;
    PORT
      LAYER M5 ;
        RECT  159 2.137 159.12 51.863 ;
        RECT  153.6 2.137 153.72 51.863 ;
        RECT  148.2 2.137 148.32 51.863 ;
        RECT  142.8 2.137 142.92 51.863 ;
        RECT  137.4 2.137 137.52 51.863 ;
        RECT  132 2.137 132.12 51.863 ;
        RECT  126.6 2.137 126.72 51.863 ;
        RECT  121.2 2.137 121.32 51.863 ;
        RECT  115.8 2.137 115.92 51.863 ;
        RECT  110.4 2.137 110.52 51.863 ;
        RECT  105 2.137 105.12 51.863 ;
        RECT  99.6 2.137 99.72 51.863 ;
        RECT  94.2 2.137 94.32 51.863 ;
        RECT  88.8 2.137 88.92 51.863 ;
        RECT  83.4 2.137 83.52 51.863 ;
        RECT  78 2.137 78.12 51.863 ;
        RECT  72.6 2.137 72.72 51.863 ;
        RECT  67.2 2.137 67.32 51.863 ;
        RECT  61.8 2.137 61.92 51.863 ;
        RECT  56.4 2.137 56.52 51.863 ;
        RECT  51 2.137 51.12 51.863 ;
        RECT  45.6 2.137 45.72 51.863 ;
        RECT  40.2 2.137 40.32 51.863 ;
        RECT  34.8 2.137 34.92 51.863 ;
        RECT  29.4 2.137 29.52 51.863 ;
        RECT  24 2.137 24.12 51.863 ;
        RECT  18.6 2.137 18.72 51.863 ;
        RECT  13.2 2.137 13.32 51.863 ;
        RECT  7.8 2.137 7.92 51.863 ;
        RECT  2.4 2.137 2.52 51.863 ;
    END
  END VSS
  OBS
    LAYER RVTN ;
     RECT  2.16 2.16 162 2.295 ;
     RECT  2.16 2.565 162 2.835 ;
     RECT  2.16 3.105 162 3.375 ;
     RECT  2.16 3.645 162 3.915 ;
     RECT  2.16 4.185 162 4.455 ;
     RECT  2.16 4.725 162 4.995 ;
     RECT  2.16 5.265 162 5.535 ;
     RECT  2.16 5.805 162 6.075 ;
     RECT  2.16 6.345 162 6.615 ;
     RECT  2.16 6.885 162 7.155 ;
     RECT  2.16 7.425 162 7.695 ;
     RECT  2.16 7.965 162 8.235 ;
     RECT  2.16 8.505 162 8.775 ;
     RECT  2.16 9.045 162 9.315 ;
     RECT  2.16 9.585 162 9.855 ;
     RECT  2.16 10.125 162 10.395 ;
     RECT  2.16 10.665 162 10.935 ;
     RECT  2.16 11.205 162 11.475 ;
     RECT  2.16 11.745 162 12.015 ;
     RECT  2.16 12.285 162 12.555 ;
     RECT  2.16 12.825 162 13.095 ;
     RECT  2.16 13.365 162 13.635 ;
     RECT  2.16 13.905 162 14.175 ;
     RECT  2.16 14.445 162 14.715 ;
     RECT  2.16 14.985 162 15.255 ;
     RECT  2.16 15.525 162 15.795 ;
     RECT  2.16 16.065 162 16.335 ;
     RECT  2.16 16.605 162 16.875 ;
     RECT  2.16 17.145 162 17.415 ;
     RECT  2.16 17.685 162 17.955 ;
     RECT  2.16 18.225 162 18.495 ;
     RECT  2.16 18.765 162 19.035 ;
     RECT  2.16 19.305 162 19.575 ;
     RECT  2.16 19.845 162 20.115 ;
     RECT  2.16 20.385 162 20.655 ;
     RECT  2.16 20.925 162 21.195 ;
     RECT  2.16 21.465 162 21.735 ;
     RECT  2.16 22.005 162 22.275 ;
     RECT  2.16 22.545 162 22.815 ;
     RECT  2.16 23.085 162 23.355 ;
     RECT  2.16 23.625 162 23.895 ;
     RECT  2.16 24.165 162 24.435 ;
     RECT  2.16 24.705 162 24.975 ;
     RECT  2.16 25.245 162 25.515 ;
     RECT  2.16 25.785 162 26.055 ;
     RECT  2.16 26.325 162 26.595 ;
     RECT  2.16 26.865 162 27.135 ;
     RECT  2.16 27.405 162 27.675 ;
     RECT  2.16 27.945 162 28.215 ;
     RECT  2.16 28.485 162 28.755 ;
     RECT  2.16 29.025 162 29.295 ;
     RECT  2.16 29.565 162 29.835 ;
     RECT  2.16 30.105 162 30.375 ;
     RECT  2.16 30.645 162 30.915 ;
     RECT  2.16 31.185 162 31.455 ;
     RECT  2.16 31.725 162 31.995 ;
     RECT  2.16 32.265 162 32.535 ;
     RECT  2.16 32.805 162 33.075 ;
     RECT  2.16 33.345 162 33.615 ;
     RECT  2.16 33.885 162 34.155 ;
     RECT  2.16 34.425 162 34.695 ;
     RECT  2.16 34.965 162 35.235 ;
     RECT  2.16 35.505 162 35.775 ;
     RECT  2.16 36.045 162 36.315 ;
     RECT  2.16 36.585 162 36.855 ;
     RECT  2.16 37.125 162 37.395 ;
     RECT  2.16 37.665 162 37.935 ;
     RECT  2.16 38.205 162 38.475 ;
     RECT  2.16 38.745 162 39.015 ;
     RECT  2.16 39.285 162 39.555 ;
     RECT  2.16 39.825 162 40.095 ;
     RECT  2.16 40.365 162 40.635 ;
     RECT  2.16 40.905 162 41.175 ;
     RECT  2.16 41.445 162 41.715 ;
     RECT  2.16 41.985 162 42.255 ;
     RECT  2.16 42.525 162 42.795 ;
     RECT  2.16 43.065 162 43.335 ;
     RECT  2.16 43.605 162 43.875 ;
     RECT  2.16 44.145 162 44.415 ;
     RECT  2.16 44.685 162 44.955 ;
     RECT  2.16 45.225 162 45.495 ;
     RECT  2.16 45.765 162 46.035 ;
     RECT  2.16 46.305 162 46.575 ;
     RECT  2.16 46.845 162 47.115 ;
     RECT  2.16 47.385 162 47.655 ;
     RECT  2.16 47.925 162 48.195 ;
     RECT  2.16 48.465 162 48.735 ;
     RECT  2.16 49.005 162 49.275 ;
     RECT  2.16 49.545 162 49.815 ;
     RECT  2.16 50.085 162 50.355 ;
     RECT  2.16 50.625 162 50.895 ;
     RECT  2.16 51.165 162 51.435 ;
     RECT  2.16 51.705 162 51.84 ;
    LAYER RVTP ;
     RECT  2.16 2.295 162 2.565 ;
     RECT  2.16 2.835 162 3.105 ;
     RECT  2.16 3.375 162 3.645 ;
     RECT  2.16 3.915 162 4.185 ;
     RECT  2.16 4.455 162 4.725 ;
     RECT  2.16 4.995 162 5.265 ;
     RECT  2.16 5.535 162 5.805 ;
     RECT  2.16 6.075 162 6.345 ;
     RECT  2.16 6.615 162 6.885 ;
     RECT  2.16 7.155 162 7.425 ;
     RECT  2.16 7.695 162 7.965 ;
     RECT  2.16 8.235 162 8.505 ;
     RECT  2.16 8.775 162 9.045 ;
     RECT  2.16 9.315 162 9.585 ;
     RECT  2.16 9.855 162 10.125 ;
     RECT  2.16 10.395 162 10.665 ;
     RECT  2.16 10.935 162 11.205 ;
     RECT  2.16 11.475 162 11.745 ;
     RECT  2.16 12.015 162 12.285 ;
     RECT  2.16 12.555 162 12.825 ;
     RECT  2.16 13.095 162 13.365 ;
     RECT  2.16 13.635 162 13.905 ;
     RECT  2.16 14.175 162 14.445 ;
     RECT  2.16 14.715 162 14.985 ;
     RECT  2.16 15.255 162 15.525 ;
     RECT  2.16 15.795 162 16.065 ;
     RECT  2.16 16.335 162 16.605 ;
     RECT  2.16 16.875 162 17.145 ;
     RECT  2.16 17.415 162 17.685 ;
     RECT  2.16 17.955 162 18.225 ;
     RECT  2.16 18.495 162 18.765 ;
     RECT  2.16 19.035 162 19.305 ;
     RECT  2.16 19.575 162 19.845 ;
     RECT  2.16 20.115 162 20.385 ;
     RECT  2.16 20.655 162 20.925 ;
     RECT  2.16 21.195 162 21.465 ;
     RECT  2.16 21.735 162 22.005 ;
     RECT  2.16 22.275 162 22.545 ;
     RECT  2.16 22.815 162 23.085 ;
     RECT  2.16 23.355 162 23.625 ;
     RECT  2.16 23.895 162 24.165 ;
     RECT  2.16 24.435 162 24.705 ;
     RECT  2.16 24.975 162 25.245 ;
     RECT  2.16 25.515 162 25.785 ;
     RECT  2.16 26.055 162 26.325 ;
     RECT  2.16 26.595 162 26.865 ;
     RECT  2.16 27.135 162 27.405 ;
     RECT  2.16 27.675 162 27.945 ;
     RECT  2.16 28.215 162 28.485 ;
     RECT  2.16 28.755 162 29.025 ;
     RECT  2.16 29.295 162 29.565 ;
     RECT  2.16 29.835 162 30.105 ;
     RECT  2.16 30.375 162 30.645 ;
     RECT  2.16 30.915 162 31.185 ;
     RECT  2.16 31.455 162 31.725 ;
     RECT  2.16 31.995 162 32.265 ;
     RECT  2.16 32.535 162 32.805 ;
     RECT  2.16 33.075 162 33.345 ;
     RECT  2.16 33.615 162 33.885 ;
     RECT  2.16 34.155 162 34.425 ;
     RECT  2.16 34.695 162 34.965 ;
     RECT  2.16 35.235 162 35.505 ;
     RECT  2.16 35.775 162 36.045 ;
     RECT  2.16 36.315 162 36.585 ;
     RECT  2.16 36.855 162 37.125 ;
     RECT  2.16 37.395 162 37.665 ;
     RECT  2.16 37.935 162 38.205 ;
     RECT  2.16 38.475 162 38.745 ;
     RECT  2.16 39.015 162 39.285 ;
     RECT  2.16 39.555 162 39.825 ;
     RECT  2.16 40.095 162 40.365 ;
     RECT  2.16 40.635 162 40.905 ;
     RECT  2.16 41.175 162 41.445 ;
     RECT  2.16 41.715 162 41.985 ;
     RECT  2.16 42.255 162 42.525 ;
     RECT  2.16 42.795 162 43.065 ;
     RECT  2.16 43.335 162 43.605 ;
     RECT  2.16 43.875 162 44.145 ;
     RECT  2.16 44.415 162 44.685 ;
     RECT  2.16 44.955 162 45.225 ;
     RECT  2.16 45.495 162 45.765 ;
     RECT  2.16 46.035 162 46.305 ;
     RECT  2.16 46.575 162 46.845 ;
     RECT  2.16 47.115 162 47.385 ;
     RECT  2.16 47.655 162 47.925 ;
     RECT  2.16 48.195 162 48.465 ;
     RECT  2.16 48.735 162 49.005 ;
     RECT  2.16 49.275 162 49.545 ;
     RECT  2.16 49.815 162 50.085 ;
     RECT  2.16 50.355 162 50.625 ;
     RECT  2.16 50.895 162 51.165 ;
     RECT  2.16 51.435 162 51.705 ;
    LAYER M1 ;
     RECT  2.16 2.151 162 51.849 ;
    LAYER M2 ;
     RECT  13.135 0.144 13.271 0.162 ;
     RECT  15.295 53.136 15.395 53.154 ;
     RECT  15.691 0.144 15.935 0.162 ;
     RECT  2.16 2.151 18.535 51.849 ;
     RECT  18.535 2.151 18.635 51.93 ;
     RECT  19.291 0.144 19.391 0.162 ;
     RECT  21.163 0.144 21.335 0.162 ;
     RECT  21.955 53.136 22.055 53.154 ;
     RECT  22.099 0.144 22.199 0.162 ;
     RECT  18.635 2.151 24.079 51.849 ;
     RECT  24.079 2.151 24.179 51.93 ;
     RECT  23.971 0.144 25.367 0.162 ;
     RECT  26.455 0.144 26.555 0.162 ;
     RECT  29.335 52.992 29.543 53.01 ;
     RECT  28.939 0.144 29.867 0.162 ;
     RECT  30.667 52.992 30.767 53.01 ;
     RECT  31.351 0.144 31.451 0.162 ;
     RECT  34.591 0.144 35.519 0.162 ;
     RECT  24.179 2.151 38.623 51.849 ;
     RECT  38.623 2.151 38.723 51.894 ;
     RECT  38.911 53.838 38.947 53.856 ;
     RECT  38.947 53.838 39.047 53.928 ;
     RECT  39.019 0.144 39.155 0.162 ;
     RECT  40.099 0.144 40.235 0.162 ;
     RECT  41.431 0.144 41.567 0.162 ;
     RECT  38.723 2.151 41.863 51.849 ;
     RECT  41.863 2.151 41.963 52.002 ;
     RECT  45.031 0.144 45.131 0.162 ;
     RECT  47.047 0.144 47.183 0.162 ;
     RECT  41.963 2.151 47.695 51.849 ;
     RECT  47.695 2.151 47.795 51.93 ;
     RECT  48.271 0.144 48.767 0.162 ;
     RECT  47.795 2.151 51.007 51.849 ;
     RECT  50.611 0.144 51.107 0.162 ;
     RECT  51.007 2.151 51.179 51.93 ;
     RECT  51.179 2.151 52.843 51.849 ;
     RECT  52.843 2.151 52.943 52.578 ;
     RECT  54.715 0.144 54.815 0.162 ;
     RECT  56.191 0.144 56.327 0.162 ;
     RECT  52.943 2.151 56.479 51.849 ;
     RECT  56.479 2.151 56.867 51.93 ;
     RECT  60.151 1.152 60.287 1.17 ;
     RECT  60.151 0.144 60.359 0.162 ;
     RECT  61.627 53.838 61.663 53.856 ;
     RECT  61.663 53.838 61.763 53.928 ;
     RECT  62.239 52.992 62.339 53.01 ;
     RECT  62.239 0.144 62.375 0.162 ;
     RECT  56.867 2.151 62.527 51.849 ;
     RECT  62.527 2.151 62.699 51.894 ;
     RECT  63.139 0.144 63.239 0.162 ;
     RECT  63.139 52.992 63.239 53.01 ;
     RECT  65.155 0.144 65.255 0.162 ;
     RECT  65.263 52.992 65.363 53.01 ;
     RECT  62.699 2.151 66.055 51.849 ;
     RECT  66.055 2.151 66.191 51.894 ;
     RECT  66.379 0.144 66.515 0.162 ;
     RECT  67.567 0.144 67.667 0.162 ;
     RECT  68.215 53.136 68.315 53.154 ;
     RECT  69.583 0.144 69.683 0.162 ;
     RECT  70.015 52.992 70.115 53.01 ;
     RECT  70.807 0.144 71.231 0.162 ;
     RECT  71.995 0.144 73.247 0.162 ;
     RECT  66.191 2.151 74.047 51.849 ;
     RECT  74.047 2.151 74.147 51.894 ;
     RECT  74.407 0.144 74.507 0.162 ;
     RECT  76.027 0.144 76.523 0.162 ;
     RECT  77.791 0.144 78.071 0.162 ;
     RECT  78.295 52.992 79.079 53.01 ;
     RECT  79.807 52.992 80.303 53.01 ;
     RECT  74.147 2.151 83.443 51.849 ;
     RECT  83.443 2.151 83.731 51.93 ;
     RECT  83.731 2.151 83.831 52.002 ;
     RECT  84.019 0.144 84.119 0.162 ;
     RECT  83.831 2.151 84.811 51.849 ;
     RECT  84.811 1.728 84.911 51.849 ;
     RECT  85.567 0.144 85.703 0.162 ;
     RECT  84.631 52.992 85.739 53.01 ;
     RECT  84.911 2.151 86.143 51.849 ;
     RECT  86.143 2.151 86.459 51.894 ;
     RECT  86.899 0.144 86.999 0.162 ;
     RECT  87.295 1.152 87.395 1.17 ;
     RECT  87.655 52.992 87.755 53.01 ;
     RECT  88.555 52.911 88.591 52.929 ;
     RECT  88.591 52.911 88.727 53.01 ;
     RECT  88.727 52.911 88.907 52.929 ;
     RECT  86.459 2.151 91.291 51.849 ;
     RECT  91.291 2.151 91.391 51.894 ;
     RECT  94.315 52.992 94.415 53.01 ;
     RECT  95.755 0.144 96.251 0.162 ;
     RECT  96.007 52.992 96.683 53.01 ;
     RECT  91.391 2.151 99.787 51.849 ;
     RECT  99.787 2.151 99.887 52.074 ;
     RECT  99.787 0.144 99.959 0.162 ;
     RECT  101.011 52.992 101.903 53.01 ;
     RECT  102.595 0.144 102.695 0.162 ;
     RECT  102.523 53.028 102.811 53.046 ;
     RECT  102.811 52.911 103.127 53.046 ;
     RECT  103.127 53.028 103.423 53.046 ;
     RECT  103.423 53.028 103.595 53.118 ;
     RECT  103.595 53.1 104.243 53.118 ;
     RECT  99.887 2.151 104.323 51.849 ;
     RECT  104.323 2.151 104.747 51.894 ;
     RECT  104.647 52.992 104.783 53.01 ;
     RECT  104.611 0.144 105.035 0.162 ;
     RECT  106.303 52.992 106.475 53.01 ;
     RECT  107.419 0.144 107.735 0.162 ;
     RECT  107.815 1.152 107.951 1.17 ;
     RECT  108.859 52.992 109.823 53.01 ;
     RECT  104.747 2.151 110.983 51.849 ;
     RECT  109.831 0.144 111.155 0.162 ;
     RECT  110.983 2.151 111.371 51.894 ;
     RECT  111.595 52.992 111.695 53.01 ;
     RECT  111.775 1.152 111.875 1.17 ;
     RECT  111.371 2.151 112.495 51.849 ;
     RECT  112.567 0.144 112.667 0.162 ;
     RECT  112.495 2.151 113.747 51.894 ;
     RECT  113.719 52.992 113.819 53.01 ;
     RECT  115.051 1.152 115.151 1.17 ;
     RECT  115.231 52.992 115.511 53.01 ;
     RECT  113.747 2.151 115.843 51.849 ;
     RECT  115.843 2.151 116.131 51.93 ;
     RECT  116.131 2.151 116.267 52.038 ;
     RECT  115.879 0.144 116.411 0.162 ;
     RECT  116.455 52.992 116.807 53.01 ;
     RECT  116.267 2.151 117.031 51.849 ;
     RECT  117.031 2.151 117.967 51.894 ;
     RECT  117.967 2.151 118.751 52.47 ;
     RECT  118.687 0.144 119.111 0.162 ;
     RECT  119.875 0.144 120.155 0.162 ;
     RECT  118.751 2.151 120.155 51.894 ;
     RECT  120.155 2.151 120.991 51.849 ;
     RECT  120.991 2.151 121.379 51.894 ;
     RECT  121.819 1.152 121.919 1.17 ;
     RECT  122.719 0.144 122.819 0.162 ;
     RECT  123.115 1.152 123.251 1.17 ;
     RECT  123.907 0.144 124.007 0.162 ;
     RECT  124.303 1.152 124.403 1.17 ;
     RECT  126.319 0.144 127.247 0.162 ;
     RECT  128.335 0.144 129.227 0.162 ;
     RECT  131.467 0.144 132.683 0.162 ;
     RECT  121.379 2.151 134.779 51.849 ;
     RECT  134.779 1.728 134.915 51.849 ;
     RECT  135.967 0.144 136.067 0.162 ;
     RECT  134.915 2.151 136.399 51.849 ;
     RECT  136.399 1.728 137.075 51.849 ;
     RECT  137.587 0.531 138.739 0.549 ;
     RECT  138.739 0.531 138.811 1.17 ;
     RECT  138.811 0.144 138.839 1.17 ;
     RECT  138.839 0.144 138.983 0.162 ;
     RECT  140.395 0.144 140.603 0.162 ;
     RECT  137.075 2.151 141.619 51.849 ;
     RECT  141.619 1.728 141.863 51.849 ;
     RECT  141.863 2.151 143.239 51.849 ;
     RECT  142.843 0.144 143.375 0.162 ;
     RECT  143.239 1.728 144.023 51.849 ;
     RECT  144.355 0.144 144.455 0.162 ;
     RECT  144.823 1.152 145.139 1.17 ;
     RECT  144.023 2.151 145.651 51.849 ;
     RECT  145.651 1.728 145.859 51.849 ;
     RECT  146.371 0.144 146.471 0.162 ;
     RECT  145.859 2.151 146.839 51.849 ;
     RECT  146.839 1.728 147.739 51.849 ;
     RECT  147.739 1.152 147.839 51.849 ;
     RECT  147.839 1.728 147.875 51.849 ;
     RECT  148.063 0.144 148.163 0.162 ;
     RECT  147.875 2.106 148.243 51.849 ;
     RECT  148.243 2.106 148.631 51.93 ;
     RECT  148.631 2.106 148.855 51.849 ;
     RECT  148.855 1.728 149.315 51.849 ;
     RECT  149.315 2.106 149.963 51.849 ;
     RECT  149.683 0.144 150.179 0.162 ;
     RECT  149.963 2.151 151.267 51.849 ;
     RECT  151.267 1.728 152.123 51.849 ;
     RECT  152.095 0.144 152.195 0.162 ;
     RECT  152.123 2.151 153.139 51.849 ;
     RECT  153.679 53.028 154.139 53.046 ;
     RECT  153.139 2.106 154.507 51.849 ;
     RECT  153.679 0.144 154.895 0.162 ;
     RECT  154.507 1.728 155.435 51.849 ;
     RECT  156.847 0.144 156.947 0.162 ;
     RECT  155.435 2.151 157.315 51.849 ;
     RECT  157.315 1.728 157.631 51.849 ;
     RECT  157.631 2.151 158.503 51.849 ;
     RECT  158.539 52.992 159.359 53.01 ;
     RECT  158.503 1.728 160.043 51.849 ;
     RECT  160.043 2.151 162 51.849 ;
    LAYER M3 ;
     RECT  4.428 0.108 159.75 0.167 ;
     RECT  4.428 0.167 131.886 0.173 ;
     RECT  132.66 0.167 142.434 0.173 ;
     RECT  82.476 0.173 82.89 0.317 ;
     RECT  134.784 0.173 142.434 0.554 ;
     RECT  8.82 0.173 11.286 0.557 ;
     RECT  14.868 0.173 16.902 0.557 ;
     RECT  17.676 0.173 19.71 0.557 ;
     RECT  83.664 0.173 88.11 0.557 ;
     RECT  92.952 0.173 97.362 0.557 ;
     RECT  98.172 0.173 98.982 0.557 ;
     RECT  99.936 0.173 131.886 1.675 ;
     RECT  132.66 0.173 134.01 1.675 ;
     RECT  4.428 0.173 8.046 1.723 ;
     RECT  8.82 0.557 10.062 1.723 ;
     RECT  10.836 0.557 11.286 1.723 ;
     RECT  12.06 0.173 12.078 1.723 ;
     RECT  18.9 0.557 19.71 1.723 ;
     RECT  21.06 0.173 28.17 1.723 ;
     RECT  29.016 0.173 81.702 1.723 ;
     RECT  82.872 0.317 82.89 1.723 ;
     RECT  83.664 0.557 87.714 1.723 ;
     RECT  89.316 0.173 89.73 1.723 ;
     RECT  90.936 0.173 92.142 1.723 ;
     RECT  92.952 0.557 93.762 1.723 ;
     RECT  94.536 0.557 97.362 1.723 ;
     RECT  98.172 0.557 98.19 1.723 ;
     RECT  98.964 0.557 98.982 1.723 ;
     RECT  99.936 1.675 134.01 1.723 ;
     RECT  134.784 0.554 137.214 1.723 ;
     RECT  137.988 0.554 142.434 1.723 ;
     RECT  143.244 0.167 159.75 1.723 ;
     RECT  17.676 0.557 18.126 2.011 ;
     RECT  18.9 1.723 89.802 2.011 ;
     RECT  90.756 1.723 92.142 2.155 ;
     RECT  92.952 1.723 160.038 2.155 ;
     RECT  4.428 1.723 12.078 2.191 ;
     RECT  12.852 0.173 14.094 2.191 ;
     RECT  14.868 0.557 16.11 2.191 ;
     RECT  16.884 0.557 16.902 2.191 ;
     RECT  17.676 2.011 89.802 2.191 ;
     RECT  90.756 2.155 160.038 2.191 ;
     RECT  4.428 2.191 14.094 2.251 ;
     RECT  14.832 2.191 160.29 2.251 ;
     RECT  4.428 2.251 160.29 2.255 ;
     RECT  4.464 2.255 160.29 2.263 ;
     RECT  4.464 2.263 160.362 2.335 ;
     RECT  2.415 2.143 2.505 2.413 ;
     RECT  4.464 2.335 160.722 3.181 ;
     RECT  4.284 3.181 160.722 3.307 ;
     RECT  4.284 3.307 160.866 3.955 ;
     RECT  4.284 3.955 160.938 4.379 ;
     RECT  4.284 4.379 16.758 4.649 ;
     RECT  17.496 4.379 160.938 4.649 ;
     RECT  17.496 4.649 160.902 4.733 ;
     RECT  17.496 4.733 117.342 4.781 ;
     RECT  17.496 4.781 117.306 4.919 ;
     RECT  118.08 4.733 160.902 4.919 ;
     RECT  17.496 4.919 117.09 4.925 ;
     RECT  17.496 4.925 117.054 4.991 ;
     RECT  4.536 4.649 16.758 5.063 ;
     RECT  4.896 5.063 16.758 5.189 ;
     RECT  17.496 4.991 116.298 5.225 ;
     RECT  118.08 4.919 160.578 5.225 ;
     RECT  118.116 5.225 160.578 5.297 ;
     RECT  14.904 5.189 16.758 5.341 ;
     RECT  17.496 5.225 32.598 5.341 ;
     RECT  14.904 5.341 32.598 5.369 ;
     RECT  14.976 5.369 32.598 5.495 ;
     RECT  33.372 5.225 116.298 5.531 ;
     RECT  115.704 5.531 116.298 5.639 ;
     RECT  14.976 5.495 24.498 5.741 ;
     RECT  25.272 5.495 32.598 5.933 ;
     RECT  4.896 5.189 14.166 5.999 ;
     RECT  14.976 5.741 24.354 5.999 ;
     RECT  115.815 5.639 116.298 6.043 ;
     RECT  117.036 4.991 117.054 6.043 ;
     RECT  6.264 5.999 14.166 6.071 ;
     RECT  33.372 5.531 114.966 6.269 ;
     RECT  122.256 5.297 160.578 6.269 ;
     RECT  122.256 6.269 146.934 6.305 ;
     RECT  25.812 5.933 32.598 6.547 ;
     RECT  33.372 6.269 89.097 6.547 ;
     RECT  115.815 6.043 117.054 6.547 ;
     RECT  118.116 5.297 121.497 6.547 ;
     RECT  14.976 5.999 24.297 6.575 ;
     RECT  122.256 6.305 146.898 6.809 ;
     RECT  25.812 6.547 89.097 7.619 ;
     RECT  25.812 7.619 87.678 7.889 ;
     RECT  25.812 7.889 87.642 9.815 ;
     RECT  25.812 9.815 87.282 10.049 ;
     RECT  122.256 6.809 138.69 11.129 ;
     RECT  147.672 6.269 160.578 24.205 ;
     RECT  147.672 24.205 160.758 24.899 ;
     RECT  122.364 11.129 138.69 25.411 ;
     RECT  122.364 25.411 138.798 26.023 ;
     RECT  139.572 6.809 146.898 26.023 ;
     RECT  122.364 26.023 146.898 26.833 ;
     RECT  122.364 26.833 147.078 26.905 ;
     RECT  147.924 24.899 160.758 26.905 ;
     RECT  88.815 7.619 89.097 37.471 ;
     RECT  89.856 6.269 114.966 37.471 ;
     RECT  3.78 37.705 3.798 37.741 ;
     RECT  4.896 5.999 5.454 37.831 ;
     RECT  4.896 37.831 5.706 37.859 ;
     RECT  3.6 37.741 3.798 37.939 ;
     RECT  2.415 2.413 2.697 37.975 ;
     RECT  3.6 37.939 3.834 37.975 ;
     RECT  4.896 37.859 4.914 37.975 ;
     RECT  2.415 37.975 2.79 38.011 ;
     RECT  3.6 37.975 4.914 38.011 ;
     RECT  2.415 38.011 4.914 38.129 ;
     RECT  2.415 38.129 3.834 38.137 ;
     RECT  4.716 38.129 4.914 38.165 ;
     RECT  88.815 37.471 114.966 38.245 ;
     RECT  88.776 38.245 114.966 38.309 ;
     RECT  2.304 38.137 3.834 38.347 ;
     RECT  2.268 38.347 3.834 38.399 ;
     RECT  2.304 38.399 3.834 38.849 ;
     RECT  3.708 38.849 3.798 38.939 ;
     RECT  3.78 38.939 3.798 39.011 ;
     RECT  88.776 38.309 94.497 39.091 ;
     RECT  2.304 38.849 2.697 39.119 ;
     RECT  122.364 26.905 160.758 39.623 ;
     RECT  25.812 10.049 86.994 40.171 ;
     RECT  95.472 38.309 114.966 40.981 ;
     RECT  128.196 39.623 160.758 41.071 ;
     RECT  25.812 40.171 87.318 41.521 ;
     RECT  88.128 39.091 94.497 41.521 ;
     RECT  95.256 40.981 114.966 41.791 ;
     RECT  115.815 6.547 121.497 41.791 ;
     RECT  25.812 41.521 94.497 42.763 ;
     RECT  95.256 41.791 121.497 42.763 ;
     RECT  128.196 41.071 161.334 42.989 ;
     RECT  25.812 42.763 121.497 43.565 ;
     RECT  122.364 39.623 127.458 43.681 ;
     RECT  128.196 42.989 161.226 43.681 ;
     RECT  122.364 43.681 161.226 43.871 ;
     RECT  94.068 43.565 121.497 43.951 ;
     RECT  122.364 43.871 161.082 43.951 ;
     RECT  6.696 6.071 14.166 44.311 ;
     RECT  14.976 6.575 19.458 44.311 ;
     RECT  25.812 43.565 93.33 44.581 ;
     RECT  94.068 43.951 161.082 44.581 ;
     RECT  25.812 44.581 161.082 44.717 ;
     RECT  25.812 44.717 161.01 44.789 ;
     RECT  20.196 6.575 24.297 44.851 ;
     RECT  6.696 44.311 19.458 45.031 ;
     RECT  20.196 44.851 24.642 45.031 ;
     RECT  6.696 45.031 24.642 45.499 ;
     RECT  25.812 44.789 26.73 45.499 ;
     RECT  25.632 45.499 26.73 45.571 ;
     RECT  27.504 44.789 161.01 45.571 ;
     RECT  6.696 45.499 24.678 45.661 ;
     RECT  6.66 45.661 24.678 45.841 ;
     RECT  25.632 45.571 161.01 45.841 ;
     RECT  6.624 45.841 24.678 45.967 ;
     RECT  6.444 45.967 24.678 46.013 ;
     RECT  6.624 46.013 24.678 46.039 ;
     RECT  25.524 45.841 161.01 46.039 ;
     RECT  6.624 46.039 161.01 46.103 ;
     RECT  25.632 46.103 161.01 46.139 ;
     RECT  25.632 46.139 144.09 46.205 ;
     RECT  6.624 46.103 24.858 46.301 ;
     RECT  144.864 46.139 161.01 46.805 ;
     RECT  6.624 46.301 24.822 46.987 ;
     RECT  6.588 46.987 24.822 47.039 ;
     RECT  153.396 46.805 161.01 47.039 ;
     RECT  6.624 47.039 24.822 47.155 ;
     RECT  25.668 46.205 144.09 47.155 ;
     RECT  6.624 47.155 144.09 47.191 ;
     RECT  144.864 46.805 152.406 47.191 ;
     RECT  6.624 47.191 152.406 47.219 ;
     RECT  157.968 47.039 161.01 47.315 ;
     RECT  6.624 47.219 145.026 47.345 ;
     RECT  144.468 47.345 145.026 48.235 ;
     RECT  153.396 47.039 157.23 48.271 ;
     RECT  158.004 47.315 161.01 48.271 ;
     RECT  6.624 47.345 143.262 48.299 ;
     RECT  144.468 48.235 145.062 48.433 ;
     RECT  145.872 47.219 152.406 48.433 ;
     RECT  153.396 48.271 161.01 48.433 ;
     RECT  144.468 48.433 152.406 48.973 ;
     RECT  153.396 48.433 161.046 48.973 ;
     RECT  153.18 48.973 161.046 49.003 ;
     RECT  6.624 48.299 136.386 49.081 ;
     RECT  137.196 48.299 143.262 49.081 ;
     RECT  6.624 49.081 143.262 49.171 ;
     RECT  144.036 48.973 152.406 49.171 ;
     RECT  153.18 49.003 161.262 49.199 ;
     RECT  6.624 49.171 152.406 49.315 ;
     RECT  153.18 49.199 161.118 49.315 ;
     RECT  5.688 37.859 5.706 49.477 ;
     RECT  6.624 49.315 161.118 49.477 ;
     RECT  5.688 49.477 161.118 49.565 ;
     RECT  5.688 49.565 156.582 49.577 ;
     RECT  4.896 38.165 4.914 49.585 ;
     RECT  5.688 49.577 150.966 49.585 ;
     RECT  4.896 49.585 150.966 49.891 ;
     RECT  157.32 49.565 161.118 50.009 ;
     RECT  4.788 49.891 150.966 50.017 ;
     RECT  4.608 50.017 150.966 50.153 ;
     RECT  127.944 50.153 150.966 50.279 ;
     RECT  157.32 50.009 160.794 50.279 ;
     RECT  4.608 50.153 127.134 50.351 ;
     RECT  151.704 49.577 156.582 50.395 ;
     RECT  157.32 50.279 160.578 50.395 ;
     RECT  128.052 50.279 150.966 50.431 ;
     RECT  151.704 50.395 160.578 50.431 ;
     RECT  128.052 50.431 160.578 50.549 ;
     RECT  152.388 50.549 160.578 50.819 ;
     RECT  4.716 50.351 127.134 51.089 ;
     RECT  128.052 50.549 151.578 51.089 ;
     RECT  152.676 50.819 160.578 51.205 ;
     RECT  4.716 51.089 126.897 51.241 ;
     RECT  142.596 51.089 151.578 51.359 ;
     RECT  142.596 51.359 145.962 51.395 ;
     RECT  128.16 51.089 141.858 51.431 ;
     RECT  2.415 39.119 2.697 51.587 ;
     RECT  4.392 51.241 126.897 51.587 ;
     RECT  4.392 51.587 126.774 51.629 ;
     RECT  128.16 51.431 135.558 51.629 ;
     RECT  136.404 51.431 141.318 51.629 ;
     RECT  142.596 51.395 145.35 51.629 ;
     RECT  146.736 51.359 146.754 51.629 ;
     RECT  147.564 51.359 150.534 51.629 ;
     RECT  151.272 51.359 151.434 51.629 ;
     RECT  152.676 51.205 160.866 51.629 ;
     RECT  128.16 51.629 132.105 51.665 ;
     RECT  157.284 51.629 160.758 51.665 ;
     RECT  131.904 51.665 132.105 51.677 ;
     RECT  4.392 51.629 126.705 51.701 ;
     RECT  151.272 51.629 151.29 51.701 ;
     RECT  160.56 51.665 160.578 51.737 ;
     RECT  152.676 51.629 155.898 51.745 ;
     RECT  122.22 51.701 126.705 51.773 ;
     RECT  137.415 51.629 141.318 51.773 ;
     RECT  122.328 51.773 126.705 51.809 ;
     RECT  137.415 51.773 140.706 51.809 ;
     RECT  152.424 51.745 155.898 51.809 ;
     RECT  123.3 51.809 126.705 51.821 ;
     RECT  133.02 51.629 135.558 51.821 ;
     RECT  142.815 51.629 145.35 51.821 ;
     RECT  147.564 51.629 150.462 51.821 ;
     RECT  152.424 51.809 154.926 51.821 ;
     RECT  2.415 51.587 2.505 51.857 ;
     RECT  4.392 51.701 121.374 51.857 ;
     RECT  126.615 51.821 126.705 51.857 ;
     RECT  132.015 51.677 132.105 51.857 ;
     RECT  137.415 51.809 140.382 51.857 ;
     RECT  142.815 51.821 145.242 51.857 ;
     RECT  89.496 51.857 121.374 51.869 ;
     RECT  109.26 51.869 121.374 51.899 ;
     RECT  142.956 51.857 145.242 52.013 ;
     RECT  4.392 51.857 88.722 52.906 ;
     RECT  89.496 51.869 108.27 52.906 ;
     RECT  4.392 52.906 108.27 52.987 ;
     RECT  109.26 51.899 121.014 52.987 ;
     RECT  128.16 51.665 130.698 53.069 ;
     RECT  137.88 51.857 140.382 53.069 ;
     RECT  147.564 51.821 150.066 53.069 ;
     RECT  152.676 51.821 154.926 53.069 ;
     RECT  157.284 51.665 159.786 53.069 ;
     RECT  4.392 52.987 121.014 53.868 ;
     RECT  123.732 51.821 125.838 53.868 ;
     RECT  128.556 53.069 130.698 53.868 ;
     RECT  133.416 51.821 135.558 53.868 ;
     RECT  138.24 53.069 140.382 53.868 ;
     RECT  143.1 52.013 145.242 53.868 ;
     RECT  147.96 53.069 150.066 53.868 ;
     RECT  152.784 53.069 154.926 53.868 ;
     RECT  157.644 53.069 159.786 53.868 ;
     RECT  38.952 53.868 39.042 53.933 ;
     RECT  61.668 53.868 61.758 53.933 ;
    LAYER M4 ;
     RECT  0.156 15.696 0.275 15.72 ;
     RECT  0.156 38.352 2.365 38.376 ;
     RECT  0.229 27.12 2.408 27.144 ;
     RECT  2.365 38.352 2.408 38.712 ;
     RECT  2.408 2.148 2.512 51.852 ;
     RECT  2.512 2.418 2.704 51.582 ;
     RECT  2.704 38.16 3.683 38.712 ;
     RECT  4.501 51.792 4.796 51.816 ;
     RECT  4.796 51.792 5.249 52.488 ;
     RECT  4.777 50.016 5.533 50.04 ;
     RECT  5.533 50.016 5.645 50.376 ;
     RECT  4.273 3.936 5.753 3.96 ;
     RECT  5.249 52.464 6.371 52.488 ;
     RECT  6.433 5.328 6.62 5.352 ;
     RECT  6.217 3.408 6.649 3.432 ;
     RECT  6.565 46.992 6.652 47.592 ;
     RECT  5.645 50.016 6.721 50.04 ;
     RECT  6.649 52.992 6.757 53.016 ;
     RECT  6.757 52.992 6.758 53.064 ;
     RECT  6.721 50.016 6.761 50.712 ;
     RECT  6.652 47.568 6.793 47.592 ;
     RECT  6.649 2.832 6.841 3.432 ;
     RECT  6.761 50.688 6.853 50.712 ;
     RECT  4.597 1.728 6.937 1.752 ;
     RECT  6.841 2.832 6.937 2.904 ;
     RECT  6.937 1.728 7.085 2.904 ;
     RECT  6.853 50.688 7.217 51.336 ;
     RECT  6.62 4.896 7.333 5.352 ;
     RECT  2.704 44.928 7.477 44.952 ;
     RECT  7.333 4.512 7.532 5.352 ;
     RECT  7.477 44.928 7.573 45 ;
     RECT  6.433 45.984 7.573 46.008 ;
     RECT  6.758 53.04 7.619 53.064 ;
     RECT  7.405 0.576 7.669 0.6 ;
     RECT  6.793 47.568 7.729 48.36 ;
     RECT  7.573 44.928 7.801 46.008 ;
     RECT  7.085 2.148 7.808 2.904 ;
     RECT  7.532 4.512 7.808 5.64 ;
     RECT  2.704 27.12 7.808 27.144 ;
     RECT  7.801 44.928 7.808 46.104 ;
     RECT  7.729 47.568 7.808 48.792 ;
     RECT  7.217 50.688 7.808 51.864 ;
     RECT  7.669 0.192 7.859 0.6 ;
     RECT  7.808 2.148 7.861 51.864 ;
     RECT  7.861 2.148 8.104 52.008 ;
     RECT  8.104 50.832 8.149 52.008 ;
     RECT  8.104 2.148 8.197 3.384 ;
     RECT  8.197 1.728 8.293 3.384 ;
     RECT  8.293 1.152 8.332 3.384 ;
     RECT  8.332 1.152 8.387 3.24 ;
     RECT  8.396 0.144 8.483 0.168 ;
     RECT  8.387 1.152 8.483 2.712 ;
     RECT  8.483 1.728 8.819 2.664 ;
     RECT  8.104 4.512 8.915 5.64 ;
     RECT  8.149 50.832 9.385 52.488 ;
     RECT  8.104 44.976 9.404 45 ;
     RECT  8.104 46.08 9.404 46.152 ;
     RECT  9.404 44.976 9.445 46.152 ;
     RECT  9.445 44.448 9.491 46.152 ;
     RECT  9.385 50.736 9.497 52.488 ;
     RECT  8.819 1.728 9.649 2.28 ;
     RECT  9.497 51.312 9.677 52.488 ;
     RECT  9.491 46.128 9.713 46.152 ;
     RECT  8.915 4.512 9.893 5.352 ;
     RECT  9.677 51.792 9.973 52.488 ;
     RECT  9.973 51.792 10.001 53.064 ;
     RECT  10.001 51.888 10.06 53.064 ;
     RECT  8.104 47.184 10.073 49.56 ;
     RECT  9.491 44.448 10.109 45 ;
     RECT  10.073 47.184 10.289 48.552 ;
     RECT  10.213 3.408 10.36 3.432 ;
     RECT  10.36 3.408 10.393 3.48 ;
     RECT  10.385 0.528 10.469 0.552 ;
     RECT  9.649 1.728 10.789 1.752 ;
     RECT  9.893 5.04 10.94 5.352 ;
     RECT  10.789 1.728 10.973 2.232 ;
     RECT  10.94 5.04 10.973 5.4 ;
     RECT  10.109 44.976 10.981 45 ;
     RECT  10.973 5.136 11.027 5.4 ;
     RECT  10.289 47.712 11.084 48.552 ;
     RECT  10.073 49.536 11.084 49.56 ;
     RECT  10.06 51.888 11.113 52.488 ;
     RECT  11.113 51.888 11.149 53.064 ;
     RECT  11.084 47.712 11.153 49.56 ;
     RECT  11.153 47.712 11.171 49.464 ;
     RECT  11.149 51.312 11.333 53.064 ;
     RECT  10.393 3.408 11.441 4.056 ;
     RECT  11.333 53.04 11.555 53.064 ;
     RECT  11.441 3.408 11.845 3.96 ;
     RECT  11.845 2.928 11.941 3.96 ;
     RECT  10.973 1.728 12.121 1.752 ;
     RECT  11.941 2.832 12.121 3.96 ;
     RECT  11.027 5.136 12.236 5.304 ;
     RECT  10.981 44.976 12.277 45.624 ;
     RECT  12.277 44.976 12.445 46.2 ;
     RECT  11.171 47.712 12.445 48.744 ;
     RECT  12.121 1.728 12.469 3.96 ;
     RECT  11.612 0.144 12.515 0.168 ;
     RECT  11.333 51.312 12.709 51.912 ;
     RECT  12.469 1.728 12.805 4.056 ;
     RECT  12.236 5.136 12.805 5.64 ;
     RECT  12.421 50.112 13.021 50.136 ;
     RECT  12.445 44.976 13.093 48.744 ;
     RECT  12.805 1.728 13.208 5.64 ;
     RECT  8.104 27.12 13.208 27.144 ;
     RECT  13.093 44.976 13.208 48.984 ;
     RECT  13.021 50.016 13.208 50.136 ;
     RECT  12.709 51.312 13.208 52.488 ;
     RECT  13.208 1.728 13.504 52.488 ;
     RECT  13.504 46.08 13.565 52.488 ;
     RECT  13.504 3.408 13.667 5.928 ;
     RECT  13.565 51.312 13.673 52.488 ;
     RECT  13.667 3.456 13.715 5.928 ;
     RECT  13.715 3.456 13.781 5.352 ;
     RECT  13.504 44.448 13.817 45.048 ;
     RECT  13.565 46.08 13.853 50.28 ;
     RECT  13.504 1.728 13.997 2.28 ;
     RECT  13.853 46.08 14.14 46.104 ;
     RECT  13.853 47.28 14.213 50.28 ;
     RECT  13.673 51.312 14.284 51.912 ;
     RECT  13.997 2.208 14.485 2.28 ;
     RECT  14.444 0.144 14.531 0.168 ;
     RECT  14.284 51.888 14.579 51.912 ;
     RECT  13.781 3.456 14.641 3.48 ;
     RECT  13.817 44.448 14.797 45 ;
     RECT  14.213 50.16 14.821 50.28 ;
     RECT  14.641 3.408 15.061 3.48 ;
     RECT  14.213 47.28 15.116 48.744 ;
     RECT  15.116 46.656 15.181 48.744 ;
     RECT  15.181 46.656 15.203 49.176 ;
     RECT  13.781 4.56 15.26 5.352 ;
     RECT  14.821 53.04 15.329 53.064 ;
     RECT  15.26 4.56 15.347 5.4 ;
     RECT  15.347 4.56 15.361 5.352 ;
     RECT  14.485 2.208 15.395 2.328 ;
     RECT  15.061 3.408 15.401 3.528 ;
     RECT  15.401 3.408 15.437 3.432 ;
     RECT  15.361 4.512 15.689 5.352 ;
     RECT  15.203 47.28 15.865 49.176 ;
     RECT  14.821 50.16 15.865 50.376 ;
     RECT  15.865 47.28 15.893 50.376 ;
     RECT  15.425 1.728 15.977 1.752 ;
     RECT  15.893 47.28 15.977 50.76 ;
     RECT  14.797 44.976 16.049 45 ;
     RECT  15.977 47.28 16.157 50.184 ;
     RECT  15.689 4.56 16.265 5.352 ;
     RECT  16.157 47.28 16.297 50.04 ;
     RECT  16.265 5.136 16.364 5.352 ;
     RECT  16.364 5.136 16.451 5.4 ;
     RECT  16.297 46.656 16.477 50.04 ;
     RECT  16.433 0.528 16.517 0.552 ;
     RECT  15.461 2.832 16.652 3.336 ;
     RECT  15.445 52.464 16.691 52.488 ;
     RECT  16.652 2.832 16.796 3.432 ;
     RECT  16.297 44.736 17.089 44.76 ;
     RECT  16.933 51.792 17.093 51.816 ;
     RECT  17.228 0.144 17.315 0.168 ;
     RECT  17.089 44.736 17.372 45 ;
     RECT  16.477 45.984 17.372 50.04 ;
     RECT  16.451 5.136 17.42 5.352 ;
     RECT  17.372 44.736 17.459 50.04 ;
     RECT  16.796 2.832 17.461 3.768 ;
     RECT  17.461 2.304 17.557 3.768 ;
     RECT  17.42 5.136 17.593 5.4 ;
     RECT  17.557 2.304 17.893 4.008 ;
     RECT  17.893 1.728 17.993 4.008 ;
     RECT  17.845 53.04 18.065 53.064 ;
     RECT  17.557 51.552 18.133 51.576 ;
     RECT  17.993 2.016 18.205 4.008 ;
     RECT  17.593 5.04 18.205 5.4 ;
     RECT  17.459 45.984 18.313 50.04 ;
     RECT  18.133 51.552 18.313 51.816 ;
     RECT  18.205 2.016 18.325 5.4 ;
     RECT  18.313 45.984 18.421 51.816 ;
     RECT  18.449 0.528 18.533 0.552 ;
     RECT  18.325 2.016 18.608 5.832 ;
     RECT  13.504 27.12 18.608 27.144 ;
     RECT  17.459 44.736 18.608 45 ;
     RECT  18.421 45.984 18.608 51.96 ;
     RECT  18.608 2.016 18.803 51.96 ;
     RECT  18.803 2.016 18.904 51.912 ;
     RECT  18.904 45.024 19.181 51.912 ;
     RECT  19.181 47.376 19.361 51.912 ;
     RECT  18.904 2.832 19.405 6.264 ;
     RECT  19.361 51.312 19.468 51.912 ;
     RECT  19.405 2.832 19.715 5.736 ;
     RECT  19.715 2.832 19.721 3.432 ;
     RECT  19.715 4.512 19.804 5.736 ;
     RECT  19.361 47.376 19.829 50.04 ;
     RECT  19.468 51.312 19.865 51.336 ;
     RECT  19.829 47.376 20.189 49.272 ;
     RECT  19.181 45.024 20.473 46.008 ;
     RECT  19.804 4.56 20.492 5.736 ;
     RECT  20.492 4.56 20.579 5.928 ;
     RECT  19.721 3.312 20.684 3.432 ;
     RECT  20.189 47.664 20.729 49.272 ;
     RECT  20.684 3.216 20.905 3.432 ;
     RECT  20.579 4.56 20.905 5.64 ;
     RECT  20.905 3.216 20.917 5.64 ;
     RECT  20.729 47.856 20.917 49.272 ;
     RECT  20.06 0.144 20.963 0.168 ;
     RECT  20.917 2.88 20.963 5.64 ;
     RECT  20.473 45.024 20.977 46.584 ;
     RECT  21.049 0.192 21.155 0.216 ;
     RECT  19.957 52.464 21.185 52.488 ;
     RECT  21.185 52.464 21.539 53.016 ;
     RECT  21.539 52.992 21.769 53.016 ;
     RECT  20.963 2.88 21.941 5.352 ;
     RECT  21.941 2.832 22.021 5.352 ;
     RECT  20.977 44.976 22.057 46.584 ;
     RECT  20.917 47.856 22.057 50.088 ;
     RECT  22.021 2.832 22.105 5.688 ;
     RECT  21.769 52.992 22.115 53.112 ;
     RECT  22.105 2.832 22.252 5.352 ;
     RECT  22.115 52.992 22.637 53.016 ;
     RECT  22.252 2.832 22.787 2.856 ;
     RECT  22.693 51.792 22.949 51.816 ;
     RECT  22.252 3.984 22.997 5.352 ;
     RECT  22.949 51.792 23.033 51.864 ;
     RECT  22.997 4.656 23.101 5.352 ;
     RECT  23.033 51.792 23.276 51.816 ;
     RECT  22.057 44.976 23.756 50.088 ;
     RECT  23.276 51.552 23.756 51.816 ;
     RECT  23.101 4.656 23.893 5.64 ;
     RECT  19.093 1.728 24.008 1.752 ;
     RECT  23.852 3.024 24.008 3.048 ;
     RECT  23.893 4.656 24.008 6.024 ;
     RECT  18.904 27.12 24.008 27.144 ;
     RECT  23.756 44.976 24.008 51.816 ;
     RECT  24.008 1.728 24.229 51.852 ;
     RECT  24.229 1.728 24.304 52.488 ;
     RECT  24.304 51.84 24.365 52.488 ;
     RECT  24.304 1.728 24.473 5.928 ;
     RECT  24.365 51.84 24.653 51.864 ;
     RECT  24.473 2.784 24.797 5.928 ;
     RECT  24.797 2.784 24.851 2.904 ;
     RECT  24.473 1.728 24.865 1.752 ;
     RECT  24.851 2.784 25.043 2.856 ;
     RECT  24.797 3.984 25.157 5.928 ;
     RECT  24.865 1.68 25.187 1.752 ;
     RECT  25.157 4.56 25.229 5.928 ;
     RECT  24.304 47.088 25.285 50.088 ;
     RECT  25.229 4.656 25.331 5.928 ;
     RECT  24.304 45.504 25.621 45.528 ;
     RECT  25.285 46.848 25.621 50.088 ;
     RECT  25.621 45.504 25.661 50.088 ;
     RECT  24.805 52.992 25.717 53.016 ;
     RECT  25.661 45.552 25.793 50.088 ;
     RECT  25.793 45.552 25.877 50.184 ;
     RECT  25.909 2.88 26.345 2.904 ;
     RECT  25.717 52.464 26.387 53.016 ;
     RECT  26.387 52.992 26.963 53.016 ;
     RECT  25.331 4.656 27.133 5.352 ;
     RECT  25.877 45.552 27.133 49.896 ;
     RECT  27.133 45.552 27.299 50.088 ;
     RECT  26.621 51.84 27.317 51.864 ;
     RECT  27.299 46.176 27.461 50.088 ;
     RECT  27.529 52.416 27.613 52.44 ;
     RECT  27.829 51.312 27.929 51.336 ;
     RECT  27.781 0.192 27.971 0.216 ;
     RECT  27.461 46.176 28.321 49.656 ;
     RECT  27.133 3.696 28.529 5.352 ;
     RECT  28.508 0.144 28.595 0.168 ;
     RECT  28.453 51.552 28.741 51.576 ;
     RECT  28.741 51.552 29.077 51.768 ;
     RECT  28.165 53.04 29.077 53.064 ;
     RECT  28.529 3.408 29.269 5.352 ;
     RECT  25.187 1.728 29.408 1.752 ;
     RECT  29.269 3.408 29.408 5.496 ;
     RECT  24.304 27.12 29.408 27.144 ;
     RECT  28.861 43.344 29.408 43.368 ;
     RECT  28.321 45.456 29.408 49.656 ;
     RECT  29.077 51.552 29.408 53.064 ;
     RECT  29.408 1.728 29.411 53.064 ;
     RECT  29.411 1.728 29.704 53.016 ;
     RECT  29.704 43.344 30.341 53.016 ;
     RECT  30.341 43.344 30.515 52.44 ;
     RECT  29.704 3.936 30.557 5.256 ;
     RECT  30.515 46.32 30.803 52.44 ;
     RECT  30.515 43.344 30.809 45.288 ;
     RECT  30.803 46.32 30.845 49.08 ;
     RECT  30.757 0.192 30.899 0.216 ;
     RECT  30.803 50.4 30.899 52.44 ;
     RECT  30.809 43.344 31.133 45.24 ;
     RECT  30.899 50.4 31.169 51.384 ;
     RECT  31.133 43.584 31.205 45.24 ;
     RECT  30.899 52.416 31.241 52.44 ;
     RECT  30.557 4.896 31.313 5.256 ;
     RECT  31.169 51.312 31.385 51.384 ;
     RECT  31.205 43.584 31.637 43.8 ;
     RECT  31.477 52.944 31.705 52.968 ;
     RECT  31.705 52.944 31.709 53.064 ;
     RECT  30.845 46.32 31.813 46.92 ;
     RECT  30.845 48 31.813 49.08 ;
     RECT  31.813 46.32 31.885 49.08 ;
     RECT  31.709 53.04 32.147 53.064 ;
     RECT  31.637 43.776 32.173 43.8 ;
     RECT  31.205 44.88 32.173 45.24 ;
     RECT  32.173 43.776 32.285 45.24 ;
     RECT  31.313 4.896 32.389 5.208 ;
     RECT  29.704 1.728 32.641 1.752 ;
     RECT  31.885 46.32 32.641 49.608 ;
     RECT  31.385 51.312 32.669 51.336 ;
     RECT  32.669 51.312 32.753 51.864 ;
     RECT  32.641 1.728 32.819 2.28 ;
     RECT  32.285 44.64 32.857 45.24 ;
     RECT  32.641 46.32 32.857 49.896 ;
     RECT  32.857 44.64 33.221 49.896 ;
     RECT  32.677 3.36 33.613 3.384 ;
     RECT  32.389 4.896 33.613 5.544 ;
     RECT  33.221 44.64 33.685 45.24 ;
     RECT  32.753 51.312 33.689 51.768 ;
     RECT  33.221 46.224 33.772 49.752 ;
     RECT  33.973 53.04 34.259 53.064 ;
     RECT  33.685 44.16 34.549 45.24 ;
     RECT  33.772 46.224 34.549 49.56 ;
     RECT  34.549 44.16 34.621 49.56 ;
     RECT  32.819 1.728 34.789 1.752 ;
     RECT  34.789 1.728 34.808 1.8 ;
     RECT  33.613 3.36 34.808 5.544 ;
     RECT  29.704 27.12 34.808 27.144 ;
     RECT  34.621 43.584 34.808 49.56 ;
     RECT  33.689 51.312 34.808 51.336 ;
     RECT  34.441 52.464 34.808 52.488 ;
     RECT  34.808 1.728 35.104 52.488 ;
     RECT  35.104 43.536 35.165 46.296 ;
     RECT  35.104 1.728 35.201 1.8 ;
     RECT  35.104 2.784 35.201 3.336 ;
     RECT  35.104 4.512 35.219 5.544 ;
     RECT  35.201 3.312 35.993 3.336 ;
     RECT  35.104 49.536 36.161 49.56 ;
     RECT  35.219 4.704 36.205 5.544 ;
     RECT  35.104 51.312 36.226 51.336 ;
     RECT  35.201 1.728 36.313 1.752 ;
     RECT  35.165 43.536 36.317 46.104 ;
     RECT  36.226 51.312 36.371 51.384 ;
     RECT  36.313 1.728 36.419 2.28 ;
     RECT  35.104 47.52 36.457 47.736 ;
     RECT  36.317 43.68 36.469 46.104 ;
     RECT  36.457 47.52 36.469 47.928 ;
     RECT  36.469 43.68 36.515 47.928 ;
     RECT  36.161 49.536 36.673 50.136 ;
     RECT  36.515 47.856 36.745 47.928 ;
     RECT  36.515 43.68 36.857 46.872 ;
     RECT  35.104 52.464 36.857 52.488 ;
     RECT  36.673 49.536 37.001 50.472 ;
     RECT  36.745 47.856 37.321 48.552 ;
     RECT  37.001 49.536 37.321 49.608 ;
     RECT  36.857 44.16 37.501 46.872 ;
     RECT  37.321 47.856 37.501 49.608 ;
     RECT  37.465 53.04 37.571 53.064 ;
     RECT  37.501 44.16 37.667 49.608 ;
     RECT  37.237 51.552 37.861 51.576 ;
     RECT  37.667 44.16 38.005 49.032 ;
     RECT  37.753 15.984 38.101 16.008 ;
     RECT  38.005 43.872 38.101 49.032 ;
     RECT  36.205 3.696 38.113 5.544 ;
     RECT  37.861 51.312 38.149 51.576 ;
     RECT  38.101 15.984 38.188 16.2 ;
     RECT  38.101 43.248 38.333 49.032 ;
     RECT  38.333 48.288 38.369 49.032 ;
     RECT  38.333 43.248 38.621 47.304 ;
     RECT  38.149 51.312 38.771 51.864 ;
     RECT  38.725 0.192 38.867 0.216 ;
     RECT  38.369 48.912 38.909 49.032 ;
     RECT  38.771 51.84 39.02 51.864 ;
     RECT  38.113 3.456 39.197 5.544 ;
     RECT  38.909 48.912 39.841 48.936 ;
     RECT  38.621 43.248 39.949 43.272 ;
     RECT  38.621 44.448 39.949 47.304 ;
     RECT  39.841 48.48 39.949 48.936 ;
     RECT  36.419 1.728 40.208 1.752 ;
     RECT  39.197 3.84 40.208 5.544 ;
     RECT  38.188 15.984 40.208 16.008 ;
     RECT  35.104 27.12 40.208 27.144 ;
     RECT  39.949 43.248 40.208 48.936 ;
     RECT  39.02 51.84 40.208 52.488 ;
     RECT  40.208 1.728 40.504 52.488 ;
     RECT  40.504 51.744 40.597 52.488 ;
     RECT  40.504 43.248 40.601 48.648 ;
     RECT  40.601 43.248 40.853 43.896 ;
     RECT  40.504 4.128 41.213 5.544 ;
     RECT  40.601 44.976 41.315 48.648 ;
     RECT  40.597 51.744 41.393 53.064 ;
     RECT  40.504 49.68 41.569 49.704 ;
     RECT  41.315 44.976 41.713 48.504 ;
     RECT  41.569 49.68 41.857 50.328 ;
     RECT  41.393 51.744 41.857 51.912 ;
     RECT  41.857 49.68 41.969 51.912 ;
     RECT  40.504 1.728 42.113 1.752 ;
     RECT  41.713 44.928 42.332 48.504 ;
     RECT  41.969 49.68 42.332 51.816 ;
     RECT  42.145 1.104 42.467 1.128 ;
     RECT  42.332 44.928 42.649 51.816 ;
     RECT  42.649 44.448 42.685 51.816 ;
     RECT  40.853 43.248 42.709 43.272 ;
     RECT  42.685 44.304 42.709 51.816 ;
     RECT  41.213 4.416 42.761 5.544 ;
     RECT  42.709 43.248 42.761 51.816 ;
     RECT  42.721 0.192 42.851 0.216 ;
     RECT  42.761 43.248 43.337 51.576 ;
     RECT  42.397 3.312 43.477 3.336 ;
     RECT  43.337 43.248 43.589 51.384 ;
     RECT  41.393 53.04 43.661 53.064 ;
     RECT  42.761 4.656 43.729 5.544 ;
     RECT  43.477 3.312 43.801 3.384 ;
     RECT  43.729 4.464 43.801 5.544 ;
     RECT  43.589 43.248 44.345 51.336 ;
     RECT  43.189 1.728 44.437 1.752 ;
     RECT  44.485 52.464 44.921 52.488 ;
     RECT  44.437 1.728 45.169 1.8 ;
     RECT  44.345 43.248 45.385 50.904 ;
     RECT  45.169 1.728 45.608 2.28 ;
     RECT  43.801 3.312 45.608 5.544 ;
     RECT  40.504 15.984 45.608 16.008 ;
     RECT  40.504 27.12 45.608 27.144 ;
     RECT  45.385 43.248 45.608 51.384 ;
     RECT  45.608 1.728 45.712 51.852 ;
     RECT  45.712 1.728 45.904 51.582 ;
     RECT  45.313 52.944 46.019 53.064 ;
     RECT  45.904 43.344 46.757 51.576 ;
     RECT  46.019 53.04 47.267 53.064 ;
     RECT  46.757 43.344 47.297 50.664 ;
     RECT  47.297 50.64 47.837 50.664 ;
     RECT  47.509 51.84 47.917 51.864 ;
     RECT  47.297 43.344 48.301 49.224 ;
     RECT  48.133 51.888 48.305 51.912 ;
     RECT  48.301 42.72 48.38 49.224 ;
     RECT  45.904 3.6 48.419 5.544 ;
     RECT  48.419 3.888 48.449 5.544 ;
     RECT  48.38 42.72 48.625 49.56 ;
     RECT  48.625 42.288 48.755 49.56 ;
     RECT  48.449 3.888 48.917 4.44 ;
     RECT  48.755 44.16 49.265 49.56 ;
     RECT  49.045 50.688 49.265 50.712 ;
     RECT  49.265 44.16 49.333 50.712 ;
     RECT  49.333 44.16 49.565 51.336 ;
     RECT  49.237 52.512 49.669 52.536 ;
     RECT  49.669 52.464 49.817 52.536 ;
     RECT  49.817 52.512 49.916 52.536 ;
     RECT  48.917 3.984 50.029 4.44 ;
     RECT  49.565 44.16 50.029 50.76 ;
     RECT  50.029 3.552 50.245 4.44 ;
     RECT  48.449 5.52 50.245 5.544 ;
     RECT  48.755 42.288 50.317 43.128 ;
     RECT  50.029 44.112 50.713 50.76 ;
     RECT  45.904 1.728 50.821 1.752 ;
     RECT  49.916 52.512 50.821 53.064 ;
     RECT  50.821 52.464 50.915 53.064 ;
     RECT  50.317 42.144 51.001 43.128 ;
     RECT  50.713 44.112 51.001 50.952 ;
     RECT  50.821 1.728 51.008 2.04 ;
     RECT  50.245 3.552 51.008 5.544 ;
     RECT  45.904 15.984 51.008 16.008 ;
     RECT  45.904 27.12 51.008 27.144 ;
     RECT  50.137 30.384 51.008 30.408 ;
     RECT  51.001 42.144 51.008 50.952 ;
     RECT  51.008 1.728 51.112 51.852 ;
     RECT  51.112 1.728 51.304 51.582 ;
     RECT  51.304 15.984 51.443 16.008 ;
     RECT  51.304 19.392 51.731 19.512 ;
     RECT  51.304 30.384 51.731 30.6 ;
     RECT  51.304 48.24 51.868 51.432 ;
     RECT  51.304 42.192 52.013 47.064 ;
     RECT  51.868 48.24 52.049 51.336 ;
     RECT  50.915 53.04 52.193 53.064 ;
     RECT  52.013 45.792 52.265 47.064 ;
     RECT  52.049 48.24 52.265 49.512 ;
     RECT  52.265 45.936 52.297 47.064 ;
     RECT  51.304 4.704 52.369 5.544 ;
     RECT  51.304 1.728 52.46 1.752 ;
     RECT  52.46 1.728 52.547 2.28 ;
     RECT  52.297 45.936 52.621 47.208 ;
     RECT  52.265 48.24 52.621 49.464 ;
     RECT  52.693 52.464 52.877 52.488 ;
     RECT  52.369 4.656 53.017 5.544 ;
     RECT  52.049 50.592 53.029 51.336 ;
     RECT  53.029 50.544 53.269 51.336 ;
     RECT  53.017 4.56 53.341 5.544 ;
     RECT  52.013 42.192 53.341 44.616 ;
     RECT  52.621 45.936 53.341 49.464 ;
     RECT  53.341 42.192 53.405 49.464 ;
     RECT  53.269 50.544 53.405 51.816 ;
     RECT  53.405 42.192 53.597 51.816 ;
     RECT  52.547 1.728 54.025 1.752 ;
     RECT  54.025 1.728 54.131 1.992 ;
     RECT  53.341 4.512 54.421 5.544 ;
     RECT  53.597 42.192 54.805 51.336 ;
     RECT  54.805 42.192 54.892 51.912 ;
     RECT  54.892 42.192 55.141 51.336 ;
     RECT  54.131 1.728 55.177 1.752 ;
     RECT  55.177 1.104 55.331 1.752 ;
     RECT  54.637 53.04 56.051 53.064 ;
     RECT  54.421 3.552 56.185 5.544 ;
     RECT  55.141 42.144 56.185 51.336 ;
     RECT  56.185 42 56.197 51.336 ;
     RECT  56.197 42 56.257 51.48 ;
     RECT  55.331 1.728 56.329 1.752 ;
     RECT  56.185 3.408 56.401 5.544 ;
     RECT  56.329 1.152 56.408 1.752 ;
     RECT  56.401 3.36 56.408 5.544 ;
     RECT  51.731 19.488 56.408 19.512 ;
     RECT  51.304 27.12 56.408 27.144 ;
     RECT  51.731 30.384 56.408 30.408 ;
     RECT  56.257 41.136 56.408 51.48 ;
     RECT  56.408 1.152 56.531 51.852 ;
     RECT  56.531 1.728 56.629 51.852 ;
     RECT  56.629 1.728 56.704 51.96 ;
     RECT  56.704 41.136 56.801 51.96 ;
     RECT  56.801 41.136 56.909 50.328 ;
     RECT  56.704 3.36 57.251 5.544 ;
     RECT  56.909 41.136 57.347 42.792 ;
     RECT  56.801 51.312 57.347 51.96 ;
     RECT  56.704 1.728 57.781 1.752 ;
     RECT  56.909 43.824 57.781 50.328 ;
     RECT  57.409 52.464 57.875 52.488 ;
     RECT  57.781 50.16 57.913 50.328 ;
     RECT  57.347 51.312 57.913 51.336 ;
     RECT  57.347 41.904 58.117 42.792 ;
     RECT  57.781 43.824 58.117 48.84 ;
     RECT  58.057 0.192 58.163 0.216 ;
     RECT  58.117 41.904 58.163 48.84 ;
     RECT  58.163 41.904 58.169 48.6 ;
     RECT  57.251 3.408 58.501 5.544 ;
     RECT  57.913 50.16 58.705 51.336 ;
     RECT  58.705 50.16 58.789 51.912 ;
     RECT  58.789 50.16 58.921 51.816 ;
     RECT  58.921 50.112 59.075 51.816 ;
     RECT  59.075 50.112 59.077 50.328 ;
     RECT  58.501 2.88 59.393 5.544 ;
     RECT  59.497 53.04 59.581 53.064 ;
     RECT  59.393 3.312 59.717 5.544 ;
     RECT  58.169 42 59.821 48.6 ;
     RECT  59.077 49.584 59.821 50.328 ;
     RECT  59.821 42 59.861 50.328 ;
     RECT  59.075 51.312 59.941 51.816 ;
     RECT  59.941 51.312 60.077 51.912 ;
     RECT  59.861 42.432 60.229 50.328 ;
     RECT  60.077 51.312 60.229 51.432 ;
     RECT  58.933 1.728 60.995 1.752 ;
     RECT  59.717 3.744 61.333 5.544 ;
     RECT  61.333 2.88 61.429 5.544 ;
     RECT  61.429 2.784 61.621 5.544 ;
     RECT  56.704 19.488 61.649 19.512 ;
     RECT  61.141 53.04 61.667 53.064 ;
     RECT  60.229 42.432 61.669 51.432 ;
     RECT  61.669 42.432 61.765 51.672 ;
     RECT  61.621 1.968 61.808 5.544 ;
     RECT  61.649 19.488 61.808 19.944 ;
     RECT  56.704 27.12 61.808 27.144 ;
     RECT  56.704 30.384 61.808 30.408 ;
     RECT  61.765 42.432 61.808 52.008 ;
     RECT  61.808 1.968 61.909 52.008 ;
     RECT  61.909 1.968 62.099 52.92 ;
     RECT  62.099 1.968 62.104 51.864 ;
     RECT  62.104 1.968 62.149 5.544 ;
     RECT  62.099 52.896 62.273 52.92 ;
     RECT  62.104 41.76 62.453 51.864 ;
     RECT  62.149 1.728 62.777 5.544 ;
     RECT  62.453 41.76 62.812 51.576 ;
     RECT  62.677 53.76 62.819 53.784 ;
     RECT  62.812 42.336 63.245 51.576 ;
     RECT  62.777 1.728 63.251 2.28 ;
     RECT  63.245 42.528 63.317 51.576 ;
     RECT  63.251 1.728 63.491 2.232 ;
     RECT  62.777 3.552 63.497 5.544 ;
     RECT  63.317 49.104 63.589 51.576 ;
     RECT  63.589 49.104 63.857 51.816 ;
     RECT  63.317 42.528 64.145 47.928 ;
     RECT  64.145 42.528 64.321 45.672 ;
     RECT  64.321 42.192 64.405 45.672 ;
     RECT  63.857 49.104 64.609 50.712 ;
     RECT  63.491 1.728 64.645 1.752 ;
     RECT  64.501 52.464 64.748 52.488 ;
     RECT  64.145 46.752 64.825 47.928 ;
     RECT  64.609 48.96 64.825 50.712 ;
     RECT  64.825 46.752 64.853 50.712 ;
     RECT  64.853 46.752 64.883 51.336 ;
     RECT  63.497 3.792 64.933 5.544 ;
     RECT  64.883 46.752 64.979 49.56 ;
     RECT  64.748 52.464 65.075 53.064 ;
     RECT  65.075 52.896 65.297 53.064 ;
     RECT  64.933 3.408 65.372 5.544 ;
     RECT  64.883 50.544 65.413 51.336 ;
     RECT  64.981 41.04 65.437 41.064 ;
     RECT  64.405 42.144 65.437 45.672 ;
     RECT  65.372 3.312 65.459 5.544 ;
     RECT  65.437 41.04 65.545 45.672 ;
     RECT  64.979 46.752 65.545 49.176 ;
     RECT  65.413 50.544 65.549 51.816 ;
     RECT  65.545 41.04 65.617 49.176 ;
     RECT  65.297 53.04 65.801 53.064 ;
     RECT  65.617 40.992 66.037 49.176 ;
     RECT  65.549 50.544 66.037 51.384 ;
     RECT  66.037 40.992 66.083 51.384 ;
     RECT  66.325 52.992 66.593 53.016 ;
     RECT  66.083 41.136 66.901 51.384 ;
     RECT  66.901 41.136 67.165 51.816 ;
     RECT  64.645 1.728 67.208 2.28 ;
     RECT  65.459 3.408 67.208 5.544 ;
     RECT  62.104 27.12 67.208 27.144 ;
     RECT  62.104 30.384 67.208 30.408 ;
     RECT  67.165 41.136 67.208 52.008 ;
     RECT  67.208 1.728 67.283 52.008 ;
     RECT  67.283 1.728 67.312 51.852 ;
     RECT  67.312 1.728 67.504 51.582 ;
     RECT  67.504 1.728 67.811 2.28 ;
     RECT  67.525 52.944 67.811 52.968 ;
     RECT  67.504 41.136 67.853 51.582 ;
     RECT  67.853 41.136 67.961 48.936 ;
     RECT  67.853 50.112 68.437 51.582 ;
     RECT  67.961 41.136 68.465 47.256 ;
     RECT  68.465 41.328 68.501 47.256 ;
     RECT  67.504 3.408 68.609 5.544 ;
     RECT  68.437 50.112 68.717 51.912 ;
     RECT  67.961 48.432 68.917 48.936 ;
     RECT  68.717 50.112 68.917 51.864 ;
     RECT  68.501 41.472 69.073 47.256 ;
     RECT  68.917 48.432 69.121 51.864 ;
     RECT  69.073 41.472 69.293 47.448 ;
     RECT  69.293 42.192 69.443 47.448 ;
     RECT  67.813 53.04 69.473 53.064 ;
     RECT  69.121 48.432 69.577 49.56 ;
     RECT  69.493 40.992 69.581 41.064 ;
     RECT  69.577 48.384 69.761 49.56 ;
     RECT  69.761 49.536 70.121 49.56 ;
     RECT  70.009 0.192 70.211 0.216 ;
     RECT  68.609 4.512 70.297 5.544 ;
     RECT  69.581 41.04 70.337 41.064 ;
     RECT  69.443 42.192 70.441 47.208 ;
     RECT  68.609 3.408 70.477 3.432 ;
     RECT  70.297 4.416 70.477 5.544 ;
     RECT  70.477 3.408 70.517 5.544 ;
     RECT  69.121 50.544 70.553 51.864 ;
     RECT  70.441 41.76 70.585 47.208 ;
     RECT  70.585 41.76 70.621 47.304 ;
     RECT  69.761 48.384 70.621 48.408 ;
     RECT  70.517 3.744 70.643 5.544 ;
     RECT  70.621 41.76 70.787 48.408 ;
     RECT  70.787 42.144 70.805 48.408 ;
     RECT  70.805 48.336 70.844 48.408 ;
     RECT  70.873 50.16 71.197 50.28 ;
     RECT  70.553 51.312 71.237 51.864 ;
     RECT  70.844 48.336 71.377 48.84 ;
     RECT  71.197 50.112 71.377 50.28 ;
     RECT  70.643 4.416 71.381 5.544 ;
     RECT  70.805 42.144 71.381 47.352 ;
     RECT  71.381 42.144 71.605 46.776 ;
     RECT  71.377 48.336 71.881 50.28 ;
     RECT  71.237 51.312 71.881 51.528 ;
     RECT  71.881 48.336 71.953 51.528 ;
     RECT  67.811 1.728 72.469 1.752 ;
     RECT  72.469 1.728 72.565 1.8 ;
     RECT  71.605 42.192 72.601 46.776 ;
     RECT  72.565 1.728 72.608 1.992 ;
     RECT  72.469 3.36 72.608 3.384 ;
     RECT  71.381 4.512 72.608 5.544 ;
     RECT  67.504 27.12 72.608 27.144 ;
     RECT  67.504 30.384 72.608 30.408 ;
     RECT  72.601 42.192 72.608 46.824 ;
     RECT  71.953 47.952 72.608 51.528 ;
     RECT  72.608 1.728 72.661 51.852 ;
     RECT  72.661 1.728 72.904 52.008 ;
     RECT  72.904 3.36 72.965 5.544 ;
     RECT  72.904 41.616 72.965 52.008 ;
     RECT  72.965 48.384 73.001 52.008 ;
     RECT  73.001 51.648 73.109 52.008 ;
     RECT  73.001 48.384 73.145 50.616 ;
     RECT  73.109 51.84 73.573 52.008 ;
     RECT  72.949 52.992 73.573 53.016 ;
     RECT  73.145 48.384 73.657 50.424 ;
     RECT  73.573 51.84 73.721 53.016 ;
     RECT  73.721 52.416 73.829 53.016 ;
     RECT  72.965 41.616 74.005 47.304 ;
     RECT  74.005 41.616 74.293 47.352 ;
     RECT  73.657 48.384 74.293 49.08 ;
     RECT  73.657 50.4 74.485 50.424 ;
     RECT  73.829 52.992 74.585 53.016 ;
     RECT  74.293 41.616 74.873 49.08 ;
     RECT  74.873 42.816 74.977 49.08 ;
     RECT  74.485 50.4 74.977 50.712 ;
     RECT  72.965 3.984 74.981 5.544 ;
     RECT  74.977 42.816 75.109 50.712 ;
     RECT  74.981 4.512 75.205 5.544 ;
     RECT  75.109 42.816 75.233 51.336 ;
     RECT  75.233 42.816 75.493 50.664 ;
     RECT  75.493 42.816 75.841 50.136 ;
     RECT  75.769 0.192 75.875 0.216 ;
     RECT  75.205 4.512 75.949 6.072 ;
     RECT  74.873 41.616 76.061 41.64 ;
     RECT  75.841 42.72 76.115 50.136 ;
     RECT  75.653 51.84 76.597 51.864 ;
     RECT  76.115 42.72 76.633 49.56 ;
     RECT  76.633 41.952 76.643 49.56 ;
     RECT  76.643 45.984 76.673 49.56 ;
     RECT  76.597 51.792 76.813 51.864 ;
     RECT  76.741 50.736 76.835 50.76 ;
     RECT  76.813 51.792 76.931 52.488 ;
     RECT  75.949 3.696 77.173 6.072 ;
     RECT  76.931 51.792 77.221 51.816 ;
     RECT  76.643 41.952 77.509 45 ;
     RECT  76.673 49.44 77.509 49.56 ;
     RECT  77.509 41.472 77.605 45 ;
     RECT  76.673 45.984 77.605 48.456 ;
     RECT  77.605 41.472 77.749 48.456 ;
     RECT  77.509 49.44 77.749 50.328 ;
     RECT  72.904 1.728 77.804 1.752 ;
     RECT  77.677 53.04 77.891 53.064 ;
     RECT  77.804 1.728 78.008 2.28 ;
     RECT  77.173 3.312 78.008 6.072 ;
     RECT  72.904 27.12 78.008 27.144 ;
     RECT  72.904 30.384 78.008 30.408 ;
     RECT  77.749 41.472 78.008 50.328 ;
     RECT  77.221 51.312 78.008 51.816 ;
     RECT  78.008 1.728 78.304 51.852 ;
     RECT  78.304 42.48 78.653 50.808 ;
     RECT  78.304 1.728 78.659 2.28 ;
     RECT  78.653 42.48 78.689 48.936 ;
     RECT  78.653 50.064 78.707 50.808 ;
     RECT  78.133 52.992 78.709 53.016 ;
     RECT  78.689 46.752 78.733 48.456 ;
     RECT  78.733 46.752 78.833 48.216 ;
     RECT  78.709 52.896 78.905 53.016 ;
     RECT  78.304 51.84 79.037 51.852 ;
     RECT  78.304 3.312 79.265 6.072 ;
     RECT  79.265 4.656 79.405 6.072 ;
     RECT  78.905 52.992 79.409 53.016 ;
     RECT  79.405 4.656 79.445 6.552 ;
     RECT  78.707 50.064 79.793 50.568 ;
     RECT  79.793 49.776 79.813 50.568 ;
     RECT  78.689 42.48 79.909 45.624 ;
     RECT  78.833 46.752 79.909 47.88 ;
     RECT  79.909 42.48 79.949 47.88 ;
     RECT  79.037 51.84 79.957 51.864 ;
     RECT  79.949 46.08 79.981 47.88 ;
     RECT  79.813 49.008 79.981 50.568 ;
     RECT  79.957 51.84 80.057 51.912 ;
     RECT  79.445 4.656 80.341 5.544 ;
     RECT  80.341 3.936 80.425 5.544 ;
     RECT  80.425 4.656 80.453 5.544 ;
     RECT  79.949 42.48 80.54 44.472 ;
     RECT  80.54 42.144 80.627 44.472 ;
     RECT  79.981 46.08 80.633 50.568 ;
     RECT  80.453 5.088 80.889 5.544 ;
     RECT  79.445 6.528 80.889 6.552 ;
     RECT  80.633 46.416 80.917 50.568 ;
     RECT  80.533 51.552 80.917 51.816 ;
     RECT  80.889 5.088 80.963 6.552 ;
     RECT  80.627 42.816 81.065 44.472 ;
     RECT  80.917 46.416 81.157 51.816 ;
     RECT  80.963 5.136 81.203 6.552 ;
     RECT  81.065 44.256 81.245 44.472 ;
     RECT  81.157 46.416 81.353 51.864 ;
     RECT  78.659 1.728 81.385 1.752 ;
     RECT  81.205 2.832 81.385 2.856 ;
     RECT  81.245 44.4 81.421 44.472 ;
     RECT  81.385 1.728 81.491 2.856 ;
     RECT  81.353 51.264 81.532 51.864 ;
     RECT  81.491 2.832 81.605 2.856 ;
     RECT  81.353 46.416 81.889 50.136 ;
     RECT  81.532 51.264 81.965 51.624 ;
     RECT  81.889 46.176 81.997 50.136 ;
     RECT  81.203 5.136 82.069 5.544 ;
     RECT  82.028 0.144 82.115 0.168 ;
     RECT  81.421 44.4 82.141 44.664 ;
     RECT  81.997 45.936 82.141 50.136 ;
     RECT  78.304 27.12 82.145 27.144 ;
     RECT  82.069 4.608 82.357 5.544 ;
     RECT  82.141 44.4 82.361 50.136 ;
     RECT  81.877 2.88 82.501 3.432 ;
     RECT  82.357 4.56 82.501 5.544 ;
     RECT  82.069 52.992 82.501 53.016 ;
     RECT  82.501 2.88 82.556 5.544 ;
     RECT  82.501 52.992 82.585 53.064 ;
     RECT  82.361 46.08 82.609 50.136 ;
     RECT  82.465 0.288 82.643 0.312 ;
     RECT  81.491 1.728 82.645 1.752 ;
     RECT  82.556 2.88 82.645 5.784 ;
     RECT  82.537 6.768 82.645 6.792 ;
     RECT  81.965 51.504 82.645 51.624 ;
     RECT  78.304 30.384 82.681 30.408 ;
     RECT  82.645 1.728 82.709 6.792 ;
     RECT  82.609 46.08 82.981 50.424 ;
     RECT  82.645 51.504 82.981 51.864 ;
     RECT  82.981 46.08 83.269 51.864 ;
     RECT  82.709 1.728 83.293 6.84 ;
     RECT  83.228 0.144 83.315 0.168 ;
     RECT  83.293 1.728 83.408 6.888 ;
     RECT  82.825 8.496 83.408 8.52 ;
     RECT  81.157 11.424 83.408 11.448 ;
     RECT  82.933 12.528 83.408 12.552 ;
     RECT  82.681 30.096 83.408 30.408 ;
     RECT  81.065 43.008 83.408 43.032 ;
     RECT  82.361 44.4 83.408 45.048 ;
     RECT  83.269 46.08 83.408 51.96 ;
     RECT  83.408 1.728 83.585 51.96 ;
     RECT  83.585 2.256 83.603 51.96 ;
     RECT  82.585 52.992 83.657 53.016 ;
     RECT  83.603 2.256 83.704 51.582 ;
     RECT  83.704 2.256 83.909 9.816 ;
     RECT  83.704 43.008 84.125 51.576 ;
     RECT  84.125 44.208 84.131 51.576 ;
     RECT  83.704 12.528 84.197 12.936 ;
     RECT  84.197 12.912 84.371 12.936 ;
     RECT  84.131 44.64 84.377 51.576 ;
     RECT  84.377 44.64 84.557 50.712 ;
     RECT  83.909 2.256 84.659 8.568 ;
     RECT  83.704 30.096 85.061 30.84 ;
     RECT  84.805 51.792 85.093 51.816 ;
     RECT  83.704 11.424 85.169 11.496 ;
     RECT  84.659 2.88 85.34 8.568 ;
     RECT  83.909 9.792 85.34 9.816 ;
     RECT  85.093 51.792 85.493 51.864 ;
     RECT  85.417 12 85.501 12.024 ;
     RECT  84.557 44.64 85.667 50.328 ;
     RECT  85.34 2.88 85.709 9.816 ;
     RECT  85.709 2.88 85.849 9.144 ;
     RECT  85.849 2.736 85.955 9.144 ;
     RECT  85.955 3.408 86.221 9.144 ;
     RECT  86.221 9.12 86.357 9.144 ;
     RECT  85.085 1.728 86.501 1.752 ;
     RECT  86.005 51.312 86.569 51.336 ;
     RECT  86.293 52.464 86.569 52.488 ;
     RECT  86.221 3.408 86.627 7.992 ;
     RECT  86.569 51.312 86.645 52.488 ;
     RECT  86.645 51.312 86.653 51.864 ;
     RECT  86.653 51.312 86.681 51.672 ;
     RECT  86.627 3.408 86.915 7.896 ;
     RECT  85.667 45.888 86.915 50.328 ;
     RECT  86.915 3.408 87.109 7.608 ;
     RECT  87.109 2.88 87.581 7.608 ;
     RECT  85.667 44.64 87.685 44.664 ;
     RECT  87.581 2.88 87.797 7.416 ;
     RECT  86.681 51.648 87.797 51.672 ;
     RECT  86.915 45.888 87.937 49.464 ;
     RECT  86.917 50.496 87.937 50.664 ;
     RECT  87.937 45.888 88.021 50.664 ;
     RECT  87.733 0.528 88.121 0.552 ;
     RECT  87.493 1.728 88.261 1.752 ;
     RECT  87.829 53.04 88.405 53.064 ;
     RECT  87.685 44.448 88.585 44.664 ;
     RECT  88.021 45.888 88.585 51.432 ;
     RECT  88.405 52.992 88.645 53.064 ;
     RECT  84.125 43.008 88.729 43.032 ;
     RECT  88.261 1.728 88.808 2.28 ;
     RECT  87.797 3.312 88.808 7.416 ;
     RECT  85.061 30.096 88.808 30.12 ;
     RECT  88.765 38.784 88.808 38.808 ;
     RECT  88.657 40.56 88.808 40.584 ;
     RECT  88.729 42.768 88.808 43.032 ;
     RECT  88.585 44.448 88.808 51.432 ;
     RECT  88.808 1.728 89.029 51.852 ;
     RECT  89.029 1.728 89.104 51.96 ;
     RECT  89.104 1.728 89.219 6.264 ;
     RECT  89.104 43.92 89.363 43.944 ;
     RECT  89.104 48.384 89.411 51.96 ;
     RECT  89.104 39.888 89.525 42.792 ;
     RECT  89.525 39.888 89.555 42.216 ;
     RECT  89.411 51.264 89.605 51.96 ;
     RECT  88.645 52.944 89.605 53.064 ;
     RECT  89.104 46.704 89.669 47.16 ;
     RECT  89.104 38.16 89.777 38.808 ;
     RECT  89.605 51.264 89.993 53.064 ;
     RECT  89.555 39.888 90.065 41.064 ;
     RECT  89.777 38.16 90.097 38.184 ;
     RECT  89.411 48.384 90.124 50.088 ;
     RECT  89.104 44.928 90.133 44.952 ;
     RECT  89.219 4.512 90.209 6.264 ;
     RECT  90.097 37.488 90.275 38.184 ;
     RECT  89.993 51.264 90.275 51.912 ;
     RECT  90.124 48.384 90.421 48.504 ;
     RECT  88.508 0.144 90.563 0.168 ;
     RECT  89.219 1.728 90.565 3.432 ;
     RECT  90.065 39.888 90.601 40.584 ;
     RECT  90.209 4.512 90.605 5.64 ;
     RECT  90.124 49.584 90.605 50.088 ;
     RECT  90.275 51.264 90.641 51.672 ;
     RECT  90.097 43.296 90.661 43.32 ;
     RECT  90.133 44.928 90.661 45.048 ;
     RECT  90.565 1.728 90.677 3.48 ;
     RECT  90.661 43.296 90.707 45.048 ;
     RECT  90.605 50.016 90.709 50.088 ;
     RECT  90.641 51.264 90.709 51.336 ;
     RECT  90.707 43.824 90.748 45.048 ;
     RECT  90.709 50.016 90.965 51.336 ;
     RECT  90.748 44.928 91.033 45.048 ;
     RECT  90.275 38.16 91.041 38.184 ;
     RECT  90.677 2.832 91.093 3.48 ;
     RECT  89.669 46.704 91.117 46.824 ;
     RECT  91.093 2.832 91.141 3.528 ;
     RECT  90.605 4.512 91.141 5.208 ;
     RECT  90.601 39.84 91.217 40.584 ;
     RECT  91.141 2.832 91.289 5.208 ;
     RECT  90.748 43.824 91.325 43.848 ;
     RECT  91.289 2.832 91.405 2.856 ;
     RECT  90.421 48.096 91.429 48.504 ;
     RECT  91.033 44.928 91.541 45.624 ;
     RECT  91.429 48.096 91.573 48.84 ;
     RECT  91.289 4.224 91.628 5.208 ;
     RECT  91.628 4.224 91.715 5.928 ;
     RECT  91.217 40.464 91.865 40.584 ;
     RECT  90.965 50.16 91.964 51.336 ;
     RECT  89.993 53.04 91.973 53.064 ;
     RECT  90.677 1.728 92.045 1.752 ;
     RECT  91.865 40.56 92.045 40.584 ;
     RECT  91.964 50.016 92.051 51.336 ;
     RECT  91.969 42.768 92.053 42.792 ;
     RECT  92.051 50.496 92.053 51.336 ;
     RECT  91.573 47.808 92.113 48.84 ;
     RECT  92.053 50.496 92.117 51.384 ;
     RECT  92.117 50.592 92.177 51.384 ;
     RECT  92.113 47.808 92.243 49.032 ;
     RECT  92.177 50.592 92.261 51.864 ;
     RECT  91.715 4.224 92.321 5.688 ;
     RECT  91.041 38.16 92.509 38.232 ;
     RECT  92.365 39.264 92.509 39.288 ;
     RECT  92.321 3.648 92.533 5.688 ;
     RECT  92.533 3.504 92.545 5.688 ;
     RECT  92.509 38.16 92.549 39.288 ;
     RECT  92.492 0.144 92.579 0.168 ;
     RECT  91.117 46.752 92.653 46.824 ;
     RECT  92.243 47.808 92.653 48.504 ;
     RECT  92.684 2.16 92.689 2.184 ;
     RECT  92.689 2.16 92.773 2.28 ;
     RECT  92.545 3.408 92.773 5.688 ;
     RECT  92.549 38.736 92.837 39.288 ;
     RECT  91.541 44.928 92.876 45.048 ;
     RECT  92.293 40.8 92.905 40.824 ;
     RECT  92.261 50.688 92.909 51.816 ;
     RECT  92.905 40.8 92.989 41.016 ;
     RECT  92.773 3.312 93.053 5.688 ;
     RECT  92.876 44.352 93.109 45.048 ;
     RECT  92.653 46.752 93.109 48.504 ;
     RECT  93.109 44.352 93.155 48.504 ;
     RECT  93.155 45.696 93.229 48.504 ;
     RECT  92.989 40.8 93.233 40.968 ;
     RECT  93.229 45.696 93.473 48.888 ;
     RECT  93.157 53.04 93.493 53.064 ;
     RECT  92.773 2.16 93.541 2.232 ;
     RECT  92.909 50.688 93.625 51.48 ;
     RECT  93.473 45.696 93.653 49.608 ;
     RECT  93.625 50.64 93.653 51.48 ;
     RECT  93.541 1.728 94.021 2.232 ;
     RECT  93.653 45.696 94.165 51.48 ;
     RECT  93.589 52.992 94.165 53.016 ;
     RECT  93.829 0.528 94.169 0.552 ;
     RECT  94.021 1.728 94.208 2.28 ;
     RECT  93.053 3.408 94.208 5.688 ;
     RECT  89.104 30.096 94.208 30.12 ;
     RECT  92.837 39.264 94.208 39.288 ;
     RECT  93.233 40.944 94.208 40.968 ;
     RECT  92.689 42.48 94.208 42.504 ;
     RECT  93.155 44.352 94.208 44.664 ;
     RECT  94.165 45.696 94.208 53.016 ;
     RECT  94.208 1.728 94.504 53.016 ;
     RECT  94.504 42.48 94.643 42.792 ;
     RECT  94.504 51.312 94.739 53.016 ;
     RECT  94.504 43.824 94.931 44.616 ;
     RECT  94.504 46.704 94.961 50.28 ;
     RECT  94.961 46.704 94.969 50.184 ;
     RECT  94.504 1.728 95.177 5.592 ;
     RECT  95.177 1.728 95.293 4.92 ;
     RECT  94.739 52.992 95.437 53.016 ;
     RECT  94.643 42.48 95.533 42.504 ;
     RECT  94.931 43.824 95.713 43.848 ;
     RECT  94.969 46.704 95.797 50.136 ;
     RECT  95.797 45.888 95.929 50.136 ;
     RECT  95.929 45.744 96.073 50.136 ;
     RECT  94.739 51.312 96.073 51.864 ;
     RECT  95.701 53.04 96.077 53.064 ;
     RECT  95.533 42.192 96.149 42.504 ;
     RECT  95.293 1.728 96.253 1.752 ;
     RECT  96.253 1.104 96.277 1.752 ;
     RECT  95.293 2.784 96.277 4.92 ;
     RECT  96.073 45.744 96.293 51.864 ;
     RECT  95.713 43.536 96.325 43.848 ;
     RECT  96.277 1.104 96.371 4.92 ;
     RECT  96.325 43.536 96.371 44.184 ;
     RECT  96.371 1.728 96.469 4.92 ;
     RECT  96.469 1.728 96.509 5.208 ;
     RECT  96.371 43.824 96.649 44.184 ;
     RECT  96.293 45.744 96.649 51.384 ;
     RECT  96.509 1.728 97.129 2.856 ;
     RECT  96.649 43.824 97.157 51.384 ;
     RECT  97.129 1.728 97.265 2.28 ;
     RECT  97.045 52.464 97.283 52.488 ;
     RECT  96.509 3.84 97.381 5.208 ;
     RECT  97.157 43.92 97.445 51.384 ;
     RECT  96.149 42.192 97.453 42.216 ;
     RECT  97.381 3.84 97.477 5.256 ;
     RECT  94.504 39.264 97.585 39.288 ;
     RECT  97.585 39.264 97.586 39.336 ;
     RECT  97.586 39.312 97.628 39.336 ;
     RECT  97.724 0.144 97.811 0.168 ;
     RECT  97.445 43.92 97.949 51.336 ;
     RECT  97.477 3.408 98.005 5.256 ;
     RECT  97.813 53.04 98.021 53.064 ;
     RECT  97.949 47.184 98.057 51.336 ;
     RECT  98.057 47.184 98.129 51.192 ;
     RECT  98.005 3.408 98.252 5.4 ;
     RECT  97.949 43.92 98.293 46.008 ;
     RECT  98.252 3.312 98.513 5.4 ;
     RECT  98.513 0.528 98.597 0.552 ;
     RECT  98.129 47.184 98.597 50.904 ;
     RECT  97.628 39.312 98.629 39.816 ;
     RECT  94.504 40.848 98.629 40.872 ;
     RECT  98.293 42.432 98.965 46.008 ;
     RECT  98.629 39.312 99.061 40.872 ;
     RECT  98.965 42.384 99.061 46.008 ;
     RECT  99.061 39.312 99.097 46.008 ;
     RECT  98.597 47.184 99.097 50.76 ;
     RECT  99.308 0.144 99.395 0.168 ;
     RECT  97.265 1.728 99.445 1.752 ;
     RECT  98.513 2.88 99.445 5.4 ;
     RECT  99.301 51.792 99.457 51.816 ;
     RECT  99.445 1.728 99.608 5.4 ;
     RECT  94.504 30.096 99.608 30.12 ;
     RECT  99.097 39.312 99.608 50.76 ;
     RECT  99.457 51.792 99.608 51.96 ;
     RECT  99.608 1.728 99.637 51.96 ;
     RECT  99.637 1.728 99.904 52.008 ;
     RECT  99.904 1.728 100.001 5.256 ;
     RECT  99.904 50.736 100.067 52.008 ;
     RECT  100.067 50.736 100.547 51.96 ;
     RECT  100.547 51.312 100.739 51.96 ;
     RECT  100.001 3.936 100.865 5.256 ;
     RECT  100.739 51.312 100.883 51.912 ;
     RECT  99.904 42.72 100.897 49.608 ;
     RECT  100.865 3.936 100.901 5.016 ;
     RECT  100.897 42.72 100.973 50.184 ;
     RECT  99.904 39.36 101.009 40.344 ;
     RECT  100.001 1.728 101.041 2.712 ;
     RECT  100.973 43.296 101.123 50.184 ;
     RECT  101.041 1.728 101.125 2.856 ;
     RECT  101.084 40.416 101.171 40.44 ;
     RECT  101.125 1.728 101.261 2.28 ;
     RECT  101.123 43.296 101.441 49.848 ;
     RECT  100.901 4.512 101.513 5.016 ;
     RECT  101.461 52.992 101.585 53.016 ;
     RECT  101.401 0.24 101.603 0.264 ;
     RECT  101.441 44.832 101.981 49.848 ;
     RECT  100.883 51.84 101.981 51.912 ;
     RECT  101.441 43.296 102.013 43.56 ;
     RECT  101.261 2.256 102.035 2.28 ;
     RECT  101.513 4.512 102.157 4.92 ;
     RECT  101.009 39.36 102.193 39.384 ;
     RECT  101.981 46.656 102.301 49.848 ;
     RECT  102.284 51.312 102.301 51.336 ;
     RECT  102.301 46.656 102.371 51.336 ;
     RECT  102.013 43.2 102.521 43.56 ;
     RECT  102.037 52.464 102.521 52.488 ;
     RECT  102.521 43.296 102.613 43.56 ;
     RECT  101.981 44.832 102.613 45.624 ;
     RECT  102.193 42.048 102.841 42.072 ;
     RECT  102.371 47.856 102.949 51.336 ;
     RECT  102.613 43.296 103.052 45.624 ;
     RECT  102.371 46.656 103.052 46.68 ;
     RECT  102.841 41.472 103.057 42.072 ;
     RECT  103.052 43.296 103.235 46.68 ;
     RECT  102.193 39.36 103.244 39.768 ;
     RECT  103.057 41.472 103.244 42.216 ;
     RECT  103.235 43.536 103.381 46.68 ;
     RECT  102.949 47.856 103.381 51.816 ;
     RECT  103.244 39.36 103.421 42.216 ;
     RECT  103.421 39.36 103.565 39.768 ;
     RECT  103.381 43.536 103.861 51.816 ;
     RECT  102.157 3.552 104.029 4.92 ;
     RECT  104.029 3.552 104.137 5.016 ;
     RECT  103.421 41.472 104.245 42.216 ;
     RECT  103.861 43.536 104.245 51.864 ;
     RECT  104.245 41.472 104.785 51.864 ;
     RECT  102.365 1.728 105.008 1.752 ;
     RECT  104.137 3.552 105.008 5.064 ;
     RECT  104.029 16.368 105.008 16.392 ;
     RECT  99.904 30.096 105.008 30.12 ;
     RECT  103.565 39.36 105.008 39.384 ;
     RECT  104.785 41.232 105.008 51.864 ;
     RECT  105.008 1.728 105.061 51.864 ;
     RECT  105.061 1.728 105.217 52.008 ;
     RECT  105.217 1.728 105.304 52.44 ;
     RECT  105.304 1.728 105.365 1.992 ;
     RECT  105.304 42.72 105.443 52.44 ;
     RECT  105.443 48.288 105.541 52.44 ;
     RECT  105.541 48.288 105.587 53.064 ;
     RECT  105.443 42.72 106.157 47.304 ;
     RECT  106.157 42.768 106.265 47.304 ;
     RECT  105.304 40.992 106.273 41.448 ;
     RECT  105.365 1.728 106.405 1.752 ;
     RECT  106.265 42.816 106.513 47.304 ;
     RECT  105.587 48.288 106.513 51.576 ;
     RECT  106.513 42.816 106.553 51.576 ;
     RECT  105.304 15.984 106.585 16.392 ;
     RECT  105.304 39.36 106.585 39.384 ;
     RECT  106.405 1.728 106.589 1.848 ;
     RECT  106.585 39.36 106.625 39.528 ;
     RECT  106.553 51.312 106.865 51.576 ;
     RECT  106.865 51.312 106.931 51.864 ;
     RECT  106.931 51.84 106.949 51.864 ;
     RECT  105.304 3.408 107.084 5.064 ;
     RECT  106.585 15.984 107.171 16.536 ;
     RECT  106.273 41.376 107.201 41.448 ;
     RECT  106.625 39.504 107.377 39.528 ;
     RECT  105.587 52.992 107.509 53.064 ;
     RECT  106.553 42.816 107.555 49.896 ;
     RECT  107.509 52.896 107.561 53.064 ;
     RECT  107.561 52.896 107.597 53.016 ;
     RECT  106.589 1.728 107.605 1.752 ;
     RECT  107.084 3.408 107.653 5.16 ;
     RECT  107.605 1.728 107.705 2.28 ;
     RECT  107.555 42.816 107.881 47.4 ;
     RECT  107.377 39.504 107.957 39.816 ;
     RECT  107.555 48.432 108.085 49.896 ;
     RECT  107.597 52.992 108.173 53.016 ;
     RECT  107.201 41.424 108.205 41.448 ;
     RECT  107.881 42.72 108.205 47.4 ;
     RECT  108.085 48.432 108.349 50.568 ;
     RECT  108.349 48.432 108.421 50.904 ;
     RECT  107.653 3.408 108.425 5.544 ;
     RECT  108.421 48.432 108.565 51.864 ;
     RECT  108.565 48.384 108.677 51.864 ;
     RECT  108.677 48.384 108.857 51.816 ;
     RECT  108.205 41.424 108.925 47.4 ;
     RECT  108.857 48.384 108.925 51.768 ;
     RECT  108.925 41.424 108.956 51.768 ;
     RECT  107.957 39.504 109.105 39.528 ;
     RECT  108.956 40.752 109.105 51.768 ;
     RECT  108.565 53.04 109.261 53.064 ;
     RECT  107.705 1.728 110.329 1.752 ;
     RECT  110.329 1.728 110.408 2.04 ;
     RECT  108.425 3.696 110.408 5.544 ;
     RECT  107.171 16.272 110.408 16.536 ;
     RECT  105.304 30.096 110.408 30.12 ;
     RECT  109.105 39.504 110.408 51.768 ;
     RECT  110.408 1.728 110.512 51.852 ;
     RECT  109.621 52.992 110.579 53.016 ;
     RECT  110.512 1.728 110.704 51.582 ;
     RECT  110.704 3.696 110.981 5.544 ;
     RECT  110.704 39.504 111.107 51.336 ;
     RECT  111.107 40.272 111.148 51.336 ;
     RECT  111.148 40.56 111.733 51.336 ;
     RECT  110.981 4.176 111.773 5.544 ;
     RECT  111.733 40.56 111.881 51.864 ;
     RECT  110.704 1.728 111.905 1.848 ;
     RECT  111.905 1.728 111.989 2.28 ;
     RECT  111.881 40.56 112.061 42.6 ;
     RECT  111.881 43.632 112.133 51.864 ;
     RECT  112.061 42.096 112.205 42.6 ;
     RECT  112.133 43.632 112.259 51.672 ;
     RECT  112.259 50.4 112.277 51.672 ;
     RECT  112.061 40.56 112.385 41.064 ;
     RECT  111.773 4.176 112.417 5.112 ;
     RECT  112.385 41.04 112.421 41.064 ;
     RECT  112.417 3.888 112.705 5.112 ;
     RECT  112.705 3.744 112.813 5.112 ;
     RECT  111.989 1.728 112.837 1.752 ;
     RECT  112.205 42.576 112.849 42.6 ;
     RECT  112.259 43.632 112.849 49.272 ;
     RECT  112.837 1.152 112.924 1.752 ;
     RECT  112.813 2.976 112.925 5.112 ;
     RECT  111.877 53.04 112.933 53.064 ;
     RECT  112.925 3.648 112.997 5.112 ;
     RECT  112.997 3.744 113.033 5.112 ;
     RECT  113.033 3.84 113.069 5.112 ;
     RECT  112.849 42.576 113.281 49.272 ;
     RECT  110.704 16.272 113.315 16.536 ;
     RECT  112.277 50.4 113.557 51.336 ;
     RECT  113.281 42.528 113.641 49.272 ;
     RECT  112.933 52.992 113.845 53.064 ;
     RECT  113.641 41.616 113.893 49.272 ;
     RECT  113.893 41.616 113.921 49.368 ;
     RECT  113.557 50.4 113.921 51.624 ;
     RECT  113.069 3.84 113.933 5.016 ;
     RECT  113.845 52.608 113.933 53.064 ;
     RECT  110.704 30.096 114.041 30.12 ;
     RECT  113.921 41.616 114.041 51.624 ;
     RECT  114.041 41.616 114.257 49.608 ;
     RECT  113.933 3.84 114.289 4.968 ;
     RECT  113.933 53.04 114.325 53.064 ;
     RECT  114.041 50.736 114.329 51.624 ;
     RECT  113.315 16.512 114.565 16.536 ;
     RECT  114.329 50.736 114.581 51.384 ;
     RECT  114.325 53.04 114.581 53.208 ;
     RECT  114.565 16.512 114.611 16.824 ;
     RECT  114.581 50.736 114.707 51.336 ;
     RECT  114.707 51.264 114.844 51.336 ;
     RECT  114.581 53.04 115.043 53.112 ;
     RECT  112.924 1.728 115.301 1.752 ;
     RECT  114.289 3.552 115.549 4.968 ;
     RECT  115.549 3.408 115.573 4.968 ;
     RECT  114.844 51.312 115.621 51.336 ;
     RECT  115.621 51.312 115.669 51.432 ;
     RECT  115.621 1.968 115.808 1.992 ;
     RECT  115.573 3.408 115.808 5.304 ;
     RECT  114.611 16.8 115.808 16.824 ;
     RECT  114.901 30.192 115.808 30.216 ;
     RECT  114.257 41.616 115.808 49.368 ;
     RECT  115.669 51.312 115.808 51.768 ;
     RECT  115.808 1.968 115.957 51.852 ;
     RECT  115.957 1.968 116.104 51.96 ;
     RECT  116.104 42.768 116.165 51.96 ;
     RECT  116.104 41.76 116.243 41.784 ;
     RECT  116.165 42.768 116.281 51.768 ;
     RECT  116.104 1.968 116.437 2.28 ;
     RECT  116.281 43.344 116.453 51.768 ;
     RECT  116.453 43.344 116.633 50.28 ;
     RECT  116.104 3.408 116.705 5.304 ;
     RECT  115.043 53.04 116.741 53.064 ;
     RECT  116.437 1.728 116.915 2.28 ;
     RECT  116.633 43.344 116.921 49.56 ;
     RECT  116.921 43.344 116.957 48.984 ;
     RECT  116.705 3.888 117.173 5.304 ;
     RECT  116.453 51.36 117.205 51.768 ;
     RECT  117.205 51.36 117.493 51.816 ;
     RECT  117.493 50.592 117.781 51.816 ;
     RECT  116.957 43.344 117.925 48.552 ;
     RECT  117.925 43.344 118.012 48.648 ;
     RECT  118.012 43.344 118.028 48.552 ;
     RECT  117.781 50.016 118.037 51.816 ;
     RECT  118.028 43.152 118.069 48.552 ;
     RECT  118.141 3.312 118.177 3.336 ;
     RECT  117.173 4.512 118.177 5.304 ;
     RECT  118.177 3.312 118.249 5.304 ;
     RECT  118.069 43.008 118.249 48.552 ;
     RECT  118.037 50.592 118.253 51.432 ;
     RECT  118.249 3.216 118.541 5.304 ;
     RECT  118.249 42.72 118.757 48.552 ;
     RECT  118.253 50.64 119.029 51.432 ;
     RECT  116.915 1.728 119.041 1.752 ;
     RECT  119.029 50.64 119.117 51.816 ;
     RECT  118.757 42.72 119.189 43.032 ;
     RECT  118.541 3.312 119.225 5.304 ;
     RECT  119.041 1.104 119.315 1.752 ;
     RECT  118.757 44.016 119.42 48.552 ;
     RECT  119.117 50.736 119.693 51.816 ;
     RECT  119.617 0.192 119.747 0.216 ;
     RECT  119.42 44.016 119.765 48.648 ;
     RECT  119.225 3.408 119.837 5.304 ;
     RECT  119.765 44.064 119.909 48.648 ;
     RECT  119.909 44.736 120.085 48.648 ;
     RECT  120.085 44.736 120.476 48.744 ;
     RECT  120.476 44.736 120.517 49.416 ;
     RECT  119.693 50.736 120.764 51.384 ;
     RECT  120.517 44.736 120.86 49.512 ;
     RECT  120.764 50.736 120.86 51.48 ;
     RECT  119.837 3.408 120.877 4.152 ;
     RECT  119.837 5.184 120.877 5.304 ;
     RECT  119.315 1.728 121.165 1.752 ;
     RECT  121.165 1.728 121.208 1.992 ;
     RECT  120.877 3.408 121.208 5.304 ;
     RECT  116.104 16.8 121.208 16.824 ;
     RECT  119.189 43.008 121.208 43.032 ;
     RECT  120.86 44.736 121.208 51.48 ;
     RECT  121.208 1.728 121.312 51.852 ;
     RECT  121.312 1.728 121.504 51.582 ;
     RECT  121.504 45.168 121.709 48.648 ;
     RECT  121.709 47.28 121.781 48.648 ;
     RECT  121.709 45.168 121.817 46.248 ;
     RECT  121.504 49.872 122.321 51.336 ;
     RECT  121.781 47.28 122.857 48.504 ;
     RECT  122.857 47.28 123.185 48.744 ;
     RECT  123.185 48.384 123.437 48.744 ;
     RECT  121.504 3.984 123.473 5.304 ;
     RECT  123.437 48.48 123.473 48.744 ;
     RECT  123.289 51.792 123.587 51.816 ;
     RECT  121.817 45.168 123.617 45.96 ;
     RECT  123.185 47.28 123.653 47.304 ;
     RECT  122.321 50.688 123.829 50.712 ;
     RECT  123.829 50.688 124.028 51.336 ;
     RECT  123.617 45.936 124.153 45.96 ;
     RECT  124.045 47.136 124.153 47.16 ;
     RECT  124.028 50.112 124.309 51.336 ;
     RECT  124.297 53.04 124.381 53.064 ;
     RECT  124.309 49.488 124.741 51.336 ;
     RECT  124.153 45.936 124.789 47.16 ;
     RECT  123.473 48.48 124.789 48.504 ;
     RECT  123.473 4.656 124.877 5.304 ;
     RECT  124.789 45.936 124.877 48.504 ;
     RECT  121.504 1.728 124.933 1.752 ;
     RECT  124.933 1.728 125.021 2.28 ;
     RECT  124.741 49.488 125.077 51.384 ;
     RECT  125.077 49.488 125.171 51.432 ;
     RECT  125.171 50.4 125.269 51.432 ;
     RECT  125.269 50.4 125.411 51.48 ;
     RECT  124.877 4.752 125.525 5.304 ;
     RECT  125.521 53.04 125.891 53.064 ;
     RECT  125.525 4.752 125.917 5.256 ;
     RECT  124.877 45.936 126.169 47.832 ;
     RECT  126.169 45.936 126.385 47.88 ;
     RECT  125.845 49.008 126.385 49.368 ;
     RECT  125.917 4.704 126.493 5.256 ;
     RECT  125.021 1.728 126.608 1.752 ;
     RECT  123.721 3.6 126.608 3.624 ;
     RECT  126.493 4.608 126.608 5.256 ;
     RECT  121.504 16.8 126.608 16.824 ;
     RECT  121.504 43.008 126.608 43.032 ;
     RECT  126.385 45.936 126.608 49.368 ;
     RECT  125.411 50.4 126.608 50.76 ;
     RECT  125.653 51.792 126.608 51.816 ;
     RECT  126.517 0.192 126.659 0.216 ;
     RECT  126.608 1.728 126.712 51.852 ;
     RECT  126.712 1.728 126.904 51.582 ;
     RECT  126.904 1.728 127.073 2.04 ;
     RECT  126.904 4.512 127.145 5.256 ;
     RECT  126.904 50.016 127.145 50.664 ;
     RECT  126.904 45.936 127.181 48.792 ;
     RECT  127.145 50.016 127.909 50.04 ;
     RECT  127.181 45.936 127.973 48.504 ;
     RECT  127.909 49.68 127.996 50.04 ;
     RECT  127.973 48.48 128.045 48.504 ;
     RECT  127.973 45.936 128.153 47.304 ;
     RECT  126.904 16.8 128.189 16.824 ;
     RECT  126.904 43.008 128.339 43.032 ;
     RECT  128.293 16.992 128.513 17.016 ;
     RECT  127.996 50.016 128.653 50.04 ;
     RECT  128.437 51.504 128.653 51.528 ;
     RECT  127.073 1.728 128.693 1.752 ;
     RECT  128.653 50.016 128.771 51.528 ;
     RECT  128.771 50.016 128.837 50.184 ;
     RECT  128.437 48.816 128.972 48.936 ;
     RECT  128.153 47.28 129.013 47.304 ;
     RECT  128.771 51.312 129.059 51.528 ;
     RECT  128.972 48.816 129.061 49.032 ;
     RECT  128.837 50.016 129.061 50.136 ;
     RECT  127.145 4.512 129.121 5.208 ;
     RECT  129.013 47.28 129.356 47.592 ;
     RECT  129.061 48.816 129.395 50.136 ;
     RECT  129.356 47.232 129.397 47.592 ;
     RECT  129.395 48.816 129.397 48.84 ;
     RECT  129.397 47.232 129.413 48.84 ;
     RECT  129.413 47.232 129.443 47.928 ;
     RECT  129.445 44.88 129.596 44.904 ;
     RECT  128.153 45.936 129.596 46.248 ;
     RECT  129.596 44.88 129.683 46.248 ;
     RECT  128.876 2.256 129.733 2.28 ;
     RECT  128.149 53.04 129.809 53.064 ;
     RECT  129.443 47.28 130.097 47.928 ;
     RECT  129.683 44.88 130.205 44.904 ;
     RECT  129.733 1.728 130.211 2.28 ;
     RECT  129.121 3.936 130.349 5.208 ;
     RECT  129.395 50.016 130.417 50.136 ;
     RECT  130.417 50.016 130.501 50.184 ;
     RECT  129.059 51.312 130.501 51.432 ;
     RECT  130.501 49.392 131.029 50.184 ;
     RECT  131.029 49.344 131.276 50.184 ;
     RECT  130.349 4.752 131.425 5.208 ;
     RECT  131.276 48.912 131.425 50.184 ;
     RECT  130.501 51.312 131.425 51.672 ;
     RECT  130.097 47.28 131.468 47.304 ;
     RECT  129.683 45.936 131.509 46.248 ;
     RECT  131.468 47.232 131.509 47.304 ;
     RECT  131.425 4.656 131.569 5.208 ;
     RECT  130.211 1.728 131.929 1.752 ;
     RECT  131.929 1.68 132.008 1.752 ;
     RECT  131.569 4.608 132.008 5.208 ;
     RECT  131.509 45.936 132.008 47.64 ;
     RECT  131.425 48.912 132.008 51.672 ;
     RECT  132.008 1.68 132.112 51.852 ;
     RECT  132.112 1.68 132.304 51.816 ;
     RECT  132.304 1.68 132.611 1.752 ;
     RECT  132.304 44.736 133.085 47.64 ;
     RECT  132.304 51.792 133.283 51.816 ;
     RECT  132.304 4.56 133.297 5.208 ;
     RECT  132.304 50.016 133.333 50.04 ;
     RECT  133.085 44.736 133.553 46.104 ;
     RECT  133.333 50.016 133.573 50.136 ;
     RECT  133.553 44.736 133.589 44.76 ;
     RECT  133.513 49.008 133.628 49.032 ;
     RECT  133.573 50.016 133.661 50.28 ;
     RECT  133.628 48.912 133.715 49.032 ;
     RECT  133.585 3.072 133.733 3.096 ;
     RECT  133.297 4.56 133.945 6.072 ;
     RECT  133.661 50.016 133.985 50.184 ;
     RECT  132.611 1.728 134.149 1.752 ;
     RECT  133.985 50.016 134.3 50.04 ;
     RECT  134.3 49.872 134.387 50.04 ;
     RECT  134.017 53.04 134.387 53.064 ;
     RECT  133.945 4.512 134.413 6.072 ;
     RECT  134.348 0.144 134.435 0.168 ;
     RECT  133.333 51.312 134.437 51.336 ;
     RECT  133.085 47.616 134.449 47.64 ;
     RECT  134.387 49.92 134.569 50.04 ;
     RECT  134.149 1.728 134.741 2.328 ;
     RECT  134.741 1.728 135.029 1.8 ;
     RECT  134.437 51.312 135.065 51.432 ;
     RECT  134.989 50.16 135.107 50.184 ;
     RECT  135.065 51.36 135.107 51.432 ;
     RECT  134.449 47.616 135.173 47.736 ;
     RECT  135.061 48.912 135.209 48.936 ;
     RECT  135.349 0.192 135.497 0.216 ;
     RECT  135.349 51.792 135.533 51.816 ;
     RECT  135.173 47.616 135.565 47.64 ;
     RECT  135.781 2.208 136.165 2.232 ;
     RECT  136.165 2.208 136.213 2.28 ;
     RECT  135.961 3.504 136.259 3.528 ;
     RECT  136.213 2.208 136.565 2.52 ;
     RECT  135.565 47.28 136.597 47.64 ;
     RECT  136.597 50.208 137.041 50.232 ;
     RECT  136.597 47.28 137.365 47.88 ;
     RECT  136.565 1.728 137.408 2.52 ;
     RECT  134.413 4.512 137.408 6.12 ;
     RECT  133.553 46.08 137.408 46.104 ;
     RECT  137.365 47.28 137.408 48.408 ;
     RECT  137.041 49.776 137.408 50.232 ;
     RECT  137.408 1.728 137.512 51.852 ;
     RECT  137.512 1.728 137.704 51.582 ;
     RECT  137.704 46.08 137.765 46.824 ;
     RECT  137.704 3.6 137.843 3.624 ;
     RECT  137.765 46.704 137.939 46.824 ;
     RECT  137.869 53.04 138.131 53.064 ;
     RECT  138.149 0.192 138.233 0.216 ;
     RECT  137.704 47.856 138.629 48.408 ;
     RECT  137.704 49.776 138.697 50.04 ;
     RECT  138.697 49.536 138.86 50.04 ;
     RECT  137.704 5.184 139.057 6.12 ;
     RECT  137.704 1.728 139.205 2.52 ;
     RECT  139.057 5.088 139.277 6.12 ;
     RECT  137.939 46.704 139.313 46.728 ;
     RECT  139.277 5.184 139.457 6.12 ;
     RECT  138.86 49.488 139.565 50.04 ;
     RECT  137.704 51.312 139.58 51.336 ;
     RECT  139.58 51.312 139.667 51.432 ;
     RECT  139.565 49.488 139.709 49.512 ;
     RECT  139.813 0.576 139.925 0.6 ;
     RECT  139.777 46.176 140.249 46.2 ;
     RECT  140.137 45.024 140.485 45.048 ;
     RECT  140.485 44.352 140.531 45.048 ;
     RECT  138.629 47.856 140.533 48.12 ;
     RECT  140.531 44.352 140.573 44.376 ;
     RECT  139.667 51.312 140.573 51.384 ;
     RECT  139.205 1.728 140.581 1.752 ;
     RECT  140.569 3.792 140.605 3.816 ;
     RECT  140.573 51.312 140.605 51.336 ;
     RECT  140.605 3.792 140.717 3.912 ;
     RECT  140.497 49.44 140.725 49.464 ;
     RECT  140.605 50.736 140.725 51.336 ;
     RECT  139.457 5.184 140.749 6.072 ;
     RECT  140.581 1.728 140.753 1.8 ;
     RECT  140.717 3.888 140.753 3.912 ;
     RECT  140.725 49.44 140.771 51.336 ;
     RECT  140.972 1.68 141.059 1.704 ;
     RECT  140.101 43.296 141.401 43.32 ;
     RECT  140.533 47.04 141.613 48.12 ;
     RECT  140.771 49.44 141.613 50.76 ;
     RECT  140.749 5.184 141.617 6.264 ;
     RECT  141.613 47.04 141.617 50.76 ;
     RECT  141.617 47.04 141.653 49.896 ;
     RECT  141.397 0.192 142.213 0.216 ;
     RECT  142.213 0.192 142.229 0.264 ;
     RECT  141.617 5.184 142.261 6.072 ;
     RECT  142.229 0.24 142.409 0.264 ;
     RECT  142.261 4.512 142.693 6.072 ;
     RECT  142.693 4.512 142.765 6.408 ;
     RECT  141.821 1.728 142.808 1.752 ;
     RECT  142.765 4.128 142.808 6.408 ;
     RECT  141.404 43.344 142.808 43.896 ;
     RECT  142.549 45.696 142.808 45.72 ;
     RECT  141.653 47.04 142.808 47.88 ;
     RECT  141.653 48.96 142.808 49.896 ;
     RECT  142.808 1.728 142.933 51.852 ;
     RECT  142.933 1.728 143.02 52.008 ;
     RECT  143.02 1.728 143.104 51.582 ;
     RECT  143.104 43.872 143.129 43.896 ;
     RECT  143.104 45.696 143.129 46.584 ;
     RECT  143.104 4.512 143.381 6.168 ;
     RECT  143.341 53.088 143.557 53.112 ;
     RECT  143.104 50.736 143.651 51.336 ;
     RECT  143.557 53.04 143.891 53.112 ;
     RECT  143.413 0.192 143.921 0.216 ;
     RECT  143.891 53.04 144.065 53.064 ;
     RECT  143.104 48.96 144.097 49.608 ;
     RECT  143.104 1.728 144.197 1.752 ;
     RECT  144.197 1.728 144.205 1.8 ;
     RECT  144.205 1.68 144.281 1.8 ;
     RECT  144.281 1.68 144.659 1.752 ;
     RECT  143.381 5.184 144.781 6.168 ;
     RECT  143.651 51.312 145.001 51.336 ;
     RECT  143.104 47.856 145.033 47.88 ;
     RECT  143.129 45.696 145.045 45.72 ;
     RECT  145.033 47.088 145.045 47.88 ;
     RECT  144.997 0.528 145.091 0.552 ;
     RECT  145.045 45.696 145.132 47.88 ;
     RECT  145.132 47.088 145.141 47.88 ;
     RECT  144.097 48.96 145.141 49.896 ;
     RECT  145.132 45.696 145.177 46.056 ;
     RECT  145.141 47.088 145.187 49.896 ;
     RECT  145.177 44.976 145.217 46.056 ;
     RECT  145.187 48.624 145.217 49.896 ;
     RECT  145.217 48.624 145.228 48.984 ;
     RECT  144.781 4.896 145.357 6.168 ;
     RECT  145.045 51.792 145.361 51.816 ;
     RECT  145.228 48.912 145.577 48.984 ;
     RECT  145.357 4.608 145.649 6.168 ;
     RECT  145.217 44.976 145.865 45 ;
     RECT  144.659 1.728 145.897 1.752 ;
     RECT  145.501 50.112 145.933 50.136 ;
     RECT  145.897 1.728 146.005 2.712 ;
     RECT  145.964 3.744 146.005 3.768 ;
     RECT  146.005 1.728 146.051 3.768 ;
     RECT  145.649 4.848 146.051 6.168 ;
     RECT  145.217 46.032 146.477 46.056 ;
     RECT  146.051 1.728 146.585 3.048 ;
     RECT  146.051 5.136 146.773 6.168 ;
     RECT  145.577 48.912 146.797 48.936 ;
     RECT  145.933 50.112 146.797 50.712 ;
     RECT  146.773 5.136 146.819 6.264 ;
     RECT  145.187 47.088 146.876 47.592 ;
     RECT  146.876 47.088 146.963 47.88 ;
     RECT  146.585 3.024 147.161 3.048 ;
     RECT  146.819 5.136 147.553 5.208 ;
     RECT  146.963 47.088 147.637 47.592 ;
     RECT  147.553 4.512 147.805 5.208 ;
     RECT  146.797 48.912 147.805 50.712 ;
     RECT  147.553 53.04 147.827 53.064 ;
     RECT  147.061 0.192 147.845 0.216 ;
     RECT  147.805 4.128 147.877 5.208 ;
     RECT  146.819 6.24 147.877 6.264 ;
     RECT  147.877 4.128 148.069 6.264 ;
     RECT  146.585 1.728 148.208 1.752 ;
     RECT  148.069 3.984 148.208 6.264 ;
     RECT  148.165 44.448 148.208 44.472 ;
     RECT  147.637 46.752 148.208 47.592 ;
     RECT  147.805 48.912 148.208 51.528 ;
     RECT  148.208 1.728 148.405 51.852 ;
     RECT  148.405 1.728 148.504 51.96 ;
     RECT  148.504 47.328 148.643 49.608 ;
     RECT  148.504 3.024 148.673 3.048 ;
     RECT  148.504 51.312 148.673 51.96 ;
     RECT  148.504 1.728 148.709 1.8 ;
     RECT  148.504 4.128 148.709 6.12 ;
     RECT  148.643 47.328 148.787 47.448 ;
     RECT  148.504 44.4 148.825 44.472 ;
     RECT  148.709 4.368 148.835 6.12 ;
     RECT  148.835 4.608 148.876 6.12 ;
     RECT  148.787 47.328 148.889 47.4 ;
     RECT  148.876 4.656 149.069 6.12 ;
     RECT  148.825 44.448 149.713 44.472 ;
     RECT  148.504 45.6 149.713 45.624 ;
     RECT  148.673 51.312 149.753 51.336 ;
     RECT  149.749 53.04 149.833 53.064 ;
     RECT  148.643 49.2 149.9 49.608 ;
     RECT  148.889 47.328 149.921 47.352 ;
     RECT  149.921 46.752 149.941 47.352 ;
     RECT  149.9 48.96 149.941 49.608 ;
     RECT  149.941 48.96 149.987 49.752 ;
     RECT  149.941 46.752 150.077 47.88 ;
     RECT  149.069 4.656 150.109 5.208 ;
     RECT  149.713 44.448 150.289 45.624 ;
     RECT  150.289 44.016 150.325 45.624 ;
     RECT  150.325 44.016 150.467 45.72 ;
     RECT  150.467 45.12 150.469 45.72 ;
     RECT  150.077 46.752 150.469 47.544 ;
     RECT  150.469 45.12 150.473 47.544 ;
     RECT  149.893 51.792 150.473 51.816 ;
     RECT  150.473 46.176 150.653 47.544 ;
     RECT  150.473 45.12 150.833 45.144 ;
     RECT  150.467 44.016 150.865 44.04 ;
     RECT  149.987 49.488 150.865 49.752 ;
     RECT  150.865 43.68 150.905 44.04 ;
     RECT  150.865 49.488 150.905 50.712 ;
     RECT  150.905 50.688 150.965 50.712 ;
     RECT  150.965 50.688 151.049 51.336 ;
     RECT  150.905 49.488 151.193 49.56 ;
     RECT  151.193 49.536 151.409 49.56 ;
     RECT  151.049 50.688 151.409 50.712 ;
     RECT  151.045 0.192 151.445 0.216 ;
     RECT  150.109 4.56 152.053 5.208 ;
     RECT  150.865 41.616 152.149 41.64 ;
     RECT  152.149 41.616 152.195 42.456 ;
     RECT  152.053 4.56 152.197 5.64 ;
     RECT  150.905 43.68 152.197 43.704 ;
     RECT  152.195 42.432 152.444 42.456 ;
     RECT  152.197 43.68 152.444 44.472 ;
     RECT  152.444 42.432 152.531 44.472 ;
     RECT  152.197 3.84 152.701 5.64 ;
     RECT  152.413 51.792 152.725 51.816 ;
     RECT  150.653 46.176 152.773 46.2 ;
     RECT  150.653 47.328 152.773 47.352 ;
     RECT  152.531 44.448 152.809 44.472 ;
     RECT  152.665 53.04 152.963 53.064 ;
     RECT  152.701 50.112 153.02 50.136 ;
     RECT  152.725 51.408 153.061 51.816 ;
     RECT  153.061 51.312 153.253 51.816 ;
     RECT  152.701 3.84 153.421 6.024 ;
     RECT  153.02 49.344 153.493 50.136 ;
     RECT  153.253 51.216 153.493 51.816 ;
     RECT  153.493 49.344 153.5 51.816 ;
     RECT  153.169 0.528 153.539 0.552 ;
     RECT  153.5 49.344 153.587 52.008 ;
     RECT  148.709 1.728 153.608 1.752 ;
     RECT  153.421 3.312 153.608 6.024 ;
     RECT  152.531 42.432 153.608 42.552 ;
     RECT  152.809 44.448 153.608 44.904 ;
     RECT  152.773 46.176 153.608 47.352 ;
     RECT  153.587 49.344 153.608 51.96 ;
     RECT  153.608 1.728 153.875 51.96 ;
     RECT  153.875 1.728 153.904 51.816 ;
     RECT  153.904 44.88 154.181 44.904 ;
     RECT  153.904 3.84 154.211 3.864 ;
     RECT  153.904 2.832 154.225 2.856 ;
     RECT  153.904 4.896 154.252 5.736 ;
     RECT  153.904 42.528 154.289 42.552 ;
     RECT  154.252 4.896 154.397 5.208 ;
     RECT  153.904 48.432 154.865 51.816 ;
     RECT  154.865 48.432 155.045 51.528 ;
     RECT  155.045 48.432 155.075 51.336 ;
     RECT  155.075 49.488 155.189 51.336 ;
     RECT  153.904 47.328 155.221 47.352 ;
     RECT  155.075 48.432 155.221 48.456 ;
     RECT  155.221 47.328 155.276 48.456 ;
     RECT  155.276 47.232 155.363 48.456 ;
     RECT  153.904 46.224 155.437 46.248 ;
     RECT  155.437 46.128 155.477 46.248 ;
     RECT  153.904 1.728 155.509 1.752 ;
     RECT  155.363 47.328 155.651 48.456 ;
     RECT  155.189 50.688 155.693 51.336 ;
     RECT  154.933 43.248 155.845 43.272 ;
     RECT  155.651 47.328 155.891 47.352 ;
     RECT  155.509 1.728 156.053 2.184 ;
     RECT  156.053 2.16 156.277 2.184 ;
     RECT  155.651 48.432 156.557 48.456 ;
     RECT  155.477 46.128 156.701 46.152 ;
     RECT  154.397 5.184 156.773 5.208 ;
     RECT  156.277 2.16 156.845 2.328 ;
     RECT  155.845 42.624 156.881 43.272 ;
     RECT  155.189 49.488 157.057 49.512 ;
     RECT  156.881 42.624 157.097 42.648 ;
     RECT  157.057 49.488 157.141 49.56 ;
     RECT  155.693 50.688 157.141 50.712 ;
     RECT  157.141 49.44 157.196 49.56 ;
     RECT  157.141 50.688 157.237 50.808 ;
     RECT  157.237 50.688 157.349 51.336 ;
     RECT  157.349 50.736 157.741 51.336 ;
     RECT  155.293 3.84 157.777 3.864 ;
     RECT  157.777 3.84 157.817 4.008 ;
     RECT  157.196 49.392 157.861 49.56 ;
     RECT  156.913 2.784 157.909 2.808 ;
     RECT  157.861 48.96 157.993 49.56 ;
     RECT  157.741 50.736 158.053 51.384 ;
     RECT  157.993 48.912 158.065 49.56 ;
     RECT  157.705 41.616 158.209 41.64 ;
     RECT  157.849 42.912 158.252 42.936 ;
     RECT  157.381 44.448 158.252 44.472 ;
     RECT  157.817 3.984 158.281 4.008 ;
     RECT  158.065 48.672 158.293 49.56 ;
     RECT  157.273 53.04 158.293 53.064 ;
     RECT  158.053 50.736 158.389 51.432 ;
     RECT  158.293 53.04 158.435 53.16 ;
     RECT  158.209 41.376 158.497 41.64 ;
     RECT  158.389 50.736 158.821 51.816 ;
     RECT  158.293 48.48 158.869 49.56 ;
     RECT  158.821 50.592 158.869 52.008 ;
     RECT  157.085 1.728 159.008 1.752 ;
     RECT  157.909 2.784 159.008 2.904 ;
     RECT  158.281 3.984 159.008 4.728 ;
     RECT  157.633 6 159.008 6.024 ;
     RECT  158.497 41.232 159.008 41.64 ;
     RECT  158.252 42.912 159.008 44.472 ;
     RECT  157.957 47.28 159.008 47.304 ;
     RECT  158.869 48.48 159.008 52.008 ;
     RECT  159.008 1.728 159.011 52.008 ;
     RECT  159.011 1.728 159.112 51.852 ;
     RECT  159.112 1.728 159.304 51.582 ;
     RECT  159.304 41.376 159.365 41.4 ;
     RECT  159.304 1.728 159.473 2.808 ;
     RECT  159.301 52.992 159.491 53.016 ;
     RECT  159.473 2.256 159.545 2.808 ;
     RECT  159.304 42.624 159.587 42.744 ;
     RECT  159.545 2.784 159.653 2.808 ;
     RECT  159.304 48.48 160.049 51.336 ;
     RECT  159.304 44.304 160.121 44.328 ;
     RECT  160.049 48.48 160.121 49.512 ;
     RECT  160.121 48.48 160.409 49.416 ;
     RECT  160.409 49.008 160.499 49.416 ;
     RECT  160.049 51.312 160.553 51.336 ;
     RECT  159.587 42.72 160.597 42.744 ;
     RECT  160.837 42.768 160.949 42.792 ;
     RECT  160.499 49.008 161.273 49.032 ;
    LAYER M5 ;
     RECT  8.448 0.133 8.472 0.144 ;
     RECT  11.664 0.133 12.504 0.144 ;
     RECT  14.496 0.133 14.52 0.144 ;
     RECT  17.28 0.133 17.304 0.144 ;
     RECT  20.112 0.133 20.952 0.144 ;
     RECT  28.56 0.133 28.584 0.144 ;
     RECT  82.08 0.133 82.104 0.144 ;
     RECT  83.28 0.133 83.304 0.144 ;
     RECT  88.56 0.133 90.552 0.144 ;
     RECT  92.544 0.133 92.568 0.144 ;
     RECT  97.776 0.133 97.8 0.144 ;
     RECT  99.36 0.133 99.384 0.144 ;
     RECT  134.4 0.133 134.424 0.144 ;
     RECT  4.608 0.144 159.528 0.227 ;
     RECT  4.608 0.227 146.664 1.139 ;
     RECT  120.096 1.139 146.664 1.715 ;
     RECT  4.608 1.139 42.072 1.763 ;
     RECT  43.248 1.139 118.92 1.763 ;
     RECT  120.096 1.715 140.616 1.763 ;
     RECT  141.84 1.715 144.264 1.763 ;
     RECT  145.44 1.715 146.664 1.763 ;
     RECT  147.84 0.227 159.528 1.763 ;
     RECT  44.448 1.763 45.912 1.811 ;
     RECT  134.16 1.763 134.616 1.811 ;
     RECT  140.592 1.763 140.616 1.811 ;
     RECT  144.24 1.763 144.264 1.811 ;
     RECT  148.2 1.763 148.68 1.811 ;
     RECT  106.416 1.763 106.44 1.859 ;
     RECT  110.4 1.763 111.96 1.859 ;
     RECT  54.096 1.763 54.12 2.003 ;
     RECT  115.68 1.763 116.904 2.003 ;
     RECT  2.4 2.137 2.52 2.151 ;
     RECT  146.016 1.763 146.28 2.195 ;
     RECT  155.52 1.763 156.744 2.195 ;
     RECT  135.792 1.763 136.248 2.243 ;
     RECT  32.784 1.763 32.808 2.291 ;
     RECT  36.384 1.763 36.408 2.291 ;
     RECT  45.264 1.811 45.912 2.291 ;
     RECT  52.512 1.763 52.536 2.291 ;
     RECT  66.96 1.763 67.8 2.291 ;
     RECT  77.856 1.763 78.648 2.291 ;
     RECT  102 1.763 102.024 2.291 ;
     RECT  107.616 1.763 107.64 2.291 ;
     RECT  115.8 2.003 116.904 2.291 ;
     RECT  124.944 1.763 124.968 2.291 ;
     RECT  128.928 1.763 130.2 2.291 ;
     RECT  136.176 2.243 136.248 2.291 ;
     RECT  159 1.763 159.528 2.291 ;
     RECT  6.24 1.763 18.912 2.339 ;
     RECT  134.16 1.811 134.184 2.339 ;
     RECT  156.288 2.195 156.312 2.339 ;
     RECT  86.688 1.763 91.128 2.725 ;
     RECT  24 1.763 24.744 2.773 ;
     RECT  25.92 1.763 25.944 2.773 ;
     RECT  92.352 1.763 95.256 2.773 ;
     RECT  96.288 1.763 96.312 2.773 ;
     RECT  14.688 2.339 18.912 2.821 ;
     RECT  20.112 1.763 20.952 2.821 ;
     RECT  21.936 1.763 21.96 2.821 ;
     RECT  81.456 1.763 84.696 2.821 ;
     RECT  85.92 2.725 91.128 2.821 ;
     RECT  92.352 2.773 96.312 2.821 ;
     RECT  97.536 1.763 100.824 2.821 ;
     RECT  152.688 1.763 153.912 2.821 ;
     RECT  157.92 1.763 157.944 2.821 ;
     RECT  159 2.291 159.312 2.821 ;
     RECT  24 2.773 25.944 2.915 ;
     RECT  58.512 1.763 58.536 2.915 ;
     RECT  61.344 1.763 63.48 2.915 ;
     RECT  85.92 2.821 91.368 2.915 ;
     RECT  157.92 2.821 159.312 2.915 ;
     RECT  24 2.915 25.032 3.013 ;
     RECT  14.688 2.821 20.952 3.205 ;
     RECT  21.936 2.821 22.776 3.205 ;
     RECT  81.216 2.821 84.696 3.205 ;
     RECT  78 2.291 78.312 3.301 ;
     RECT  34.8 1.763 35.112 3.349 ;
     RECT  56.4 1.763 56.712 3.349 ;
     RECT  72.48 1.763 72.912 3.395 ;
     RECT  67.2 2.291 67.512 3.397 ;
     RECT  6.24 2.339 13.656 3.443 ;
     RECT  28.56 1.763 29.712 3.443 ;
     RECT  64.944 1.763 65.976 3.443 ;
     RECT  14.688 3.205 22.776 3.491 ;
     RECT  15.072 3.491 22.776 3.539 ;
     RECT  136.224 2.291 136.248 3.539 ;
     RECT  45.6 2.291 45.912 3.589 ;
     RECT  137.4 1.763 137.712 3.589 ;
     RECT  92.352 2.821 101.112 3.683 ;
     RECT  112.944 3.637 112.968 3.827 ;
     RECT  81.216 3.205 84.936 3.877 ;
     RECT  85.92 2.915 86.712 3.877 ;
     RECT  88.32 2.915 91.368 3.877 ;
     RECT  81.216 3.877 86.712 3.925 ;
     RECT  115.8 2.291 116.112 3.925 ;
     RECT  148.2 1.811 148.512 3.973 ;
     RECT  15.504 3.539 22.776 4.019 ;
     RECT  23.904 3.013 25.032 4.019 ;
     RECT  92.784 3.683 101.112 4.019 ;
     RECT  44.448 3.349 44.472 4.067 ;
     RECT  34.032 3.349 35.112 4.115 ;
     RECT  48.384 3.589 48.408 4.115 ;
     RECT  67.2 3.397 67.608 4.117 ;
     RECT  110.4 1.859 110.712 4.165 ;
     RECT  148.08 3.973 148.512 4.357 ;
     RECT  111.936 1.859 111.96 4.403 ;
     RECT  34.8 4.115 35.112 4.501 ;
     RECT  70.608 3.733 70.632 4.501 ;
     RECT  137.4 3.589 137.832 4.501 ;
     RECT  148.08 4.357 148.824 4.547 ;
     RECT  17.904 4.019 22.344 4.595 ;
     RECT  23.904 4.019 24.936 4.595 ;
     RECT  119.712 3.397 119.736 4.595 ;
     RECT  152.688 2.821 154.2 4.595 ;
     RECT  148.2 4.547 148.824 4.643 ;
     RECT  15.504 4.019 16.872 4.691 ;
     RECT  67.2 4.117 67.8 4.691 ;
     RECT  80.352 3.925 87.192 4.691 ;
     RECT  92.784 4.019 97.08 4.691 ;
     RECT  98.304 4.019 101.112 4.691 ;
     RECT  42.72 4.549 42.744 4.693 ;
     RECT  6.672 3.443 10.488 4.739 ;
     RECT  61.44 2.915 63.48 4.739 ;
     RECT  95.568 4.691 97.08 4.739 ;
     RECT  98.304 4.691 99.912 4.787 ;
     RECT  101.088 4.691 101.112 4.787 ;
     RECT  114.576 4.357 114.6 4.883 ;
     RECT  6.672 4.739 8.904 4.931 ;
     RECT  42.624 4.693 42.744 4.931 ;
     RECT  136.752 4.501 137.832 4.931 ;
     RECT  45.6 3.589 46.776 4.979 ;
     RECT  67.2 4.691 67.608 4.979 ;
     RECT  110.256 4.165 110.712 4.981 ;
     RECT  80.928 4.691 87.192 5.029 ;
     RECT  88.176 3.877 91.368 5.029 ;
     RECT  34.8 4.501 35.208 5.075 ;
     RECT  72.6 3.395 72.912 5.077 ;
     RECT  6.768 4.931 8.904 5.171 ;
     RECT  10.224 4.739 10.488 5.171 ;
     RECT  42.72 4.931 42.744 5.171 ;
     RECT  53.28 4.645 53.304 5.171 ;
     RECT  61.488 4.739 63.48 5.171 ;
     RECT  65.424 3.443 65.976 5.171 ;
     RECT  80.928 5.029 91.368 5.171 ;
     RECT  92.784 4.691 94.512 5.171 ;
     RECT  97.056 4.739 97.08 5.171 ;
     RECT  98.304 4.787 98.328 5.171 ;
     RECT  142.8 1.763 143.112 5.173 ;
     RECT  99.456 4.787 99.912 5.219 ;
     RECT  118.56 4.117 118.584 5.219 ;
     RECT  20.928 4.595 22.344 5.267 ;
     RECT  137.4 4.931 137.832 5.267 ;
     RECT  115.68 3.925 116.112 5.269 ;
     RECT  11.856 3.443 13.512 5.315 ;
     RECT  61.632 5.171 62.328 5.315 ;
     RECT  92.784 5.171 92.904 5.317 ;
     RECT  29.04 3.443 29.712 5.363 ;
     RECT  16.416 4.691 16.872 5.365 ;
     RECT  17.904 4.595 19.944 5.365 ;
     RECT  67.2 4.979 67.512 5.365 ;
     RECT  146.016 2.195 146.04 5.459 ;
     RECT  107.136 4.645 107.16 5.509 ;
     RECT  23.904 4.595 24.888 5.605 ;
     RECT  153.216 4.595 154.2 5.747 ;
     RECT  82.512 5.171 90.504 5.795 ;
     RECT  12.288 5.315 13.512 5.893 ;
     RECT  16.416 5.365 19.944 5.893 ;
     RECT  20.928 5.267 21 5.893 ;
     RECT  23.184 5.605 24.888 5.893 ;
     RECT  75.216 4.501 75.24 6.083 ;
     RECT  133.968 5.029 133.992 6.083 ;
     RECT  80.928 5.171 80.952 6.229 ;
     RECT  80.928 6.229 81.192 6.275 ;
     RECT  146.784 5.605 146.808 6.275 ;
     RECT  142.704 5.173 143.112 6.419 ;
     RECT  82.512 5.795 86.376 6.805 ;
     RECT  87.456 5.795 90.504 6.805 ;
     RECT  82.512 6.805 90.504 7.619 ;
     RECT  82.512 7.619 86.904 9.155 ;
     RECT  81.168 6.275 81.192 11.459 ;
     RECT  82.512 9.155 85.848 11.507 ;
     RECT  82.512 11.507 84.168 12.901 ;
     RECT  51 1.763 51.312 15.973 ;
     RECT  107.136 5.509 107.688 16.307 ;
     RECT  114.576 16.501 114.6 16.789 ;
     RECT  115.584 5.269 116.112 16.789 ;
     RECT  114.576 16.789 116.112 16.835 ;
     RECT  51 15.973 51.432 19.381 ;
     RECT  0.24 15.685 0.264 27.155 ;
     RECT  82.512 12.901 84.36 30.851 ;
     RECT  2.4 2.151 2.712 38.149 ;
     RECT  88.272 7.619 90.504 38.197 ;
     RECT  91.68 5.317 92.904 38.197 ;
     RECT  97.392 5.221 98.04 39.301 ;
     RECT  99.6 5.219 99.912 39.301 ;
     RECT  103.296 39.733 103.32 40.595 ;
     RECT  66.288 5.365 67.512 40.981 ;
     RECT  69.408 4.501 69.432 40.981 ;
     RECT  88.272 38.197 92.904 40.981 ;
     RECT  105 1.763 105.312 40.981 ;
     RECT  64.992 5.365 65.016 41.075 ;
     RECT  56.4 3.349 57.24 41.125 ;
     RECT  66.048 40.981 67.512 41.171 ;
     RECT  158.688 2.915 159.312 41.267 ;
     RECT  110.256 4.981 111.24 41.269 ;
     RECT  107.664 16.307 107.688 41.413 ;
     RECT  109.008 40.741 109.032 41.413 ;
     RECT  69.408 40.981 69.528 41.461 ;
     RECT  78 3.301 79.08 41.461 ;
     RECT  61.68 5.315 62.328 41.749 ;
     RECT  114.912 16.835 116.112 41.749 ;
     RECT  72.6 5.077 73.896 41.989 ;
     RECT  110.256 41.269 111.288 42.085 ;
     RECT  51 19.381 51.72 42.133 ;
     RECT  63.936 5.365 63.96 42.133 ;
     RECT  70.608 4.501 71.304 42.133 ;
     RECT  95.568 4.739 95.592 42.181 ;
     RECT  77.52 41.461 79.08 42.227 ;
     RECT  95.568 42.181 96.36 42.227 ;
     RECT  97.392 39.301 99.912 42.227 ;
     RECT  103.2 41.557 103.224 42.227 ;
     RECT  107.664 41.413 109.032 42.419 ;
     RECT  50.688 42.133 51.72 42.421 ;
     RECT  152.16 41.605 152.184 42.467 ;
     RECT  94.08 5.171 94.512 42.469 ;
     RECT  59.04 42.181 59.064 42.613 ;
     RECT  60.288 42.565 60.312 42.613 ;
     RECT  66.048 41.171 66.072 42.613 ;
     RECT  67.2 41.171 67.512 42.613 ;
     RECT  159 41.267 159.312 42.613 ;
     RECT  59.04 42.613 60.312 42.709 ;
     RECT  70.608 42.133 71.592 42.709 ;
     RECT  72.6 41.989 74.088 42.709 ;
     RECT  159 42.613 159.576 42.709 ;
     RECT  63.936 42.133 64.44 42.803 ;
     RECT  88.272 40.981 92.952 42.803 ;
     RECT  94.08 42.469 94.632 42.803 ;
     RECT  114.912 41.749 116.232 42.803 ;
     RECT  50.688 42.421 52.008 42.995 ;
     RECT  128.304 5.173 128.328 43.043 ;
     RECT  105 40.981 106.248 43.045 ;
     RECT  56.4 41.125 57.336 43.141 ;
     RECT  58.56 42.709 60.312 43.141 ;
     RECT  70.608 42.709 74.088 43.141 ;
     RECT  64.416 42.803 64.44 43.237 ;
     RECT  80.592 42.133 80.616 43.237 ;
     RECT  113.28 16.261 113.304 43.237 ;
     RECT  114.912 42.803 116.112 43.237 ;
     RECT  38.112 4.789 38.136 43.283 ;
     RECT  70.608 43.141 74.664 43.285 ;
     RECT  80.496 43.237 80.616 43.285 ;
     RECT  109.008 42.419 109.032 43.285 ;
     RECT  110.256 42.085 112.152 43.285 ;
     RECT  153.216 5.747 153.912 43.285 ;
     RECT  61.68 41.749 62.76 43.381 ;
     RECT  98.016 42.227 99.912 43.573 ;
     RECT  101.136 40.405 101.16 43.573 ;
     RECT  105 43.045 106.344 43.621 ;
     RECT  107.664 42.419 107.688 43.621 ;
     RECT  70.608 43.285 75.384 43.669 ;
     RECT  109.008 43.285 112.152 43.669 ;
     RECT  45.6 4.979 45.912 43.717 ;
     RECT  56.16 43.141 60.312 43.717 ;
     RECT  61.68 43.381 63.048 43.717 ;
     RECT  94.08 42.803 94.512 43.813 ;
     RECT  96.336 42.227 96.36 43.813 ;
     RECT  108.768 43.669 112.152 43.813 ;
     RECT  113.28 43.237 116.112 43.813 ;
     RECT  42.72 43.813 42.744 43.861 ;
     RECT  77.568 42.227 79.08 43.861 ;
     RECT  159 42.709 160.584 43.861 ;
     RECT  55.152 42.133 55.176 43.909 ;
     RECT  56.16 43.717 63.048 43.909 ;
     RECT  88.272 42.803 91.128 43.955 ;
     RECT  98.016 43.573 101.16 43.955 ;
     RECT  102.624 43.285 103.224 43.955 ;
     RECT  105 43.621 107.688 43.955 ;
     RECT  70.608 43.669 75.816 44.003 ;
     RECT  75.12 44.003 75.816 44.053 ;
     RECT  76.8 43.861 79.08 44.053 ;
     RECT  103.152 43.955 103.224 44.053 ;
     RECT  105 43.955 106.92 44.053 ;
     RECT  118.08 43.141 118.104 44.101 ;
     RECT  96.336 43.813 96.888 44.195 ;
     RECT  82.512 30.851 83.88 44.197 ;
     RECT  75.12 44.053 79.08 44.245 ;
     RECT  80.352 43.285 80.616 44.245 ;
     RECT  48.72 43.861 48.744 44.293 ;
     RECT  158.304 43.861 160.584 44.339 ;
     RECT  29.28 5.363 29.712 44.341 ;
     RECT  53.568 42.517 53.592 44.341 ;
     RECT  55.152 43.909 63.048 44.341 ;
     RECT  141.456 43.861 141.48 44.341 ;
     RECT  70.608 44.003 73.992 44.387 ;
     RECT  148.2 4.643 148.512 44.389 ;
     RECT  7.584 5.171 8.904 44.437 ;
     RECT  15.312 5.365 15.336 44.437 ;
     RECT  82.512 44.197 84.12 44.437 ;
     RECT  12.288 5.893 13.704 44.483 ;
     RECT  42.72 43.861 43.032 44.483 ;
     RECT  53.568 44.341 63.048 44.483 ;
     RECT  75.12 44.245 80.616 44.483 ;
     RECT  152.496 43.285 153.912 44.483 ;
     RECT  53.568 44.483 62.616 44.579 ;
     RECT  54.288 44.579 62.616 44.627 ;
     RECT  94.08 43.813 94.92 44.627 ;
     RECT  94.08 44.627 94.512 44.675 ;
     RECT  48.72 44.293 49.128 44.725 ;
     RECT  119.568 44.437 119.592 44.725 ;
     RECT  121.2 1.763 121.512 44.725 ;
     RECT  48.624 44.725 49.128 44.821 ;
     RECT  48.624 44.821 49.32 44.867 ;
     RECT  108.768 43.813 116.112 44.867 ;
     RECT  153.216 44.483 153.912 44.867 ;
     RECT  32.112 43.765 32.136 44.915 ;
     RECT  92.112 42.803 92.952 44.917 ;
     RECT  2.4 38.149 3.672 44.963 ;
     RECT  44.592 4.645 44.616 44.965 ;
     RECT  45.6 43.717 46.2 44.965 ;
     RECT  47.184 43.573 47.208 44.965 ;
     RECT  64.416 43.237 64.92 44.965 ;
     RECT  66.048 42.613 67.512 44.965 ;
     RECT  69.072 41.461 69.528 44.965 ;
     RECT  70.608 44.387 72.912 44.965 ;
     RECT  73.968 44.387 73.992 44.965 ;
     RECT  73.968 44.965 74.136 45.013 ;
     RECT  75.12 44.483 80.52 45.013 ;
     RECT  7.584 44.437 9.48 45.059 ;
     RECT  92.112 44.917 93.144 45.059 ;
     RECT  140.496 44.341 141.48 45.059 ;
     RECT  82.32 44.437 84.12 45.107 ;
     RECT  150.432 44.005 150.456 45.155 ;
     RECT  44.064 44.965 44.616 45.157 ;
     RECT  45.6 44.965 47.208 45.157 ;
     RECT  103.152 44.053 106.92 45.253 ;
     RECT  44.064 45.157 47.208 45.299 ;
     RECT  82.752 45.107 84.12 45.301 ;
     RECT  85.392 11.507 85.848 45.301 ;
     RECT  103.152 45.253 107.64 45.301 ;
     RECT  113.28 44.867 116.112 45.301 ;
     RECT  29.28 44.341 30.504 45.491 ;
     RECT  43.008 44.483 43.032 45.493 ;
     RECT  44.064 45.299 44.616 45.493 ;
     RECT  102.336 45.301 107.64 45.493 ;
     RECT  61.2 44.627 62.616 45.541 ;
     RECT  64.416 44.965 67.512 45.541 ;
     RECT  10.992 5.365 11.016 45.635 ;
     RECT  49.008 44.867 49.32 45.635 ;
     RECT  102.336 45.493 107.688 45.635 ;
     RECT  61.2 45.541 67.512 45.683 ;
     RECT  119.568 44.725 121.512 45.731 ;
     RECT  16.416 5.893 21 45.779 ;
     RECT  54.288 44.627 59.928 45.827 ;
     RECT  49.296 45.635 49.32 45.877 ;
     RECT  7.8 45.059 9.48 45.923 ;
     RECT  88.272 43.955 89.112 45.923 ;
     RECT  69.072 44.965 72.912 45.973 ;
     RECT  73.968 45.013 80.52 45.973 ;
     RECT  96.864 44.195 96.888 45.973 ;
     RECT  98.064 43.955 101.16 45.973 ;
     RECT  113.28 45.301 116.232 46.021 ;
     RECT  12.288 44.483 13.512 46.069 ;
     RECT  14.736 44.437 15.336 46.069 ;
     RECT  45.6 45.299 47.208 46.069 ;
     RECT  132 1.763 132.312 46.069 ;
     RECT  92.928 45.059 93.144 46.117 ;
     RECT  94.2 44.675 94.512 46.117 ;
     RECT  27.264 45.541 27.288 46.165 ;
     RECT  40.2 1.763 40.512 46.165 ;
     RECT  153.6 44.867 153.912 46.165 ;
     RECT  12.288 46.069 15.336 46.211 ;
     RECT  29.28 45.491 29.928 46.211 ;
     RECT  82.752 45.301 85.848 46.211 ;
     RECT  129.648 44.869 129.672 46.213 ;
     RECT  61.2 45.683 63.864 46.259 ;
     RECT  129.408 46.213 129.672 46.259 ;
     RECT  27.264 46.165 27.768 46.261 ;
     RECT  43.008 45.493 44.616 46.357 ;
     RECT  149.952 45.589 149.976 46.357 ;
     RECT  64.896 45.683 67.512 46.405 ;
     RECT  86.88 9.155 86.904 46.405 ;
     RECT  145.056 45.685 145.08 46.499 ;
     RECT  64.896 46.405 68.04 46.501 ;
     RECT  69.072 45.973 80.52 46.501 ;
     RECT  108.768 44.867 112.152 46.547 ;
     RECT  34.8 5.075 35.112 46.645 ;
     RECT  51 42.995 52.008 46.645 ;
     RECT  96.864 45.973 101.16 46.645 ;
     RECT  102.336 45.635 103.8 46.645 ;
     RECT  104.832 45.635 107.688 46.645 ;
     RECT  54.288 45.827 55.08 46.693 ;
     RECT  95.808 45.877 95.832 46.693 ;
     RECT  96.864 46.645 107.688 46.693 ;
     RECT  137.4 5.267 137.712 46.693 ;
     RECT  95.808 46.693 107.688 46.739 ;
     RECT  108.96 46.547 112.152 46.741 ;
     RECT  148.2 44.389 148.776 46.741 ;
     RECT  34.032 46.645 35.112 46.787 ;
     RECT  117.312 44.101 118.104 46.787 ;
     RECT  119.616 45.731 121.512 46.787 ;
     RECT  125.376 46.117 125.4 46.787 ;
     RECT  149.952 46.357 150.504 46.787 ;
     RECT  152.784 46.165 153.912 46.787 ;
     RECT  45.6 46.069 47.784 46.789 ;
     RECT  137.4 46.693 137.928 46.835 ;
     RECT  23.184 5.893 25.32 46.883 ;
     RECT  56.112 45.827 59.928 46.885 ;
     RECT  61.2 46.259 63.816 46.885 ;
     RECT  88.704 45.923 89.112 46.981 ;
     RECT  90.24 43.955 91.128 46.981 ;
     RECT  131.52 46.069 132.984 47.027 ;
     RECT  141.456 45.059 141.48 47.029 ;
     RECT  142.8 6.419 143.112 47.029 ;
     RECT  126.6 1.763 126.912 47.125 ;
     RECT  53.472 46.693 55.08 47.173 ;
     RECT  96.192 46.739 107.688 47.219 ;
     RECT  13.2 46.211 15.336 47.221 ;
     RECT  22.032 5.267 22.104 47.221 ;
     RECT  23.184 46.883 24.888 47.221 ;
     RECT  40.2 46.165 40.824 47.221 ;
     RECT  42.72 46.357 44.616 47.221 ;
     RECT  45.6 46.789 48.168 47.221 ;
     RECT  82.752 46.211 83.712 47.221 ;
     RECT  84.72 46.211 85.848 47.221 ;
     RECT  92.928 46.117 94.512 47.221 ;
     RECT  155.856 42.613 155.88 47.221 ;
     RECT  82.752 47.221 85.848 47.267 ;
     RECT  49.296 45.877 49.752 47.269 ;
     RECT  50.832 46.645 52.008 47.269 ;
     RECT  88.704 46.981 91.128 47.269 ;
     RECT  97.296 47.219 107.688 47.269 ;
     RECT  126.6 47.125 127.704 47.269 ;
     RECT  158.304 44.339 159.576 47.269 ;
     RECT  12.768 47.221 15.336 47.315 ;
     RECT  120.144 46.787 121.512 47.315 ;
     RECT  126.6 47.269 127.944 47.315 ;
     RECT  42.72 47.221 48.168 47.317 ;
     RECT  53.04 47.173 55.08 47.317 ;
     RECT  56.112 46.885 63.816 47.317 ;
     RECT  113.28 46.021 116.28 47.317 ;
     RECT  14.736 47.315 15.336 47.363 ;
     RECT  97.296 47.269 107.784 47.363 ;
     RECT  155.328 47.221 155.88 47.363 ;
     RECT  16.416 45.779 18.912 47.411 ;
     RECT  147.648 46.741 148.776 47.411 ;
     RECT  64.896 46.501 80.52 47.459 ;
     RECT  148.2 47.411 148.776 47.459 ;
     RECT  36.48 46.069 36.504 47.555 ;
     RECT  150.48 46.787 150.504 47.555 ;
     RECT  6.576 45.973 6.6 47.603 ;
     RECT  16.848 47.411 18.912 47.605 ;
     RECT  126.6 47.315 126.912 47.605 ;
     RECT  137.4 46.835 137.712 47.605 ;
     RECT  131.52 47.027 132.312 47.651 ;
     RECT  16.848 47.605 19.032 47.701 ;
     RECT  14.736 47.363 14.76 47.747 ;
     RECT  34.128 46.787 35.112 47.749 ;
     RECT  125.952 47.605 126.912 47.749 ;
     RECT  42.72 47.317 48.264 47.797 ;
     RECT  49.296 47.269 52.008 47.797 ;
     RECT  125.28 47.749 126.912 47.797 ;
     RECT  22.032 47.221 24.888 47.843 ;
     RECT  141.456 47.029 143.112 47.843 ;
     RECT  20.544 45.779 21 47.845 ;
     RECT  22.032 47.843 22.824 47.845 ;
     RECT  37.632 45.205 37.656 47.845 ;
     RECT  42.72 47.797 52.008 47.845 ;
     RECT  82.752 47.267 84.408 47.845 ;
     RECT  92.736 47.221 94.512 47.845 ;
     RECT  108.96 46.741 112.248 47.845 ;
     RECT  113.28 47.317 116.52 47.845 ;
     RECT  117.936 46.787 118.104 47.845 ;
     RECT  141.456 47.843 141.48 47.891 ;
     RECT  53.04 47.317 63.816 47.893 ;
     RECT  64.896 47.459 69.096 47.893 ;
     RECT  117.936 47.845 118.728 47.893 ;
     RECT  7.8 45.923 8.904 47.939 ;
     RECT  16.848 47.701 19.08 47.939 ;
     RECT  129.408 46.259 129.432 47.939 ;
     RECT  16.848 47.939 16.872 47.987 ;
     RECT  23.856 47.843 24.888 48.035 ;
     RECT  27.264 46.261 28.008 48.083 ;
     RECT  27.936 48.083 28.008 48.085 ;
     RECT  29.4 46.211 29.928 48.085 ;
     RECT  123.12 47.269 123.144 48.131 ;
     RECT  103.104 47.363 107.784 48.373 ;
     RECT  108.96 47.845 116.52 48.373 ;
     RECT  20.544 47.845 22.824 48.419 ;
     RECT  27.936 48.085 29.928 48.419 ;
     RECT  86.88 46.405 87.432 48.419 ;
     RECT  88.512 47.269 91.128 48.421 ;
     RECT  92.736 47.845 94.728 48.421 ;
     RECT  153.6 46.787 153.912 48.421 ;
     RECT  155.328 47.363 155.64 48.421 ;
     RECT  17.904 47.939 19.08 48.467 ;
     RECT  28.56 48.419 29.928 48.467 ;
     RECT  96.192 47.219 96.216 48.467 ;
     RECT  103.104 48.373 116.52 48.467 ;
     RECT  7.8 47.939 8.232 48.515 ;
     RECT  12.768 47.315 13.608 48.515 ;
     RECT  42.384 47.845 52.008 48.515 ;
     RECT  85.392 47.267 85.848 48.515 ;
     RECT  158.016 47.269 159.576 48.515 ;
     RECT  103.104 48.467 112.248 48.613 ;
     RECT  40.2 47.221 41.304 48.659 ;
     RECT  117.936 47.893 119.496 48.659 ;
     RECT  145.152 47.557 145.176 48.659 ;
     RECT  120.528 47.315 121.512 48.661 ;
     RECT  97.296 47.363 101.688 48.755 ;
     RECT  87.888 48.421 91.128 48.805 ;
     RECT  97.296 48.755 101.592 48.805 ;
     RECT  48.768 48.515 52.008 48.851 ;
     RECT  33.168 47.749 35.112 48.899 ;
     RECT  113.904 48.467 116.52 48.901 ;
     RECT  127.92 47.315 127.944 48.901 ;
     RECT  132 47.651 132.312 48.901 ;
     RECT  42.384 48.515 47.352 48.947 ;
     RECT  96.432 48.805 101.592 48.947 ;
     RECT  146.928 47.845 146.952 48.947 ;
     RECT  158.016 48.515 159.48 48.949 ;
     RECT  23.856 48.035 24.504 48.995 ;
     RECT  50.832 48.851 52.008 48.997 ;
     RECT  53.04 47.893 69.096 48.997 ;
     RECT  70.224 47.459 80.52 48.997 ;
     RECT  87.888 48.805 91.464 48.997 ;
     RECT  92.736 48.421 94.92 48.997 ;
     RECT  127.92 48.901 128.808 48.997 ;
     RECT  133.68 48.901 133.704 48.997 ;
     RECT  33.168 48.899 33.72 49.043 ;
     RECT  160.56 44.339 160.584 49.043 ;
     RECT  28.992 48.467 29.712 49.091 ;
     RECT  31.872 47.173 31.896 49.091 ;
     RECT  42.384 48.947 47.208 49.091 ;
     RECT  13.2 48.515 13.608 49.139 ;
     RECT  23.856 48.995 24.312 49.189 ;
     RECT  18.48 48.467 19.08 49.283 ;
     RECT  70.224 48.997 80.616 49.331 ;
     RECT  103.008 48.613 112.248 49.331 ;
     RECT  127.92 48.997 129.048 49.333 ;
     RECT  131.328 48.901 132.312 49.333 ;
     RECT  153.6 48.421 155.64 49.333 ;
     RECT  131.04 49.333 132.312 49.381 ;
     RECT  157.872 48.949 159.48 49.381 ;
     RECT  86.88 48.419 86.904 49.429 ;
     RECT  87.888 48.997 94.92 49.429 ;
     RECT  157.248 49.381 159.48 49.429 ;
     RECT  11.136 48.421 11.16 49.475 ;
     RECT  124.8 47.797 126.912 49.477 ;
     RECT  142.8 47.843 143.112 49.477 ;
     RECT  149.952 47.845 149.976 49.477 ;
     RECT  48.768 48.851 49.752 49.525 ;
     RECT  50.832 48.997 69.096 49.525 ;
     RECT  70.224 49.331 80.52 49.525 ;
     RECT  113.904 48.901 116.76 49.525 ;
     RECT  138.912 49.477 139.656 49.525 ;
     RECT  29.04 49.091 29.712 49.571 ;
     RECT  20.928 48.419 22.824 49.619 ;
     RECT  36.96 47.845 37.656 49.619 ;
     RECT  50.832 49.525 80.52 49.619 ;
     RECT  85.68 48.515 85.848 49.619 ;
     RECT  148.2 47.459 148.632 49.619 ;
     RECT  27.312 49.045 27.336 49.667 ;
     RECT  50.832 49.619 57.336 49.667 ;
     RECT  103.104 49.331 112.248 49.667 ;
     RECT  42.384 49.091 46.968 49.715 ;
     RECT  127.92 49.333 129.384 49.715 ;
     RECT  33.696 49.043 33.72 49.763 ;
     RECT  149.76 49.477 149.976 49.763 ;
     RECT  96.624 48.947 101.592 49.859 ;
     RECT  133.584 48.997 133.704 49.861 ;
     RECT  135.072 48.901 135.096 49.861 ;
     RECT  22.032 49.619 22.056 49.907 ;
     RECT  50.832 49.667 53.064 49.909 ;
     RECT  66.24 49.619 80.52 50.003 ;
     RECT  113.904 49.525 116.904 50.005 ;
     RECT  118.08 48.659 118.728 50.005 ;
     RECT  18.6 49.283 19.08 50.051 ;
     RECT  128.784 49.715 129.384 50.053 ;
     RECT  130.512 49.381 132.312 50.053 ;
     RECT  20.928 49.619 20.952 50.099 ;
     RECT  13.2 49.139 13.512 50.101 ;
     RECT  36.96 49.619 36.984 50.101 ;
     RECT  82.512 47.845 84.408 50.101 ;
     RECT  124.32 49.477 126.912 50.101 ;
     RECT  133.584 49.861 135.096 50.101 ;
     RECT  153.072 49.333 155.64 50.101 ;
     RECT  25.824 49.045 25.848 50.195 ;
     RECT  43.008 49.715 46.968 50.195 ;
     RECT  66.24 50.003 75.48 50.195 ;
     RECT  76.8 50.003 80.52 50.195 ;
     RECT  86.88 49.429 94.92 50.195 ;
     RECT  96.624 49.859 101.112 50.195 ;
     RECT  128.784 50.053 132.312 50.195 ;
     RECT  133.344 50.101 135.096 50.195 ;
     RECT  136.608 47.605 137.712 50.243 ;
     RECT  120.24 48.661 121.512 50.245 ;
     RECT  69.936 50.195 70.92 50.291 ;
     RECT  133.344 50.195 134.52 50.291 ;
     RECT  14.832 50.149 14.856 50.387 ;
     RECT  113.904 50.005 118.728 50.435 ;
     RECT  114.48 50.435 118.728 50.629 ;
     RECT  71.904 50.195 75.48 50.675 ;
     RECT  7.8 48.515 8.112 50.677 ;
     RECT  48.432 49.525 49.752 50.677 ;
     RECT  50.784 49.909 53.064 50.677 ;
     RECT  81.744 50.101 84.408 50.677 ;
     RECT  54.192 49.667 57.336 50.725 ;
     RECT  58.464 49.619 65.256 50.725 ;
     RECT  15.936 50.149 15.96 50.771 ;
     RECT  48.432 50.677 53.064 50.771 ;
     RECT  76.8 50.195 78.696 50.771 ;
     RECT  77.232 50.771 78.696 50.819 ;
     RECT  157.152 49.429 159.48 50.819 ;
     RECT  18.6 50.051 18.912 50.869 ;
     RECT  103.104 49.667 106.92 50.917 ;
     RECT  128.784 50.195 129.96 50.965 ;
     RECT  50.592 50.771 53.064 51.253 ;
     RECT  54.192 50.725 65.256 51.253 ;
     RECT  6.864 50.677 8.112 51.301 ;
     RECT  12.432 50.101 13.512 51.301 ;
     RECT  18.432 50.869 18.912 51.301 ;
     RECT  34.8 48.899 35.112 51.301 ;
     RECT  36.192 50.101 36.984 51.301 ;
     RECT  50.592 51.253 65.256 51.301 ;
     RECT  66.24 50.195 68.52 51.301 ;
     RECT  69.936 50.291 70.248 51.301 ;
     RECT  71.904 50.675 75.432 51.301 ;
     RECT  85.68 49.619 85.704 51.301 ;
     RECT  86.928 50.195 94.728 51.301 ;
     RECT  96.624 50.195 100.728 51.301 ;
     RECT  102.672 50.917 106.92 51.301 ;
     RECT  108.096 49.667 112.2 51.301 ;
     RECT  113.28 50.437 113.304 51.301 ;
     RECT  114.48 50.629 119.064 51.301 ;
     RECT  120.24 50.245 122.28 51.301 ;
     RECT  124.08 50.101 126.912 51.301 ;
     RECT  133.344 50.291 133.368 51.301 ;
     RECT  134.352 50.291 134.52 51.301 ;
     RECT  137.4 50.243 137.712 51.301 ;
     RECT  138.72 49.525 139.656 51.301 ;
     RECT  140.736 49.765 140.76 51.301 ;
     RECT  142.8 49.477 143.736 51.301 ;
     RECT  148.2 49.619 148.512 51.301 ;
     RECT  149.76 49.763 149.784 51.301 ;
     RECT  157.248 50.819 159.48 51.301 ;
     RECT  160.464 49.381 160.488 51.301 ;
     RECT  6.864 51.301 9.384 51.347 ;
     RECT  36.192 51.301 38.76 51.347 ;
     RECT  114.48 51.301 122.28 51.347 ;
     RECT  131.04 50.195 132.312 51.347 ;
     RECT  137.4 51.301 140.76 51.347 ;
     RECT  151.008 49.525 151.032 51.347 ;
     RECT  152.736 50.101 155.64 51.347 ;
     RECT  157.248 51.301 160.488 51.347 ;
     RECT  128.736 50.965 129.96 51.349 ;
     RECT  133.344 51.301 134.808 51.349 ;
     RECT  128.736 51.349 130.536 51.493 ;
     RECT  148.2 51.301 149.784 51.493 ;
     RECT  17.232 49.381 17.256 51.541 ;
     RECT  18.432 51.301 19.704 51.541 ;
     RECT  23.808 49.189 24.312 51.541 ;
     RECT  27.84 51.301 27.864 51.541 ;
     RECT  29.4 49.571 29.712 51.541 ;
     RECT  42.096 51.301 42.12 51.541 ;
     RECT  43.2 50.195 46.968 51.541 ;
     RECT  80.256 50.195 80.28 51.541 ;
     RECT  108.096 51.301 113.304 51.589 ;
     RECT  114.48 51.347 121.512 51.589 ;
     RECT  17.232 51.541 19.704 51.781 ;
     RECT  23.328 51.541 24.312 51.781 ;
     RECT  50.592 51.301 70.296 51.781 ;
     RECT  71.472 51.301 75.432 51.781 ;
     RECT  77.232 50.819 78.456 51.781 ;
     RECT  80.256 51.541 80.568 51.781 ;
     RECT  81.744 50.677 84.504 51.781 ;
     RECT  85.68 51.301 94.824 51.781 ;
     RECT  123.84 51.301 126.912 51.781 ;
     RECT  132 51.347 132.312 51.781 ;
     RECT  133.344 51.349 135.096 51.781 ;
     RECT  142.8 51.301 144.792 51.781 ;
     RECT  148.08 51.493 149.784 51.781 ;
     RECT  152.736 51.347 154.776 51.781 ;
     RECT  22.704 51.781 24.312 51.829 ;
     RECT  27.84 51.541 29.712 51.829 ;
     RECT  42.096 51.541 46.968 51.829 ;
     RECT  48.432 50.771 49.368 51.829 ;
     RECT  50.592 51.781 75.432 51.829 ;
     RECT  76.608 51.781 78.456 51.829 ;
     RECT  80.256 51.781 94.824 51.829 ;
     RECT  96.288 51.301 100.872 51.829 ;
     RECT  102.336 51.301 106.92 51.829 ;
     RECT  2.4 44.963 2.712 51.849 ;
     RECT  108.096 51.589 121.512 51.849 ;
     RECT  123.552 51.781 126.912 51.849 ;
     RECT  132 51.781 135.384 51.849 ;
     RECT  2.4 51.849 2.52 51.863 ;
     RECT  108.096 51.849 121.32 51.863 ;
     RECT  123.552 51.849 126.72 51.863 ;
     RECT  132 51.849 132.12 51.863 ;
     RECT  137.4 51.347 140.232 51.863 ;
     RECT  142.8 51.781 145.08 51.863 ;
     RECT  12.096 51.301 14.232 51.877 ;
     RECT  26.64 51.829 29.712 51.877 ;
     RECT  30.768 49.861 30.792 51.877 ;
     RECT  31.776 51.301 35.112 51.877 ;
     RECT  36.336 51.347 38.76 51.877 ;
     RECT  40.2 48.659 40.512 51.877 ;
     RECT  42.096 51.829 49.368 51.877 ;
     RECT  4.512 51.781 4.536 52.453 ;
     RECT  7.248 51.347 9.384 52.453 ;
     RECT  10.896 51.877 14.568 52.453 ;
     RECT  16.944 51.781 19.704 52.453 ;
     RECT  26.64 51.877 35.112 52.453 ;
     RECT  36.336 51.877 40.512 52.453 ;
     RECT  41.808 51.877 49.368 52.453 ;
     RECT  50.592 51.829 106.92 52.453 ;
     RECT  25.728 52.453 106.92 52.885 ;
     RECT  108.096 51.863 120.84 52.885 ;
     RECT  4.512 52.453 21.528 52.981 ;
     RECT  22.704 51.829 24.552 52.981 ;
     RECT  25.728 52.885 120.84 52.981 ;
     RECT  128.688 51.493 130.536 53.029 ;
     RECT  138.384 51.863 140.232 53.029 ;
     RECT  148.08 51.781 149.928 53.029 ;
     RECT  157.776 51.347 159.624 53.029 ;
     RECT  123.552 51.863 125.88 53.075 ;
     RECT  4.512 52.981 120.84 53.84 ;
     RECT  123.552 53.075 125.688 53.84 ;
     RECT  128.4 53.029 130.536 53.84 ;
     RECT  133.248 51.849 135.384 53.84 ;
     RECT  138.096 53.029 140.232 53.84 ;
     RECT  142.944 51.863 145.08 53.84 ;
     RECT  147.792 53.029 149.928 53.84 ;
     RECT  152.64 51.781 154.776 53.84 ;
     RECT  157.488 53.029 159.624 53.84 ;
  END
END ot_s81_engram_mixq_shcol_b
END LIBRARY
